VERSION 5.8 ;
BUSBITCHARS "[]" ;
DIVIDERCHAR "/" ;
UNITS
    DATABASE MICRONS 1000 ;
END UNITS

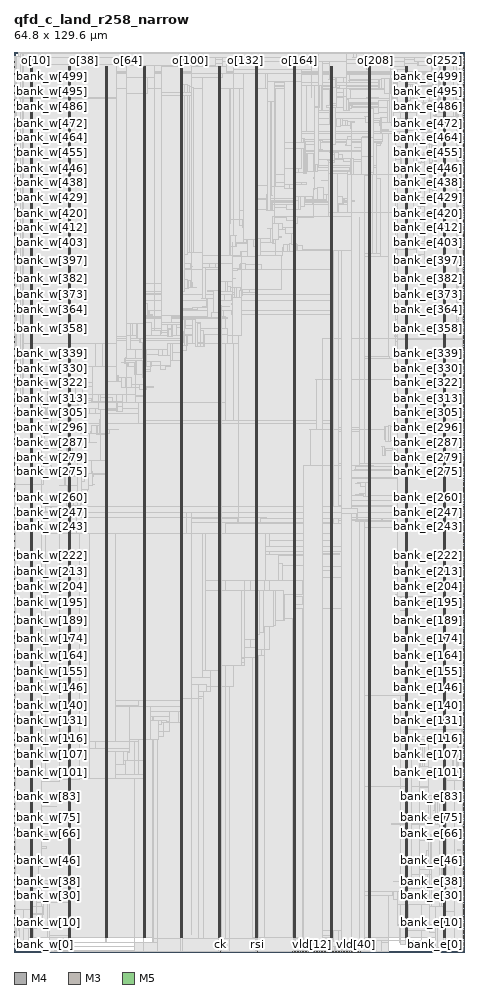
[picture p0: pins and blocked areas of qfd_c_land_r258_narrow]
MACRO qfd_c_land_r258_narrow
  FOREIGN qfd_c_land_r258_narrow 0 0 ;
  CLASS BLOCK ;
  SIZE 64.8 BY 129.6 ;
  PIN bank_e[0]
    DIRECTION INPUT ;
    USE SIGNAL ;
    PORT
      LAYER M4 ;
        RECT  64.716 0.672 64.8 0.696 ;
    END
  END bank_e[0]
  PIN bank_e[100]
    DIRECTION INPUT ;
    USE SIGNAL ;
    PORT
      LAYER M4 ;
        RECT  64.716 25.584 64.8 25.608 ;
    END
  END bank_e[100]
  PIN bank_e[101]
    DIRECTION INPUT ;
    USE SIGNAL ;
    PORT
      LAYER M4 ;
        RECT  64.716 25.824 64.8 25.848 ;
    END
  END bank_e[101]
  PIN bank_e[102]
    DIRECTION INPUT ;
    USE SIGNAL ;
    PORT
      LAYER M4 ;
        RECT  64.716 26.064 64.8 26.088 ;
    END
  END bank_e[102]
  PIN bank_e[103]
    DIRECTION INPUT ;
    USE SIGNAL ;
    PORT
      LAYER M4 ;
        RECT  64.716 26.304 64.8 26.328 ;
    END
  END bank_e[103]
  PIN bank_e[104]
    DIRECTION INPUT ;
    USE SIGNAL ;
    PORT
      LAYER M4 ;
        RECT  64.716 26.544 64.8 26.568 ;
    END
  END bank_e[104]
  PIN bank_e[105]
    DIRECTION INPUT ;
    USE SIGNAL ;
    PORT
      LAYER M4 ;
        RECT  64.716 26.784 64.8 26.808 ;
    END
  END bank_e[105]
  PIN bank_e[106]
    DIRECTION INPUT ;
    USE SIGNAL ;
    PORT
      LAYER M4 ;
        RECT  64.716 27.072 64.8 27.096 ;
    END
  END bank_e[106]
  PIN bank_e[107]
    DIRECTION INPUT ;
    USE SIGNAL ;
    PORT
      LAYER M4 ;
        RECT  64.716 27.312 64.8 27.336 ;
    END
  END bank_e[107]
  PIN bank_e[108]
    DIRECTION INPUT ;
    USE SIGNAL ;
    PORT
      LAYER M4 ;
        RECT  64.716 27.552 64.8 27.576 ;
    END
  END bank_e[108]
  PIN bank_e[109]
    DIRECTION INPUT ;
    USE SIGNAL ;
    PORT
      LAYER M4 ;
        RECT  64.716 27.792 64.8 27.816 ;
    END
  END bank_e[109]
  PIN bank_e[10]
    DIRECTION INPUT ;
    USE SIGNAL ;
    PORT
      LAYER M4 ;
        RECT  64.716 3.12 64.8 3.144 ;
    END
  END bank_e[10]
  PIN bank_e[110]
    DIRECTION INPUT ;
    USE SIGNAL ;
    PORT
      LAYER M4 ;
        RECT  64.716 28.032 64.8 28.056 ;
    END
  END bank_e[110]
  PIN bank_e[111]
    DIRECTION INPUT ;
    USE SIGNAL ;
    PORT
      LAYER M4 ;
        RECT  64.716 28.32 64.8 28.344 ;
    END
  END bank_e[111]
  PIN bank_e[112]
    DIRECTION INPUT ;
    USE SIGNAL ;
    PORT
      LAYER M4 ;
        RECT  64.716 28.56 64.8 28.584 ;
    END
  END bank_e[112]
  PIN bank_e[113]
    DIRECTION INPUT ;
    USE SIGNAL ;
    PORT
      LAYER M4 ;
        RECT  64.716 28.8 64.8 28.824 ;
    END
  END bank_e[113]
  PIN bank_e[114]
    DIRECTION INPUT ;
    USE SIGNAL ;
    PORT
      LAYER M4 ;
        RECT  64.716 29.04 64.8 29.064 ;
    END
  END bank_e[114]
  PIN bank_e[115]
    DIRECTION INPUT ;
    USE SIGNAL ;
    PORT
      LAYER M4 ;
        RECT  64.716 29.28 64.8 29.304 ;
    END
  END bank_e[115]
  PIN bank_e[116]
    DIRECTION INPUT ;
    USE SIGNAL ;
    PORT
      LAYER M4 ;
        RECT  64.716 29.568 64.8 29.592 ;
    END
  END bank_e[116]
  PIN bank_e[117]
    DIRECTION INPUT ;
    USE SIGNAL ;
    PORT
      LAYER M4 ;
        RECT  64.716 29.808 64.8 29.832 ;
    END
  END bank_e[117]
  PIN bank_e[118]
    DIRECTION INPUT ;
    USE SIGNAL ;
    PORT
      LAYER M4 ;
        RECT  64.716 30.048 64.8 30.072 ;
    END
  END bank_e[118]
  PIN bank_e[119]
    DIRECTION INPUT ;
    USE SIGNAL ;
    PORT
      LAYER M4 ;
        RECT  64.716 30.288 64.8 30.312 ;
    END
  END bank_e[119]
  PIN bank_e[11]
    DIRECTION INPUT ;
    USE SIGNAL ;
    PORT
      LAYER M4 ;
        RECT  64.716 3.408 64.8 3.432 ;
    END
  END bank_e[11]
  PIN bank_e[120]
    DIRECTION INPUT ;
    USE SIGNAL ;
    PORT
      LAYER M4 ;
        RECT  64.716 30.528 64.8 30.552 ;
    END
  END bank_e[120]
  PIN bank_e[121]
    DIRECTION INPUT ;
    USE SIGNAL ;
    PORT
      LAYER M4 ;
        RECT  64.716 30.768 64.8 30.792 ;
    END
  END bank_e[121]
  PIN bank_e[122]
    DIRECTION INPUT ;
    USE SIGNAL ;
    PORT
      LAYER M4 ;
        RECT  64.716 31.056 64.8 31.08 ;
    END
  END bank_e[122]
  PIN bank_e[123]
    DIRECTION INPUT ;
    USE SIGNAL ;
    PORT
      LAYER M4 ;
        RECT  64.716 31.296 64.8 31.32 ;
    END
  END bank_e[123]
  PIN bank_e[124]
    DIRECTION INPUT ;
    USE SIGNAL ;
    PORT
      LAYER M4 ;
        RECT  64.716 31.536 64.8 31.56 ;
    END
  END bank_e[124]
  PIN bank_e[125]
    DIRECTION INPUT ;
    USE SIGNAL ;
    PORT
      LAYER M4 ;
        RECT  64.716 31.776 64.8 31.8 ;
    END
  END bank_e[125]
  PIN bank_e[126]
    DIRECTION INPUT ;
    USE SIGNAL ;
    PORT
      LAYER M4 ;
        RECT  64.716 32.016 64.8 32.04 ;
    END
  END bank_e[126]
  PIN bank_e[127]
    DIRECTION INPUT ;
    USE SIGNAL ;
    PORT
      LAYER M4 ;
        RECT  64.716 32.304 64.8 32.328 ;
    END
  END bank_e[127]
  PIN bank_e[128]
    DIRECTION INPUT ;
    USE SIGNAL ;
    PORT
      LAYER M4 ;
        RECT  64.716 32.544 64.8 32.568 ;
    END
  END bank_e[128]
  PIN bank_e[129]
    DIRECTION INPUT ;
    USE SIGNAL ;
    PORT
      LAYER M4 ;
        RECT  64.716 32.784 64.8 32.808 ;
    END
  END bank_e[129]
  PIN bank_e[12]
    DIRECTION INPUT ;
    USE SIGNAL ;
    PORT
      LAYER M4 ;
        RECT  64.716 3.648 64.8 3.672 ;
    END
  END bank_e[12]
  PIN bank_e[130]
    DIRECTION INPUT ;
    USE SIGNAL ;
    PORT
      LAYER M4 ;
        RECT  64.716 33.024 64.8 33.048 ;
    END
  END bank_e[130]
  PIN bank_e[131]
    DIRECTION INPUT ;
    USE SIGNAL ;
    PORT
      LAYER M4 ;
        RECT  64.716 33.264 64.8 33.288 ;
    END
  END bank_e[131]
  PIN bank_e[132]
    DIRECTION INPUT ;
    USE SIGNAL ;
    PORT
      LAYER M4 ;
        RECT  64.716 33.552 64.8 33.576 ;
    END
  END bank_e[132]
  PIN bank_e[133]
    DIRECTION INPUT ;
    USE SIGNAL ;
    PORT
      LAYER M4 ;
        RECT  64.716 33.792 64.8 33.816 ;
    END
  END bank_e[133]
  PIN bank_e[134]
    DIRECTION INPUT ;
    USE SIGNAL ;
    PORT
      LAYER M4 ;
        RECT  64.716 34.032 64.8 34.056 ;
    END
  END bank_e[134]
  PIN bank_e[135]
    DIRECTION INPUT ;
    USE SIGNAL ;
    PORT
      LAYER M4 ;
        RECT  64.716 34.272 64.8 34.296 ;
    END
  END bank_e[135]
  PIN bank_e[136]
    DIRECTION INPUT ;
    USE SIGNAL ;
    PORT
      LAYER M4 ;
        RECT  64.716 34.512 64.8 34.536 ;
    END
  END bank_e[136]
  PIN bank_e[137]
    DIRECTION INPUT ;
    USE SIGNAL ;
    PORT
      LAYER M4 ;
        RECT  64.716 34.752 64.8 34.776 ;
    END
  END bank_e[137]
  PIN bank_e[138]
    DIRECTION INPUT ;
    USE SIGNAL ;
    PORT
      LAYER M4 ;
        RECT  64.716 35.04 64.8 35.064 ;
    END
  END bank_e[138]
  PIN bank_e[139]
    DIRECTION INPUT ;
    USE SIGNAL ;
    PORT
      LAYER M4 ;
        RECT  64.716 35.28 64.8 35.304 ;
    END
  END bank_e[139]
  PIN bank_e[13]
    DIRECTION INPUT ;
    USE SIGNAL ;
    PORT
      LAYER M4 ;
        RECT  64.716 3.888 64.8 3.912 ;
    END
  END bank_e[13]
  PIN bank_e[140]
    DIRECTION INPUT ;
    USE SIGNAL ;
    PORT
      LAYER M4 ;
        RECT  64.716 35.52 64.8 35.544 ;
    END
  END bank_e[140]
  PIN bank_e[141]
    DIRECTION INPUT ;
    USE SIGNAL ;
    PORT
      LAYER M4 ;
        RECT  64.716 35.76 64.8 35.784 ;
    END
  END bank_e[141]
  PIN bank_e[142]
    DIRECTION INPUT ;
    USE SIGNAL ;
    PORT
      LAYER M4 ;
        RECT  64.716 36 64.8 36.024 ;
    END
  END bank_e[142]
  PIN bank_e[143]
    DIRECTION INPUT ;
    USE SIGNAL ;
    PORT
      LAYER M4 ;
        RECT  64.716 36.288 64.8 36.312 ;
    END
  END bank_e[143]
  PIN bank_e[144]
    DIRECTION INPUT ;
    USE SIGNAL ;
    PORT
      LAYER M4 ;
        RECT  64.716 36.528 64.8 36.552 ;
    END
  END bank_e[144]
  PIN bank_e[145]
    DIRECTION INPUT ;
    USE SIGNAL ;
    PORT
      LAYER M4 ;
        RECT  64.716 36.768 64.8 36.792 ;
    END
  END bank_e[145]
  PIN bank_e[146]
    DIRECTION INPUT ;
    USE SIGNAL ;
    PORT
      LAYER M4 ;
        RECT  64.716 37.008 64.8 37.032 ;
    END
  END bank_e[146]
  PIN bank_e[147]
    DIRECTION INPUT ;
    USE SIGNAL ;
    PORT
      LAYER M4 ;
        RECT  64.716 37.248 64.8 37.272 ;
    END
  END bank_e[147]
  PIN bank_e[148]
    DIRECTION INPUT ;
    USE SIGNAL ;
    PORT
      LAYER M4 ;
        RECT  64.716 37.536 64.8 37.56 ;
    END
  END bank_e[148]
  PIN bank_e[149]
    DIRECTION INPUT ;
    USE SIGNAL ;
    PORT
      LAYER M4 ;
        RECT  64.716 37.776 64.8 37.8 ;
    END
  END bank_e[149]
  PIN bank_e[14]
    DIRECTION INPUT ;
    USE SIGNAL ;
    PORT
      LAYER M4 ;
        RECT  64.716 4.128 64.8 4.152 ;
    END
  END bank_e[14]
  PIN bank_e[150]
    DIRECTION INPUT ;
    USE SIGNAL ;
    PORT
      LAYER M4 ;
        RECT  64.716 38.016 64.8 38.04 ;
    END
  END bank_e[150]
  PIN bank_e[151]
    DIRECTION INPUT ;
    USE SIGNAL ;
    PORT
      LAYER M4 ;
        RECT  64.716 38.256 64.8 38.28 ;
    END
  END bank_e[151]
  PIN bank_e[152]
    DIRECTION INPUT ;
    USE SIGNAL ;
    PORT
      LAYER M4 ;
        RECT  64.716 38.496 64.8 38.52 ;
    END
  END bank_e[152]
  PIN bank_e[153]
    DIRECTION INPUT ;
    USE SIGNAL ;
    PORT
      LAYER M4 ;
        RECT  64.716 38.784 64.8 38.808 ;
    END
  END bank_e[153]
  PIN bank_e[154]
    DIRECTION INPUT ;
    USE SIGNAL ;
    PORT
      LAYER M4 ;
        RECT  64.716 39.024 64.8 39.048 ;
    END
  END bank_e[154]
  PIN bank_e[155]
    DIRECTION INPUT ;
    USE SIGNAL ;
    PORT
      LAYER M4 ;
        RECT  64.716 39.264 64.8 39.288 ;
    END
  END bank_e[155]
  PIN bank_e[156]
    DIRECTION INPUT ;
    USE SIGNAL ;
    PORT
      LAYER M4 ;
        RECT  64.716 39.504 64.8 39.528 ;
    END
  END bank_e[156]
  PIN bank_e[157]
    DIRECTION INPUT ;
    USE SIGNAL ;
    PORT
      LAYER M4 ;
        RECT  64.716 39.744 64.8 39.768 ;
    END
  END bank_e[157]
  PIN bank_e[158]
    DIRECTION INPUT ;
    USE SIGNAL ;
    PORT
      LAYER M4 ;
        RECT  64.716 39.984 64.8 40.008 ;
    END
  END bank_e[158]
  PIN bank_e[159]
    DIRECTION INPUT ;
    USE SIGNAL ;
    PORT
      LAYER M4 ;
        RECT  64.716 40.272 64.8 40.296 ;
    END
  END bank_e[159]
  PIN bank_e[15]
    DIRECTION INPUT ;
    USE SIGNAL ;
    PORT
      LAYER M4 ;
        RECT  64.716 4.368 64.8 4.392 ;
    END
  END bank_e[15]
  PIN bank_e[160]
    DIRECTION INPUT ;
    USE SIGNAL ;
    PORT
      LAYER M4 ;
        RECT  64.716 40.512 64.8 40.536 ;
    END
  END bank_e[160]
  PIN bank_e[161]
    DIRECTION INPUT ;
    USE SIGNAL ;
    PORT
      LAYER M4 ;
        RECT  64.716 40.752 64.8 40.776 ;
    END
  END bank_e[161]
  PIN bank_e[162]
    DIRECTION INPUT ;
    USE SIGNAL ;
    PORT
      LAYER M4 ;
        RECT  64.716 40.992 64.8 41.016 ;
    END
  END bank_e[162]
  PIN bank_e[163]
    DIRECTION INPUT ;
    USE SIGNAL ;
    PORT
      LAYER M4 ;
        RECT  64.716 41.232 64.8 41.256 ;
    END
  END bank_e[163]
  PIN bank_e[164]
    DIRECTION INPUT ;
    USE SIGNAL ;
    PORT
      LAYER M4 ;
        RECT  64.716 41.52 64.8 41.544 ;
    END
  END bank_e[164]
  PIN bank_e[165]
    DIRECTION INPUT ;
    USE SIGNAL ;
    PORT
      LAYER M4 ;
        RECT  64.716 41.76 64.8 41.784 ;
    END
  END bank_e[165]
  PIN bank_e[166]
    DIRECTION INPUT ;
    USE SIGNAL ;
    PORT
      LAYER M4 ;
        RECT  64.716 42 64.8 42.024 ;
    END
  END bank_e[166]
  PIN bank_e[167]
    DIRECTION INPUT ;
    USE SIGNAL ;
    PORT
      LAYER M4 ;
        RECT  64.716 42.24 64.8 42.264 ;
    END
  END bank_e[167]
  PIN bank_e[168]
    DIRECTION INPUT ;
    USE SIGNAL ;
    PORT
      LAYER M4 ;
        RECT  64.716 42.48 64.8 42.504 ;
    END
  END bank_e[168]
  PIN bank_e[169]
    DIRECTION INPUT ;
    USE SIGNAL ;
    PORT
      LAYER M4 ;
        RECT  64.716 42.768 64.8 42.792 ;
    END
  END bank_e[169]
  PIN bank_e[16]
    DIRECTION INPUT ;
    USE SIGNAL ;
    PORT
      LAYER M4 ;
        RECT  64.716 4.656 64.8 4.68 ;
    END
  END bank_e[16]
  PIN bank_e[170]
    DIRECTION INPUT ;
    USE SIGNAL ;
    PORT
      LAYER M4 ;
        RECT  64.716 43.008 64.8 43.032 ;
    END
  END bank_e[170]
  PIN bank_e[171]
    DIRECTION INPUT ;
    USE SIGNAL ;
    PORT
      LAYER M4 ;
        RECT  64.716 43.248 64.8 43.272 ;
    END
  END bank_e[171]
  PIN bank_e[172]
    DIRECTION INPUT ;
    USE SIGNAL ;
    PORT
      LAYER M4 ;
        RECT  64.716 43.488 64.8 43.512 ;
    END
  END bank_e[172]
  PIN bank_e[173]
    DIRECTION INPUT ;
    USE SIGNAL ;
    PORT
      LAYER M4 ;
        RECT  64.716 43.728 64.8 43.752 ;
    END
  END bank_e[173]
  PIN bank_e[174]
    DIRECTION INPUT ;
    USE SIGNAL ;
    PORT
      LAYER M4 ;
        RECT  64.716 43.968 64.8 43.992 ;
    END
  END bank_e[174]
  PIN bank_e[175]
    DIRECTION INPUT ;
    USE SIGNAL ;
    PORT
      LAYER M4 ;
        RECT  64.716 44.256 64.8 44.28 ;
    END
  END bank_e[175]
  PIN bank_e[176]
    DIRECTION INPUT ;
    USE SIGNAL ;
    PORT
      LAYER M4 ;
        RECT  64.716 44.496 64.8 44.52 ;
    END
  END bank_e[176]
  PIN bank_e[177]
    DIRECTION INPUT ;
    USE SIGNAL ;
    PORT
      LAYER M4 ;
        RECT  64.716 44.736 64.8 44.76 ;
    END
  END bank_e[177]
  PIN bank_e[178]
    DIRECTION INPUT ;
    USE SIGNAL ;
    PORT
      LAYER M4 ;
        RECT  64.716 44.976 64.8 45 ;
    END
  END bank_e[178]
  PIN bank_e[179]
    DIRECTION INPUT ;
    USE SIGNAL ;
    PORT
      LAYER M4 ;
        RECT  64.716 45.216 64.8 45.24 ;
    END
  END bank_e[179]
  PIN bank_e[17]
    DIRECTION INPUT ;
    USE SIGNAL ;
    PORT
      LAYER M4 ;
        RECT  64.716 4.896 64.8 4.92 ;
    END
  END bank_e[17]
  PIN bank_e[180]
    DIRECTION INPUT ;
    USE SIGNAL ;
    PORT
      LAYER M4 ;
        RECT  64.716 45.504 64.8 45.528 ;
    END
  END bank_e[180]
  PIN bank_e[181]
    DIRECTION INPUT ;
    USE SIGNAL ;
    PORT
      LAYER M4 ;
        RECT  64.716 45.744 64.8 45.768 ;
    END
  END bank_e[181]
  PIN bank_e[182]
    DIRECTION INPUT ;
    USE SIGNAL ;
    PORT
      LAYER M4 ;
        RECT  64.716 45.984 64.8 46.008 ;
    END
  END bank_e[182]
  PIN bank_e[183]
    DIRECTION INPUT ;
    USE SIGNAL ;
    PORT
      LAYER M4 ;
        RECT  64.716 46.224 64.8 46.248 ;
    END
  END bank_e[183]
  PIN bank_e[184]
    DIRECTION INPUT ;
    USE SIGNAL ;
    PORT
      LAYER M4 ;
        RECT  64.716 46.464 64.8 46.488 ;
    END
  END bank_e[184]
  PIN bank_e[185]
    DIRECTION INPUT ;
    USE SIGNAL ;
    PORT
      LAYER M4 ;
        RECT  64.716 46.752 64.8 46.776 ;
    END
  END bank_e[185]
  PIN bank_e[186]
    DIRECTION INPUT ;
    USE SIGNAL ;
    PORT
      LAYER M4 ;
        RECT  64.716 46.992 64.8 47.016 ;
    END
  END bank_e[186]
  PIN bank_e[187]
    DIRECTION INPUT ;
    USE SIGNAL ;
    PORT
      LAYER M4 ;
        RECT  64.716 47.232 64.8 47.256 ;
    END
  END bank_e[187]
  PIN bank_e[188]
    DIRECTION INPUT ;
    USE SIGNAL ;
    PORT
      LAYER M4 ;
        RECT  64.716 47.472 64.8 47.496 ;
    END
  END bank_e[188]
  PIN bank_e[189]
    DIRECTION INPUT ;
    USE SIGNAL ;
    PORT
      LAYER M4 ;
        RECT  64.716 47.712 64.8 47.736 ;
    END
  END bank_e[189]
  PIN bank_e[18]
    DIRECTION INPUT ;
    USE SIGNAL ;
    PORT
      LAYER M4 ;
        RECT  64.716 5.136 64.8 5.16 ;
    END
  END bank_e[18]
  PIN bank_e[190]
    DIRECTION INPUT ;
    USE SIGNAL ;
    PORT
      LAYER M4 ;
        RECT  64.716 48 64.8 48.024 ;
    END
  END bank_e[190]
  PIN bank_e[191]
    DIRECTION INPUT ;
    USE SIGNAL ;
    PORT
      LAYER M4 ;
        RECT  64.716 48.24 64.8 48.264 ;
    END
  END bank_e[191]
  PIN bank_e[192]
    DIRECTION INPUT ;
    USE SIGNAL ;
    PORT
      LAYER M4 ;
        RECT  64.716 48.48 64.8 48.504 ;
    END
  END bank_e[192]
  PIN bank_e[193]
    DIRECTION INPUT ;
    USE SIGNAL ;
    PORT
      LAYER M4 ;
        RECT  64.716 48.72 64.8 48.744 ;
    END
  END bank_e[193]
  PIN bank_e[194]
    DIRECTION INPUT ;
    USE SIGNAL ;
    PORT
      LAYER M4 ;
        RECT  64.716 48.96 64.8 48.984 ;
    END
  END bank_e[194]
  PIN bank_e[195]
    DIRECTION INPUT ;
    USE SIGNAL ;
    PORT
      LAYER M4 ;
        RECT  64.716 49.2 64.8 49.224 ;
    END
  END bank_e[195]
  PIN bank_e[196]
    DIRECTION INPUT ;
    USE SIGNAL ;
    PORT
      LAYER M4 ;
        RECT  64.716 49.488 64.8 49.512 ;
    END
  END bank_e[196]
  PIN bank_e[197]
    DIRECTION INPUT ;
    USE SIGNAL ;
    PORT
      LAYER M4 ;
        RECT  64.716 49.728 64.8 49.752 ;
    END
  END bank_e[197]
  PIN bank_e[198]
    DIRECTION INPUT ;
    USE SIGNAL ;
    PORT
      LAYER M4 ;
        RECT  64.716 49.968 64.8 49.992 ;
    END
  END bank_e[198]
  PIN bank_e[199]
    DIRECTION INPUT ;
    USE SIGNAL ;
    PORT
      LAYER M4 ;
        RECT  64.716 50.208 64.8 50.232 ;
    END
  END bank_e[199]
  PIN bank_e[19]
    DIRECTION INPUT ;
    USE SIGNAL ;
    PORT
      LAYER M4 ;
        RECT  64.716 5.376 64.8 5.4 ;
    END
  END bank_e[19]
  PIN bank_e[1]
    DIRECTION INPUT ;
    USE SIGNAL ;
    PORT
      LAYER M4 ;
        RECT  64.716 0.912 64.8 0.936 ;
    END
  END bank_e[1]
  PIN bank_e[200]
    DIRECTION INPUT ;
    USE SIGNAL ;
    PORT
      LAYER M4 ;
        RECT  64.716 50.448 64.8 50.472 ;
    END
  END bank_e[200]
  PIN bank_e[201]
    DIRECTION INPUT ;
    USE SIGNAL ;
    PORT
      LAYER M4 ;
        RECT  64.716 50.736 64.8 50.76 ;
    END
  END bank_e[201]
  PIN bank_e[202]
    DIRECTION INPUT ;
    USE SIGNAL ;
    PORT
      LAYER M4 ;
        RECT  64.716 50.976 64.8 51 ;
    END
  END bank_e[202]
  PIN bank_e[203]
    DIRECTION INPUT ;
    USE SIGNAL ;
    PORT
      LAYER M4 ;
        RECT  64.716 51.216 64.8 51.24 ;
    END
  END bank_e[203]
  PIN bank_e[204]
    DIRECTION INPUT ;
    USE SIGNAL ;
    PORT
      LAYER M4 ;
        RECT  64.716 51.456 64.8 51.48 ;
    END
  END bank_e[204]
  PIN bank_e[205]
    DIRECTION INPUT ;
    USE SIGNAL ;
    PORT
      LAYER M4 ;
        RECT  64.716 51.696 64.8 51.72 ;
    END
  END bank_e[205]
  PIN bank_e[206]
    DIRECTION INPUT ;
    USE SIGNAL ;
    PORT
      LAYER M4 ;
        RECT  64.716 51.984 64.8 52.008 ;
    END
  END bank_e[206]
  PIN bank_e[207]
    DIRECTION INPUT ;
    USE SIGNAL ;
    PORT
      LAYER M4 ;
        RECT  64.716 52.224 64.8 52.248 ;
    END
  END bank_e[207]
  PIN bank_e[208]
    DIRECTION INPUT ;
    USE SIGNAL ;
    PORT
      LAYER M4 ;
        RECT  64.716 52.464 64.8 52.488 ;
    END
  END bank_e[208]
  PIN bank_e[209]
    DIRECTION INPUT ;
    USE SIGNAL ;
    PORT
      LAYER M4 ;
        RECT  64.716 52.704 64.8 52.728 ;
    END
  END bank_e[209]
  PIN bank_e[20]
    DIRECTION INPUT ;
    USE SIGNAL ;
    PORT
      LAYER M4 ;
        RECT  64.716 5.616 64.8 5.64 ;
    END
  END bank_e[20]
  PIN bank_e[210]
    DIRECTION INPUT ;
    USE SIGNAL ;
    PORT
      LAYER M4 ;
        RECT  64.716 52.944 64.8 52.968 ;
    END
  END bank_e[210]
  PIN bank_e[211]
    DIRECTION INPUT ;
    USE SIGNAL ;
    PORT
      LAYER M4 ;
        RECT  64.716 53.184 64.8 53.208 ;
    END
  END bank_e[211]
  PIN bank_e[212]
    DIRECTION INPUT ;
    USE SIGNAL ;
    PORT
      LAYER M4 ;
        RECT  64.716 53.472 64.8 53.496 ;
    END
  END bank_e[212]
  PIN bank_e[213]
    DIRECTION INPUT ;
    USE SIGNAL ;
    PORT
      LAYER M4 ;
        RECT  64.716 53.712 64.8 53.736 ;
    END
  END bank_e[213]
  PIN bank_e[214]
    DIRECTION INPUT ;
    USE SIGNAL ;
    PORT
      LAYER M4 ;
        RECT  64.716 53.952 64.8 53.976 ;
    END
  END bank_e[214]
  PIN bank_e[215]
    DIRECTION INPUT ;
    USE SIGNAL ;
    PORT
      LAYER M4 ;
        RECT  64.716 54.192 64.8 54.216 ;
    END
  END bank_e[215]
  PIN bank_e[216]
    DIRECTION INPUT ;
    USE SIGNAL ;
    PORT
      LAYER M4 ;
        RECT  64.716 54.432 64.8 54.456 ;
    END
  END bank_e[216]
  PIN bank_e[217]
    DIRECTION INPUT ;
    USE SIGNAL ;
    PORT
      LAYER M4 ;
        RECT  64.716 54.72 64.8 54.744 ;
    END
  END bank_e[217]
  PIN bank_e[218]
    DIRECTION INPUT ;
    USE SIGNAL ;
    PORT
      LAYER M4 ;
        RECT  64.716 54.96 64.8 54.984 ;
    END
  END bank_e[218]
  PIN bank_e[219]
    DIRECTION INPUT ;
    USE SIGNAL ;
    PORT
      LAYER M4 ;
        RECT  64.716 55.2 64.8 55.224 ;
    END
  END bank_e[219]
  PIN bank_e[21]
    DIRECTION INPUT ;
    USE SIGNAL ;
    PORT
      LAYER M4 ;
        RECT  64.716 5.904 64.8 5.928 ;
    END
  END bank_e[21]
  PIN bank_e[220]
    DIRECTION INPUT ;
    USE SIGNAL ;
    PORT
      LAYER M4 ;
        RECT  64.716 55.44 64.8 55.464 ;
    END
  END bank_e[220]
  PIN bank_e[221]
    DIRECTION INPUT ;
    USE SIGNAL ;
    PORT
      LAYER M4 ;
        RECT  64.716 55.68 64.8 55.704 ;
    END
  END bank_e[221]
  PIN bank_e[222]
    DIRECTION INPUT ;
    USE SIGNAL ;
    PORT
      LAYER M4 ;
        RECT  64.716 55.968 64.8 55.992 ;
    END
  END bank_e[222]
  PIN bank_e[223]
    DIRECTION INPUT ;
    USE SIGNAL ;
    PORT
      LAYER M4 ;
        RECT  64.716 56.208 64.8 56.232 ;
    END
  END bank_e[223]
  PIN bank_e[224]
    DIRECTION INPUT ;
    USE SIGNAL ;
    PORT
      LAYER M4 ;
        RECT  64.716 56.448 64.8 56.472 ;
    END
  END bank_e[224]
  PIN bank_e[225]
    DIRECTION INPUT ;
    USE SIGNAL ;
    PORT
      LAYER M4 ;
        RECT  64.716 56.688 64.8 56.712 ;
    END
  END bank_e[225]
  PIN bank_e[226]
    DIRECTION INPUT ;
    USE SIGNAL ;
    PORT
      LAYER M4 ;
        RECT  64.716 56.928 64.8 56.952 ;
    END
  END bank_e[226]
  PIN bank_e[227]
    DIRECTION INPUT ;
    USE SIGNAL ;
    PORT
      LAYER M4 ;
        RECT  64.716 57.168 64.8 57.192 ;
    END
  END bank_e[227]
  PIN bank_e[228]
    DIRECTION INPUT ;
    USE SIGNAL ;
    PORT
      LAYER M4 ;
        RECT  64.716 57.456 64.8 57.48 ;
    END
  END bank_e[228]
  PIN bank_e[229]
    DIRECTION INPUT ;
    USE SIGNAL ;
    PORT
      LAYER M4 ;
        RECT  64.716 57.696 64.8 57.72 ;
    END
  END bank_e[229]
  PIN bank_e[22]
    DIRECTION INPUT ;
    USE SIGNAL ;
    PORT
      LAYER M4 ;
        RECT  64.716 6.144 64.8 6.168 ;
    END
  END bank_e[22]
  PIN bank_e[230]
    DIRECTION INPUT ;
    USE SIGNAL ;
    PORT
      LAYER M4 ;
        RECT  64.716 57.936 64.8 57.96 ;
    END
  END bank_e[230]
  PIN bank_e[231]
    DIRECTION INPUT ;
    USE SIGNAL ;
    PORT
      LAYER M4 ;
        RECT  64.716 58.176 64.8 58.2 ;
    END
  END bank_e[231]
  PIN bank_e[232]
    DIRECTION INPUT ;
    USE SIGNAL ;
    PORT
      LAYER M4 ;
        RECT  64.716 58.416 64.8 58.44 ;
    END
  END bank_e[232]
  PIN bank_e[233]
    DIRECTION INPUT ;
    USE SIGNAL ;
    PORT
      LAYER M4 ;
        RECT  64.716 58.704 64.8 58.728 ;
    END
  END bank_e[233]
  PIN bank_e[234]
    DIRECTION INPUT ;
    USE SIGNAL ;
    PORT
      LAYER M4 ;
        RECT  64.716 58.944 64.8 58.968 ;
    END
  END bank_e[234]
  PIN bank_e[235]
    DIRECTION INPUT ;
    USE SIGNAL ;
    PORT
      LAYER M4 ;
        RECT  64.716 59.184 64.8 59.208 ;
    END
  END bank_e[235]
  PIN bank_e[236]
    DIRECTION INPUT ;
    USE SIGNAL ;
    PORT
      LAYER M4 ;
        RECT  64.716 59.424 64.8 59.448 ;
    END
  END bank_e[236]
  PIN bank_e[237]
    DIRECTION INPUT ;
    USE SIGNAL ;
    PORT
      LAYER M4 ;
        RECT  64.716 59.664 64.8 59.688 ;
    END
  END bank_e[237]
  PIN bank_e[238]
    DIRECTION INPUT ;
    USE SIGNAL ;
    PORT
      LAYER M4 ;
        RECT  64.716 59.952 64.8 59.976 ;
    END
  END bank_e[238]
  PIN bank_e[239]
    DIRECTION INPUT ;
    USE SIGNAL ;
    PORT
      LAYER M4 ;
        RECT  64.716 60.192 64.8 60.216 ;
    END
  END bank_e[239]
  PIN bank_e[23]
    DIRECTION INPUT ;
    USE SIGNAL ;
    PORT
      LAYER M4 ;
        RECT  64.716 6.384 64.8 6.408 ;
    END
  END bank_e[23]
  PIN bank_e[240]
    DIRECTION INPUT ;
    USE SIGNAL ;
    PORT
      LAYER M4 ;
        RECT  64.716 60.432 64.8 60.456 ;
    END
  END bank_e[240]
  PIN bank_e[241]
    DIRECTION INPUT ;
    USE SIGNAL ;
    PORT
      LAYER M4 ;
        RECT  64.716 60.672 64.8 60.696 ;
    END
  END bank_e[241]
  PIN bank_e[242]
    DIRECTION INPUT ;
    USE SIGNAL ;
    PORT
      LAYER M4 ;
        RECT  64.716 60.912 64.8 60.936 ;
    END
  END bank_e[242]
  PIN bank_e[243]
    DIRECTION INPUT ;
    USE SIGNAL ;
    PORT
      LAYER M4 ;
        RECT  64.716 61.2 64.8 61.224 ;
    END
  END bank_e[243]
  PIN bank_e[244]
    DIRECTION INPUT ;
    USE SIGNAL ;
    PORT
      LAYER M4 ;
        RECT  64.716 61.44 64.8 61.464 ;
    END
  END bank_e[244]
  PIN bank_e[245]
    DIRECTION INPUT ;
    USE SIGNAL ;
    PORT
      LAYER M4 ;
        RECT  64.716 61.68 64.8 61.704 ;
    END
  END bank_e[245]
  PIN bank_e[246]
    DIRECTION INPUT ;
    USE SIGNAL ;
    PORT
      LAYER M4 ;
        RECT  64.716 61.92 64.8 61.944 ;
    END
  END bank_e[246]
  PIN bank_e[247]
    DIRECTION INPUT ;
    USE SIGNAL ;
    PORT
      LAYER M4 ;
        RECT  64.716 62.16 64.8 62.184 ;
    END
  END bank_e[247]
  PIN bank_e[248]
    DIRECTION INPUT ;
    USE SIGNAL ;
    PORT
      LAYER M4 ;
        RECT  64.716 62.4 64.8 62.424 ;
    END
  END bank_e[248]
  PIN bank_e[249]
    DIRECTION INPUT ;
    USE SIGNAL ;
    PORT
      LAYER M4 ;
        RECT  64.716 62.688 64.8 62.712 ;
    END
  END bank_e[249]
  PIN bank_e[24]
    DIRECTION INPUT ;
    USE SIGNAL ;
    PORT
      LAYER M4 ;
        RECT  64.716 6.624 64.8 6.648 ;
    END
  END bank_e[24]
  PIN bank_e[250]
    DIRECTION INPUT ;
    USE SIGNAL ;
    PORT
      LAYER M4 ;
        RECT  64.716 62.928 64.8 62.952 ;
    END
  END bank_e[250]
  PIN bank_e[251]
    DIRECTION INPUT ;
    USE SIGNAL ;
    PORT
      LAYER M4 ;
        RECT  64.716 63.168 64.8 63.192 ;
    END
  END bank_e[251]
  PIN bank_e[252]
    DIRECTION INPUT ;
    USE SIGNAL ;
    PORT
      LAYER M4 ;
        RECT  64.716 63.408 64.8 63.432 ;
    END
  END bank_e[252]
  PIN bank_e[253]
    DIRECTION INPUT ;
    USE SIGNAL ;
    PORT
      LAYER M4 ;
        RECT  64.716 63.648 64.8 63.672 ;
    END
  END bank_e[253]
  PIN bank_e[254]
    DIRECTION INPUT ;
    USE SIGNAL ;
    PORT
      LAYER M4 ;
        RECT  64.716 63.936 64.8 63.96 ;
    END
  END bank_e[254]
  PIN bank_e[255]
    DIRECTION INPUT ;
    USE SIGNAL ;
    PORT
      LAYER M4 ;
        RECT  64.716 64.176 64.8 64.2 ;
    END
  END bank_e[255]
  PIN bank_e[256]
    DIRECTION INPUT ;
    USE SIGNAL ;
    PORT
      LAYER M4 ;
        RECT  64.716 64.416 64.8 64.44 ;
    END
  END bank_e[256]
  PIN bank_e[257]
    DIRECTION INPUT ;
    USE SIGNAL ;
    PORT
      LAYER M4 ;
        RECT  64.716 64.656 64.8 64.68 ;
    END
  END bank_e[257]
  PIN bank_e[258]
    DIRECTION INPUT ;
    USE SIGNAL ;
    PORT
      LAYER M4 ;
        RECT  64.716 64.896 64.8 64.92 ;
    END
  END bank_e[258]
  PIN bank_e[259]
    DIRECTION INPUT ;
    USE SIGNAL ;
    PORT
      LAYER M4 ;
        RECT  64.716 65.184 64.8 65.208 ;
    END
  END bank_e[259]
  PIN bank_e[25]
    DIRECTION INPUT ;
    USE SIGNAL ;
    PORT
      LAYER M4 ;
        RECT  64.716 6.864 64.8 6.888 ;
    END
  END bank_e[25]
  PIN bank_e[260]
    DIRECTION INPUT ;
    USE SIGNAL ;
    PORT
      LAYER M4 ;
        RECT  64.716 65.424 64.8 65.448 ;
    END
  END bank_e[260]
  PIN bank_e[261]
    DIRECTION INPUT ;
    USE SIGNAL ;
    PORT
      LAYER M4 ;
        RECT  64.716 65.664 64.8 65.688 ;
    END
  END bank_e[261]
  PIN bank_e[262]
    DIRECTION INPUT ;
    USE SIGNAL ;
    PORT
      LAYER M4 ;
        RECT  64.716 65.904 64.8 65.928 ;
    END
  END bank_e[262]
  PIN bank_e[263]
    DIRECTION INPUT ;
    USE SIGNAL ;
    PORT
      LAYER M4 ;
        RECT  64.716 66.144 64.8 66.168 ;
    END
  END bank_e[263]
  PIN bank_e[264]
    DIRECTION INPUT ;
    USE SIGNAL ;
    PORT
      LAYER M4 ;
        RECT  64.716 66.384 64.8 66.408 ;
    END
  END bank_e[264]
  PIN bank_e[265]
    DIRECTION INPUT ;
    USE SIGNAL ;
    PORT
      LAYER M4 ;
        RECT  64.716 66.672 64.8 66.696 ;
    END
  END bank_e[265]
  PIN bank_e[266]
    DIRECTION INPUT ;
    USE SIGNAL ;
    PORT
      LAYER M4 ;
        RECT  64.716 66.912 64.8 66.936 ;
    END
  END bank_e[266]
  PIN bank_e[267]
    DIRECTION INPUT ;
    USE SIGNAL ;
    PORT
      LAYER M4 ;
        RECT  64.716 67.152 64.8 67.176 ;
    END
  END bank_e[267]
  PIN bank_e[268]
    DIRECTION INPUT ;
    USE SIGNAL ;
    PORT
      LAYER M4 ;
        RECT  64.716 67.392 64.8 67.416 ;
    END
  END bank_e[268]
  PIN bank_e[269]
    DIRECTION INPUT ;
    USE SIGNAL ;
    PORT
      LAYER M4 ;
        RECT  64.716 67.632 64.8 67.656 ;
    END
  END bank_e[269]
  PIN bank_e[26]
    DIRECTION INPUT ;
    USE SIGNAL ;
    PORT
      LAYER M4 ;
        RECT  64.716 7.152 64.8 7.176 ;
    END
  END bank_e[26]
  PIN bank_e[270]
    DIRECTION INPUT ;
    USE SIGNAL ;
    PORT
      LAYER M4 ;
        RECT  64.716 67.92 64.8 67.944 ;
    END
  END bank_e[270]
  PIN bank_e[271]
    DIRECTION INPUT ;
    USE SIGNAL ;
    PORT
      LAYER M4 ;
        RECT  64.716 68.16 64.8 68.184 ;
    END
  END bank_e[271]
  PIN bank_e[272]
    DIRECTION INPUT ;
    USE SIGNAL ;
    PORT
      LAYER M4 ;
        RECT  64.716 68.4 64.8 68.424 ;
    END
  END bank_e[272]
  PIN bank_e[273]
    DIRECTION INPUT ;
    USE SIGNAL ;
    PORT
      LAYER M4 ;
        RECT  64.716 68.64 64.8 68.664 ;
    END
  END bank_e[273]
  PIN bank_e[274]
    DIRECTION INPUT ;
    USE SIGNAL ;
    PORT
      LAYER M4 ;
        RECT  64.716 68.88 64.8 68.904 ;
    END
  END bank_e[274]
  PIN bank_e[275]
    DIRECTION INPUT ;
    USE SIGNAL ;
    PORT
      LAYER M4 ;
        RECT  64.716 69.168 64.8 69.192 ;
    END
  END bank_e[275]
  PIN bank_e[276]
    DIRECTION INPUT ;
    USE SIGNAL ;
    PORT
      LAYER M4 ;
        RECT  64.716 69.408 64.8 69.432 ;
    END
  END bank_e[276]
  PIN bank_e[277]
    DIRECTION INPUT ;
    USE SIGNAL ;
    PORT
      LAYER M4 ;
        RECT  64.716 69.648 64.8 69.672 ;
    END
  END bank_e[277]
  PIN bank_e[278]
    DIRECTION INPUT ;
    USE SIGNAL ;
    PORT
      LAYER M4 ;
        RECT  64.716 69.888 64.8 69.912 ;
    END
  END bank_e[278]
  PIN bank_e[279]
    DIRECTION INPUT ;
    USE SIGNAL ;
    PORT
      LAYER M4 ;
        RECT  64.716 70.128 64.8 70.152 ;
    END
  END bank_e[279]
  PIN bank_e[27]
    DIRECTION INPUT ;
    USE SIGNAL ;
    PORT
      LAYER M4 ;
        RECT  64.716 7.392 64.8 7.416 ;
    END
  END bank_e[27]
  PIN bank_e[280]
    DIRECTION INPUT ;
    USE SIGNAL ;
    PORT
      LAYER M4 ;
        RECT  64.716 70.416 64.8 70.44 ;
    END
  END bank_e[280]
  PIN bank_e[281]
    DIRECTION INPUT ;
    USE SIGNAL ;
    PORT
      LAYER M4 ;
        RECT  64.716 70.656 64.8 70.68 ;
    END
  END bank_e[281]
  PIN bank_e[282]
    DIRECTION INPUT ;
    USE SIGNAL ;
    PORT
      LAYER M4 ;
        RECT  64.716 70.896 64.8 70.92 ;
    END
  END bank_e[282]
  PIN bank_e[283]
    DIRECTION INPUT ;
    USE SIGNAL ;
    PORT
      LAYER M4 ;
        RECT  64.716 71.136 64.8 71.16 ;
    END
  END bank_e[283]
  PIN bank_e[284]
    DIRECTION INPUT ;
    USE SIGNAL ;
    PORT
      LAYER M4 ;
        RECT  64.716 71.376 64.8 71.4 ;
    END
  END bank_e[284]
  PIN bank_e[285]
    DIRECTION INPUT ;
    USE SIGNAL ;
    PORT
      LAYER M4 ;
        RECT  64.716 71.616 64.8 71.64 ;
    END
  END bank_e[285]
  PIN bank_e[286]
    DIRECTION INPUT ;
    USE SIGNAL ;
    PORT
      LAYER M4 ;
        RECT  64.716 71.904 64.8 71.928 ;
    END
  END bank_e[286]
  PIN bank_e[287]
    DIRECTION INPUT ;
    USE SIGNAL ;
    PORT
      LAYER M4 ;
        RECT  64.716 72.144 64.8 72.168 ;
    END
  END bank_e[287]
  PIN bank_e[288]
    DIRECTION INPUT ;
    USE SIGNAL ;
    PORT
      LAYER M4 ;
        RECT  64.716 72.384 64.8 72.408 ;
    END
  END bank_e[288]
  PIN bank_e[289]
    DIRECTION INPUT ;
    USE SIGNAL ;
    PORT
      LAYER M4 ;
        RECT  64.716 72.624 64.8 72.648 ;
    END
  END bank_e[289]
  PIN bank_e[28]
    DIRECTION INPUT ;
    USE SIGNAL ;
    PORT
      LAYER M4 ;
        RECT  64.716 7.632 64.8 7.656 ;
    END
  END bank_e[28]
  PIN bank_e[290]
    DIRECTION INPUT ;
    USE SIGNAL ;
    PORT
      LAYER M4 ;
        RECT  64.716 72.864 64.8 72.888 ;
    END
  END bank_e[290]
  PIN bank_e[291]
    DIRECTION INPUT ;
    USE SIGNAL ;
    PORT
      LAYER M4 ;
        RECT  64.716 73.152 64.8 73.176 ;
    END
  END bank_e[291]
  PIN bank_e[292]
    DIRECTION INPUT ;
    USE SIGNAL ;
    PORT
      LAYER M4 ;
        RECT  64.716 73.392 64.8 73.416 ;
    END
  END bank_e[292]
  PIN bank_e[293]
    DIRECTION INPUT ;
    USE SIGNAL ;
    PORT
      LAYER M4 ;
        RECT  64.716 73.632 64.8 73.656 ;
    END
  END bank_e[293]
  PIN bank_e[294]
    DIRECTION INPUT ;
    USE SIGNAL ;
    PORT
      LAYER M4 ;
        RECT  64.716 73.872 64.8 73.896 ;
    END
  END bank_e[294]
  PIN bank_e[295]
    DIRECTION INPUT ;
    USE SIGNAL ;
    PORT
      LAYER M4 ;
        RECT  64.716 74.112 64.8 74.136 ;
    END
  END bank_e[295]
  PIN bank_e[296]
    DIRECTION INPUT ;
    USE SIGNAL ;
    PORT
      LAYER M4 ;
        RECT  64.716 74.4 64.8 74.424 ;
    END
  END bank_e[296]
  PIN bank_e[297]
    DIRECTION INPUT ;
    USE SIGNAL ;
    PORT
      LAYER M4 ;
        RECT  64.716 74.64 64.8 74.664 ;
    END
  END bank_e[297]
  PIN bank_e[298]
    DIRECTION INPUT ;
    USE SIGNAL ;
    PORT
      LAYER M4 ;
        RECT  64.716 74.88 64.8 74.904 ;
    END
  END bank_e[298]
  PIN bank_e[299]
    DIRECTION INPUT ;
    USE SIGNAL ;
    PORT
      LAYER M4 ;
        RECT  64.716 75.12 64.8 75.144 ;
    END
  END bank_e[299]
  PIN bank_e[29]
    DIRECTION INPUT ;
    USE SIGNAL ;
    PORT
      LAYER M4 ;
        RECT  64.716 7.872 64.8 7.896 ;
    END
  END bank_e[29]
  PIN bank_e[2]
    DIRECTION INPUT ;
    USE SIGNAL ;
    PORT
      LAYER M4 ;
        RECT  64.716 1.152 64.8 1.176 ;
    END
  END bank_e[2]
  PIN bank_e[300]
    DIRECTION INPUT ;
    USE SIGNAL ;
    PORT
      LAYER M4 ;
        RECT  64.716 75.36 64.8 75.384 ;
    END
  END bank_e[300]
  PIN bank_e[301]
    DIRECTION INPUT ;
    USE SIGNAL ;
    PORT
      LAYER M4 ;
        RECT  64.716 75.6 64.8 75.624 ;
    END
  END bank_e[301]
  PIN bank_e[302]
    DIRECTION INPUT ;
    USE SIGNAL ;
    PORT
      LAYER M4 ;
        RECT  64.716 75.888 64.8 75.912 ;
    END
  END bank_e[302]
  PIN bank_e[303]
    DIRECTION INPUT ;
    USE SIGNAL ;
    PORT
      LAYER M4 ;
        RECT  64.716 76.128 64.8 76.152 ;
    END
  END bank_e[303]
  PIN bank_e[304]
    DIRECTION INPUT ;
    USE SIGNAL ;
    PORT
      LAYER M4 ;
        RECT  64.716 76.368 64.8 76.392 ;
    END
  END bank_e[304]
  PIN bank_e[305]
    DIRECTION INPUT ;
    USE SIGNAL ;
    PORT
      LAYER M4 ;
        RECT  64.716 76.608 64.8 76.632 ;
    END
  END bank_e[305]
  PIN bank_e[306]
    DIRECTION INPUT ;
    USE SIGNAL ;
    PORT
      LAYER M4 ;
        RECT  64.716 76.848 64.8 76.872 ;
    END
  END bank_e[306]
  PIN bank_e[307]
    DIRECTION INPUT ;
    USE SIGNAL ;
    PORT
      LAYER M4 ;
        RECT  64.716 77.136 64.8 77.16 ;
    END
  END bank_e[307]
  PIN bank_e[308]
    DIRECTION INPUT ;
    USE SIGNAL ;
    PORT
      LAYER M4 ;
        RECT  64.716 77.376 64.8 77.4 ;
    END
  END bank_e[308]
  PIN bank_e[309]
    DIRECTION INPUT ;
    USE SIGNAL ;
    PORT
      LAYER M4 ;
        RECT  64.716 77.616 64.8 77.64 ;
    END
  END bank_e[309]
  PIN bank_e[30]
    DIRECTION INPUT ;
    USE SIGNAL ;
    PORT
      LAYER M4 ;
        RECT  64.716 8.112 64.8 8.136 ;
    END
  END bank_e[30]
  PIN bank_e[310]
    DIRECTION INPUT ;
    USE SIGNAL ;
    PORT
      LAYER M4 ;
        RECT  64.716 77.856 64.8 77.88 ;
    END
  END bank_e[310]
  PIN bank_e[311]
    DIRECTION INPUT ;
    USE SIGNAL ;
    PORT
      LAYER M4 ;
        RECT  64.716 78.096 64.8 78.12 ;
    END
  END bank_e[311]
  PIN bank_e[312]
    DIRECTION INPUT ;
    USE SIGNAL ;
    PORT
      LAYER M4 ;
        RECT  64.716 78.384 64.8 78.408 ;
    END
  END bank_e[312]
  PIN bank_e[313]
    DIRECTION INPUT ;
    USE SIGNAL ;
    PORT
      LAYER M4 ;
        RECT  64.716 78.624 64.8 78.648 ;
    END
  END bank_e[313]
  PIN bank_e[314]
    DIRECTION INPUT ;
    USE SIGNAL ;
    PORT
      LAYER M4 ;
        RECT  64.716 78.864 64.8 78.888 ;
    END
  END bank_e[314]
  PIN bank_e[315]
    DIRECTION INPUT ;
    USE SIGNAL ;
    PORT
      LAYER M4 ;
        RECT  64.716 79.104 64.8 79.128 ;
    END
  END bank_e[315]
  PIN bank_e[316]
    DIRECTION INPUT ;
    USE SIGNAL ;
    PORT
      LAYER M4 ;
        RECT  64.716 79.344 64.8 79.368 ;
    END
  END bank_e[316]
  PIN bank_e[317]
    DIRECTION INPUT ;
    USE SIGNAL ;
    PORT
      LAYER M4 ;
        RECT  64.716 79.632 64.8 79.656 ;
    END
  END bank_e[317]
  PIN bank_e[318]
    DIRECTION INPUT ;
    USE SIGNAL ;
    PORT
      LAYER M4 ;
        RECT  64.716 79.872 64.8 79.896 ;
    END
  END bank_e[318]
  PIN bank_e[319]
    DIRECTION INPUT ;
    USE SIGNAL ;
    PORT
      LAYER M4 ;
        RECT  64.716 80.112 64.8 80.136 ;
    END
  END bank_e[319]
  PIN bank_e[31]
    DIRECTION INPUT ;
    USE SIGNAL ;
    PORT
      LAYER M4 ;
        RECT  64.716 8.352 64.8 8.376 ;
    END
  END bank_e[31]
  PIN bank_e[320]
    DIRECTION INPUT ;
    USE SIGNAL ;
    PORT
      LAYER M4 ;
        RECT  64.716 80.352 64.8 80.376 ;
    END
  END bank_e[320]
  PIN bank_e[321]
    DIRECTION INPUT ;
    USE SIGNAL ;
    PORT
      LAYER M4 ;
        RECT  64.716 80.592 64.8 80.616 ;
    END
  END bank_e[321]
  PIN bank_e[322]
    DIRECTION INPUT ;
    USE SIGNAL ;
    PORT
      LAYER M4 ;
        RECT  64.716 80.832 64.8 80.856 ;
    END
  END bank_e[322]
  PIN bank_e[323]
    DIRECTION INPUT ;
    USE SIGNAL ;
    PORT
      LAYER M4 ;
        RECT  64.716 81.12 64.8 81.144 ;
    END
  END bank_e[323]
  PIN bank_e[324]
    DIRECTION INPUT ;
    USE SIGNAL ;
    PORT
      LAYER M4 ;
        RECT  64.716 81.36 64.8 81.384 ;
    END
  END bank_e[324]
  PIN bank_e[325]
    DIRECTION INPUT ;
    USE SIGNAL ;
    PORT
      LAYER M4 ;
        RECT  64.716 81.6 64.8 81.624 ;
    END
  END bank_e[325]
  PIN bank_e[326]
    DIRECTION INPUT ;
    USE SIGNAL ;
    PORT
      LAYER M4 ;
        RECT  64.716 81.84 64.8 81.864 ;
    END
  END bank_e[326]
  PIN bank_e[327]
    DIRECTION INPUT ;
    USE SIGNAL ;
    PORT
      LAYER M4 ;
        RECT  64.716 82.08 64.8 82.104 ;
    END
  END bank_e[327]
  PIN bank_e[328]
    DIRECTION INPUT ;
    USE SIGNAL ;
    PORT
      LAYER M4 ;
        RECT  64.716 82.368 64.8 82.392 ;
    END
  END bank_e[328]
  PIN bank_e[329]
    DIRECTION INPUT ;
    USE SIGNAL ;
    PORT
      LAYER M4 ;
        RECT  64.716 82.608 64.8 82.632 ;
    END
  END bank_e[329]
  PIN bank_e[32]
    DIRECTION INPUT ;
    USE SIGNAL ;
    PORT
      LAYER M4 ;
        RECT  64.716 8.64 64.8 8.664 ;
    END
  END bank_e[32]
  PIN bank_e[330]
    DIRECTION INPUT ;
    USE SIGNAL ;
    PORT
      LAYER M4 ;
        RECT  64.716 82.848 64.8 82.872 ;
    END
  END bank_e[330]
  PIN bank_e[331]
    DIRECTION INPUT ;
    USE SIGNAL ;
    PORT
      LAYER M4 ;
        RECT  64.716 83.088 64.8 83.112 ;
    END
  END bank_e[331]
  PIN bank_e[332]
    DIRECTION INPUT ;
    USE SIGNAL ;
    PORT
      LAYER M4 ;
        RECT  64.716 83.328 64.8 83.352 ;
    END
  END bank_e[332]
  PIN bank_e[333]
    DIRECTION INPUT ;
    USE SIGNAL ;
    PORT
      LAYER M4 ;
        RECT  64.716 83.616 64.8 83.64 ;
    END
  END bank_e[333]
  PIN bank_e[334]
    DIRECTION INPUT ;
    USE SIGNAL ;
    PORT
      LAYER M4 ;
        RECT  64.716 83.856 64.8 83.88 ;
    END
  END bank_e[334]
  PIN bank_e[335]
    DIRECTION INPUT ;
    USE SIGNAL ;
    PORT
      LAYER M4 ;
        RECT  64.716 84.096 64.8 84.12 ;
    END
  END bank_e[335]
  PIN bank_e[336]
    DIRECTION INPUT ;
    USE SIGNAL ;
    PORT
      LAYER M4 ;
        RECT  64.716 84.336 64.8 84.36 ;
    END
  END bank_e[336]
  PIN bank_e[337]
    DIRECTION INPUT ;
    USE SIGNAL ;
    PORT
      LAYER M4 ;
        RECT  64.716 84.576 64.8 84.6 ;
    END
  END bank_e[337]
  PIN bank_e[338]
    DIRECTION INPUT ;
    USE SIGNAL ;
    PORT
      LAYER M4 ;
        RECT  64.716 84.816 64.8 84.84 ;
    END
  END bank_e[338]
  PIN bank_e[339]
    DIRECTION INPUT ;
    USE SIGNAL ;
    PORT
      LAYER M4 ;
        RECT  64.716 85.104 64.8 85.128 ;
    END
  END bank_e[339]
  PIN bank_e[33]
    DIRECTION INPUT ;
    USE SIGNAL ;
    PORT
      LAYER M4 ;
        RECT  64.716 8.88 64.8 8.904 ;
    END
  END bank_e[33]
  PIN bank_e[340]
    DIRECTION INPUT ;
    USE SIGNAL ;
    PORT
      LAYER M4 ;
        RECT  64.716 85.344 64.8 85.368 ;
    END
  END bank_e[340]
  PIN bank_e[341]
    DIRECTION INPUT ;
    USE SIGNAL ;
    PORT
      LAYER M4 ;
        RECT  64.716 85.584 64.8 85.608 ;
    END
  END bank_e[341]
  PIN bank_e[342]
    DIRECTION INPUT ;
    USE SIGNAL ;
    PORT
      LAYER M4 ;
        RECT  64.716 85.824 64.8 85.848 ;
    END
  END bank_e[342]
  PIN bank_e[343]
    DIRECTION INPUT ;
    USE SIGNAL ;
    PORT
      LAYER M4 ;
        RECT  64.716 86.064 64.8 86.088 ;
    END
  END bank_e[343]
  PIN bank_e[344]
    DIRECTION INPUT ;
    USE SIGNAL ;
    PORT
      LAYER M4 ;
        RECT  64.716 86.352 64.8 86.376 ;
    END
  END bank_e[344]
  PIN bank_e[345]
    DIRECTION INPUT ;
    USE SIGNAL ;
    PORT
      LAYER M4 ;
        RECT  64.716 86.592 64.8 86.616 ;
    END
  END bank_e[345]
  PIN bank_e[346]
    DIRECTION INPUT ;
    USE SIGNAL ;
    PORT
      LAYER M4 ;
        RECT  64.716 86.832 64.8 86.856 ;
    END
  END bank_e[346]
  PIN bank_e[347]
    DIRECTION INPUT ;
    USE SIGNAL ;
    PORT
      LAYER M4 ;
        RECT  64.716 87.072 64.8 87.096 ;
    END
  END bank_e[347]
  PIN bank_e[348]
    DIRECTION INPUT ;
    USE SIGNAL ;
    PORT
      LAYER M4 ;
        RECT  64.716 87.312 64.8 87.336 ;
    END
  END bank_e[348]
  PIN bank_e[349]
    DIRECTION INPUT ;
    USE SIGNAL ;
    PORT
      LAYER M4 ;
        RECT  64.716 87.6 64.8 87.624 ;
    END
  END bank_e[349]
  PIN bank_e[34]
    DIRECTION INPUT ;
    USE SIGNAL ;
    PORT
      LAYER M4 ;
        RECT  64.716 9.12 64.8 9.144 ;
    END
  END bank_e[34]
  PIN bank_e[350]
    DIRECTION INPUT ;
    USE SIGNAL ;
    PORT
      LAYER M4 ;
        RECT  64.716 87.84 64.8 87.864 ;
    END
  END bank_e[350]
  PIN bank_e[351]
    DIRECTION INPUT ;
    USE SIGNAL ;
    PORT
      LAYER M4 ;
        RECT  64.716 88.08 64.8 88.104 ;
    END
  END bank_e[351]
  PIN bank_e[352]
    DIRECTION INPUT ;
    USE SIGNAL ;
    PORT
      LAYER M4 ;
        RECT  64.716 88.32 64.8 88.344 ;
    END
  END bank_e[352]
  PIN bank_e[353]
    DIRECTION INPUT ;
    USE SIGNAL ;
    PORT
      LAYER M4 ;
        RECT  64.716 88.56 64.8 88.584 ;
    END
  END bank_e[353]
  PIN bank_e[354]
    DIRECTION INPUT ;
    USE SIGNAL ;
    PORT
      LAYER M4 ;
        RECT  64.716 88.8 64.8 88.824 ;
    END
  END bank_e[354]
  PIN bank_e[355]
    DIRECTION INPUT ;
    USE SIGNAL ;
    PORT
      LAYER M4 ;
        RECT  64.716 89.088 64.8 89.112 ;
    END
  END bank_e[355]
  PIN bank_e[356]
    DIRECTION INPUT ;
    USE SIGNAL ;
    PORT
      LAYER M4 ;
        RECT  64.716 89.328 64.8 89.352 ;
    END
  END bank_e[356]
  PIN bank_e[357]
    DIRECTION INPUT ;
    USE SIGNAL ;
    PORT
      LAYER M4 ;
        RECT  64.716 89.568 64.8 89.592 ;
    END
  END bank_e[357]
  PIN bank_e[358]
    DIRECTION INPUT ;
    USE SIGNAL ;
    PORT
      LAYER M4 ;
        RECT  64.716 89.808 64.8 89.832 ;
    END
  END bank_e[358]
  PIN bank_e[359]
    DIRECTION INPUT ;
    USE SIGNAL ;
    PORT
      LAYER M4 ;
        RECT  64.716 90.048 64.8 90.072 ;
    END
  END bank_e[359]
  PIN bank_e[35]
    DIRECTION INPUT ;
    USE SIGNAL ;
    PORT
      LAYER M4 ;
        RECT  64.716 9.36 64.8 9.384 ;
    END
  END bank_e[35]
  PIN bank_e[360]
    DIRECTION INPUT ;
    USE SIGNAL ;
    PORT
      LAYER M4 ;
        RECT  64.716 90.336 64.8 90.36 ;
    END
  END bank_e[360]
  PIN bank_e[361]
    DIRECTION INPUT ;
    USE SIGNAL ;
    PORT
      LAYER M4 ;
        RECT  64.716 90.576 64.8 90.6 ;
    END
  END bank_e[361]
  PIN bank_e[362]
    DIRECTION INPUT ;
    USE SIGNAL ;
    PORT
      LAYER M4 ;
        RECT  64.716 90.816 64.8 90.84 ;
    END
  END bank_e[362]
  PIN bank_e[363]
    DIRECTION INPUT ;
    USE SIGNAL ;
    PORT
      LAYER M4 ;
        RECT  64.716 91.056 64.8 91.08 ;
    END
  END bank_e[363]
  PIN bank_e[364]
    DIRECTION INPUT ;
    USE SIGNAL ;
    PORT
      LAYER M4 ;
        RECT  64.716 91.296 64.8 91.32 ;
    END
  END bank_e[364]
  PIN bank_e[365]
    DIRECTION INPUT ;
    USE SIGNAL ;
    PORT
      LAYER M4 ;
        RECT  64.716 91.584 64.8 91.608 ;
    END
  END bank_e[365]
  PIN bank_e[366]
    DIRECTION INPUT ;
    USE SIGNAL ;
    PORT
      LAYER M4 ;
        RECT  64.716 91.824 64.8 91.848 ;
    END
  END bank_e[366]
  PIN bank_e[367]
    DIRECTION INPUT ;
    USE SIGNAL ;
    PORT
      LAYER M4 ;
        RECT  64.716 92.064 64.8 92.088 ;
    END
  END bank_e[367]
  PIN bank_e[368]
    DIRECTION INPUT ;
    USE SIGNAL ;
    PORT
      LAYER M4 ;
        RECT  64.716 92.304 64.8 92.328 ;
    END
  END bank_e[368]
  PIN bank_e[369]
    DIRECTION INPUT ;
    USE SIGNAL ;
    PORT
      LAYER M4 ;
        RECT  64.716 92.544 64.8 92.568 ;
    END
  END bank_e[369]
  PIN bank_e[36]
    DIRECTION INPUT ;
    USE SIGNAL ;
    PORT
      LAYER M4 ;
        RECT  64.716 9.6 64.8 9.624 ;
    END
  END bank_e[36]
  PIN bank_e[370]
    DIRECTION INPUT ;
    USE SIGNAL ;
    PORT
      LAYER M4 ;
        RECT  64.716 92.832 64.8 92.856 ;
    END
  END bank_e[370]
  PIN bank_e[371]
    DIRECTION INPUT ;
    USE SIGNAL ;
    PORT
      LAYER M4 ;
        RECT  64.716 93.072 64.8 93.096 ;
    END
  END bank_e[371]
  PIN bank_e[372]
    DIRECTION INPUT ;
    USE SIGNAL ;
    PORT
      LAYER M4 ;
        RECT  64.716 93.312 64.8 93.336 ;
    END
  END bank_e[372]
  PIN bank_e[373]
    DIRECTION INPUT ;
    USE SIGNAL ;
    PORT
      LAYER M4 ;
        RECT  64.716 93.552 64.8 93.576 ;
    END
  END bank_e[373]
  PIN bank_e[374]
    DIRECTION INPUT ;
    USE SIGNAL ;
    PORT
      LAYER M4 ;
        RECT  64.716 93.792 64.8 93.816 ;
    END
  END bank_e[374]
  PIN bank_e[375]
    DIRECTION INPUT ;
    USE SIGNAL ;
    PORT
      LAYER M4 ;
        RECT  64.716 94.032 64.8 94.056 ;
    END
  END bank_e[375]
  PIN bank_e[376]
    DIRECTION INPUT ;
    USE SIGNAL ;
    PORT
      LAYER M4 ;
        RECT  64.716 94.32 64.8 94.344 ;
    END
  END bank_e[376]
  PIN bank_e[377]
    DIRECTION INPUT ;
    USE SIGNAL ;
    PORT
      LAYER M4 ;
        RECT  64.716 94.56 64.8 94.584 ;
    END
  END bank_e[377]
  PIN bank_e[378]
    DIRECTION INPUT ;
    USE SIGNAL ;
    PORT
      LAYER M4 ;
        RECT  64.716 94.8 64.8 94.824 ;
    END
  END bank_e[378]
  PIN bank_e[379]
    DIRECTION INPUT ;
    USE SIGNAL ;
    PORT
      LAYER M4 ;
        RECT  64.716 95.04 64.8 95.064 ;
    END
  END bank_e[379]
  PIN bank_e[37]
    DIRECTION INPUT ;
    USE SIGNAL ;
    PORT
      LAYER M4 ;
        RECT  64.716 9.888 64.8 9.912 ;
    END
  END bank_e[37]
  PIN bank_e[380]
    DIRECTION INPUT ;
    USE SIGNAL ;
    PORT
      LAYER M4 ;
        RECT  64.716 95.28 64.8 95.304 ;
    END
  END bank_e[380]
  PIN bank_e[381]
    DIRECTION INPUT ;
    USE SIGNAL ;
    PORT
      LAYER M4 ;
        RECT  64.716 95.568 64.8 95.592 ;
    END
  END bank_e[381]
  PIN bank_e[382]
    DIRECTION INPUT ;
    USE SIGNAL ;
    PORT
      LAYER M4 ;
        RECT  64.716 95.808 64.8 95.832 ;
    END
  END bank_e[382]
  PIN bank_e[383]
    DIRECTION INPUT ;
    USE SIGNAL ;
    PORT
      LAYER M4 ;
        RECT  64.716 96.048 64.8 96.072 ;
    END
  END bank_e[383]
  PIN bank_e[384]
    DIRECTION INPUT ;
    USE SIGNAL ;
    PORT
      LAYER M4 ;
        RECT  64.716 96.288 64.8 96.312 ;
    END
  END bank_e[384]
  PIN bank_e[385]
    DIRECTION INPUT ;
    USE SIGNAL ;
    PORT
      LAYER M4 ;
        RECT  64.716 96.528 64.8 96.552 ;
    END
  END bank_e[385]
  PIN bank_e[386]
    DIRECTION INPUT ;
    USE SIGNAL ;
    PORT
      LAYER M4 ;
        RECT  64.716 96.816 64.8 96.84 ;
    END
  END bank_e[386]
  PIN bank_e[387]
    DIRECTION INPUT ;
    USE SIGNAL ;
    PORT
      LAYER M4 ;
        RECT  64.716 97.056 64.8 97.08 ;
    END
  END bank_e[387]
  PIN bank_e[388]
    DIRECTION INPUT ;
    USE SIGNAL ;
    PORT
      LAYER M4 ;
        RECT  64.716 97.296 64.8 97.32 ;
    END
  END bank_e[388]
  PIN bank_e[389]
    DIRECTION INPUT ;
    USE SIGNAL ;
    PORT
      LAYER M4 ;
        RECT  64.716 97.536 64.8 97.56 ;
    END
  END bank_e[389]
  PIN bank_e[38]
    DIRECTION INPUT ;
    USE SIGNAL ;
    PORT
      LAYER M4 ;
        RECT  64.716 10.128 64.8 10.152 ;
    END
  END bank_e[38]
  PIN bank_e[390]
    DIRECTION INPUT ;
    USE SIGNAL ;
    PORT
      LAYER M4 ;
        RECT  64.716 97.776 64.8 97.8 ;
    END
  END bank_e[390]
  PIN bank_e[391]
    DIRECTION INPUT ;
    USE SIGNAL ;
    PORT
      LAYER M4 ;
        RECT  64.716 98.016 64.8 98.04 ;
    END
  END bank_e[391]
  PIN bank_e[392]
    DIRECTION INPUT ;
    USE SIGNAL ;
    PORT
      LAYER M4 ;
        RECT  64.716 98.304 64.8 98.328 ;
    END
  END bank_e[392]
  PIN bank_e[393]
    DIRECTION INPUT ;
    USE SIGNAL ;
    PORT
      LAYER M4 ;
        RECT  64.716 98.544 64.8 98.568 ;
    END
  END bank_e[393]
  PIN bank_e[394]
    DIRECTION INPUT ;
    USE SIGNAL ;
    PORT
      LAYER M4 ;
        RECT  64.716 98.784 64.8 98.808 ;
    END
  END bank_e[394]
  PIN bank_e[395]
    DIRECTION INPUT ;
    USE SIGNAL ;
    PORT
      LAYER M4 ;
        RECT  64.716 99.024 64.8 99.048 ;
    END
  END bank_e[395]
  PIN bank_e[396]
    DIRECTION INPUT ;
    USE SIGNAL ;
    PORT
      LAYER M4 ;
        RECT  64.716 99.264 64.8 99.288 ;
    END
  END bank_e[396]
  PIN bank_e[397]
    DIRECTION INPUT ;
    USE SIGNAL ;
    PORT
      LAYER M4 ;
        RECT  64.716 99.552 64.8 99.576 ;
    END
  END bank_e[397]
  PIN bank_e[398]
    DIRECTION INPUT ;
    USE SIGNAL ;
    PORT
      LAYER M4 ;
        RECT  64.716 99.792 64.8 99.816 ;
    END
  END bank_e[398]
  PIN bank_e[399]
    DIRECTION INPUT ;
    USE SIGNAL ;
    PORT
      LAYER M4 ;
        RECT  64.716 100.032 64.8 100.056 ;
    END
  END bank_e[399]
  PIN bank_e[39]
    DIRECTION INPUT ;
    USE SIGNAL ;
    PORT
      LAYER M4 ;
        RECT  64.716 10.368 64.8 10.392 ;
    END
  END bank_e[39]
  PIN bank_e[3]
    DIRECTION INPUT ;
    USE SIGNAL ;
    PORT
      LAYER M4 ;
        RECT  64.716 1.392 64.8 1.416 ;
    END
  END bank_e[3]
  PIN bank_e[400]
    DIRECTION INPUT ;
    USE SIGNAL ;
    PORT
      LAYER M4 ;
        RECT  64.716 100.272 64.8 100.296 ;
    END
  END bank_e[400]
  PIN bank_e[401]
    DIRECTION INPUT ;
    USE SIGNAL ;
    PORT
      LAYER M4 ;
        RECT  64.716 100.512 64.8 100.536 ;
    END
  END bank_e[401]
  PIN bank_e[402]
    DIRECTION INPUT ;
    USE SIGNAL ;
    PORT
      LAYER M4 ;
        RECT  64.716 100.8 64.8 100.824 ;
    END
  END bank_e[402]
  PIN bank_e[403]
    DIRECTION INPUT ;
    USE SIGNAL ;
    PORT
      LAYER M4 ;
        RECT  64.716 101.04 64.8 101.064 ;
    END
  END bank_e[403]
  PIN bank_e[404]
    DIRECTION INPUT ;
    USE SIGNAL ;
    PORT
      LAYER M4 ;
        RECT  64.716 101.28 64.8 101.304 ;
    END
  END bank_e[404]
  PIN bank_e[405]
    DIRECTION INPUT ;
    USE SIGNAL ;
    PORT
      LAYER M4 ;
        RECT  64.716 101.52 64.8 101.544 ;
    END
  END bank_e[405]
  PIN bank_e[406]
    DIRECTION INPUT ;
    USE SIGNAL ;
    PORT
      LAYER M4 ;
        RECT  64.716 101.76 64.8 101.784 ;
    END
  END bank_e[406]
  PIN bank_e[407]
    DIRECTION INPUT ;
    USE SIGNAL ;
    PORT
      LAYER M4 ;
        RECT  64.716 102.048 64.8 102.072 ;
    END
  END bank_e[407]
  PIN bank_e[408]
    DIRECTION INPUT ;
    USE SIGNAL ;
    PORT
      LAYER M4 ;
        RECT  64.716 102.288 64.8 102.312 ;
    END
  END bank_e[408]
  PIN bank_e[409]
    DIRECTION INPUT ;
    USE SIGNAL ;
    PORT
      LAYER M4 ;
        RECT  64.716 102.528 64.8 102.552 ;
    END
  END bank_e[409]
  PIN bank_e[40]
    DIRECTION INPUT ;
    USE SIGNAL ;
    PORT
      LAYER M4 ;
        RECT  64.716 10.608 64.8 10.632 ;
    END
  END bank_e[40]
  PIN bank_e[410]
    DIRECTION INPUT ;
    USE SIGNAL ;
    PORT
      LAYER M4 ;
        RECT  64.716 102.768 64.8 102.792 ;
    END
  END bank_e[410]
  PIN bank_e[411]
    DIRECTION INPUT ;
    USE SIGNAL ;
    PORT
      LAYER M4 ;
        RECT  64.716 103.008 64.8 103.032 ;
    END
  END bank_e[411]
  PIN bank_e[412]
    DIRECTION INPUT ;
    USE SIGNAL ;
    PORT
      LAYER M4 ;
        RECT  64.716 103.248 64.8 103.272 ;
    END
  END bank_e[412]
  PIN bank_e[413]
    DIRECTION INPUT ;
    USE SIGNAL ;
    PORT
      LAYER M4 ;
        RECT  64.716 103.536 64.8 103.56 ;
    END
  END bank_e[413]
  PIN bank_e[414]
    DIRECTION INPUT ;
    USE SIGNAL ;
    PORT
      LAYER M4 ;
        RECT  64.716 103.776 64.8 103.8 ;
    END
  END bank_e[414]
  PIN bank_e[415]
    DIRECTION INPUT ;
    USE SIGNAL ;
    PORT
      LAYER M4 ;
        RECT  64.716 104.016 64.8 104.04 ;
    END
  END bank_e[415]
  PIN bank_e[416]
    DIRECTION INPUT ;
    USE SIGNAL ;
    PORT
      LAYER M4 ;
        RECT  64.716 104.256 64.8 104.28 ;
    END
  END bank_e[416]
  PIN bank_e[417]
    DIRECTION INPUT ;
    USE SIGNAL ;
    PORT
      LAYER M4 ;
        RECT  64.716 104.496 64.8 104.52 ;
    END
  END bank_e[417]
  PIN bank_e[418]
    DIRECTION INPUT ;
    USE SIGNAL ;
    PORT
      LAYER M4 ;
        RECT  64.716 104.784 64.8 104.808 ;
    END
  END bank_e[418]
  PIN bank_e[419]
    DIRECTION INPUT ;
    USE SIGNAL ;
    PORT
      LAYER M4 ;
        RECT  64.716 105.024 64.8 105.048 ;
    END
  END bank_e[419]
  PIN bank_e[41]
    DIRECTION INPUT ;
    USE SIGNAL ;
    PORT
      LAYER M4 ;
        RECT  64.716 10.848 64.8 10.872 ;
    END
  END bank_e[41]
  PIN bank_e[420]
    DIRECTION INPUT ;
    USE SIGNAL ;
    PORT
      LAYER M4 ;
        RECT  64.716 105.264 64.8 105.288 ;
    END
  END bank_e[420]
  PIN bank_e[421]
    DIRECTION INPUT ;
    USE SIGNAL ;
    PORT
      LAYER M4 ;
        RECT  64.716 105.504 64.8 105.528 ;
    END
  END bank_e[421]
  PIN bank_e[422]
    DIRECTION INPUT ;
    USE SIGNAL ;
    PORT
      LAYER M4 ;
        RECT  64.716 105.744 64.8 105.768 ;
    END
  END bank_e[422]
  PIN bank_e[423]
    DIRECTION INPUT ;
    USE SIGNAL ;
    PORT
      LAYER M4 ;
        RECT  64.716 106.032 64.8 106.056 ;
    END
  END bank_e[423]
  PIN bank_e[424]
    DIRECTION INPUT ;
    USE SIGNAL ;
    PORT
      LAYER M4 ;
        RECT  64.716 106.272 64.8 106.296 ;
    END
  END bank_e[424]
  PIN bank_e[425]
    DIRECTION INPUT ;
    USE SIGNAL ;
    PORT
      LAYER M4 ;
        RECT  64.716 106.512 64.8 106.536 ;
    END
  END bank_e[425]
  PIN bank_e[426]
    DIRECTION INPUT ;
    USE SIGNAL ;
    PORT
      LAYER M4 ;
        RECT  64.716 106.752 64.8 106.776 ;
    END
  END bank_e[426]
  PIN bank_e[427]
    DIRECTION INPUT ;
    USE SIGNAL ;
    PORT
      LAYER M4 ;
        RECT  64.716 106.992 64.8 107.016 ;
    END
  END bank_e[427]
  PIN bank_e[428]
    DIRECTION INPUT ;
    USE SIGNAL ;
    PORT
      LAYER M4 ;
        RECT  64.716 107.232 64.8 107.256 ;
    END
  END bank_e[428]
  PIN bank_e[429]
    DIRECTION INPUT ;
    USE SIGNAL ;
    PORT
      LAYER M4 ;
        RECT  64.716 107.52 64.8 107.544 ;
    END
  END bank_e[429]
  PIN bank_e[42]
    DIRECTION INPUT ;
    USE SIGNAL ;
    PORT
      LAYER M4 ;
        RECT  64.716 11.136 64.8 11.16 ;
    END
  END bank_e[42]
  PIN bank_e[430]
    DIRECTION INPUT ;
    USE SIGNAL ;
    PORT
      LAYER M4 ;
        RECT  64.716 107.76 64.8 107.784 ;
    END
  END bank_e[430]
  PIN bank_e[431]
    DIRECTION INPUT ;
    USE SIGNAL ;
    PORT
      LAYER M4 ;
        RECT  64.716 108 64.8 108.024 ;
    END
  END bank_e[431]
  PIN bank_e[432]
    DIRECTION INPUT ;
    USE SIGNAL ;
    PORT
      LAYER M4 ;
        RECT  64.716 108.24 64.8 108.264 ;
    END
  END bank_e[432]
  PIN bank_e[433]
    DIRECTION INPUT ;
    USE SIGNAL ;
    PORT
      LAYER M4 ;
        RECT  64.716 108.48 64.8 108.504 ;
    END
  END bank_e[433]
  PIN bank_e[434]
    DIRECTION INPUT ;
    USE SIGNAL ;
    PORT
      LAYER M4 ;
        RECT  64.716 108.768 64.8 108.792 ;
    END
  END bank_e[434]
  PIN bank_e[435]
    DIRECTION INPUT ;
    USE SIGNAL ;
    PORT
      LAYER M4 ;
        RECT  64.716 109.008 64.8 109.032 ;
    END
  END bank_e[435]
  PIN bank_e[436]
    DIRECTION INPUT ;
    USE SIGNAL ;
    PORT
      LAYER M4 ;
        RECT  64.716 109.248 64.8 109.272 ;
    END
  END bank_e[436]
  PIN bank_e[437]
    DIRECTION INPUT ;
    USE SIGNAL ;
    PORT
      LAYER M4 ;
        RECT  64.716 109.488 64.8 109.512 ;
    END
  END bank_e[437]
  PIN bank_e[438]
    DIRECTION INPUT ;
    USE SIGNAL ;
    PORT
      LAYER M4 ;
        RECT  64.716 109.728 64.8 109.752 ;
    END
  END bank_e[438]
  PIN bank_e[439]
    DIRECTION INPUT ;
    USE SIGNAL ;
    PORT
      LAYER M4 ;
        RECT  64.716 110.016 64.8 110.04 ;
    END
  END bank_e[439]
  PIN bank_e[43]
    DIRECTION INPUT ;
    USE SIGNAL ;
    PORT
      LAYER M4 ;
        RECT  64.716 11.376 64.8 11.4 ;
    END
  END bank_e[43]
  PIN bank_e[440]
    DIRECTION INPUT ;
    USE SIGNAL ;
    PORT
      LAYER M4 ;
        RECT  64.716 110.256 64.8 110.28 ;
    END
  END bank_e[440]
  PIN bank_e[441]
    DIRECTION INPUT ;
    USE SIGNAL ;
    PORT
      LAYER M4 ;
        RECT  64.716 110.496 64.8 110.52 ;
    END
  END bank_e[441]
  PIN bank_e[442]
    DIRECTION INPUT ;
    USE SIGNAL ;
    PORT
      LAYER M4 ;
        RECT  64.716 110.736 64.8 110.76 ;
    END
  END bank_e[442]
  PIN bank_e[443]
    DIRECTION INPUT ;
    USE SIGNAL ;
    PORT
      LAYER M4 ;
        RECT  64.716 110.976 64.8 111 ;
    END
  END bank_e[443]
  PIN bank_e[444]
    DIRECTION INPUT ;
    USE SIGNAL ;
    PORT
      LAYER M4 ;
        RECT  64.716 111.264 64.8 111.288 ;
    END
  END bank_e[444]
  PIN bank_e[445]
    DIRECTION INPUT ;
    USE SIGNAL ;
    PORT
      LAYER M4 ;
        RECT  64.716 111.504 64.8 111.528 ;
    END
  END bank_e[445]
  PIN bank_e[446]
    DIRECTION INPUT ;
    USE SIGNAL ;
    PORT
      LAYER M4 ;
        RECT  64.716 111.744 64.8 111.768 ;
    END
  END bank_e[446]
  PIN bank_e[447]
    DIRECTION INPUT ;
    USE SIGNAL ;
    PORT
      LAYER M4 ;
        RECT  64.716 111.984 64.8 112.008 ;
    END
  END bank_e[447]
  PIN bank_e[448]
    DIRECTION INPUT ;
    USE SIGNAL ;
    PORT
      LAYER M4 ;
        RECT  64.716 112.224 64.8 112.248 ;
    END
  END bank_e[448]
  PIN bank_e[449]
    DIRECTION INPUT ;
    USE SIGNAL ;
    PORT
      LAYER M4 ;
        RECT  64.716 112.464 64.8 112.488 ;
    END
  END bank_e[449]
  PIN bank_e[44]
    DIRECTION INPUT ;
    USE SIGNAL ;
    PORT
      LAYER M4 ;
        RECT  64.716 11.616 64.8 11.64 ;
    END
  END bank_e[44]
  PIN bank_e[450]
    DIRECTION INPUT ;
    USE SIGNAL ;
    PORT
      LAYER M4 ;
        RECT  64.716 112.752 64.8 112.776 ;
    END
  END bank_e[450]
  PIN bank_e[451]
    DIRECTION INPUT ;
    USE SIGNAL ;
    PORT
      LAYER M4 ;
        RECT  64.716 112.992 64.8 113.016 ;
    END
  END bank_e[451]
  PIN bank_e[452]
    DIRECTION INPUT ;
    USE SIGNAL ;
    PORT
      LAYER M4 ;
        RECT  64.716 113.232 64.8 113.256 ;
    END
  END bank_e[452]
  PIN bank_e[453]
    DIRECTION INPUT ;
    USE SIGNAL ;
    PORT
      LAYER M4 ;
        RECT  64.716 113.472 64.8 113.496 ;
    END
  END bank_e[453]
  PIN bank_e[454]
    DIRECTION INPUT ;
    USE SIGNAL ;
    PORT
      LAYER M4 ;
        RECT  64.716 113.712 64.8 113.736 ;
    END
  END bank_e[454]
  PIN bank_e[455]
    DIRECTION INPUT ;
    USE SIGNAL ;
    PORT
      LAYER M4 ;
        RECT  64.716 114 64.8 114.024 ;
    END
  END bank_e[455]
  PIN bank_e[456]
    DIRECTION INPUT ;
    USE SIGNAL ;
    PORT
      LAYER M4 ;
        RECT  64.716 114.24 64.8 114.264 ;
    END
  END bank_e[456]
  PIN bank_e[457]
    DIRECTION INPUT ;
    USE SIGNAL ;
    PORT
      LAYER M4 ;
        RECT  64.716 114.48 64.8 114.504 ;
    END
  END bank_e[457]
  PIN bank_e[458]
    DIRECTION INPUT ;
    USE SIGNAL ;
    PORT
      LAYER M4 ;
        RECT  64.716 114.72 64.8 114.744 ;
    END
  END bank_e[458]
  PIN bank_e[459]
    DIRECTION INPUT ;
    USE SIGNAL ;
    PORT
      LAYER M4 ;
        RECT  64.716 114.96 64.8 114.984 ;
    END
  END bank_e[459]
  PIN bank_e[45]
    DIRECTION INPUT ;
    USE SIGNAL ;
    PORT
      LAYER M4 ;
        RECT  64.716 11.856 64.8 11.88 ;
    END
  END bank_e[45]
  PIN bank_e[460]
    DIRECTION INPUT ;
    USE SIGNAL ;
    PORT
      LAYER M4 ;
        RECT  64.716 115.248 64.8 115.272 ;
    END
  END bank_e[460]
  PIN bank_e[461]
    DIRECTION INPUT ;
    USE SIGNAL ;
    PORT
      LAYER M4 ;
        RECT  64.716 115.488 64.8 115.512 ;
    END
  END bank_e[461]
  PIN bank_e[462]
    DIRECTION INPUT ;
    USE SIGNAL ;
    PORT
      LAYER M4 ;
        RECT  64.716 115.728 64.8 115.752 ;
    END
  END bank_e[462]
  PIN bank_e[463]
    DIRECTION INPUT ;
    USE SIGNAL ;
    PORT
      LAYER M4 ;
        RECT  64.716 115.968 64.8 115.992 ;
    END
  END bank_e[463]
  PIN bank_e[464]
    DIRECTION INPUT ;
    USE SIGNAL ;
    PORT
      LAYER M4 ;
        RECT  64.716 116.208 64.8 116.232 ;
    END
  END bank_e[464]
  PIN bank_e[465]
    DIRECTION INPUT ;
    USE SIGNAL ;
    PORT
      LAYER M4 ;
        RECT  64.716 116.448 64.8 116.472 ;
    END
  END bank_e[465]
  PIN bank_e[466]
    DIRECTION INPUT ;
    USE SIGNAL ;
    PORT
      LAYER M4 ;
        RECT  64.716 116.736 64.8 116.76 ;
    END
  END bank_e[466]
  PIN bank_e[467]
    DIRECTION INPUT ;
    USE SIGNAL ;
    PORT
      LAYER M4 ;
        RECT  64.716 116.976 64.8 117 ;
    END
  END bank_e[467]
  PIN bank_e[468]
    DIRECTION INPUT ;
    USE SIGNAL ;
    PORT
      LAYER M4 ;
        RECT  64.716 117.216 64.8 117.24 ;
    END
  END bank_e[468]
  PIN bank_e[469]
    DIRECTION INPUT ;
    USE SIGNAL ;
    PORT
      LAYER M4 ;
        RECT  64.716 117.456 64.8 117.48 ;
    END
  END bank_e[469]
  PIN bank_e[46]
    DIRECTION INPUT ;
    USE SIGNAL ;
    PORT
      LAYER M4 ;
        RECT  64.716 12.096 64.8 12.12 ;
    END
  END bank_e[46]
  PIN bank_e[470]
    DIRECTION INPUT ;
    USE SIGNAL ;
    PORT
      LAYER M4 ;
        RECT  64.716 117.696 64.8 117.72 ;
    END
  END bank_e[470]
  PIN bank_e[471]
    DIRECTION INPUT ;
    USE SIGNAL ;
    PORT
      LAYER M4 ;
        RECT  64.716 117.984 64.8 118.008 ;
    END
  END bank_e[471]
  PIN bank_e[472]
    DIRECTION INPUT ;
    USE SIGNAL ;
    PORT
      LAYER M4 ;
        RECT  64.716 118.224 64.8 118.248 ;
    END
  END bank_e[472]
  PIN bank_e[473]
    DIRECTION INPUT ;
    USE SIGNAL ;
    PORT
      LAYER M4 ;
        RECT  64.716 118.464 64.8 118.488 ;
    END
  END bank_e[473]
  PIN bank_e[474]
    DIRECTION INPUT ;
    USE SIGNAL ;
    PORT
      LAYER M4 ;
        RECT  64.716 118.704 64.8 118.728 ;
    END
  END bank_e[474]
  PIN bank_e[475]
    DIRECTION INPUT ;
    USE SIGNAL ;
    PORT
      LAYER M4 ;
        RECT  64.716 118.944 64.8 118.968 ;
    END
  END bank_e[475]
  PIN bank_e[476]
    DIRECTION INPUT ;
    USE SIGNAL ;
    PORT
      LAYER M4 ;
        RECT  64.716 119.232 64.8 119.256 ;
    END
  END bank_e[476]
  PIN bank_e[477]
    DIRECTION INPUT ;
    USE SIGNAL ;
    PORT
      LAYER M4 ;
        RECT  64.716 119.472 64.8 119.496 ;
    END
  END bank_e[477]
  PIN bank_e[478]
    DIRECTION INPUT ;
    USE SIGNAL ;
    PORT
      LAYER M4 ;
        RECT  64.716 119.712 64.8 119.736 ;
    END
  END bank_e[478]
  PIN bank_e[479]
    DIRECTION INPUT ;
    USE SIGNAL ;
    PORT
      LAYER M4 ;
        RECT  64.716 119.952 64.8 119.976 ;
    END
  END bank_e[479]
  PIN bank_e[47]
    DIRECTION INPUT ;
    USE SIGNAL ;
    PORT
      LAYER M4 ;
        RECT  64.716 12.336 64.8 12.36 ;
    END
  END bank_e[47]
  PIN bank_e[480]
    DIRECTION INPUT ;
    USE SIGNAL ;
    PORT
      LAYER M4 ;
        RECT  64.716 120.192 64.8 120.216 ;
    END
  END bank_e[480]
  PIN bank_e[481]
    DIRECTION INPUT ;
    USE SIGNAL ;
    PORT
      LAYER M4 ;
        RECT  64.716 120.432 64.8 120.456 ;
    END
  END bank_e[481]
  PIN bank_e[482]
    DIRECTION INPUT ;
    USE SIGNAL ;
    PORT
      LAYER M4 ;
        RECT  64.716 120.72 64.8 120.744 ;
    END
  END bank_e[482]
  PIN bank_e[483]
    DIRECTION INPUT ;
    USE SIGNAL ;
    PORT
      LAYER M4 ;
        RECT  64.716 120.96 64.8 120.984 ;
    END
  END bank_e[483]
  PIN bank_e[484]
    DIRECTION INPUT ;
    USE SIGNAL ;
    PORT
      LAYER M4 ;
        RECT  64.716 121.2 64.8 121.224 ;
    END
  END bank_e[484]
  PIN bank_e[485]
    DIRECTION INPUT ;
    USE SIGNAL ;
    PORT
      LAYER M4 ;
        RECT  64.716 121.44 64.8 121.464 ;
    END
  END bank_e[485]
  PIN bank_e[486]
    DIRECTION INPUT ;
    USE SIGNAL ;
    PORT
      LAYER M4 ;
        RECT  64.716 121.68 64.8 121.704 ;
    END
  END bank_e[486]
  PIN bank_e[487]
    DIRECTION INPUT ;
    USE SIGNAL ;
    PORT
      LAYER M4 ;
        RECT  64.716 121.968 64.8 121.992 ;
    END
  END bank_e[487]
  PIN bank_e[488]
    DIRECTION INPUT ;
    USE SIGNAL ;
    PORT
      LAYER M4 ;
        RECT  64.716 122.208 64.8 122.232 ;
    END
  END bank_e[488]
  PIN bank_e[489]
    DIRECTION INPUT ;
    USE SIGNAL ;
    PORT
      LAYER M4 ;
        RECT  64.716 122.448 64.8 122.472 ;
    END
  END bank_e[489]
  PIN bank_e[48]
    DIRECTION INPUT ;
    USE SIGNAL ;
    PORT
      LAYER M4 ;
        RECT  64.716 12.624 64.8 12.648 ;
    END
  END bank_e[48]
  PIN bank_e[490]
    DIRECTION INPUT ;
    USE SIGNAL ;
    PORT
      LAYER M4 ;
        RECT  64.716 122.688 64.8 122.712 ;
    END
  END bank_e[490]
  PIN bank_e[491]
    DIRECTION INPUT ;
    USE SIGNAL ;
    PORT
      LAYER M4 ;
        RECT  64.716 122.928 64.8 122.952 ;
    END
  END bank_e[491]
  PIN bank_e[492]
    DIRECTION INPUT ;
    USE SIGNAL ;
    PORT
      LAYER M4 ;
        RECT  64.716 123.216 64.8 123.24 ;
    END
  END bank_e[492]
  PIN bank_e[493]
    DIRECTION INPUT ;
    USE SIGNAL ;
    PORT
      LAYER M4 ;
        RECT  64.716 123.456 64.8 123.48 ;
    END
  END bank_e[493]
  PIN bank_e[494]
    DIRECTION INPUT ;
    USE SIGNAL ;
    PORT
      LAYER M4 ;
        RECT  64.716 123.696 64.8 123.72 ;
    END
  END bank_e[494]
  PIN bank_e[495]
    DIRECTION INPUT ;
    USE SIGNAL ;
    PORT
      LAYER M4 ;
        RECT  64.716 123.936 64.8 123.96 ;
    END
  END bank_e[495]
  PIN bank_e[496]
    DIRECTION INPUT ;
    USE SIGNAL ;
    PORT
      LAYER M4 ;
        RECT  64.716 124.176 64.8 124.2 ;
    END
  END bank_e[496]
  PIN bank_e[497]
    DIRECTION INPUT ;
    USE SIGNAL ;
    PORT
      LAYER M4 ;
        RECT  64.716 124.464 64.8 124.488 ;
    END
  END bank_e[497]
  PIN bank_e[498]
    DIRECTION INPUT ;
    USE SIGNAL ;
    PORT
      LAYER M4 ;
        RECT  64.716 124.704 64.8 124.728 ;
    END
  END bank_e[498]
  PIN bank_e[499]
    DIRECTION INPUT ;
    USE SIGNAL ;
    PORT
      LAYER M4 ;
        RECT  64.716 124.944 64.8 124.968 ;
    END
  END bank_e[499]
  PIN bank_e[49]
    DIRECTION INPUT ;
    USE SIGNAL ;
    PORT
      LAYER M4 ;
        RECT  64.716 12.864 64.8 12.888 ;
    END
  END bank_e[49]
  PIN bank_e[4]
    DIRECTION INPUT ;
    USE SIGNAL ;
    PORT
      LAYER M4 ;
        RECT  64.716 1.632 64.8 1.656 ;
    END
  END bank_e[4]
  PIN bank_e[500]
    DIRECTION INPUT ;
    USE SIGNAL ;
    PORT
      LAYER M4 ;
        RECT  64.716 125.184 64.8 125.208 ;
    END
  END bank_e[500]
  PIN bank_e[501]
    DIRECTION INPUT ;
    USE SIGNAL ;
    PORT
      LAYER M4 ;
        RECT  64.716 125.424 64.8 125.448 ;
    END
  END bank_e[501]
  PIN bank_e[502]
    DIRECTION INPUT ;
    USE SIGNAL ;
    PORT
      LAYER M4 ;
        RECT  64.716 125.664 64.8 125.688 ;
    END
  END bank_e[502]
  PIN bank_e[503]
    DIRECTION INPUT ;
    USE SIGNAL ;
    PORT
      LAYER M4 ;
        RECT  64.716 125.952 64.8 125.976 ;
    END
  END bank_e[503]
  PIN bank_e[504]
    DIRECTION INPUT ;
    USE SIGNAL ;
    PORT
      LAYER M4 ;
        RECT  64.716 126.192 64.8 126.216 ;
    END
  END bank_e[504]
  PIN bank_e[505]
    DIRECTION INPUT ;
    USE SIGNAL ;
    PORT
      LAYER M4 ;
        RECT  64.716 126.432 64.8 126.456 ;
    END
  END bank_e[505]
  PIN bank_e[506]
    DIRECTION INPUT ;
    USE SIGNAL ;
    PORT
      LAYER M4 ;
        RECT  64.716 126.672 64.8 126.696 ;
    END
  END bank_e[506]
  PIN bank_e[507]
    DIRECTION INPUT ;
    USE SIGNAL ;
    PORT
      LAYER M4 ;
        RECT  64.716 126.912 64.8 126.936 ;
    END
  END bank_e[507]
  PIN bank_e[508]
    DIRECTION INPUT ;
    USE SIGNAL ;
    PORT
      LAYER M4 ;
        RECT  64.716 127.2 64.8 127.224 ;
    END
  END bank_e[508]
  PIN bank_e[509]
    DIRECTION INPUT ;
    USE SIGNAL ;
    PORT
      LAYER M4 ;
        RECT  64.716 127.44 64.8 127.464 ;
    END
  END bank_e[509]
  PIN bank_e[50]
    DIRECTION INPUT ;
    USE SIGNAL ;
    PORT
      LAYER M4 ;
        RECT  64.716 13.104 64.8 13.128 ;
    END
  END bank_e[50]
  PIN bank_e[510]
    DIRECTION INPUT ;
    USE SIGNAL ;
    PORT
      LAYER M4 ;
        RECT  64.716 127.68 64.8 127.704 ;
    END
  END bank_e[510]
  PIN bank_e[511]
    DIRECTION INPUT ;
    USE SIGNAL ;
    PORT
      LAYER M4 ;
        RECT  64.716 127.92 64.8 127.944 ;
    END
  END bank_e[511]
  PIN bank_e[512]
    DIRECTION INPUT ;
    USE SIGNAL ;
    PORT
      LAYER M4 ;
        RECT  64.716 128.16 64.8 128.184 ;
    END
  END bank_e[512]
  PIN bank_e[513]
    DIRECTION INPUT ;
    USE SIGNAL ;
    PORT
      LAYER M4 ;
        RECT  64.716 128.448 64.8 128.472 ;
    END
  END bank_e[513]
  PIN bank_e[514]
    DIRECTION INPUT ;
    USE SIGNAL ;
    PORT
      LAYER M4 ;
        RECT  64.716 128.688 64.8 128.712 ;
    END
  END bank_e[514]
  PIN bank_e[515]
    DIRECTION INPUT ;
    USE SIGNAL ;
    PORT
      LAYER M4 ;
        RECT  64.716 128.928 64.8 128.952 ;
    END
  END bank_e[515]
  PIN bank_e[51]
    DIRECTION INPUT ;
    USE SIGNAL ;
    PORT
      LAYER M4 ;
        RECT  64.716 13.344 64.8 13.368 ;
    END
  END bank_e[51]
  PIN bank_e[52]
    DIRECTION INPUT ;
    USE SIGNAL ;
    PORT
      LAYER M4 ;
        RECT  64.716 13.584 64.8 13.608 ;
    END
  END bank_e[52]
  PIN bank_e[53]
    DIRECTION INPUT ;
    USE SIGNAL ;
    PORT
      LAYER M4 ;
        RECT  64.716 13.872 64.8 13.896 ;
    END
  END bank_e[53]
  PIN bank_e[54]
    DIRECTION INPUT ;
    USE SIGNAL ;
    PORT
      LAYER M4 ;
        RECT  64.716 14.112 64.8 14.136 ;
    END
  END bank_e[54]
  PIN bank_e[55]
    DIRECTION INPUT ;
    USE SIGNAL ;
    PORT
      LAYER M4 ;
        RECT  64.716 14.352 64.8 14.376 ;
    END
  END bank_e[55]
  PIN bank_e[56]
    DIRECTION INPUT ;
    USE SIGNAL ;
    PORT
      LAYER M4 ;
        RECT  64.716 14.592 64.8 14.616 ;
    END
  END bank_e[56]
  PIN bank_e[57]
    DIRECTION INPUT ;
    USE SIGNAL ;
    PORT
      LAYER M4 ;
        RECT  64.716 14.832 64.8 14.856 ;
    END
  END bank_e[57]
  PIN bank_e[58]
    DIRECTION INPUT ;
    USE SIGNAL ;
    PORT
      LAYER M4 ;
        RECT  64.716 15.12 64.8 15.144 ;
    END
  END bank_e[58]
  PIN bank_e[59]
    DIRECTION INPUT ;
    USE SIGNAL ;
    PORT
      LAYER M4 ;
        RECT  64.716 15.36 64.8 15.384 ;
    END
  END bank_e[59]
  PIN bank_e[5]
    DIRECTION INPUT ;
    USE SIGNAL ;
    PORT
      LAYER M4 ;
        RECT  64.716 1.92 64.8 1.944 ;
    END
  END bank_e[5]
  PIN bank_e[60]
    DIRECTION INPUT ;
    USE SIGNAL ;
    PORT
      LAYER M4 ;
        RECT  64.716 15.6 64.8 15.624 ;
    END
  END bank_e[60]
  PIN bank_e[61]
    DIRECTION INPUT ;
    USE SIGNAL ;
    PORT
      LAYER M4 ;
        RECT  64.716 15.84 64.8 15.864 ;
    END
  END bank_e[61]
  PIN bank_e[62]
    DIRECTION INPUT ;
    USE SIGNAL ;
    PORT
      LAYER M4 ;
        RECT  64.716 16.08 64.8 16.104 ;
    END
  END bank_e[62]
  PIN bank_e[63]
    DIRECTION INPUT ;
    USE SIGNAL ;
    PORT
      LAYER M4 ;
        RECT  64.716 16.368 64.8 16.392 ;
    END
  END bank_e[63]
  PIN bank_e[64]
    DIRECTION INPUT ;
    USE SIGNAL ;
    PORT
      LAYER M4 ;
        RECT  64.716 16.608 64.8 16.632 ;
    END
  END bank_e[64]
  PIN bank_e[65]
    DIRECTION INPUT ;
    USE SIGNAL ;
    PORT
      LAYER M4 ;
        RECT  64.716 16.848 64.8 16.872 ;
    END
  END bank_e[65]
  PIN bank_e[66]
    DIRECTION INPUT ;
    USE SIGNAL ;
    PORT
      LAYER M4 ;
        RECT  64.716 17.088 64.8 17.112 ;
    END
  END bank_e[66]
  PIN bank_e[67]
    DIRECTION INPUT ;
    USE SIGNAL ;
    PORT
      LAYER M4 ;
        RECT  64.716 17.328 64.8 17.352 ;
    END
  END bank_e[67]
  PIN bank_e[68]
    DIRECTION INPUT ;
    USE SIGNAL ;
    PORT
      LAYER M4 ;
        RECT  64.716 17.568 64.8 17.592 ;
    END
  END bank_e[68]
  PIN bank_e[69]
    DIRECTION INPUT ;
    USE SIGNAL ;
    PORT
      LAYER M4 ;
        RECT  64.716 17.856 64.8 17.88 ;
    END
  END bank_e[69]
  PIN bank_e[6]
    DIRECTION INPUT ;
    USE SIGNAL ;
    PORT
      LAYER M4 ;
        RECT  64.716 2.16 64.8 2.184 ;
    END
  END bank_e[6]
  PIN bank_e[70]
    DIRECTION INPUT ;
    USE SIGNAL ;
    PORT
      LAYER M4 ;
        RECT  64.716 18.096 64.8 18.12 ;
    END
  END bank_e[70]
  PIN bank_e[71]
    DIRECTION INPUT ;
    USE SIGNAL ;
    PORT
      LAYER M4 ;
        RECT  64.716 18.336 64.8 18.36 ;
    END
  END bank_e[71]
  PIN bank_e[72]
    DIRECTION INPUT ;
    USE SIGNAL ;
    PORT
      LAYER M4 ;
        RECT  64.716 18.576 64.8 18.6 ;
    END
  END bank_e[72]
  PIN bank_e[73]
    DIRECTION INPUT ;
    USE SIGNAL ;
    PORT
      LAYER M4 ;
        RECT  64.716 18.816 64.8 18.84 ;
    END
  END bank_e[73]
  PIN bank_e[74]
    DIRECTION INPUT ;
    USE SIGNAL ;
    PORT
      LAYER M4 ;
        RECT  64.716 19.104 64.8 19.128 ;
    END
  END bank_e[74]
  PIN bank_e[75]
    DIRECTION INPUT ;
    USE SIGNAL ;
    PORT
      LAYER M4 ;
        RECT  64.716 19.344 64.8 19.368 ;
    END
  END bank_e[75]
  PIN bank_e[76]
    DIRECTION INPUT ;
    USE SIGNAL ;
    PORT
      LAYER M4 ;
        RECT  64.716 19.584 64.8 19.608 ;
    END
  END bank_e[76]
  PIN bank_e[77]
    DIRECTION INPUT ;
    USE SIGNAL ;
    PORT
      LAYER M4 ;
        RECT  64.716 19.824 64.8 19.848 ;
    END
  END bank_e[77]
  PIN bank_e[78]
    DIRECTION INPUT ;
    USE SIGNAL ;
    PORT
      LAYER M4 ;
        RECT  64.716 20.064 64.8 20.088 ;
    END
  END bank_e[78]
  PIN bank_e[79]
    DIRECTION INPUT ;
    USE SIGNAL ;
    PORT
      LAYER M4 ;
        RECT  64.716 20.352 64.8 20.376 ;
    END
  END bank_e[79]
  PIN bank_e[7]
    DIRECTION INPUT ;
    USE SIGNAL ;
    PORT
      LAYER M4 ;
        RECT  64.716 2.4 64.8 2.424 ;
    END
  END bank_e[7]
  PIN bank_e[80]
    DIRECTION INPUT ;
    USE SIGNAL ;
    PORT
      LAYER M4 ;
        RECT  64.716 20.592 64.8 20.616 ;
    END
  END bank_e[80]
  PIN bank_e[81]
    DIRECTION INPUT ;
    USE SIGNAL ;
    PORT
      LAYER M4 ;
        RECT  64.716 20.832 64.8 20.856 ;
    END
  END bank_e[81]
  PIN bank_e[82]
    DIRECTION INPUT ;
    USE SIGNAL ;
    PORT
      LAYER M4 ;
        RECT  64.716 21.072 64.8 21.096 ;
    END
  END bank_e[82]
  PIN bank_e[83]
    DIRECTION INPUT ;
    USE SIGNAL ;
    PORT
      LAYER M4 ;
        RECT  64.716 21.312 64.8 21.336 ;
    END
  END bank_e[83]
  PIN bank_e[84]
    DIRECTION INPUT ;
    USE SIGNAL ;
    PORT
      LAYER M4 ;
        RECT  64.716 21.552 64.8 21.576 ;
    END
  END bank_e[84]
  PIN bank_e[85]
    DIRECTION INPUT ;
    USE SIGNAL ;
    PORT
      LAYER M4 ;
        RECT  64.716 21.84 64.8 21.864 ;
    END
  END bank_e[85]
  PIN bank_e[86]
    DIRECTION INPUT ;
    USE SIGNAL ;
    PORT
      LAYER M4 ;
        RECT  64.716 22.08 64.8 22.104 ;
    END
  END bank_e[86]
  PIN bank_e[87]
    DIRECTION INPUT ;
    USE SIGNAL ;
    PORT
      LAYER M4 ;
        RECT  64.716 22.32 64.8 22.344 ;
    END
  END bank_e[87]
  PIN bank_e[88]
    DIRECTION INPUT ;
    USE SIGNAL ;
    PORT
      LAYER M4 ;
        RECT  64.716 22.56 64.8 22.584 ;
    END
  END bank_e[88]
  PIN bank_e[89]
    DIRECTION INPUT ;
    USE SIGNAL ;
    PORT
      LAYER M4 ;
        RECT  64.716 22.8 64.8 22.824 ;
    END
  END bank_e[89]
  PIN bank_e[8]
    DIRECTION INPUT ;
    USE SIGNAL ;
    PORT
      LAYER M4 ;
        RECT  64.716 2.64 64.8 2.664 ;
    END
  END bank_e[8]
  PIN bank_e[90]
    DIRECTION INPUT ;
    USE SIGNAL ;
    PORT
      LAYER M4 ;
        RECT  64.716 23.088 64.8 23.112 ;
    END
  END bank_e[90]
  PIN bank_e[91]
    DIRECTION INPUT ;
    USE SIGNAL ;
    PORT
      LAYER M4 ;
        RECT  64.716 23.328 64.8 23.352 ;
    END
  END bank_e[91]
  PIN bank_e[92]
    DIRECTION INPUT ;
    USE SIGNAL ;
    PORT
      LAYER M4 ;
        RECT  64.716 23.568 64.8 23.592 ;
    END
  END bank_e[92]
  PIN bank_e[93]
    DIRECTION INPUT ;
    USE SIGNAL ;
    PORT
      LAYER M4 ;
        RECT  64.716 23.808 64.8 23.832 ;
    END
  END bank_e[93]
  PIN bank_e[94]
    DIRECTION INPUT ;
    USE SIGNAL ;
    PORT
      LAYER M4 ;
        RECT  64.716 24.048 64.8 24.072 ;
    END
  END bank_e[94]
  PIN bank_e[95]
    DIRECTION INPUT ;
    USE SIGNAL ;
    PORT
      LAYER M4 ;
        RECT  64.716 24.336 64.8 24.36 ;
    END
  END bank_e[95]
  PIN bank_e[96]
    DIRECTION INPUT ;
    USE SIGNAL ;
    PORT
      LAYER M4 ;
        RECT  64.716 24.576 64.8 24.6 ;
    END
  END bank_e[96]
  PIN bank_e[97]
    DIRECTION INPUT ;
    USE SIGNAL ;
    PORT
      LAYER M4 ;
        RECT  64.716 24.816 64.8 24.84 ;
    END
  END bank_e[97]
  PIN bank_e[98]
    DIRECTION INPUT ;
    USE SIGNAL ;
    PORT
      LAYER M4 ;
        RECT  64.716 25.056 64.8 25.08 ;
    END
  END bank_e[98]
  PIN bank_e[99]
    DIRECTION INPUT ;
    USE SIGNAL ;
    PORT
      LAYER M4 ;
        RECT  64.716 25.296 64.8 25.32 ;
    END
  END bank_e[99]
  PIN bank_e[9]
    DIRECTION INPUT ;
    USE SIGNAL ;
    PORT
      LAYER M4 ;
        RECT  64.716 2.88 64.8 2.904 ;
    END
  END bank_e[9]
  PIN bank_w[0]
    DIRECTION INPUT ;
    USE SIGNAL ;
    PORT
      LAYER M4 ;
        RECT  0 0.672 0.084 0.696 ;
    END
  END bank_w[0]
  PIN bank_w[100]
    DIRECTION INPUT ;
    USE SIGNAL ;
    PORT
      LAYER M4 ;
        RECT  0 25.584 0.084 25.608 ;
    END
  END bank_w[100]
  PIN bank_w[101]
    DIRECTION INPUT ;
    USE SIGNAL ;
    PORT
      LAYER M4 ;
        RECT  0 25.824 0.084 25.848 ;
    END
  END bank_w[101]
  PIN bank_w[102]
    DIRECTION INPUT ;
    USE SIGNAL ;
    PORT
      LAYER M4 ;
        RECT  0 26.064 0.084 26.088 ;
    END
  END bank_w[102]
  PIN bank_w[103]
    DIRECTION INPUT ;
    USE SIGNAL ;
    PORT
      LAYER M4 ;
        RECT  0 26.304 0.084 26.328 ;
    END
  END bank_w[103]
  PIN bank_w[104]
    DIRECTION INPUT ;
    USE SIGNAL ;
    PORT
      LAYER M4 ;
        RECT  0 26.544 0.084 26.568 ;
    END
  END bank_w[104]
  PIN bank_w[105]
    DIRECTION INPUT ;
    USE SIGNAL ;
    PORT
      LAYER M4 ;
        RECT  0 26.784 0.084 26.808 ;
    END
  END bank_w[105]
  PIN bank_w[106]
    DIRECTION INPUT ;
    USE SIGNAL ;
    PORT
      LAYER M4 ;
        RECT  0 27.072 0.084 27.096 ;
    END
  END bank_w[106]
  PIN bank_w[107]
    DIRECTION INPUT ;
    USE SIGNAL ;
    PORT
      LAYER M4 ;
        RECT  0 27.312 0.084 27.336 ;
    END
  END bank_w[107]
  PIN bank_w[108]
    DIRECTION INPUT ;
    USE SIGNAL ;
    PORT
      LAYER M4 ;
        RECT  0 27.552 0.084 27.576 ;
    END
  END bank_w[108]
  PIN bank_w[109]
    DIRECTION INPUT ;
    USE SIGNAL ;
    PORT
      LAYER M4 ;
        RECT  0 27.792 0.084 27.816 ;
    END
  END bank_w[109]
  PIN bank_w[10]
    DIRECTION INPUT ;
    USE SIGNAL ;
    PORT
      LAYER M4 ;
        RECT  0 3.12 0.084 3.144 ;
    END
  END bank_w[10]
  PIN bank_w[110]
    DIRECTION INPUT ;
    USE SIGNAL ;
    PORT
      LAYER M4 ;
        RECT  0 28.032 0.084 28.056 ;
    END
  END bank_w[110]
  PIN bank_w[111]
    DIRECTION INPUT ;
    USE SIGNAL ;
    PORT
      LAYER M4 ;
        RECT  0 28.32 0.084 28.344 ;
    END
  END bank_w[111]
  PIN bank_w[112]
    DIRECTION INPUT ;
    USE SIGNAL ;
    PORT
      LAYER M4 ;
        RECT  0 28.56 0.084 28.584 ;
    END
  END bank_w[112]
  PIN bank_w[113]
    DIRECTION INPUT ;
    USE SIGNAL ;
    PORT
      LAYER M4 ;
        RECT  0 28.8 0.084 28.824 ;
    END
  END bank_w[113]
  PIN bank_w[114]
    DIRECTION INPUT ;
    USE SIGNAL ;
    PORT
      LAYER M4 ;
        RECT  0 29.04 0.084 29.064 ;
    END
  END bank_w[114]
  PIN bank_w[115]
    DIRECTION INPUT ;
    USE SIGNAL ;
    PORT
      LAYER M4 ;
        RECT  0 29.28 0.084 29.304 ;
    END
  END bank_w[115]
  PIN bank_w[116]
    DIRECTION INPUT ;
    USE SIGNAL ;
    PORT
      LAYER M4 ;
        RECT  0 29.568 0.084 29.592 ;
    END
  END bank_w[116]
  PIN bank_w[117]
    DIRECTION INPUT ;
    USE SIGNAL ;
    PORT
      LAYER M4 ;
        RECT  0 29.808 0.084 29.832 ;
    END
  END bank_w[117]
  PIN bank_w[118]
    DIRECTION INPUT ;
    USE SIGNAL ;
    PORT
      LAYER M4 ;
        RECT  0 30.048 0.084 30.072 ;
    END
  END bank_w[118]
  PIN bank_w[119]
    DIRECTION INPUT ;
    USE SIGNAL ;
    PORT
      LAYER M4 ;
        RECT  0 30.288 0.084 30.312 ;
    END
  END bank_w[119]
  PIN bank_w[11]
    DIRECTION INPUT ;
    USE SIGNAL ;
    PORT
      LAYER M4 ;
        RECT  0 3.408 0.084 3.432 ;
    END
  END bank_w[11]
  PIN bank_w[120]
    DIRECTION INPUT ;
    USE SIGNAL ;
    PORT
      LAYER M4 ;
        RECT  0 30.528 0.084 30.552 ;
    END
  END bank_w[120]
  PIN bank_w[121]
    DIRECTION INPUT ;
    USE SIGNAL ;
    PORT
      LAYER M4 ;
        RECT  0 30.768 0.084 30.792 ;
    END
  END bank_w[121]
  PIN bank_w[122]
    DIRECTION INPUT ;
    USE SIGNAL ;
    PORT
      LAYER M4 ;
        RECT  0 31.056 0.084 31.08 ;
    END
  END bank_w[122]
  PIN bank_w[123]
    DIRECTION INPUT ;
    USE SIGNAL ;
    PORT
      LAYER M4 ;
        RECT  0 31.296 0.084 31.32 ;
    END
  END bank_w[123]
  PIN bank_w[124]
    DIRECTION INPUT ;
    USE SIGNAL ;
    PORT
      LAYER M4 ;
        RECT  0 31.536 0.084 31.56 ;
    END
  END bank_w[124]
  PIN bank_w[125]
    DIRECTION INPUT ;
    USE SIGNAL ;
    PORT
      LAYER M4 ;
        RECT  0 31.776 0.084 31.8 ;
    END
  END bank_w[125]
  PIN bank_w[126]
    DIRECTION INPUT ;
    USE SIGNAL ;
    PORT
      LAYER M4 ;
        RECT  0 32.016 0.084 32.04 ;
    END
  END bank_w[126]
  PIN bank_w[127]
    DIRECTION INPUT ;
    USE SIGNAL ;
    PORT
      LAYER M4 ;
        RECT  0 32.304 0.084 32.328 ;
    END
  END bank_w[127]
  PIN bank_w[128]
    DIRECTION INPUT ;
    USE SIGNAL ;
    PORT
      LAYER M4 ;
        RECT  0 32.544 0.084 32.568 ;
    END
  END bank_w[128]
  PIN bank_w[129]
    DIRECTION INPUT ;
    USE SIGNAL ;
    PORT
      LAYER M4 ;
        RECT  0 32.784 0.084 32.808 ;
    END
  END bank_w[129]
  PIN bank_w[12]
    DIRECTION INPUT ;
    USE SIGNAL ;
    PORT
      LAYER M4 ;
        RECT  0 3.648 0.084 3.672 ;
    END
  END bank_w[12]
  PIN bank_w[130]
    DIRECTION INPUT ;
    USE SIGNAL ;
    PORT
      LAYER M4 ;
        RECT  0 33.024 0.084 33.048 ;
    END
  END bank_w[130]
  PIN bank_w[131]
    DIRECTION INPUT ;
    USE SIGNAL ;
    PORT
      LAYER M4 ;
        RECT  0 33.264 0.084 33.288 ;
    END
  END bank_w[131]
  PIN bank_w[132]
    DIRECTION INPUT ;
    USE SIGNAL ;
    PORT
      LAYER M4 ;
        RECT  0 33.552 0.084 33.576 ;
    END
  END bank_w[132]
  PIN bank_w[133]
    DIRECTION INPUT ;
    USE SIGNAL ;
    PORT
      LAYER M4 ;
        RECT  0 33.792 0.084 33.816 ;
    END
  END bank_w[133]
  PIN bank_w[134]
    DIRECTION INPUT ;
    USE SIGNAL ;
    PORT
      LAYER M4 ;
        RECT  0 34.032 0.084 34.056 ;
    END
  END bank_w[134]
  PIN bank_w[135]
    DIRECTION INPUT ;
    USE SIGNAL ;
    PORT
      LAYER M4 ;
        RECT  0 34.272 0.084 34.296 ;
    END
  END bank_w[135]
  PIN bank_w[136]
    DIRECTION INPUT ;
    USE SIGNAL ;
    PORT
      LAYER M4 ;
        RECT  0 34.512 0.084 34.536 ;
    END
  END bank_w[136]
  PIN bank_w[137]
    DIRECTION INPUT ;
    USE SIGNAL ;
    PORT
      LAYER M4 ;
        RECT  0 34.752 0.084 34.776 ;
    END
  END bank_w[137]
  PIN bank_w[138]
    DIRECTION INPUT ;
    USE SIGNAL ;
    PORT
      LAYER M4 ;
        RECT  0 35.04 0.084 35.064 ;
    END
  END bank_w[138]
  PIN bank_w[139]
    DIRECTION INPUT ;
    USE SIGNAL ;
    PORT
      LAYER M4 ;
        RECT  0 35.28 0.084 35.304 ;
    END
  END bank_w[139]
  PIN bank_w[13]
    DIRECTION INPUT ;
    USE SIGNAL ;
    PORT
      LAYER M4 ;
        RECT  0 3.888 0.084 3.912 ;
    END
  END bank_w[13]
  PIN bank_w[140]
    DIRECTION INPUT ;
    USE SIGNAL ;
    PORT
      LAYER M4 ;
        RECT  0 35.52 0.084 35.544 ;
    END
  END bank_w[140]
  PIN bank_w[141]
    DIRECTION INPUT ;
    USE SIGNAL ;
    PORT
      LAYER M4 ;
        RECT  0 35.76 0.084 35.784 ;
    END
  END bank_w[141]
  PIN bank_w[142]
    DIRECTION INPUT ;
    USE SIGNAL ;
    PORT
      LAYER M4 ;
        RECT  0 36 0.084 36.024 ;
    END
  END bank_w[142]
  PIN bank_w[143]
    DIRECTION INPUT ;
    USE SIGNAL ;
    PORT
      LAYER M4 ;
        RECT  0 36.288 0.084 36.312 ;
    END
  END bank_w[143]
  PIN bank_w[144]
    DIRECTION INPUT ;
    USE SIGNAL ;
    PORT
      LAYER M4 ;
        RECT  0 36.528 0.084 36.552 ;
    END
  END bank_w[144]
  PIN bank_w[145]
    DIRECTION INPUT ;
    USE SIGNAL ;
    PORT
      LAYER M4 ;
        RECT  0 36.768 0.084 36.792 ;
    END
  END bank_w[145]
  PIN bank_w[146]
    DIRECTION INPUT ;
    USE SIGNAL ;
    PORT
      LAYER M4 ;
        RECT  0 37.008 0.084 37.032 ;
    END
  END bank_w[146]
  PIN bank_w[147]
    DIRECTION INPUT ;
    USE SIGNAL ;
    PORT
      LAYER M4 ;
        RECT  0 37.248 0.084 37.272 ;
    END
  END bank_w[147]
  PIN bank_w[148]
    DIRECTION INPUT ;
    USE SIGNAL ;
    PORT
      LAYER M4 ;
        RECT  0 37.536 0.084 37.56 ;
    END
  END bank_w[148]
  PIN bank_w[149]
    DIRECTION INPUT ;
    USE SIGNAL ;
    PORT
      LAYER M4 ;
        RECT  0 37.776 0.084 37.8 ;
    END
  END bank_w[149]
  PIN bank_w[14]
    DIRECTION INPUT ;
    USE SIGNAL ;
    PORT
      LAYER M4 ;
        RECT  0 4.128 0.084 4.152 ;
    END
  END bank_w[14]
  PIN bank_w[150]
    DIRECTION INPUT ;
    USE SIGNAL ;
    PORT
      LAYER M4 ;
        RECT  0 38.016 0.084 38.04 ;
    END
  END bank_w[150]
  PIN bank_w[151]
    DIRECTION INPUT ;
    USE SIGNAL ;
    PORT
      LAYER M4 ;
        RECT  0 38.256 0.084 38.28 ;
    END
  END bank_w[151]
  PIN bank_w[152]
    DIRECTION INPUT ;
    USE SIGNAL ;
    PORT
      LAYER M4 ;
        RECT  0 38.496 0.084 38.52 ;
    END
  END bank_w[152]
  PIN bank_w[153]
    DIRECTION INPUT ;
    USE SIGNAL ;
    PORT
      LAYER M4 ;
        RECT  0 38.784 0.084 38.808 ;
    END
  END bank_w[153]
  PIN bank_w[154]
    DIRECTION INPUT ;
    USE SIGNAL ;
    PORT
      LAYER M4 ;
        RECT  0 39.024 0.084 39.048 ;
    END
  END bank_w[154]
  PIN bank_w[155]
    DIRECTION INPUT ;
    USE SIGNAL ;
    PORT
      LAYER M4 ;
        RECT  0 39.264 0.084 39.288 ;
    END
  END bank_w[155]
  PIN bank_w[156]
    DIRECTION INPUT ;
    USE SIGNAL ;
    PORT
      LAYER M4 ;
        RECT  0 39.504 0.084 39.528 ;
    END
  END bank_w[156]
  PIN bank_w[157]
    DIRECTION INPUT ;
    USE SIGNAL ;
    PORT
      LAYER M4 ;
        RECT  0 39.744 0.084 39.768 ;
    END
  END bank_w[157]
  PIN bank_w[158]
    DIRECTION INPUT ;
    USE SIGNAL ;
    PORT
      LAYER M4 ;
        RECT  0 39.984 0.084 40.008 ;
    END
  END bank_w[158]
  PIN bank_w[159]
    DIRECTION INPUT ;
    USE SIGNAL ;
    PORT
      LAYER M4 ;
        RECT  0 40.272 0.084 40.296 ;
    END
  END bank_w[159]
  PIN bank_w[15]
    DIRECTION INPUT ;
    USE SIGNAL ;
    PORT
      LAYER M4 ;
        RECT  0 4.368 0.084 4.392 ;
    END
  END bank_w[15]
  PIN bank_w[160]
    DIRECTION INPUT ;
    USE SIGNAL ;
    PORT
      LAYER M4 ;
        RECT  0 40.512 0.084 40.536 ;
    END
  END bank_w[160]
  PIN bank_w[161]
    DIRECTION INPUT ;
    USE SIGNAL ;
    PORT
      LAYER M4 ;
        RECT  0 40.752 0.084 40.776 ;
    END
  END bank_w[161]
  PIN bank_w[162]
    DIRECTION INPUT ;
    USE SIGNAL ;
    PORT
      LAYER M4 ;
        RECT  0 40.992 0.084 41.016 ;
    END
  END bank_w[162]
  PIN bank_w[163]
    DIRECTION INPUT ;
    USE SIGNAL ;
    PORT
      LAYER M4 ;
        RECT  0 41.232 0.084 41.256 ;
    END
  END bank_w[163]
  PIN bank_w[164]
    DIRECTION INPUT ;
    USE SIGNAL ;
    PORT
      LAYER M4 ;
        RECT  0 41.52 0.084 41.544 ;
    END
  END bank_w[164]
  PIN bank_w[165]
    DIRECTION INPUT ;
    USE SIGNAL ;
    PORT
      LAYER M4 ;
        RECT  0 41.76 0.084 41.784 ;
    END
  END bank_w[165]
  PIN bank_w[166]
    DIRECTION INPUT ;
    USE SIGNAL ;
    PORT
      LAYER M4 ;
        RECT  0 42 0.084 42.024 ;
    END
  END bank_w[166]
  PIN bank_w[167]
    DIRECTION INPUT ;
    USE SIGNAL ;
    PORT
      LAYER M4 ;
        RECT  0 42.24 0.084 42.264 ;
    END
  END bank_w[167]
  PIN bank_w[168]
    DIRECTION INPUT ;
    USE SIGNAL ;
    PORT
      LAYER M4 ;
        RECT  0 42.48 0.084 42.504 ;
    END
  END bank_w[168]
  PIN bank_w[169]
    DIRECTION INPUT ;
    USE SIGNAL ;
    PORT
      LAYER M4 ;
        RECT  0 42.768 0.084 42.792 ;
    END
  END bank_w[169]
  PIN bank_w[16]
    DIRECTION INPUT ;
    USE SIGNAL ;
    PORT
      LAYER M4 ;
        RECT  0 4.656 0.084 4.68 ;
    END
  END bank_w[16]
  PIN bank_w[170]
    DIRECTION INPUT ;
    USE SIGNAL ;
    PORT
      LAYER M4 ;
        RECT  0 43.008 0.084 43.032 ;
    END
  END bank_w[170]
  PIN bank_w[171]
    DIRECTION INPUT ;
    USE SIGNAL ;
    PORT
      LAYER M4 ;
        RECT  0 43.248 0.084 43.272 ;
    END
  END bank_w[171]
  PIN bank_w[172]
    DIRECTION INPUT ;
    USE SIGNAL ;
    PORT
      LAYER M4 ;
        RECT  0 43.488 0.084 43.512 ;
    END
  END bank_w[172]
  PIN bank_w[173]
    DIRECTION INPUT ;
    USE SIGNAL ;
    PORT
      LAYER M4 ;
        RECT  0 43.728 0.084 43.752 ;
    END
  END bank_w[173]
  PIN bank_w[174]
    DIRECTION INPUT ;
    USE SIGNAL ;
    PORT
      LAYER M4 ;
        RECT  0 43.968 0.084 43.992 ;
    END
  END bank_w[174]
  PIN bank_w[175]
    DIRECTION INPUT ;
    USE SIGNAL ;
    PORT
      LAYER M4 ;
        RECT  0 44.256 0.084 44.28 ;
    END
  END bank_w[175]
  PIN bank_w[176]
    DIRECTION INPUT ;
    USE SIGNAL ;
    PORT
      LAYER M4 ;
        RECT  0 44.496 0.084 44.52 ;
    END
  END bank_w[176]
  PIN bank_w[177]
    DIRECTION INPUT ;
    USE SIGNAL ;
    PORT
      LAYER M4 ;
        RECT  0 44.736 0.084 44.76 ;
    END
  END bank_w[177]
  PIN bank_w[178]
    DIRECTION INPUT ;
    USE SIGNAL ;
    PORT
      LAYER M4 ;
        RECT  0 44.976 0.084 45 ;
    END
  END bank_w[178]
  PIN bank_w[179]
    DIRECTION INPUT ;
    USE SIGNAL ;
    PORT
      LAYER M4 ;
        RECT  0 45.216 0.084 45.24 ;
    END
  END bank_w[179]
  PIN bank_w[17]
    DIRECTION INPUT ;
    USE SIGNAL ;
    PORT
      LAYER M4 ;
        RECT  0 4.896 0.084 4.92 ;
    END
  END bank_w[17]
  PIN bank_w[180]
    DIRECTION INPUT ;
    USE SIGNAL ;
    PORT
      LAYER M4 ;
        RECT  0 45.504 0.084 45.528 ;
    END
  END bank_w[180]
  PIN bank_w[181]
    DIRECTION INPUT ;
    USE SIGNAL ;
    PORT
      LAYER M4 ;
        RECT  0 45.744 0.084 45.768 ;
    END
  END bank_w[181]
  PIN bank_w[182]
    DIRECTION INPUT ;
    USE SIGNAL ;
    PORT
      LAYER M4 ;
        RECT  0 45.984 0.084 46.008 ;
    END
  END bank_w[182]
  PIN bank_w[183]
    DIRECTION INPUT ;
    USE SIGNAL ;
    PORT
      LAYER M4 ;
        RECT  0 46.224 0.084 46.248 ;
    END
  END bank_w[183]
  PIN bank_w[184]
    DIRECTION INPUT ;
    USE SIGNAL ;
    PORT
      LAYER M4 ;
        RECT  0 46.464 0.084 46.488 ;
    END
  END bank_w[184]
  PIN bank_w[185]
    DIRECTION INPUT ;
    USE SIGNAL ;
    PORT
      LAYER M4 ;
        RECT  0 46.752 0.084 46.776 ;
    END
  END bank_w[185]
  PIN bank_w[186]
    DIRECTION INPUT ;
    USE SIGNAL ;
    PORT
      LAYER M4 ;
        RECT  0 46.992 0.084 47.016 ;
    END
  END bank_w[186]
  PIN bank_w[187]
    DIRECTION INPUT ;
    USE SIGNAL ;
    PORT
      LAYER M4 ;
        RECT  0 47.232 0.084 47.256 ;
    END
  END bank_w[187]
  PIN bank_w[188]
    DIRECTION INPUT ;
    USE SIGNAL ;
    PORT
      LAYER M4 ;
        RECT  0 47.472 0.084 47.496 ;
    END
  END bank_w[188]
  PIN bank_w[189]
    DIRECTION INPUT ;
    USE SIGNAL ;
    PORT
      LAYER M4 ;
        RECT  0 47.712 0.084 47.736 ;
    END
  END bank_w[189]
  PIN bank_w[18]
    DIRECTION INPUT ;
    USE SIGNAL ;
    PORT
      LAYER M4 ;
        RECT  0 5.136 0.084 5.16 ;
    END
  END bank_w[18]
  PIN bank_w[190]
    DIRECTION INPUT ;
    USE SIGNAL ;
    PORT
      LAYER M4 ;
        RECT  0 48 0.084 48.024 ;
    END
  END bank_w[190]
  PIN bank_w[191]
    DIRECTION INPUT ;
    USE SIGNAL ;
    PORT
      LAYER M4 ;
        RECT  0 48.24 0.084 48.264 ;
    END
  END bank_w[191]
  PIN bank_w[192]
    DIRECTION INPUT ;
    USE SIGNAL ;
    PORT
      LAYER M4 ;
        RECT  0 48.48 0.084 48.504 ;
    END
  END bank_w[192]
  PIN bank_w[193]
    DIRECTION INPUT ;
    USE SIGNAL ;
    PORT
      LAYER M4 ;
        RECT  0 48.72 0.084 48.744 ;
    END
  END bank_w[193]
  PIN bank_w[194]
    DIRECTION INPUT ;
    USE SIGNAL ;
    PORT
      LAYER M4 ;
        RECT  0 48.96 0.084 48.984 ;
    END
  END bank_w[194]
  PIN bank_w[195]
    DIRECTION INPUT ;
    USE SIGNAL ;
    PORT
      LAYER M4 ;
        RECT  0 49.2 0.084 49.224 ;
    END
  END bank_w[195]
  PIN bank_w[196]
    DIRECTION INPUT ;
    USE SIGNAL ;
    PORT
      LAYER M4 ;
        RECT  0 49.488 0.084 49.512 ;
    END
  END bank_w[196]
  PIN bank_w[197]
    DIRECTION INPUT ;
    USE SIGNAL ;
    PORT
      LAYER M4 ;
        RECT  0 49.728 0.084 49.752 ;
    END
  END bank_w[197]
  PIN bank_w[198]
    DIRECTION INPUT ;
    USE SIGNAL ;
    PORT
      LAYER M4 ;
        RECT  0 49.968 0.084 49.992 ;
    END
  END bank_w[198]
  PIN bank_w[199]
    DIRECTION INPUT ;
    USE SIGNAL ;
    PORT
      LAYER M4 ;
        RECT  0 50.208 0.084 50.232 ;
    END
  END bank_w[199]
  PIN bank_w[19]
    DIRECTION INPUT ;
    USE SIGNAL ;
    PORT
      LAYER M4 ;
        RECT  0 5.376 0.084 5.4 ;
    END
  END bank_w[19]
  PIN bank_w[1]
    DIRECTION INPUT ;
    USE SIGNAL ;
    PORT
      LAYER M4 ;
        RECT  0 0.912 0.084 0.936 ;
    END
  END bank_w[1]
  PIN bank_w[200]
    DIRECTION INPUT ;
    USE SIGNAL ;
    PORT
      LAYER M4 ;
        RECT  0 50.448 0.084 50.472 ;
    END
  END bank_w[200]
  PIN bank_w[201]
    DIRECTION INPUT ;
    USE SIGNAL ;
    PORT
      LAYER M4 ;
        RECT  0 50.736 0.084 50.76 ;
    END
  END bank_w[201]
  PIN bank_w[202]
    DIRECTION INPUT ;
    USE SIGNAL ;
    PORT
      LAYER M4 ;
        RECT  0 50.976 0.084 51 ;
    END
  END bank_w[202]
  PIN bank_w[203]
    DIRECTION INPUT ;
    USE SIGNAL ;
    PORT
      LAYER M4 ;
        RECT  0 51.216 0.084 51.24 ;
    END
  END bank_w[203]
  PIN bank_w[204]
    DIRECTION INPUT ;
    USE SIGNAL ;
    PORT
      LAYER M4 ;
        RECT  0 51.456 0.084 51.48 ;
    END
  END bank_w[204]
  PIN bank_w[205]
    DIRECTION INPUT ;
    USE SIGNAL ;
    PORT
      LAYER M4 ;
        RECT  0 51.696 0.084 51.72 ;
    END
  END bank_w[205]
  PIN bank_w[206]
    DIRECTION INPUT ;
    USE SIGNAL ;
    PORT
      LAYER M4 ;
        RECT  0 51.984 0.084 52.008 ;
    END
  END bank_w[206]
  PIN bank_w[207]
    DIRECTION INPUT ;
    USE SIGNAL ;
    PORT
      LAYER M4 ;
        RECT  0 52.224 0.084 52.248 ;
    END
  END bank_w[207]
  PIN bank_w[208]
    DIRECTION INPUT ;
    USE SIGNAL ;
    PORT
      LAYER M4 ;
        RECT  0 52.464 0.084 52.488 ;
    END
  END bank_w[208]
  PIN bank_w[209]
    DIRECTION INPUT ;
    USE SIGNAL ;
    PORT
      LAYER M4 ;
        RECT  0 52.704 0.084 52.728 ;
    END
  END bank_w[209]
  PIN bank_w[20]
    DIRECTION INPUT ;
    USE SIGNAL ;
    PORT
      LAYER M4 ;
        RECT  0 5.616 0.084 5.64 ;
    END
  END bank_w[20]
  PIN bank_w[210]
    DIRECTION INPUT ;
    USE SIGNAL ;
    PORT
      LAYER M4 ;
        RECT  0 52.944 0.084 52.968 ;
    END
  END bank_w[210]
  PIN bank_w[211]
    DIRECTION INPUT ;
    USE SIGNAL ;
    PORT
      LAYER M4 ;
        RECT  0 53.184 0.084 53.208 ;
    END
  END bank_w[211]
  PIN bank_w[212]
    DIRECTION INPUT ;
    USE SIGNAL ;
    PORT
      LAYER M4 ;
        RECT  0 53.472 0.084 53.496 ;
    END
  END bank_w[212]
  PIN bank_w[213]
    DIRECTION INPUT ;
    USE SIGNAL ;
    PORT
      LAYER M4 ;
        RECT  0 53.712 0.084 53.736 ;
    END
  END bank_w[213]
  PIN bank_w[214]
    DIRECTION INPUT ;
    USE SIGNAL ;
    PORT
      LAYER M4 ;
        RECT  0 53.952 0.084 53.976 ;
    END
  END bank_w[214]
  PIN bank_w[215]
    DIRECTION INPUT ;
    USE SIGNAL ;
    PORT
      LAYER M4 ;
        RECT  0 54.192 0.084 54.216 ;
    END
  END bank_w[215]
  PIN bank_w[216]
    DIRECTION INPUT ;
    USE SIGNAL ;
    PORT
      LAYER M4 ;
        RECT  0 54.432 0.084 54.456 ;
    END
  END bank_w[216]
  PIN bank_w[217]
    DIRECTION INPUT ;
    USE SIGNAL ;
    PORT
      LAYER M4 ;
        RECT  0 54.72 0.084 54.744 ;
    END
  END bank_w[217]
  PIN bank_w[218]
    DIRECTION INPUT ;
    USE SIGNAL ;
    PORT
      LAYER M4 ;
        RECT  0 54.96 0.084 54.984 ;
    END
  END bank_w[218]
  PIN bank_w[219]
    DIRECTION INPUT ;
    USE SIGNAL ;
    PORT
      LAYER M4 ;
        RECT  0 55.2 0.084 55.224 ;
    END
  END bank_w[219]
  PIN bank_w[21]
    DIRECTION INPUT ;
    USE SIGNAL ;
    PORT
      LAYER M4 ;
        RECT  0 5.904 0.084 5.928 ;
    END
  END bank_w[21]
  PIN bank_w[220]
    DIRECTION INPUT ;
    USE SIGNAL ;
    PORT
      LAYER M4 ;
        RECT  0 55.44 0.084 55.464 ;
    END
  END bank_w[220]
  PIN bank_w[221]
    DIRECTION INPUT ;
    USE SIGNAL ;
    PORT
      LAYER M4 ;
        RECT  0 55.68 0.084 55.704 ;
    END
  END bank_w[221]
  PIN bank_w[222]
    DIRECTION INPUT ;
    USE SIGNAL ;
    PORT
      LAYER M4 ;
        RECT  0 55.968 0.084 55.992 ;
    END
  END bank_w[222]
  PIN bank_w[223]
    DIRECTION INPUT ;
    USE SIGNAL ;
    PORT
      LAYER M4 ;
        RECT  0 56.208 0.084 56.232 ;
    END
  END bank_w[223]
  PIN bank_w[224]
    DIRECTION INPUT ;
    USE SIGNAL ;
    PORT
      LAYER M4 ;
        RECT  0 56.448 0.084 56.472 ;
    END
  END bank_w[224]
  PIN bank_w[225]
    DIRECTION INPUT ;
    USE SIGNAL ;
    PORT
      LAYER M4 ;
        RECT  0 56.688 0.084 56.712 ;
    END
  END bank_w[225]
  PIN bank_w[226]
    DIRECTION INPUT ;
    USE SIGNAL ;
    PORT
      LAYER M4 ;
        RECT  0 56.928 0.084 56.952 ;
    END
  END bank_w[226]
  PIN bank_w[227]
    DIRECTION INPUT ;
    USE SIGNAL ;
    PORT
      LAYER M4 ;
        RECT  0 57.168 0.084 57.192 ;
    END
  END bank_w[227]
  PIN bank_w[228]
    DIRECTION INPUT ;
    USE SIGNAL ;
    PORT
      LAYER M4 ;
        RECT  0 57.456 0.084 57.48 ;
    END
  END bank_w[228]
  PIN bank_w[229]
    DIRECTION INPUT ;
    USE SIGNAL ;
    PORT
      LAYER M4 ;
        RECT  0 57.696 0.084 57.72 ;
    END
  END bank_w[229]
  PIN bank_w[22]
    DIRECTION INPUT ;
    USE SIGNAL ;
    PORT
      LAYER M4 ;
        RECT  0 6.144 0.084 6.168 ;
    END
  END bank_w[22]
  PIN bank_w[230]
    DIRECTION INPUT ;
    USE SIGNAL ;
    PORT
      LAYER M4 ;
        RECT  0 57.936 0.084 57.96 ;
    END
  END bank_w[230]
  PIN bank_w[231]
    DIRECTION INPUT ;
    USE SIGNAL ;
    PORT
      LAYER M4 ;
        RECT  0 58.176 0.084 58.2 ;
    END
  END bank_w[231]
  PIN bank_w[232]
    DIRECTION INPUT ;
    USE SIGNAL ;
    PORT
      LAYER M4 ;
        RECT  0 58.416 0.084 58.44 ;
    END
  END bank_w[232]
  PIN bank_w[233]
    DIRECTION INPUT ;
    USE SIGNAL ;
    PORT
      LAYER M4 ;
        RECT  0 58.704 0.084 58.728 ;
    END
  END bank_w[233]
  PIN bank_w[234]
    DIRECTION INPUT ;
    USE SIGNAL ;
    PORT
      LAYER M4 ;
        RECT  0 58.944 0.084 58.968 ;
    END
  END bank_w[234]
  PIN bank_w[235]
    DIRECTION INPUT ;
    USE SIGNAL ;
    PORT
      LAYER M4 ;
        RECT  0 59.184 0.084 59.208 ;
    END
  END bank_w[235]
  PIN bank_w[236]
    DIRECTION INPUT ;
    USE SIGNAL ;
    PORT
      LAYER M4 ;
        RECT  0 59.424 0.084 59.448 ;
    END
  END bank_w[236]
  PIN bank_w[237]
    DIRECTION INPUT ;
    USE SIGNAL ;
    PORT
      LAYER M4 ;
        RECT  0 59.664 0.084 59.688 ;
    END
  END bank_w[237]
  PIN bank_w[238]
    DIRECTION INPUT ;
    USE SIGNAL ;
    PORT
      LAYER M4 ;
        RECT  0 59.952 0.084 59.976 ;
    END
  END bank_w[238]
  PIN bank_w[239]
    DIRECTION INPUT ;
    USE SIGNAL ;
    PORT
      LAYER M4 ;
        RECT  0 60.192 0.084 60.216 ;
    END
  END bank_w[239]
  PIN bank_w[23]
    DIRECTION INPUT ;
    USE SIGNAL ;
    PORT
      LAYER M4 ;
        RECT  0 6.384 0.084 6.408 ;
    END
  END bank_w[23]
  PIN bank_w[240]
    DIRECTION INPUT ;
    USE SIGNAL ;
    PORT
      LAYER M4 ;
        RECT  0 60.432 0.084 60.456 ;
    END
  END bank_w[240]
  PIN bank_w[241]
    DIRECTION INPUT ;
    USE SIGNAL ;
    PORT
      LAYER M4 ;
        RECT  0 60.672 0.084 60.696 ;
    END
  END bank_w[241]
  PIN bank_w[242]
    DIRECTION INPUT ;
    USE SIGNAL ;
    PORT
      LAYER M4 ;
        RECT  0 60.912 0.084 60.936 ;
    END
  END bank_w[242]
  PIN bank_w[243]
    DIRECTION INPUT ;
    USE SIGNAL ;
    PORT
      LAYER M4 ;
        RECT  0 61.2 0.084 61.224 ;
    END
  END bank_w[243]
  PIN bank_w[244]
    DIRECTION INPUT ;
    USE SIGNAL ;
    PORT
      LAYER M4 ;
        RECT  0 61.44 0.084 61.464 ;
    END
  END bank_w[244]
  PIN bank_w[245]
    DIRECTION INPUT ;
    USE SIGNAL ;
    PORT
      LAYER M4 ;
        RECT  0 61.68 0.084 61.704 ;
    END
  END bank_w[245]
  PIN bank_w[246]
    DIRECTION INPUT ;
    USE SIGNAL ;
    PORT
      LAYER M4 ;
        RECT  0 61.92 0.084 61.944 ;
    END
  END bank_w[246]
  PIN bank_w[247]
    DIRECTION INPUT ;
    USE SIGNAL ;
    PORT
      LAYER M4 ;
        RECT  0 62.16 0.084 62.184 ;
    END
  END bank_w[247]
  PIN bank_w[248]
    DIRECTION INPUT ;
    USE SIGNAL ;
    PORT
      LAYER M4 ;
        RECT  0 62.4 0.084 62.424 ;
    END
  END bank_w[248]
  PIN bank_w[249]
    DIRECTION INPUT ;
    USE SIGNAL ;
    PORT
      LAYER M4 ;
        RECT  0 62.688 0.084 62.712 ;
    END
  END bank_w[249]
  PIN bank_w[24]
    DIRECTION INPUT ;
    USE SIGNAL ;
    PORT
      LAYER M4 ;
        RECT  0 6.624 0.084 6.648 ;
    END
  END bank_w[24]
  PIN bank_w[250]
    DIRECTION INPUT ;
    USE SIGNAL ;
    PORT
      LAYER M4 ;
        RECT  0 62.928 0.084 62.952 ;
    END
  END bank_w[250]
  PIN bank_w[251]
    DIRECTION INPUT ;
    USE SIGNAL ;
    PORT
      LAYER M4 ;
        RECT  0 63.168 0.084 63.192 ;
    END
  END bank_w[251]
  PIN bank_w[252]
    DIRECTION INPUT ;
    USE SIGNAL ;
    PORT
      LAYER M4 ;
        RECT  0 63.408 0.084 63.432 ;
    END
  END bank_w[252]
  PIN bank_w[253]
    DIRECTION INPUT ;
    USE SIGNAL ;
    PORT
      LAYER M4 ;
        RECT  0 63.648 0.084 63.672 ;
    END
  END bank_w[253]
  PIN bank_w[254]
    DIRECTION INPUT ;
    USE SIGNAL ;
    PORT
      LAYER M4 ;
        RECT  0 63.936 0.084 63.96 ;
    END
  END bank_w[254]
  PIN bank_w[255]
    DIRECTION INPUT ;
    USE SIGNAL ;
    PORT
      LAYER M4 ;
        RECT  0 64.176 0.084 64.2 ;
    END
  END bank_w[255]
  PIN bank_w[256]
    DIRECTION INPUT ;
    USE SIGNAL ;
    PORT
      LAYER M4 ;
        RECT  0 64.416 0.084 64.44 ;
    END
  END bank_w[256]
  PIN bank_w[257]
    DIRECTION INPUT ;
    USE SIGNAL ;
    PORT
      LAYER M4 ;
        RECT  0 64.656 0.084 64.68 ;
    END
  END bank_w[257]
  PIN bank_w[258]
    DIRECTION INPUT ;
    USE SIGNAL ;
    PORT
      LAYER M4 ;
        RECT  0 64.896 0.084 64.92 ;
    END
  END bank_w[258]
  PIN bank_w[259]
    DIRECTION INPUT ;
    USE SIGNAL ;
    PORT
      LAYER M4 ;
        RECT  0 65.184 0.084 65.208 ;
    END
  END bank_w[259]
  PIN bank_w[25]
    DIRECTION INPUT ;
    USE SIGNAL ;
    PORT
      LAYER M4 ;
        RECT  0 6.864 0.084 6.888 ;
    END
  END bank_w[25]
  PIN bank_w[260]
    DIRECTION INPUT ;
    USE SIGNAL ;
    PORT
      LAYER M4 ;
        RECT  0 65.424 0.084 65.448 ;
    END
  END bank_w[260]
  PIN bank_w[261]
    DIRECTION INPUT ;
    USE SIGNAL ;
    PORT
      LAYER M4 ;
        RECT  0 65.664 0.084 65.688 ;
    END
  END bank_w[261]
  PIN bank_w[262]
    DIRECTION INPUT ;
    USE SIGNAL ;
    PORT
      LAYER M4 ;
        RECT  0 65.904 0.084 65.928 ;
    END
  END bank_w[262]
  PIN bank_w[263]
    DIRECTION INPUT ;
    USE SIGNAL ;
    PORT
      LAYER M4 ;
        RECT  0 66.144 0.084 66.168 ;
    END
  END bank_w[263]
  PIN bank_w[264]
    DIRECTION INPUT ;
    USE SIGNAL ;
    PORT
      LAYER M4 ;
        RECT  0 66.384 0.084 66.408 ;
    END
  END bank_w[264]
  PIN bank_w[265]
    DIRECTION INPUT ;
    USE SIGNAL ;
    PORT
      LAYER M4 ;
        RECT  0 66.672 0.084 66.696 ;
    END
  END bank_w[265]
  PIN bank_w[266]
    DIRECTION INPUT ;
    USE SIGNAL ;
    PORT
      LAYER M4 ;
        RECT  0 66.912 0.084 66.936 ;
    END
  END bank_w[266]
  PIN bank_w[267]
    DIRECTION INPUT ;
    USE SIGNAL ;
    PORT
      LAYER M4 ;
        RECT  0 67.152 0.084 67.176 ;
    END
  END bank_w[267]
  PIN bank_w[268]
    DIRECTION INPUT ;
    USE SIGNAL ;
    PORT
      LAYER M4 ;
        RECT  0 67.392 0.084 67.416 ;
    END
  END bank_w[268]
  PIN bank_w[269]
    DIRECTION INPUT ;
    USE SIGNAL ;
    PORT
      LAYER M4 ;
        RECT  0 67.632 0.084 67.656 ;
    END
  END bank_w[269]
  PIN bank_w[26]
    DIRECTION INPUT ;
    USE SIGNAL ;
    PORT
      LAYER M4 ;
        RECT  0 7.152 0.084 7.176 ;
    END
  END bank_w[26]
  PIN bank_w[270]
    DIRECTION INPUT ;
    USE SIGNAL ;
    PORT
      LAYER M4 ;
        RECT  0 67.92 0.084 67.944 ;
    END
  END bank_w[270]
  PIN bank_w[271]
    DIRECTION INPUT ;
    USE SIGNAL ;
    PORT
      LAYER M4 ;
        RECT  0 68.16 0.084 68.184 ;
    END
  END bank_w[271]
  PIN bank_w[272]
    DIRECTION INPUT ;
    USE SIGNAL ;
    PORT
      LAYER M4 ;
        RECT  0 68.4 0.084 68.424 ;
    END
  END bank_w[272]
  PIN bank_w[273]
    DIRECTION INPUT ;
    USE SIGNAL ;
    PORT
      LAYER M4 ;
        RECT  0 68.64 0.084 68.664 ;
    END
  END bank_w[273]
  PIN bank_w[274]
    DIRECTION INPUT ;
    USE SIGNAL ;
    PORT
      LAYER M4 ;
        RECT  0 68.88 0.084 68.904 ;
    END
  END bank_w[274]
  PIN bank_w[275]
    DIRECTION INPUT ;
    USE SIGNAL ;
    PORT
      LAYER M4 ;
        RECT  0 69.168 0.084 69.192 ;
    END
  END bank_w[275]
  PIN bank_w[276]
    DIRECTION INPUT ;
    USE SIGNAL ;
    PORT
      LAYER M4 ;
        RECT  0 69.408 0.084 69.432 ;
    END
  END bank_w[276]
  PIN bank_w[277]
    DIRECTION INPUT ;
    USE SIGNAL ;
    PORT
      LAYER M4 ;
        RECT  0 69.648 0.084 69.672 ;
    END
  END bank_w[277]
  PIN bank_w[278]
    DIRECTION INPUT ;
    USE SIGNAL ;
    PORT
      LAYER M4 ;
        RECT  0 69.888 0.084 69.912 ;
    END
  END bank_w[278]
  PIN bank_w[279]
    DIRECTION INPUT ;
    USE SIGNAL ;
    PORT
      LAYER M4 ;
        RECT  0 70.128 0.084 70.152 ;
    END
  END bank_w[279]
  PIN bank_w[27]
    DIRECTION INPUT ;
    USE SIGNAL ;
    PORT
      LAYER M4 ;
        RECT  0 7.392 0.084 7.416 ;
    END
  END bank_w[27]
  PIN bank_w[280]
    DIRECTION INPUT ;
    USE SIGNAL ;
    PORT
      LAYER M4 ;
        RECT  0 70.416 0.084 70.44 ;
    END
  END bank_w[280]
  PIN bank_w[281]
    DIRECTION INPUT ;
    USE SIGNAL ;
    PORT
      LAYER M4 ;
        RECT  0 70.656 0.084 70.68 ;
    END
  END bank_w[281]
  PIN bank_w[282]
    DIRECTION INPUT ;
    USE SIGNAL ;
    PORT
      LAYER M4 ;
        RECT  0 70.896 0.084 70.92 ;
    END
  END bank_w[282]
  PIN bank_w[283]
    DIRECTION INPUT ;
    USE SIGNAL ;
    PORT
      LAYER M4 ;
        RECT  0 71.136 0.084 71.16 ;
    END
  END bank_w[283]
  PIN bank_w[284]
    DIRECTION INPUT ;
    USE SIGNAL ;
    PORT
      LAYER M4 ;
        RECT  0 71.376 0.084 71.4 ;
    END
  END bank_w[284]
  PIN bank_w[285]
    DIRECTION INPUT ;
    USE SIGNAL ;
    PORT
      LAYER M4 ;
        RECT  0 71.616 0.084 71.64 ;
    END
  END bank_w[285]
  PIN bank_w[286]
    DIRECTION INPUT ;
    USE SIGNAL ;
    PORT
      LAYER M4 ;
        RECT  0 71.904 0.084 71.928 ;
    END
  END bank_w[286]
  PIN bank_w[287]
    DIRECTION INPUT ;
    USE SIGNAL ;
    PORT
      LAYER M4 ;
        RECT  0 72.144 0.084 72.168 ;
    END
  END bank_w[287]
  PIN bank_w[288]
    DIRECTION INPUT ;
    USE SIGNAL ;
    PORT
      LAYER M4 ;
        RECT  0 72.384 0.084 72.408 ;
    END
  END bank_w[288]
  PIN bank_w[289]
    DIRECTION INPUT ;
    USE SIGNAL ;
    PORT
      LAYER M4 ;
        RECT  0 72.624 0.084 72.648 ;
    END
  END bank_w[289]
  PIN bank_w[28]
    DIRECTION INPUT ;
    USE SIGNAL ;
    PORT
      LAYER M4 ;
        RECT  0 7.632 0.084 7.656 ;
    END
  END bank_w[28]
  PIN bank_w[290]
    DIRECTION INPUT ;
    USE SIGNAL ;
    PORT
      LAYER M4 ;
        RECT  0 72.864 0.084 72.888 ;
    END
  END bank_w[290]
  PIN bank_w[291]
    DIRECTION INPUT ;
    USE SIGNAL ;
    PORT
      LAYER M4 ;
        RECT  0 73.152 0.084 73.176 ;
    END
  END bank_w[291]
  PIN bank_w[292]
    DIRECTION INPUT ;
    USE SIGNAL ;
    PORT
      LAYER M4 ;
        RECT  0 73.392 0.084 73.416 ;
    END
  END bank_w[292]
  PIN bank_w[293]
    DIRECTION INPUT ;
    USE SIGNAL ;
    PORT
      LAYER M4 ;
        RECT  0 73.632 0.084 73.656 ;
    END
  END bank_w[293]
  PIN bank_w[294]
    DIRECTION INPUT ;
    USE SIGNAL ;
    PORT
      LAYER M4 ;
        RECT  0 73.872 0.084 73.896 ;
    END
  END bank_w[294]
  PIN bank_w[295]
    DIRECTION INPUT ;
    USE SIGNAL ;
    PORT
      LAYER M4 ;
        RECT  0 74.112 0.084 74.136 ;
    END
  END bank_w[295]
  PIN bank_w[296]
    DIRECTION INPUT ;
    USE SIGNAL ;
    PORT
      LAYER M4 ;
        RECT  0 74.4 0.084 74.424 ;
    END
  END bank_w[296]
  PIN bank_w[297]
    DIRECTION INPUT ;
    USE SIGNAL ;
    PORT
      LAYER M4 ;
        RECT  0 74.64 0.084 74.664 ;
    END
  END bank_w[297]
  PIN bank_w[298]
    DIRECTION INPUT ;
    USE SIGNAL ;
    PORT
      LAYER M4 ;
        RECT  0 74.88 0.084 74.904 ;
    END
  END bank_w[298]
  PIN bank_w[299]
    DIRECTION INPUT ;
    USE SIGNAL ;
    PORT
      LAYER M4 ;
        RECT  0 75.12 0.084 75.144 ;
    END
  END bank_w[299]
  PIN bank_w[29]
    DIRECTION INPUT ;
    USE SIGNAL ;
    PORT
      LAYER M4 ;
        RECT  0 7.872 0.084 7.896 ;
    END
  END bank_w[29]
  PIN bank_w[2]
    DIRECTION INPUT ;
    USE SIGNAL ;
    PORT
      LAYER M4 ;
        RECT  0 1.152 0.084 1.176 ;
    END
  END bank_w[2]
  PIN bank_w[300]
    DIRECTION INPUT ;
    USE SIGNAL ;
    PORT
      LAYER M4 ;
        RECT  0 75.36 0.084 75.384 ;
    END
  END bank_w[300]
  PIN bank_w[301]
    DIRECTION INPUT ;
    USE SIGNAL ;
    PORT
      LAYER M4 ;
        RECT  0 75.6 0.084 75.624 ;
    END
  END bank_w[301]
  PIN bank_w[302]
    DIRECTION INPUT ;
    USE SIGNAL ;
    PORT
      LAYER M4 ;
        RECT  0 75.888 0.084 75.912 ;
    END
  END bank_w[302]
  PIN bank_w[303]
    DIRECTION INPUT ;
    USE SIGNAL ;
    PORT
      LAYER M4 ;
        RECT  0 76.128 0.084 76.152 ;
    END
  END bank_w[303]
  PIN bank_w[304]
    DIRECTION INPUT ;
    USE SIGNAL ;
    PORT
      LAYER M4 ;
        RECT  0 76.368 0.084 76.392 ;
    END
  END bank_w[304]
  PIN bank_w[305]
    DIRECTION INPUT ;
    USE SIGNAL ;
    PORT
      LAYER M4 ;
        RECT  0 76.608 0.084 76.632 ;
    END
  END bank_w[305]
  PIN bank_w[306]
    DIRECTION INPUT ;
    USE SIGNAL ;
    PORT
      LAYER M4 ;
        RECT  0 76.848 0.084 76.872 ;
    END
  END bank_w[306]
  PIN bank_w[307]
    DIRECTION INPUT ;
    USE SIGNAL ;
    PORT
      LAYER M4 ;
        RECT  0 77.136 0.084 77.16 ;
    END
  END bank_w[307]
  PIN bank_w[308]
    DIRECTION INPUT ;
    USE SIGNAL ;
    PORT
      LAYER M4 ;
        RECT  0 77.376 0.084 77.4 ;
    END
  END bank_w[308]
  PIN bank_w[309]
    DIRECTION INPUT ;
    USE SIGNAL ;
    PORT
      LAYER M4 ;
        RECT  0 77.616 0.084 77.64 ;
    END
  END bank_w[309]
  PIN bank_w[30]
    DIRECTION INPUT ;
    USE SIGNAL ;
    PORT
      LAYER M4 ;
        RECT  0 8.112 0.084 8.136 ;
    END
  END bank_w[30]
  PIN bank_w[310]
    DIRECTION INPUT ;
    USE SIGNAL ;
    PORT
      LAYER M4 ;
        RECT  0 77.856 0.084 77.88 ;
    END
  END bank_w[310]
  PIN bank_w[311]
    DIRECTION INPUT ;
    USE SIGNAL ;
    PORT
      LAYER M4 ;
        RECT  0 78.096 0.084 78.12 ;
    END
  END bank_w[311]
  PIN bank_w[312]
    DIRECTION INPUT ;
    USE SIGNAL ;
    PORT
      LAYER M4 ;
        RECT  0 78.384 0.084 78.408 ;
    END
  END bank_w[312]
  PIN bank_w[313]
    DIRECTION INPUT ;
    USE SIGNAL ;
    PORT
      LAYER M4 ;
        RECT  0 78.624 0.084 78.648 ;
    END
  END bank_w[313]
  PIN bank_w[314]
    DIRECTION INPUT ;
    USE SIGNAL ;
    PORT
      LAYER M4 ;
        RECT  0 78.864 0.084 78.888 ;
    END
  END bank_w[314]
  PIN bank_w[315]
    DIRECTION INPUT ;
    USE SIGNAL ;
    PORT
      LAYER M4 ;
        RECT  0 79.104 0.084 79.128 ;
    END
  END bank_w[315]
  PIN bank_w[316]
    DIRECTION INPUT ;
    USE SIGNAL ;
    PORT
      LAYER M4 ;
        RECT  0 79.344 0.084 79.368 ;
    END
  END bank_w[316]
  PIN bank_w[317]
    DIRECTION INPUT ;
    USE SIGNAL ;
    PORT
      LAYER M4 ;
        RECT  0 79.632 0.084 79.656 ;
    END
  END bank_w[317]
  PIN bank_w[318]
    DIRECTION INPUT ;
    USE SIGNAL ;
    PORT
      LAYER M4 ;
        RECT  0 79.872 0.084 79.896 ;
    END
  END bank_w[318]
  PIN bank_w[319]
    DIRECTION INPUT ;
    USE SIGNAL ;
    PORT
      LAYER M4 ;
        RECT  0 80.112 0.084 80.136 ;
    END
  END bank_w[319]
  PIN bank_w[31]
    DIRECTION INPUT ;
    USE SIGNAL ;
    PORT
      LAYER M4 ;
        RECT  0 8.352 0.084 8.376 ;
    END
  END bank_w[31]
  PIN bank_w[320]
    DIRECTION INPUT ;
    USE SIGNAL ;
    PORT
      LAYER M4 ;
        RECT  0 80.352 0.084 80.376 ;
    END
  END bank_w[320]
  PIN bank_w[321]
    DIRECTION INPUT ;
    USE SIGNAL ;
    PORT
      LAYER M4 ;
        RECT  0 80.592 0.084 80.616 ;
    END
  END bank_w[321]
  PIN bank_w[322]
    DIRECTION INPUT ;
    USE SIGNAL ;
    PORT
      LAYER M4 ;
        RECT  0 80.832 0.084 80.856 ;
    END
  END bank_w[322]
  PIN bank_w[323]
    DIRECTION INPUT ;
    USE SIGNAL ;
    PORT
      LAYER M4 ;
        RECT  0 81.12 0.084 81.144 ;
    END
  END bank_w[323]
  PIN bank_w[324]
    DIRECTION INPUT ;
    USE SIGNAL ;
    PORT
      LAYER M4 ;
        RECT  0 81.36 0.084 81.384 ;
    END
  END bank_w[324]
  PIN bank_w[325]
    DIRECTION INPUT ;
    USE SIGNAL ;
    PORT
      LAYER M4 ;
        RECT  0 81.6 0.084 81.624 ;
    END
  END bank_w[325]
  PIN bank_w[326]
    DIRECTION INPUT ;
    USE SIGNAL ;
    PORT
      LAYER M4 ;
        RECT  0 81.84 0.084 81.864 ;
    END
  END bank_w[326]
  PIN bank_w[327]
    DIRECTION INPUT ;
    USE SIGNAL ;
    PORT
      LAYER M4 ;
        RECT  0 82.08 0.084 82.104 ;
    END
  END bank_w[327]
  PIN bank_w[328]
    DIRECTION INPUT ;
    USE SIGNAL ;
    PORT
      LAYER M4 ;
        RECT  0 82.368 0.084 82.392 ;
    END
  END bank_w[328]
  PIN bank_w[329]
    DIRECTION INPUT ;
    USE SIGNAL ;
    PORT
      LAYER M4 ;
        RECT  0 82.608 0.084 82.632 ;
    END
  END bank_w[329]
  PIN bank_w[32]
    DIRECTION INPUT ;
    USE SIGNAL ;
    PORT
      LAYER M4 ;
        RECT  0 8.64 0.084 8.664 ;
    END
  END bank_w[32]
  PIN bank_w[330]
    DIRECTION INPUT ;
    USE SIGNAL ;
    PORT
      LAYER M4 ;
        RECT  0 82.848 0.084 82.872 ;
    END
  END bank_w[330]
  PIN bank_w[331]
    DIRECTION INPUT ;
    USE SIGNAL ;
    PORT
      LAYER M4 ;
        RECT  0 83.088 0.084 83.112 ;
    END
  END bank_w[331]
  PIN bank_w[332]
    DIRECTION INPUT ;
    USE SIGNAL ;
    PORT
      LAYER M4 ;
        RECT  0 83.328 0.084 83.352 ;
    END
  END bank_w[332]
  PIN bank_w[333]
    DIRECTION INPUT ;
    USE SIGNAL ;
    PORT
      LAYER M4 ;
        RECT  0 83.616 0.084 83.64 ;
    END
  END bank_w[333]
  PIN bank_w[334]
    DIRECTION INPUT ;
    USE SIGNAL ;
    PORT
      LAYER M4 ;
        RECT  0 83.856 0.084 83.88 ;
    END
  END bank_w[334]
  PIN bank_w[335]
    DIRECTION INPUT ;
    USE SIGNAL ;
    PORT
      LAYER M4 ;
        RECT  0 84.096 0.084 84.12 ;
    END
  END bank_w[335]
  PIN bank_w[336]
    DIRECTION INPUT ;
    USE SIGNAL ;
    PORT
      LAYER M4 ;
        RECT  0 84.336 0.084 84.36 ;
    END
  END bank_w[336]
  PIN bank_w[337]
    DIRECTION INPUT ;
    USE SIGNAL ;
    PORT
      LAYER M4 ;
        RECT  0 84.576 0.084 84.6 ;
    END
  END bank_w[337]
  PIN bank_w[338]
    DIRECTION INPUT ;
    USE SIGNAL ;
    PORT
      LAYER M4 ;
        RECT  0 84.816 0.084 84.84 ;
    END
  END bank_w[338]
  PIN bank_w[339]
    DIRECTION INPUT ;
    USE SIGNAL ;
    PORT
      LAYER M4 ;
        RECT  0 85.104 0.084 85.128 ;
    END
  END bank_w[339]
  PIN bank_w[33]
    DIRECTION INPUT ;
    USE SIGNAL ;
    PORT
      LAYER M4 ;
        RECT  0 8.88 0.084 8.904 ;
    END
  END bank_w[33]
  PIN bank_w[340]
    DIRECTION INPUT ;
    USE SIGNAL ;
    PORT
      LAYER M4 ;
        RECT  0 85.344 0.084 85.368 ;
    END
  END bank_w[340]
  PIN bank_w[341]
    DIRECTION INPUT ;
    USE SIGNAL ;
    PORT
      LAYER M4 ;
        RECT  0 85.584 0.084 85.608 ;
    END
  END bank_w[341]
  PIN bank_w[342]
    DIRECTION INPUT ;
    USE SIGNAL ;
    PORT
      LAYER M4 ;
        RECT  0 85.824 0.084 85.848 ;
    END
  END bank_w[342]
  PIN bank_w[343]
    DIRECTION INPUT ;
    USE SIGNAL ;
    PORT
      LAYER M4 ;
        RECT  0 86.064 0.084 86.088 ;
    END
  END bank_w[343]
  PIN bank_w[344]
    DIRECTION INPUT ;
    USE SIGNAL ;
    PORT
      LAYER M4 ;
        RECT  0 86.352 0.084 86.376 ;
    END
  END bank_w[344]
  PIN bank_w[345]
    DIRECTION INPUT ;
    USE SIGNAL ;
    PORT
      LAYER M4 ;
        RECT  0 86.592 0.084 86.616 ;
    END
  END bank_w[345]
  PIN bank_w[346]
    DIRECTION INPUT ;
    USE SIGNAL ;
    PORT
      LAYER M4 ;
        RECT  0 86.832 0.084 86.856 ;
    END
  END bank_w[346]
  PIN bank_w[347]
    DIRECTION INPUT ;
    USE SIGNAL ;
    PORT
      LAYER M4 ;
        RECT  0 87.072 0.084 87.096 ;
    END
  END bank_w[347]
  PIN bank_w[348]
    DIRECTION INPUT ;
    USE SIGNAL ;
    PORT
      LAYER M4 ;
        RECT  0 87.312 0.084 87.336 ;
    END
  END bank_w[348]
  PIN bank_w[349]
    DIRECTION INPUT ;
    USE SIGNAL ;
    PORT
      LAYER M4 ;
        RECT  0 87.6 0.084 87.624 ;
    END
  END bank_w[349]
  PIN bank_w[34]
    DIRECTION INPUT ;
    USE SIGNAL ;
    PORT
      LAYER M4 ;
        RECT  0 9.12 0.084 9.144 ;
    END
  END bank_w[34]
  PIN bank_w[350]
    DIRECTION INPUT ;
    USE SIGNAL ;
    PORT
      LAYER M4 ;
        RECT  0 87.84 0.084 87.864 ;
    END
  END bank_w[350]
  PIN bank_w[351]
    DIRECTION INPUT ;
    USE SIGNAL ;
    PORT
      LAYER M4 ;
        RECT  0 88.08 0.084 88.104 ;
    END
  END bank_w[351]
  PIN bank_w[352]
    DIRECTION INPUT ;
    USE SIGNAL ;
    PORT
      LAYER M4 ;
        RECT  0 88.32 0.084 88.344 ;
    END
  END bank_w[352]
  PIN bank_w[353]
    DIRECTION INPUT ;
    USE SIGNAL ;
    PORT
      LAYER M4 ;
        RECT  0 88.56 0.084 88.584 ;
    END
  END bank_w[353]
  PIN bank_w[354]
    DIRECTION INPUT ;
    USE SIGNAL ;
    PORT
      LAYER M4 ;
        RECT  0 88.8 0.084 88.824 ;
    END
  END bank_w[354]
  PIN bank_w[355]
    DIRECTION INPUT ;
    USE SIGNAL ;
    PORT
      LAYER M4 ;
        RECT  0 89.088 0.084 89.112 ;
    END
  END bank_w[355]
  PIN bank_w[356]
    DIRECTION INPUT ;
    USE SIGNAL ;
    PORT
      LAYER M4 ;
        RECT  0 89.328 0.084 89.352 ;
    END
  END bank_w[356]
  PIN bank_w[357]
    DIRECTION INPUT ;
    USE SIGNAL ;
    PORT
      LAYER M4 ;
        RECT  0 89.568 0.084 89.592 ;
    END
  END bank_w[357]
  PIN bank_w[358]
    DIRECTION INPUT ;
    USE SIGNAL ;
    PORT
      LAYER M4 ;
        RECT  0 89.808 0.084 89.832 ;
    END
  END bank_w[358]
  PIN bank_w[359]
    DIRECTION INPUT ;
    USE SIGNAL ;
    PORT
      LAYER M4 ;
        RECT  0 90.048 0.084 90.072 ;
    END
  END bank_w[359]
  PIN bank_w[35]
    DIRECTION INPUT ;
    USE SIGNAL ;
    PORT
      LAYER M4 ;
        RECT  0 9.36 0.084 9.384 ;
    END
  END bank_w[35]
  PIN bank_w[360]
    DIRECTION INPUT ;
    USE SIGNAL ;
    PORT
      LAYER M4 ;
        RECT  0 90.336 0.084 90.36 ;
    END
  END bank_w[360]
  PIN bank_w[361]
    DIRECTION INPUT ;
    USE SIGNAL ;
    PORT
      LAYER M4 ;
        RECT  0 90.576 0.084 90.6 ;
    END
  END bank_w[361]
  PIN bank_w[362]
    DIRECTION INPUT ;
    USE SIGNAL ;
    PORT
      LAYER M4 ;
        RECT  0 90.816 0.084 90.84 ;
    END
  END bank_w[362]
  PIN bank_w[363]
    DIRECTION INPUT ;
    USE SIGNAL ;
    PORT
      LAYER M4 ;
        RECT  0 91.056 0.084 91.08 ;
    END
  END bank_w[363]
  PIN bank_w[364]
    DIRECTION INPUT ;
    USE SIGNAL ;
    PORT
      LAYER M4 ;
        RECT  0 91.296 0.084 91.32 ;
    END
  END bank_w[364]
  PIN bank_w[365]
    DIRECTION INPUT ;
    USE SIGNAL ;
    PORT
      LAYER M4 ;
        RECT  0 91.584 0.084 91.608 ;
    END
  END bank_w[365]
  PIN bank_w[366]
    DIRECTION INPUT ;
    USE SIGNAL ;
    PORT
      LAYER M4 ;
        RECT  0 91.824 0.084 91.848 ;
    END
  END bank_w[366]
  PIN bank_w[367]
    DIRECTION INPUT ;
    USE SIGNAL ;
    PORT
      LAYER M4 ;
        RECT  0 92.064 0.084 92.088 ;
    END
  END bank_w[367]
  PIN bank_w[368]
    DIRECTION INPUT ;
    USE SIGNAL ;
    PORT
      LAYER M4 ;
        RECT  0 92.304 0.084 92.328 ;
    END
  END bank_w[368]
  PIN bank_w[369]
    DIRECTION INPUT ;
    USE SIGNAL ;
    PORT
      LAYER M4 ;
        RECT  0 92.544 0.084 92.568 ;
    END
  END bank_w[369]
  PIN bank_w[36]
    DIRECTION INPUT ;
    USE SIGNAL ;
    PORT
      LAYER M4 ;
        RECT  0 9.6 0.084 9.624 ;
    END
  END bank_w[36]
  PIN bank_w[370]
    DIRECTION INPUT ;
    USE SIGNAL ;
    PORT
      LAYER M4 ;
        RECT  0 92.832 0.084 92.856 ;
    END
  END bank_w[370]
  PIN bank_w[371]
    DIRECTION INPUT ;
    USE SIGNAL ;
    PORT
      LAYER M4 ;
        RECT  0 93.072 0.084 93.096 ;
    END
  END bank_w[371]
  PIN bank_w[372]
    DIRECTION INPUT ;
    USE SIGNAL ;
    PORT
      LAYER M4 ;
        RECT  0 93.312 0.084 93.336 ;
    END
  END bank_w[372]
  PIN bank_w[373]
    DIRECTION INPUT ;
    USE SIGNAL ;
    PORT
      LAYER M4 ;
        RECT  0 93.552 0.084 93.576 ;
    END
  END bank_w[373]
  PIN bank_w[374]
    DIRECTION INPUT ;
    USE SIGNAL ;
    PORT
      LAYER M4 ;
        RECT  0 93.792 0.084 93.816 ;
    END
  END bank_w[374]
  PIN bank_w[375]
    DIRECTION INPUT ;
    USE SIGNAL ;
    PORT
      LAYER M4 ;
        RECT  0 94.032 0.084 94.056 ;
    END
  END bank_w[375]
  PIN bank_w[376]
    DIRECTION INPUT ;
    USE SIGNAL ;
    PORT
      LAYER M4 ;
        RECT  0 94.32 0.084 94.344 ;
    END
  END bank_w[376]
  PIN bank_w[377]
    DIRECTION INPUT ;
    USE SIGNAL ;
    PORT
      LAYER M4 ;
        RECT  0 94.56 0.084 94.584 ;
    END
  END bank_w[377]
  PIN bank_w[378]
    DIRECTION INPUT ;
    USE SIGNAL ;
    PORT
      LAYER M4 ;
        RECT  0 94.8 0.084 94.824 ;
    END
  END bank_w[378]
  PIN bank_w[379]
    DIRECTION INPUT ;
    USE SIGNAL ;
    PORT
      LAYER M4 ;
        RECT  0 95.04 0.084 95.064 ;
    END
  END bank_w[379]
  PIN bank_w[37]
    DIRECTION INPUT ;
    USE SIGNAL ;
    PORT
      LAYER M4 ;
        RECT  0 9.888 0.084 9.912 ;
    END
  END bank_w[37]
  PIN bank_w[380]
    DIRECTION INPUT ;
    USE SIGNAL ;
    PORT
      LAYER M4 ;
        RECT  0 95.28 0.084 95.304 ;
    END
  END bank_w[380]
  PIN bank_w[381]
    DIRECTION INPUT ;
    USE SIGNAL ;
    PORT
      LAYER M4 ;
        RECT  0 95.568 0.084 95.592 ;
    END
  END bank_w[381]
  PIN bank_w[382]
    DIRECTION INPUT ;
    USE SIGNAL ;
    PORT
      LAYER M4 ;
        RECT  0 95.808 0.084 95.832 ;
    END
  END bank_w[382]
  PIN bank_w[383]
    DIRECTION INPUT ;
    USE SIGNAL ;
    PORT
      LAYER M4 ;
        RECT  0 96.048 0.084 96.072 ;
    END
  END bank_w[383]
  PIN bank_w[384]
    DIRECTION INPUT ;
    USE SIGNAL ;
    PORT
      LAYER M4 ;
        RECT  0 96.288 0.084 96.312 ;
    END
  END bank_w[384]
  PIN bank_w[385]
    DIRECTION INPUT ;
    USE SIGNAL ;
    PORT
      LAYER M4 ;
        RECT  0 96.528 0.084 96.552 ;
    END
  END bank_w[385]
  PIN bank_w[386]
    DIRECTION INPUT ;
    USE SIGNAL ;
    PORT
      LAYER M4 ;
        RECT  0 96.816 0.084 96.84 ;
    END
  END bank_w[386]
  PIN bank_w[387]
    DIRECTION INPUT ;
    USE SIGNAL ;
    PORT
      LAYER M4 ;
        RECT  0 97.056 0.084 97.08 ;
    END
  END bank_w[387]
  PIN bank_w[388]
    DIRECTION INPUT ;
    USE SIGNAL ;
    PORT
      LAYER M4 ;
        RECT  0 97.296 0.084 97.32 ;
    END
  END bank_w[388]
  PIN bank_w[389]
    DIRECTION INPUT ;
    USE SIGNAL ;
    PORT
      LAYER M4 ;
        RECT  0 97.536 0.084 97.56 ;
    END
  END bank_w[389]
  PIN bank_w[38]
    DIRECTION INPUT ;
    USE SIGNAL ;
    PORT
      LAYER M4 ;
        RECT  0 10.128 0.084 10.152 ;
    END
  END bank_w[38]
  PIN bank_w[390]
    DIRECTION INPUT ;
    USE SIGNAL ;
    PORT
      LAYER M4 ;
        RECT  0 97.776 0.084 97.8 ;
    END
  END bank_w[390]
  PIN bank_w[391]
    DIRECTION INPUT ;
    USE SIGNAL ;
    PORT
      LAYER M4 ;
        RECT  0 98.016 0.084 98.04 ;
    END
  END bank_w[391]
  PIN bank_w[392]
    DIRECTION INPUT ;
    USE SIGNAL ;
    PORT
      LAYER M4 ;
        RECT  0 98.304 0.084 98.328 ;
    END
  END bank_w[392]
  PIN bank_w[393]
    DIRECTION INPUT ;
    USE SIGNAL ;
    PORT
      LAYER M4 ;
        RECT  0 98.544 0.084 98.568 ;
    END
  END bank_w[393]
  PIN bank_w[394]
    DIRECTION INPUT ;
    USE SIGNAL ;
    PORT
      LAYER M4 ;
        RECT  0 98.784 0.084 98.808 ;
    END
  END bank_w[394]
  PIN bank_w[395]
    DIRECTION INPUT ;
    USE SIGNAL ;
    PORT
      LAYER M4 ;
        RECT  0 99.024 0.084 99.048 ;
    END
  END bank_w[395]
  PIN bank_w[396]
    DIRECTION INPUT ;
    USE SIGNAL ;
    PORT
      LAYER M4 ;
        RECT  0 99.264 0.084 99.288 ;
    END
  END bank_w[396]
  PIN bank_w[397]
    DIRECTION INPUT ;
    USE SIGNAL ;
    PORT
      LAYER M4 ;
        RECT  0 99.552 0.084 99.576 ;
    END
  END bank_w[397]
  PIN bank_w[398]
    DIRECTION INPUT ;
    USE SIGNAL ;
    PORT
      LAYER M4 ;
        RECT  0 99.792 0.084 99.816 ;
    END
  END bank_w[398]
  PIN bank_w[399]
    DIRECTION INPUT ;
    USE SIGNAL ;
    PORT
      LAYER M4 ;
        RECT  0 100.032 0.084 100.056 ;
    END
  END bank_w[399]
  PIN bank_w[39]
    DIRECTION INPUT ;
    USE SIGNAL ;
    PORT
      LAYER M4 ;
        RECT  0 10.368 0.084 10.392 ;
    END
  END bank_w[39]
  PIN bank_w[3]
    DIRECTION INPUT ;
    USE SIGNAL ;
    PORT
      LAYER M4 ;
        RECT  0 1.392 0.084 1.416 ;
    END
  END bank_w[3]
  PIN bank_w[400]
    DIRECTION INPUT ;
    USE SIGNAL ;
    PORT
      LAYER M4 ;
        RECT  0 100.272 0.084 100.296 ;
    END
  END bank_w[400]
  PIN bank_w[401]
    DIRECTION INPUT ;
    USE SIGNAL ;
    PORT
      LAYER M4 ;
        RECT  0 100.512 0.084 100.536 ;
    END
  END bank_w[401]
  PIN bank_w[402]
    DIRECTION INPUT ;
    USE SIGNAL ;
    PORT
      LAYER M4 ;
        RECT  0 100.8 0.084 100.824 ;
    END
  END bank_w[402]
  PIN bank_w[403]
    DIRECTION INPUT ;
    USE SIGNAL ;
    PORT
      LAYER M4 ;
        RECT  0 101.04 0.084 101.064 ;
    END
  END bank_w[403]
  PIN bank_w[404]
    DIRECTION INPUT ;
    USE SIGNAL ;
    PORT
      LAYER M4 ;
        RECT  0 101.28 0.084 101.304 ;
    END
  END bank_w[404]
  PIN bank_w[405]
    DIRECTION INPUT ;
    USE SIGNAL ;
    PORT
      LAYER M4 ;
        RECT  0 101.52 0.084 101.544 ;
    END
  END bank_w[405]
  PIN bank_w[406]
    DIRECTION INPUT ;
    USE SIGNAL ;
    PORT
      LAYER M4 ;
        RECT  0 101.76 0.084 101.784 ;
    END
  END bank_w[406]
  PIN bank_w[407]
    DIRECTION INPUT ;
    USE SIGNAL ;
    PORT
      LAYER M4 ;
        RECT  0 102.048 0.084 102.072 ;
    END
  END bank_w[407]
  PIN bank_w[408]
    DIRECTION INPUT ;
    USE SIGNAL ;
    PORT
      LAYER M4 ;
        RECT  0 102.288 0.084 102.312 ;
    END
  END bank_w[408]
  PIN bank_w[409]
    DIRECTION INPUT ;
    USE SIGNAL ;
    PORT
      LAYER M4 ;
        RECT  0 102.528 0.084 102.552 ;
    END
  END bank_w[409]
  PIN bank_w[40]
    DIRECTION INPUT ;
    USE SIGNAL ;
    PORT
      LAYER M4 ;
        RECT  0 10.608 0.084 10.632 ;
    END
  END bank_w[40]
  PIN bank_w[410]
    DIRECTION INPUT ;
    USE SIGNAL ;
    PORT
      LAYER M4 ;
        RECT  0 102.768 0.084 102.792 ;
    END
  END bank_w[410]
  PIN bank_w[411]
    DIRECTION INPUT ;
    USE SIGNAL ;
    PORT
      LAYER M4 ;
        RECT  0 103.008 0.084 103.032 ;
    END
  END bank_w[411]
  PIN bank_w[412]
    DIRECTION INPUT ;
    USE SIGNAL ;
    PORT
      LAYER M4 ;
        RECT  0 103.248 0.084 103.272 ;
    END
  END bank_w[412]
  PIN bank_w[413]
    DIRECTION INPUT ;
    USE SIGNAL ;
    PORT
      LAYER M4 ;
        RECT  0 103.536 0.084 103.56 ;
    END
  END bank_w[413]
  PIN bank_w[414]
    DIRECTION INPUT ;
    USE SIGNAL ;
    PORT
      LAYER M4 ;
        RECT  0 103.776 0.084 103.8 ;
    END
  END bank_w[414]
  PIN bank_w[415]
    DIRECTION INPUT ;
    USE SIGNAL ;
    PORT
      LAYER M4 ;
        RECT  0 104.016 0.084 104.04 ;
    END
  END bank_w[415]
  PIN bank_w[416]
    DIRECTION INPUT ;
    USE SIGNAL ;
    PORT
      LAYER M4 ;
        RECT  0 104.256 0.084 104.28 ;
    END
  END bank_w[416]
  PIN bank_w[417]
    DIRECTION INPUT ;
    USE SIGNAL ;
    PORT
      LAYER M4 ;
        RECT  0 104.496 0.084 104.52 ;
    END
  END bank_w[417]
  PIN bank_w[418]
    DIRECTION INPUT ;
    USE SIGNAL ;
    PORT
      LAYER M4 ;
        RECT  0 104.784 0.084 104.808 ;
    END
  END bank_w[418]
  PIN bank_w[419]
    DIRECTION INPUT ;
    USE SIGNAL ;
    PORT
      LAYER M4 ;
        RECT  0 105.024 0.084 105.048 ;
    END
  END bank_w[419]
  PIN bank_w[41]
    DIRECTION INPUT ;
    USE SIGNAL ;
    PORT
      LAYER M4 ;
        RECT  0 10.848 0.084 10.872 ;
    END
  END bank_w[41]
  PIN bank_w[420]
    DIRECTION INPUT ;
    USE SIGNAL ;
    PORT
      LAYER M4 ;
        RECT  0 105.264 0.084 105.288 ;
    END
  END bank_w[420]
  PIN bank_w[421]
    DIRECTION INPUT ;
    USE SIGNAL ;
    PORT
      LAYER M4 ;
        RECT  0 105.504 0.084 105.528 ;
    END
  END bank_w[421]
  PIN bank_w[422]
    DIRECTION INPUT ;
    USE SIGNAL ;
    PORT
      LAYER M4 ;
        RECT  0 105.744 0.084 105.768 ;
    END
  END bank_w[422]
  PIN bank_w[423]
    DIRECTION INPUT ;
    USE SIGNAL ;
    PORT
      LAYER M4 ;
        RECT  0 106.032 0.084 106.056 ;
    END
  END bank_w[423]
  PIN bank_w[424]
    DIRECTION INPUT ;
    USE SIGNAL ;
    PORT
      LAYER M4 ;
        RECT  0 106.272 0.084 106.296 ;
    END
  END bank_w[424]
  PIN bank_w[425]
    DIRECTION INPUT ;
    USE SIGNAL ;
    PORT
      LAYER M4 ;
        RECT  0 106.512 0.084 106.536 ;
    END
  END bank_w[425]
  PIN bank_w[426]
    DIRECTION INPUT ;
    USE SIGNAL ;
    PORT
      LAYER M4 ;
        RECT  0 106.752 0.084 106.776 ;
    END
  END bank_w[426]
  PIN bank_w[427]
    DIRECTION INPUT ;
    USE SIGNAL ;
    PORT
      LAYER M4 ;
        RECT  0 106.992 0.084 107.016 ;
    END
  END bank_w[427]
  PIN bank_w[428]
    DIRECTION INPUT ;
    USE SIGNAL ;
    PORT
      LAYER M4 ;
        RECT  0 107.232 0.084 107.256 ;
    END
  END bank_w[428]
  PIN bank_w[429]
    DIRECTION INPUT ;
    USE SIGNAL ;
    PORT
      LAYER M4 ;
        RECT  0 107.52 0.084 107.544 ;
    END
  END bank_w[429]
  PIN bank_w[42]
    DIRECTION INPUT ;
    USE SIGNAL ;
    PORT
      LAYER M4 ;
        RECT  0 11.136 0.084 11.16 ;
    END
  END bank_w[42]
  PIN bank_w[430]
    DIRECTION INPUT ;
    USE SIGNAL ;
    PORT
      LAYER M4 ;
        RECT  0 107.76 0.084 107.784 ;
    END
  END bank_w[430]
  PIN bank_w[431]
    DIRECTION INPUT ;
    USE SIGNAL ;
    PORT
      LAYER M4 ;
        RECT  0 108 0.084 108.024 ;
    END
  END bank_w[431]
  PIN bank_w[432]
    DIRECTION INPUT ;
    USE SIGNAL ;
    PORT
      LAYER M4 ;
        RECT  0 108.24 0.084 108.264 ;
    END
  END bank_w[432]
  PIN bank_w[433]
    DIRECTION INPUT ;
    USE SIGNAL ;
    PORT
      LAYER M4 ;
        RECT  0 108.48 0.084 108.504 ;
    END
  END bank_w[433]
  PIN bank_w[434]
    DIRECTION INPUT ;
    USE SIGNAL ;
    PORT
      LAYER M4 ;
        RECT  0 108.768 0.084 108.792 ;
    END
  END bank_w[434]
  PIN bank_w[435]
    DIRECTION INPUT ;
    USE SIGNAL ;
    PORT
      LAYER M4 ;
        RECT  0 109.008 0.084 109.032 ;
    END
  END bank_w[435]
  PIN bank_w[436]
    DIRECTION INPUT ;
    USE SIGNAL ;
    PORT
      LAYER M4 ;
        RECT  0 109.248 0.084 109.272 ;
    END
  END bank_w[436]
  PIN bank_w[437]
    DIRECTION INPUT ;
    USE SIGNAL ;
    PORT
      LAYER M4 ;
        RECT  0 109.488 0.084 109.512 ;
    END
  END bank_w[437]
  PIN bank_w[438]
    DIRECTION INPUT ;
    USE SIGNAL ;
    PORT
      LAYER M4 ;
        RECT  0 109.728 0.084 109.752 ;
    END
  END bank_w[438]
  PIN bank_w[439]
    DIRECTION INPUT ;
    USE SIGNAL ;
    PORT
      LAYER M4 ;
        RECT  0 110.016 0.084 110.04 ;
    END
  END bank_w[439]
  PIN bank_w[43]
    DIRECTION INPUT ;
    USE SIGNAL ;
    PORT
      LAYER M4 ;
        RECT  0 11.376 0.084 11.4 ;
    END
  END bank_w[43]
  PIN bank_w[440]
    DIRECTION INPUT ;
    USE SIGNAL ;
    PORT
      LAYER M4 ;
        RECT  0 110.256 0.084 110.28 ;
    END
  END bank_w[440]
  PIN bank_w[441]
    DIRECTION INPUT ;
    USE SIGNAL ;
    PORT
      LAYER M4 ;
        RECT  0 110.496 0.084 110.52 ;
    END
  END bank_w[441]
  PIN bank_w[442]
    DIRECTION INPUT ;
    USE SIGNAL ;
    PORT
      LAYER M4 ;
        RECT  0 110.736 0.084 110.76 ;
    END
  END bank_w[442]
  PIN bank_w[443]
    DIRECTION INPUT ;
    USE SIGNAL ;
    PORT
      LAYER M4 ;
        RECT  0 110.976 0.084 111 ;
    END
  END bank_w[443]
  PIN bank_w[444]
    DIRECTION INPUT ;
    USE SIGNAL ;
    PORT
      LAYER M4 ;
        RECT  0 111.264 0.084 111.288 ;
    END
  END bank_w[444]
  PIN bank_w[445]
    DIRECTION INPUT ;
    USE SIGNAL ;
    PORT
      LAYER M4 ;
        RECT  0 111.504 0.084 111.528 ;
    END
  END bank_w[445]
  PIN bank_w[446]
    DIRECTION INPUT ;
    USE SIGNAL ;
    PORT
      LAYER M4 ;
        RECT  0 111.744 0.084 111.768 ;
    END
  END bank_w[446]
  PIN bank_w[447]
    DIRECTION INPUT ;
    USE SIGNAL ;
    PORT
      LAYER M4 ;
        RECT  0 111.984 0.084 112.008 ;
    END
  END bank_w[447]
  PIN bank_w[448]
    DIRECTION INPUT ;
    USE SIGNAL ;
    PORT
      LAYER M4 ;
        RECT  0 112.224 0.084 112.248 ;
    END
  END bank_w[448]
  PIN bank_w[449]
    DIRECTION INPUT ;
    USE SIGNAL ;
    PORT
      LAYER M4 ;
        RECT  0 112.464 0.084 112.488 ;
    END
  END bank_w[449]
  PIN bank_w[44]
    DIRECTION INPUT ;
    USE SIGNAL ;
    PORT
      LAYER M4 ;
        RECT  0 11.616 0.084 11.64 ;
    END
  END bank_w[44]
  PIN bank_w[450]
    DIRECTION INPUT ;
    USE SIGNAL ;
    PORT
      LAYER M4 ;
        RECT  0 112.752 0.084 112.776 ;
    END
  END bank_w[450]
  PIN bank_w[451]
    DIRECTION INPUT ;
    USE SIGNAL ;
    PORT
      LAYER M4 ;
        RECT  0 112.992 0.084 113.016 ;
    END
  END bank_w[451]
  PIN bank_w[452]
    DIRECTION INPUT ;
    USE SIGNAL ;
    PORT
      LAYER M4 ;
        RECT  0 113.232 0.084 113.256 ;
    END
  END bank_w[452]
  PIN bank_w[453]
    DIRECTION INPUT ;
    USE SIGNAL ;
    PORT
      LAYER M4 ;
        RECT  0 113.472 0.084 113.496 ;
    END
  END bank_w[453]
  PIN bank_w[454]
    DIRECTION INPUT ;
    USE SIGNAL ;
    PORT
      LAYER M4 ;
        RECT  0 113.712 0.084 113.736 ;
    END
  END bank_w[454]
  PIN bank_w[455]
    DIRECTION INPUT ;
    USE SIGNAL ;
    PORT
      LAYER M4 ;
        RECT  0 114 0.084 114.024 ;
    END
  END bank_w[455]
  PIN bank_w[456]
    DIRECTION INPUT ;
    USE SIGNAL ;
    PORT
      LAYER M4 ;
        RECT  0 114.24 0.084 114.264 ;
    END
  END bank_w[456]
  PIN bank_w[457]
    DIRECTION INPUT ;
    USE SIGNAL ;
    PORT
      LAYER M4 ;
        RECT  0 114.48 0.084 114.504 ;
    END
  END bank_w[457]
  PIN bank_w[458]
    DIRECTION INPUT ;
    USE SIGNAL ;
    PORT
      LAYER M4 ;
        RECT  0 114.72 0.084 114.744 ;
    END
  END bank_w[458]
  PIN bank_w[459]
    DIRECTION INPUT ;
    USE SIGNAL ;
    PORT
      LAYER M4 ;
        RECT  0 114.96 0.084 114.984 ;
    END
  END bank_w[459]
  PIN bank_w[45]
    DIRECTION INPUT ;
    USE SIGNAL ;
    PORT
      LAYER M4 ;
        RECT  0 11.856 0.084 11.88 ;
    END
  END bank_w[45]
  PIN bank_w[460]
    DIRECTION INPUT ;
    USE SIGNAL ;
    PORT
      LAYER M4 ;
        RECT  0 115.248 0.084 115.272 ;
    END
  END bank_w[460]
  PIN bank_w[461]
    DIRECTION INPUT ;
    USE SIGNAL ;
    PORT
      LAYER M4 ;
        RECT  0 115.488 0.084 115.512 ;
    END
  END bank_w[461]
  PIN bank_w[462]
    DIRECTION INPUT ;
    USE SIGNAL ;
    PORT
      LAYER M4 ;
        RECT  0 115.728 0.084 115.752 ;
    END
  END bank_w[462]
  PIN bank_w[463]
    DIRECTION INPUT ;
    USE SIGNAL ;
    PORT
      LAYER M4 ;
        RECT  0 115.968 0.084 115.992 ;
    END
  END bank_w[463]
  PIN bank_w[464]
    DIRECTION INPUT ;
    USE SIGNAL ;
    PORT
      LAYER M4 ;
        RECT  0 116.208 0.084 116.232 ;
    END
  END bank_w[464]
  PIN bank_w[465]
    DIRECTION INPUT ;
    USE SIGNAL ;
    PORT
      LAYER M4 ;
        RECT  0 116.448 0.084 116.472 ;
    END
  END bank_w[465]
  PIN bank_w[466]
    DIRECTION INPUT ;
    USE SIGNAL ;
    PORT
      LAYER M4 ;
        RECT  0 116.736 0.084 116.76 ;
    END
  END bank_w[466]
  PIN bank_w[467]
    DIRECTION INPUT ;
    USE SIGNAL ;
    PORT
      LAYER M4 ;
        RECT  0 116.976 0.084 117 ;
    END
  END bank_w[467]
  PIN bank_w[468]
    DIRECTION INPUT ;
    USE SIGNAL ;
    PORT
      LAYER M4 ;
        RECT  0 117.216 0.084 117.24 ;
    END
  END bank_w[468]
  PIN bank_w[469]
    DIRECTION INPUT ;
    USE SIGNAL ;
    PORT
      LAYER M4 ;
        RECT  0 117.456 0.084 117.48 ;
    END
  END bank_w[469]
  PIN bank_w[46]
    DIRECTION INPUT ;
    USE SIGNAL ;
    PORT
      LAYER M4 ;
        RECT  0 12.096 0.084 12.12 ;
    END
  END bank_w[46]
  PIN bank_w[470]
    DIRECTION INPUT ;
    USE SIGNAL ;
    PORT
      LAYER M4 ;
        RECT  0 117.696 0.084 117.72 ;
    END
  END bank_w[470]
  PIN bank_w[471]
    DIRECTION INPUT ;
    USE SIGNAL ;
    PORT
      LAYER M4 ;
        RECT  0 117.984 0.084 118.008 ;
    END
  END bank_w[471]
  PIN bank_w[472]
    DIRECTION INPUT ;
    USE SIGNAL ;
    PORT
      LAYER M4 ;
        RECT  0 118.224 0.084 118.248 ;
    END
  END bank_w[472]
  PIN bank_w[473]
    DIRECTION INPUT ;
    USE SIGNAL ;
    PORT
      LAYER M4 ;
        RECT  0 118.464 0.084 118.488 ;
    END
  END bank_w[473]
  PIN bank_w[474]
    DIRECTION INPUT ;
    USE SIGNAL ;
    PORT
      LAYER M4 ;
        RECT  0 118.704 0.084 118.728 ;
    END
  END bank_w[474]
  PIN bank_w[475]
    DIRECTION INPUT ;
    USE SIGNAL ;
    PORT
      LAYER M4 ;
        RECT  0 118.944 0.084 118.968 ;
    END
  END bank_w[475]
  PIN bank_w[476]
    DIRECTION INPUT ;
    USE SIGNAL ;
    PORT
      LAYER M4 ;
        RECT  0 119.232 0.084 119.256 ;
    END
  END bank_w[476]
  PIN bank_w[477]
    DIRECTION INPUT ;
    USE SIGNAL ;
    PORT
      LAYER M4 ;
        RECT  0 119.472 0.084 119.496 ;
    END
  END bank_w[477]
  PIN bank_w[478]
    DIRECTION INPUT ;
    USE SIGNAL ;
    PORT
      LAYER M4 ;
        RECT  0 119.712 0.084 119.736 ;
    END
  END bank_w[478]
  PIN bank_w[479]
    DIRECTION INPUT ;
    USE SIGNAL ;
    PORT
      LAYER M4 ;
        RECT  0 119.952 0.084 119.976 ;
    END
  END bank_w[479]
  PIN bank_w[47]
    DIRECTION INPUT ;
    USE SIGNAL ;
    PORT
      LAYER M4 ;
        RECT  0 12.336 0.084 12.36 ;
    END
  END bank_w[47]
  PIN bank_w[480]
    DIRECTION INPUT ;
    USE SIGNAL ;
    PORT
      LAYER M4 ;
        RECT  0 120.192 0.084 120.216 ;
    END
  END bank_w[480]
  PIN bank_w[481]
    DIRECTION INPUT ;
    USE SIGNAL ;
    PORT
      LAYER M4 ;
        RECT  0 120.432 0.084 120.456 ;
    END
  END bank_w[481]
  PIN bank_w[482]
    DIRECTION INPUT ;
    USE SIGNAL ;
    PORT
      LAYER M4 ;
        RECT  0 120.72 0.084 120.744 ;
    END
  END bank_w[482]
  PIN bank_w[483]
    DIRECTION INPUT ;
    USE SIGNAL ;
    PORT
      LAYER M4 ;
        RECT  0 120.96 0.084 120.984 ;
    END
  END bank_w[483]
  PIN bank_w[484]
    DIRECTION INPUT ;
    USE SIGNAL ;
    PORT
      LAYER M4 ;
        RECT  0 121.2 0.084 121.224 ;
    END
  END bank_w[484]
  PIN bank_w[485]
    DIRECTION INPUT ;
    USE SIGNAL ;
    PORT
      LAYER M4 ;
        RECT  0 121.44 0.084 121.464 ;
    END
  END bank_w[485]
  PIN bank_w[486]
    DIRECTION INPUT ;
    USE SIGNAL ;
    PORT
      LAYER M4 ;
        RECT  0 121.68 0.084 121.704 ;
    END
  END bank_w[486]
  PIN bank_w[487]
    DIRECTION INPUT ;
    USE SIGNAL ;
    PORT
      LAYER M4 ;
        RECT  0 121.968 0.084 121.992 ;
    END
  END bank_w[487]
  PIN bank_w[488]
    DIRECTION INPUT ;
    USE SIGNAL ;
    PORT
      LAYER M4 ;
        RECT  0 122.208 0.084 122.232 ;
    END
  END bank_w[488]
  PIN bank_w[489]
    DIRECTION INPUT ;
    USE SIGNAL ;
    PORT
      LAYER M4 ;
        RECT  0 122.448 0.084 122.472 ;
    END
  END bank_w[489]
  PIN bank_w[48]
    DIRECTION INPUT ;
    USE SIGNAL ;
    PORT
      LAYER M4 ;
        RECT  0 12.624 0.084 12.648 ;
    END
  END bank_w[48]
  PIN bank_w[490]
    DIRECTION INPUT ;
    USE SIGNAL ;
    PORT
      LAYER M4 ;
        RECT  0 122.688 0.084 122.712 ;
    END
  END bank_w[490]
  PIN bank_w[491]
    DIRECTION INPUT ;
    USE SIGNAL ;
    PORT
      LAYER M4 ;
        RECT  0 122.928 0.084 122.952 ;
    END
  END bank_w[491]
  PIN bank_w[492]
    DIRECTION INPUT ;
    USE SIGNAL ;
    PORT
      LAYER M4 ;
        RECT  0 123.216 0.084 123.24 ;
    END
  END bank_w[492]
  PIN bank_w[493]
    DIRECTION INPUT ;
    USE SIGNAL ;
    PORT
      LAYER M4 ;
        RECT  0 123.456 0.084 123.48 ;
    END
  END bank_w[493]
  PIN bank_w[494]
    DIRECTION INPUT ;
    USE SIGNAL ;
    PORT
      LAYER M4 ;
        RECT  0 123.696 0.084 123.72 ;
    END
  END bank_w[494]
  PIN bank_w[495]
    DIRECTION INPUT ;
    USE SIGNAL ;
    PORT
      LAYER M4 ;
        RECT  0 123.936 0.084 123.96 ;
    END
  END bank_w[495]
  PIN bank_w[496]
    DIRECTION INPUT ;
    USE SIGNAL ;
    PORT
      LAYER M4 ;
        RECT  0 124.176 0.084 124.2 ;
    END
  END bank_w[496]
  PIN bank_w[497]
    DIRECTION INPUT ;
    USE SIGNAL ;
    PORT
      LAYER M4 ;
        RECT  0 124.464 0.084 124.488 ;
    END
  END bank_w[497]
  PIN bank_w[498]
    DIRECTION INPUT ;
    USE SIGNAL ;
    PORT
      LAYER M4 ;
        RECT  0 124.704 0.084 124.728 ;
    END
  END bank_w[498]
  PIN bank_w[499]
    DIRECTION INPUT ;
    USE SIGNAL ;
    PORT
      LAYER M4 ;
        RECT  0 124.944 0.084 124.968 ;
    END
  END bank_w[499]
  PIN bank_w[49]
    DIRECTION INPUT ;
    USE SIGNAL ;
    PORT
      LAYER M4 ;
        RECT  0 12.864 0.084 12.888 ;
    END
  END bank_w[49]
  PIN bank_w[4]
    DIRECTION INPUT ;
    USE SIGNAL ;
    PORT
      LAYER M4 ;
        RECT  0 1.632 0.084 1.656 ;
    END
  END bank_w[4]
  PIN bank_w[500]
    DIRECTION INPUT ;
    USE SIGNAL ;
    PORT
      LAYER M4 ;
        RECT  0 125.184 0.084 125.208 ;
    END
  END bank_w[500]
  PIN bank_w[501]
    DIRECTION INPUT ;
    USE SIGNAL ;
    PORT
      LAYER M4 ;
        RECT  0 125.424 0.084 125.448 ;
    END
  END bank_w[501]
  PIN bank_w[502]
    DIRECTION INPUT ;
    USE SIGNAL ;
    PORT
      LAYER M4 ;
        RECT  0 125.664 0.084 125.688 ;
    END
  END bank_w[502]
  PIN bank_w[503]
    DIRECTION INPUT ;
    USE SIGNAL ;
    PORT
      LAYER M4 ;
        RECT  0 125.952 0.084 125.976 ;
    END
  END bank_w[503]
  PIN bank_w[504]
    DIRECTION INPUT ;
    USE SIGNAL ;
    PORT
      LAYER M4 ;
        RECT  0 126.192 0.084 126.216 ;
    END
  END bank_w[504]
  PIN bank_w[505]
    DIRECTION INPUT ;
    USE SIGNAL ;
    PORT
      LAYER M4 ;
        RECT  0 126.432 0.084 126.456 ;
    END
  END bank_w[505]
  PIN bank_w[506]
    DIRECTION INPUT ;
    USE SIGNAL ;
    PORT
      LAYER M4 ;
        RECT  0 126.672 0.084 126.696 ;
    END
  END bank_w[506]
  PIN bank_w[507]
    DIRECTION INPUT ;
    USE SIGNAL ;
    PORT
      LAYER M4 ;
        RECT  0 126.912 0.084 126.936 ;
    END
  END bank_w[507]
  PIN bank_w[508]
    DIRECTION INPUT ;
    USE SIGNAL ;
    PORT
      LAYER M4 ;
        RECT  0 127.2 0.084 127.224 ;
    END
  END bank_w[508]
  PIN bank_w[509]
    DIRECTION INPUT ;
    USE SIGNAL ;
    PORT
      LAYER M4 ;
        RECT  0 127.44 0.084 127.464 ;
    END
  END bank_w[509]
  PIN bank_w[50]
    DIRECTION INPUT ;
    USE SIGNAL ;
    PORT
      LAYER M4 ;
        RECT  0 13.104 0.084 13.128 ;
    END
  END bank_w[50]
  PIN bank_w[510]
    DIRECTION INPUT ;
    USE SIGNAL ;
    PORT
      LAYER M4 ;
        RECT  0 127.68 0.084 127.704 ;
    END
  END bank_w[510]
  PIN bank_w[511]
    DIRECTION INPUT ;
    USE SIGNAL ;
    PORT
      LAYER M4 ;
        RECT  0 127.92 0.084 127.944 ;
    END
  END bank_w[511]
  PIN bank_w[512]
    DIRECTION INPUT ;
    USE SIGNAL ;
    PORT
      LAYER M4 ;
        RECT  0 128.16 0.084 128.184 ;
    END
  END bank_w[512]
  PIN bank_w[513]
    DIRECTION INPUT ;
    USE SIGNAL ;
    PORT
      LAYER M4 ;
        RECT  0 128.448 0.084 128.472 ;
    END
  END bank_w[513]
  PIN bank_w[514]
    DIRECTION INPUT ;
    USE SIGNAL ;
    PORT
      LAYER M4 ;
        RECT  0 128.688 0.084 128.712 ;
    END
  END bank_w[514]
  PIN bank_w[515]
    DIRECTION INPUT ;
    USE SIGNAL ;
    PORT
      LAYER M4 ;
        RECT  0 128.928 0.084 128.952 ;
    END
  END bank_w[515]
  PIN bank_w[51]
    DIRECTION INPUT ;
    USE SIGNAL ;
    PORT
      LAYER M4 ;
        RECT  0 13.344 0.084 13.368 ;
    END
  END bank_w[51]
  PIN bank_w[52]
    DIRECTION INPUT ;
    USE SIGNAL ;
    PORT
      LAYER M4 ;
        RECT  0 13.584 0.084 13.608 ;
    END
  END bank_w[52]
  PIN bank_w[53]
    DIRECTION INPUT ;
    USE SIGNAL ;
    PORT
      LAYER M4 ;
        RECT  0 13.872 0.084 13.896 ;
    END
  END bank_w[53]
  PIN bank_w[54]
    DIRECTION INPUT ;
    USE SIGNAL ;
    PORT
      LAYER M4 ;
        RECT  0 14.112 0.084 14.136 ;
    END
  END bank_w[54]
  PIN bank_w[55]
    DIRECTION INPUT ;
    USE SIGNAL ;
    PORT
      LAYER M4 ;
        RECT  0 14.352 0.084 14.376 ;
    END
  END bank_w[55]
  PIN bank_w[56]
    DIRECTION INPUT ;
    USE SIGNAL ;
    PORT
      LAYER M4 ;
        RECT  0 14.592 0.084 14.616 ;
    END
  END bank_w[56]
  PIN bank_w[57]
    DIRECTION INPUT ;
    USE SIGNAL ;
    PORT
      LAYER M4 ;
        RECT  0 14.832 0.084 14.856 ;
    END
  END bank_w[57]
  PIN bank_w[58]
    DIRECTION INPUT ;
    USE SIGNAL ;
    PORT
      LAYER M4 ;
        RECT  0 15.12 0.084 15.144 ;
    END
  END bank_w[58]
  PIN bank_w[59]
    DIRECTION INPUT ;
    USE SIGNAL ;
    PORT
      LAYER M4 ;
        RECT  0 15.36 0.084 15.384 ;
    END
  END bank_w[59]
  PIN bank_w[5]
    DIRECTION INPUT ;
    USE SIGNAL ;
    PORT
      LAYER M4 ;
        RECT  0 1.92 0.084 1.944 ;
    END
  END bank_w[5]
  PIN bank_w[60]
    DIRECTION INPUT ;
    USE SIGNAL ;
    PORT
      LAYER M4 ;
        RECT  0 15.6 0.084 15.624 ;
    END
  END bank_w[60]
  PIN bank_w[61]
    DIRECTION INPUT ;
    USE SIGNAL ;
    PORT
      LAYER M4 ;
        RECT  0 15.84 0.084 15.864 ;
    END
  END bank_w[61]
  PIN bank_w[62]
    DIRECTION INPUT ;
    USE SIGNAL ;
    PORT
      LAYER M4 ;
        RECT  0 16.08 0.084 16.104 ;
    END
  END bank_w[62]
  PIN bank_w[63]
    DIRECTION INPUT ;
    USE SIGNAL ;
    PORT
      LAYER M4 ;
        RECT  0 16.368 0.084 16.392 ;
    END
  END bank_w[63]
  PIN bank_w[64]
    DIRECTION INPUT ;
    USE SIGNAL ;
    PORT
      LAYER M4 ;
        RECT  0 16.608 0.084 16.632 ;
    END
  END bank_w[64]
  PIN bank_w[65]
    DIRECTION INPUT ;
    USE SIGNAL ;
    PORT
      LAYER M4 ;
        RECT  0 16.848 0.084 16.872 ;
    END
  END bank_w[65]
  PIN bank_w[66]
    DIRECTION INPUT ;
    USE SIGNAL ;
    PORT
      LAYER M4 ;
        RECT  0 17.088 0.084 17.112 ;
    END
  END bank_w[66]
  PIN bank_w[67]
    DIRECTION INPUT ;
    USE SIGNAL ;
    PORT
      LAYER M4 ;
        RECT  0 17.328 0.084 17.352 ;
    END
  END bank_w[67]
  PIN bank_w[68]
    DIRECTION INPUT ;
    USE SIGNAL ;
    PORT
      LAYER M4 ;
        RECT  0 17.568 0.084 17.592 ;
    END
  END bank_w[68]
  PIN bank_w[69]
    DIRECTION INPUT ;
    USE SIGNAL ;
    PORT
      LAYER M4 ;
        RECT  0 17.856 0.084 17.88 ;
    END
  END bank_w[69]
  PIN bank_w[6]
    DIRECTION INPUT ;
    USE SIGNAL ;
    PORT
      LAYER M4 ;
        RECT  0 2.16 0.084 2.184 ;
    END
  END bank_w[6]
  PIN bank_w[70]
    DIRECTION INPUT ;
    USE SIGNAL ;
    PORT
      LAYER M4 ;
        RECT  0 18.096 0.084 18.12 ;
    END
  END bank_w[70]
  PIN bank_w[71]
    DIRECTION INPUT ;
    USE SIGNAL ;
    PORT
      LAYER M4 ;
        RECT  0 18.336 0.084 18.36 ;
    END
  END bank_w[71]
  PIN bank_w[72]
    DIRECTION INPUT ;
    USE SIGNAL ;
    PORT
      LAYER M4 ;
        RECT  0 18.576 0.084 18.6 ;
    END
  END bank_w[72]
  PIN bank_w[73]
    DIRECTION INPUT ;
    USE SIGNAL ;
    PORT
      LAYER M4 ;
        RECT  0 18.816 0.084 18.84 ;
    END
  END bank_w[73]
  PIN bank_w[74]
    DIRECTION INPUT ;
    USE SIGNAL ;
    PORT
      LAYER M4 ;
        RECT  0 19.104 0.084 19.128 ;
    END
  END bank_w[74]
  PIN bank_w[75]
    DIRECTION INPUT ;
    USE SIGNAL ;
    PORT
      LAYER M4 ;
        RECT  0 19.344 0.084 19.368 ;
    END
  END bank_w[75]
  PIN bank_w[76]
    DIRECTION INPUT ;
    USE SIGNAL ;
    PORT
      LAYER M4 ;
        RECT  0 19.584 0.084 19.608 ;
    END
  END bank_w[76]
  PIN bank_w[77]
    DIRECTION INPUT ;
    USE SIGNAL ;
    PORT
      LAYER M4 ;
        RECT  0 19.824 0.084 19.848 ;
    END
  END bank_w[77]
  PIN bank_w[78]
    DIRECTION INPUT ;
    USE SIGNAL ;
    PORT
      LAYER M4 ;
        RECT  0 20.064 0.084 20.088 ;
    END
  END bank_w[78]
  PIN bank_w[79]
    DIRECTION INPUT ;
    USE SIGNAL ;
    PORT
      LAYER M4 ;
        RECT  0 20.352 0.084 20.376 ;
    END
  END bank_w[79]
  PIN bank_w[7]
    DIRECTION INPUT ;
    USE SIGNAL ;
    PORT
      LAYER M4 ;
        RECT  0 2.4 0.084 2.424 ;
    END
  END bank_w[7]
  PIN bank_w[80]
    DIRECTION INPUT ;
    USE SIGNAL ;
    PORT
      LAYER M4 ;
        RECT  0 20.592 0.084 20.616 ;
    END
  END bank_w[80]
  PIN bank_w[81]
    DIRECTION INPUT ;
    USE SIGNAL ;
    PORT
      LAYER M4 ;
        RECT  0 20.832 0.084 20.856 ;
    END
  END bank_w[81]
  PIN bank_w[82]
    DIRECTION INPUT ;
    USE SIGNAL ;
    PORT
      LAYER M4 ;
        RECT  0 21.072 0.084 21.096 ;
    END
  END bank_w[82]
  PIN bank_w[83]
    DIRECTION INPUT ;
    USE SIGNAL ;
    PORT
      LAYER M4 ;
        RECT  0 21.312 0.084 21.336 ;
    END
  END bank_w[83]
  PIN bank_w[84]
    DIRECTION INPUT ;
    USE SIGNAL ;
    PORT
      LAYER M4 ;
        RECT  0 21.552 0.084 21.576 ;
    END
  END bank_w[84]
  PIN bank_w[85]
    DIRECTION INPUT ;
    USE SIGNAL ;
    PORT
      LAYER M4 ;
        RECT  0 21.84 0.084 21.864 ;
    END
  END bank_w[85]
  PIN bank_w[86]
    DIRECTION INPUT ;
    USE SIGNAL ;
    PORT
      LAYER M4 ;
        RECT  0 22.08 0.084 22.104 ;
    END
  END bank_w[86]
  PIN bank_w[87]
    DIRECTION INPUT ;
    USE SIGNAL ;
    PORT
      LAYER M4 ;
        RECT  0 22.32 0.084 22.344 ;
    END
  END bank_w[87]
  PIN bank_w[88]
    DIRECTION INPUT ;
    USE SIGNAL ;
    PORT
      LAYER M4 ;
        RECT  0 22.56 0.084 22.584 ;
    END
  END bank_w[88]
  PIN bank_w[89]
    DIRECTION INPUT ;
    USE SIGNAL ;
    PORT
      LAYER M4 ;
        RECT  0 22.8 0.084 22.824 ;
    END
  END bank_w[89]
  PIN bank_w[8]
    DIRECTION INPUT ;
    USE SIGNAL ;
    PORT
      LAYER M4 ;
        RECT  0 2.64 0.084 2.664 ;
    END
  END bank_w[8]
  PIN bank_w[90]
    DIRECTION INPUT ;
    USE SIGNAL ;
    PORT
      LAYER M4 ;
        RECT  0 23.088 0.084 23.112 ;
    END
  END bank_w[90]
  PIN bank_w[91]
    DIRECTION INPUT ;
    USE SIGNAL ;
    PORT
      LAYER M4 ;
        RECT  0 23.328 0.084 23.352 ;
    END
  END bank_w[91]
  PIN bank_w[92]
    DIRECTION INPUT ;
    USE SIGNAL ;
    PORT
      LAYER M4 ;
        RECT  0 23.568 0.084 23.592 ;
    END
  END bank_w[92]
  PIN bank_w[93]
    DIRECTION INPUT ;
    USE SIGNAL ;
    PORT
      LAYER M4 ;
        RECT  0 23.808 0.084 23.832 ;
    END
  END bank_w[93]
  PIN bank_w[94]
    DIRECTION INPUT ;
    USE SIGNAL ;
    PORT
      LAYER M4 ;
        RECT  0 24.048 0.084 24.072 ;
    END
  END bank_w[94]
  PIN bank_w[95]
    DIRECTION INPUT ;
    USE SIGNAL ;
    PORT
      LAYER M4 ;
        RECT  0 24.336 0.084 24.36 ;
    END
  END bank_w[95]
  PIN bank_w[96]
    DIRECTION INPUT ;
    USE SIGNAL ;
    PORT
      LAYER M4 ;
        RECT  0 24.576 0.084 24.6 ;
    END
  END bank_w[96]
  PIN bank_w[97]
    DIRECTION INPUT ;
    USE SIGNAL ;
    PORT
      LAYER M4 ;
        RECT  0 24.816 0.084 24.84 ;
    END
  END bank_w[97]
  PIN bank_w[98]
    DIRECTION INPUT ;
    USE SIGNAL ;
    PORT
      LAYER M4 ;
        RECT  0 25.056 0.084 25.08 ;
    END
  END bank_w[98]
  PIN bank_w[99]
    DIRECTION INPUT ;
    USE SIGNAL ;
    PORT
      LAYER M4 ;
        RECT  0 25.296 0.084 25.32 ;
    END
  END bank_w[99]
  PIN bank_w[9]
    DIRECTION INPUT ;
    USE SIGNAL ;
    PORT
      LAYER M4 ;
        RECT  0 2.88 0.084 2.904 ;
    END
  END bank_w[9]
  PIN ck
    DIRECTION INPUT ;
    USE SIGNAL ;
    PORT
      LAYER M3 ;
        RECT  29.7 0 29.718 0.038 ;
    END
  END ck
  PIN o[0]
    DIRECTION OUTPUT ;
    USE SIGNAL ;
    PORT
      LAYER M3 ;
        RECT  0.648 129.562 0.666 129.6 ;
    END
  END o[0]
  PIN o[100]
    DIRECTION OUTPUT ;
    USE SIGNAL ;
    PORT
      LAYER M3 ;
        RECT  25.344 129.562 25.362 129.6 ;
    END
  END o[100]
  PIN o[101]
    DIRECTION OUTPUT ;
    USE SIGNAL ;
    PORT
      LAYER M5 ;
        RECT  25.584 129.516 25.608 129.6 ;
    END
  END o[101]
  PIN o[102]
    DIRECTION OUTPUT ;
    USE SIGNAL ;
    PORT
      LAYER M3 ;
        RECT  25.848 129.562 25.866 129.6 ;
    END
  END o[102]
  PIN o[103]
    DIRECTION OUTPUT ;
    USE SIGNAL ;
    PORT
      LAYER M5 ;
        RECT  26.112 129.516 26.136 129.6 ;
    END
  END o[103]
  PIN o[104]
    DIRECTION OUTPUT ;
    USE SIGNAL ;
    PORT
      LAYER M3 ;
        RECT  26.352 129.562 26.37 129.6 ;
    END
  END o[104]
  PIN o[105]
    DIRECTION OUTPUT ;
    USE SIGNAL ;
    PORT
      LAYER M5 ;
        RECT  26.592 129.516 26.616 129.6 ;
    END
  END o[105]
  PIN o[106]
    DIRECTION OUTPUT ;
    USE SIGNAL ;
    PORT
      LAYER M3 ;
        RECT  26.82 129.562 26.838 129.6 ;
    END
  END o[106]
  PIN o[107]
    DIRECTION OUTPUT ;
    USE SIGNAL ;
    PORT
      LAYER M5 ;
        RECT  27.072 129.516 27.096 129.6 ;
    END
  END o[107]
  PIN o[108]
    DIRECTION OUTPUT ;
    USE SIGNAL ;
    PORT
      LAYER M3 ;
        RECT  27.324 129.562 27.342 129.6 ;
    END
  END o[108]
  PIN o[109]
    DIRECTION OUTPUT ;
    USE SIGNAL ;
    PORT
      LAYER M5 ;
        RECT  27.552 129.516 27.576 129.6 ;
    END
  END o[109]
  PIN o[10]
    DIRECTION OUTPUT ;
    USE SIGNAL ;
    PORT
      LAYER M3 ;
        RECT  3.132 129.562 3.15 129.6 ;
    END
  END o[10]
  PIN o[110]
    DIRECTION OUTPUT ;
    USE SIGNAL ;
    PORT
      LAYER M3 ;
        RECT  27.828 129.562 27.846 129.6 ;
    END
  END o[110]
  PIN o[111]
    DIRECTION OUTPUT ;
    USE SIGNAL ;
    PORT
      LAYER M5 ;
        RECT  28.08 129.516 28.104 129.6 ;
    END
  END o[111]
  PIN o[112]
    DIRECTION OUTPUT ;
    USE SIGNAL ;
    PORT
      LAYER M3 ;
        RECT  28.332 129.562 28.35 129.6 ;
    END
  END o[112]
  PIN o[113]
    DIRECTION OUTPUT ;
    USE SIGNAL ;
    PORT
      LAYER M5 ;
        RECT  28.56 129.516 28.584 129.6 ;
    END
  END o[113]
  PIN o[114]
    DIRECTION OUTPUT ;
    USE SIGNAL ;
    PORT
      LAYER M3 ;
        RECT  28.8 129.562 28.818 129.6 ;
    END
  END o[114]
  PIN o[115]
    DIRECTION OUTPUT ;
    USE SIGNAL ;
    PORT
      LAYER M5 ;
        RECT  29.04 129.516 29.064 129.6 ;
    END
  END o[115]
  PIN o[116]
    DIRECTION OUTPUT ;
    USE SIGNAL ;
    PORT
      LAYER M3 ;
        RECT  29.304 129.562 29.322 129.6 ;
    END
  END o[116]
  PIN o[117]
    DIRECTION OUTPUT ;
    USE SIGNAL ;
    PORT
      LAYER M5 ;
        RECT  29.568 129.516 29.592 129.6 ;
    END
  END o[117]
  PIN o[118]
    DIRECTION OUTPUT ;
    USE SIGNAL ;
    PORT
      LAYER M3 ;
        RECT  29.808 129.562 29.826 129.6 ;
    END
  END o[118]
  PIN o[119]
    DIRECTION OUTPUT ;
    USE SIGNAL ;
    PORT
      LAYER M5 ;
        RECT  30.048 129.516 30.072 129.6 ;
    END
  END o[119]
  PIN o[11]
    DIRECTION OUTPUT ;
    USE SIGNAL ;
    PORT
      LAYER M5 ;
        RECT  3.36 129.516 3.384 129.6 ;
    END
  END o[11]
  PIN o[120]
    DIRECTION OUTPUT ;
    USE SIGNAL ;
    PORT
      LAYER M3 ;
        RECT  30.276 129.562 30.294 129.6 ;
    END
  END o[120]
  PIN o[121]
    DIRECTION OUTPUT ;
    USE SIGNAL ;
    PORT
      LAYER M5 ;
        RECT  30.528 129.516 30.552 129.6 ;
    END
  END o[121]
  PIN o[122]
    DIRECTION OUTPUT ;
    USE SIGNAL ;
    PORT
      LAYER M3 ;
        RECT  30.78 129.562 30.798 129.6 ;
    END
  END o[122]
  PIN o[123]
    DIRECTION OUTPUT ;
    USE SIGNAL ;
    PORT
      LAYER M5 ;
        RECT  31.008 129.516 31.032 129.6 ;
    END
  END o[123]
  PIN o[124]
    DIRECTION OUTPUT ;
    USE SIGNAL ;
    PORT
      LAYER M3 ;
        RECT  31.284 129.562 31.302 129.6 ;
    END
  END o[124]
  PIN o[125]
    DIRECTION OUTPUT ;
    USE SIGNAL ;
    PORT
      LAYER M5 ;
        RECT  31.536 129.516 31.56 129.6 ;
    END
  END o[125]
  PIN o[126]
    DIRECTION OUTPUT ;
    USE SIGNAL ;
    PORT
      LAYER M3 ;
        RECT  31.788 129.562 31.806 129.6 ;
    END
  END o[126]
  PIN o[127]
    DIRECTION OUTPUT ;
    USE SIGNAL ;
    PORT
      LAYER M5 ;
        RECT  32.016 129.516 32.04 129.6 ;
    END
  END o[127]
  PIN o[128]
    DIRECTION OUTPUT ;
    USE SIGNAL ;
    PORT
      LAYER M3 ;
        RECT  32.256 129.562 32.274 129.6 ;
    END
  END o[128]
  PIN o[129]
    DIRECTION OUTPUT ;
    USE SIGNAL ;
    PORT
      LAYER M5 ;
        RECT  32.496 129.516 32.52 129.6 ;
    END
  END o[129]
  PIN o[12]
    DIRECTION OUTPUT ;
    USE SIGNAL ;
    PORT
      LAYER M3 ;
        RECT  3.636 129.562 3.654 129.6 ;
    END
  END o[12]
  PIN o[130]
    DIRECTION OUTPUT ;
    USE SIGNAL ;
    PORT
      LAYER M3 ;
        RECT  32.76 129.562 32.778 129.6 ;
    END
  END o[130]
  PIN o[131]
    DIRECTION OUTPUT ;
    USE SIGNAL ;
    PORT
      LAYER M5 ;
        RECT  33.024 129.516 33.048 129.6 ;
    END
  END o[131]
  PIN o[132]
    DIRECTION OUTPUT ;
    USE SIGNAL ;
    PORT
      LAYER M3 ;
        RECT  33.264 129.562 33.282 129.6 ;
    END
  END o[132]
  PIN o[133]
    DIRECTION OUTPUT ;
    USE SIGNAL ;
    PORT
      LAYER M5 ;
        RECT  33.504 129.516 33.528 129.6 ;
    END
  END o[133]
  PIN o[134]
    DIRECTION OUTPUT ;
    USE SIGNAL ;
    PORT
      LAYER M3 ;
        RECT  33.732 129.562 33.75 129.6 ;
    END
  END o[134]
  PIN o[135]
    DIRECTION OUTPUT ;
    USE SIGNAL ;
    PORT
      LAYER M5 ;
        RECT  33.984 129.516 34.008 129.6 ;
    END
  END o[135]
  PIN o[136]
    DIRECTION OUTPUT ;
    USE SIGNAL ;
    PORT
      LAYER M3 ;
        RECT  34.236 129.562 34.254 129.6 ;
    END
  END o[136]
  PIN o[137]
    DIRECTION OUTPUT ;
    USE SIGNAL ;
    PORT
      LAYER M5 ;
        RECT  34.464 129.516 34.488 129.6 ;
    END
  END o[137]
  PIN o[138]
    DIRECTION OUTPUT ;
    USE SIGNAL ;
    PORT
      LAYER M3 ;
        RECT  34.74 129.562 34.758 129.6 ;
    END
  END o[138]
  PIN o[139]
    DIRECTION OUTPUT ;
    USE SIGNAL ;
    PORT
      LAYER M5 ;
        RECT  34.992 129.516 35.016 129.6 ;
    END
  END o[139]
  PIN o[13]
    DIRECTION OUTPUT ;
    USE SIGNAL ;
    PORT
      LAYER M5 ;
        RECT  3.84 129.516 3.864 129.6 ;
    END
  END o[13]
  PIN o[140]
    DIRECTION OUTPUT ;
    USE SIGNAL ;
    PORT
      LAYER M3 ;
        RECT  35.244 129.562 35.262 129.6 ;
    END
  END o[140]
  PIN o[141]
    DIRECTION OUTPUT ;
    USE SIGNAL ;
    PORT
      LAYER M5 ;
        RECT  35.472 129.516 35.496 129.6 ;
    END
  END o[141]
  PIN o[142]
    DIRECTION OUTPUT ;
    USE SIGNAL ;
    PORT
      LAYER M3 ;
        RECT  35.712 129.562 35.73 129.6 ;
    END
  END o[142]
  PIN o[143]
    DIRECTION OUTPUT ;
    USE SIGNAL ;
    PORT
      LAYER M5 ;
        RECT  35.952 129.516 35.976 129.6 ;
    END
  END o[143]
  PIN o[144]
    DIRECTION OUTPUT ;
    USE SIGNAL ;
    PORT
      LAYER M3 ;
        RECT  36.216 129.562 36.234 129.6 ;
    END
  END o[144]
  PIN o[145]
    DIRECTION OUTPUT ;
    USE SIGNAL ;
    PORT
      LAYER M5 ;
        RECT  36.48 129.516 36.504 129.6 ;
    END
  END o[145]
  PIN o[146]
    DIRECTION OUTPUT ;
    USE SIGNAL ;
    PORT
      LAYER M3 ;
        RECT  36.72 129.562 36.738 129.6 ;
    END
  END o[146]
  PIN o[147]
    DIRECTION OUTPUT ;
    USE SIGNAL ;
    PORT
      LAYER M5 ;
        RECT  36.96 129.516 36.984 129.6 ;
    END
  END o[147]
  PIN o[148]
    DIRECTION OUTPUT ;
    USE SIGNAL ;
    PORT
      LAYER M3 ;
        RECT  37.224 129.562 37.242 129.6 ;
    END
  END o[148]
  PIN o[149]
    DIRECTION OUTPUT ;
    USE SIGNAL ;
    PORT
      LAYER M5 ;
        RECT  37.44 129.516 37.464 129.6 ;
    END
  END o[149]
  PIN o[14]
    DIRECTION OUTPUT ;
    USE SIGNAL ;
    PORT
      LAYER M3 ;
        RECT  4.104 129.562 4.122 129.6 ;
    END
  END o[14]
  PIN o[150]
    DIRECTION OUTPUT ;
    USE SIGNAL ;
    PORT
      LAYER M3 ;
        RECT  37.692 129.562 37.71 129.6 ;
    END
  END o[150]
  PIN o[151]
    DIRECTION OUTPUT ;
    USE SIGNAL ;
    PORT
      LAYER M5 ;
        RECT  37.968 129.516 37.992 129.6 ;
    END
  END o[151]
  PIN o[152]
    DIRECTION OUTPUT ;
    USE SIGNAL ;
    PORT
      LAYER M3 ;
        RECT  38.196 129.562 38.214 129.6 ;
    END
  END o[152]
  PIN o[153]
    DIRECTION OUTPUT ;
    USE SIGNAL ;
    PORT
      LAYER M5 ;
        RECT  38.448 129.516 38.472 129.6 ;
    END
  END o[153]
  PIN o[154]
    DIRECTION OUTPUT ;
    USE SIGNAL ;
    PORT
      LAYER M3 ;
        RECT  38.7 129.562 38.718 129.6 ;
    END
  END o[154]
  PIN o[155]
    DIRECTION OUTPUT ;
    USE SIGNAL ;
    PORT
      LAYER M5 ;
        RECT  38.928 129.516 38.952 129.6 ;
    END
  END o[155]
  PIN o[156]
    DIRECTION OUTPUT ;
    USE SIGNAL ;
    PORT
      LAYER M3 ;
        RECT  39.168 129.562 39.186 129.6 ;
    END
  END o[156]
  PIN o[157]
    DIRECTION OUTPUT ;
    USE SIGNAL ;
    PORT
      LAYER M5 ;
        RECT  39.408 129.516 39.432 129.6 ;
    END
  END o[157]
  PIN o[158]
    DIRECTION OUTPUT ;
    USE SIGNAL ;
    PORT
      LAYER M3 ;
        RECT  39.672 129.562 39.69 129.6 ;
    END
  END o[158]
  PIN o[159]
    DIRECTION OUTPUT ;
    USE SIGNAL ;
    PORT
      LAYER M5 ;
        RECT  39.936 129.516 39.96 129.6 ;
    END
  END o[159]
  PIN o[15]
    DIRECTION OUTPUT ;
    USE SIGNAL ;
    PORT
      LAYER M5 ;
        RECT  4.368 129.516 4.392 129.6 ;
    END
  END o[15]
  PIN o[160]
    DIRECTION OUTPUT ;
    USE SIGNAL ;
    PORT
      LAYER M3 ;
        RECT  40.176 129.562 40.194 129.6 ;
    END
  END o[160]
  PIN o[161]
    DIRECTION OUTPUT ;
    USE SIGNAL ;
    PORT
      LAYER M5 ;
        RECT  40.416 129.516 40.44 129.6 ;
    END
  END o[161]
  PIN o[162]
    DIRECTION OUTPUT ;
    USE SIGNAL ;
    PORT
      LAYER M3 ;
        RECT  40.68 129.562 40.698 129.6 ;
    END
  END o[162]
  PIN o[163]
    DIRECTION OUTPUT ;
    USE SIGNAL ;
    PORT
      LAYER M5 ;
        RECT  40.896 129.516 40.92 129.6 ;
    END
  END o[163]
  PIN o[164]
    DIRECTION OUTPUT ;
    USE SIGNAL ;
    PORT
      LAYER M3 ;
        RECT  41.148 129.562 41.166 129.6 ;
    END
  END o[164]
  PIN o[165]
    DIRECTION OUTPUT ;
    USE SIGNAL ;
    PORT
      LAYER M5 ;
        RECT  41.424 129.516 41.448 129.6 ;
    END
  END o[165]
  PIN o[166]
    DIRECTION OUTPUT ;
    USE SIGNAL ;
    PORT
      LAYER M3 ;
        RECT  41.652 129.562 41.67 129.6 ;
    END
  END o[166]
  PIN o[167]
    DIRECTION OUTPUT ;
    USE SIGNAL ;
    PORT
      LAYER M5 ;
        RECT  41.904 129.516 41.928 129.6 ;
    END
  END o[167]
  PIN o[168]
    DIRECTION OUTPUT ;
    USE SIGNAL ;
    PORT
      LAYER M3 ;
        RECT  42.156 129.562 42.174 129.6 ;
    END
  END o[168]
  PIN o[169]
    DIRECTION OUTPUT ;
    USE SIGNAL ;
    PORT
      LAYER M5 ;
        RECT  42.384 129.516 42.408 129.6 ;
    END
  END o[169]
  PIN o[16]
    DIRECTION OUTPUT ;
    USE SIGNAL ;
    PORT
      LAYER M3 ;
        RECT  4.608 129.562 4.626 129.6 ;
    END
  END o[16]
  PIN o[170]
    DIRECTION OUTPUT ;
    USE SIGNAL ;
    PORT
      LAYER M3 ;
        RECT  42.624 129.562 42.642 129.6 ;
    END
  END o[170]
  PIN o[171]
    DIRECTION OUTPUT ;
    USE SIGNAL ;
    PORT
      LAYER M5 ;
        RECT  42.864 129.516 42.888 129.6 ;
    END
  END o[171]
  PIN o[172]
    DIRECTION OUTPUT ;
    USE SIGNAL ;
    PORT
      LAYER M3 ;
        RECT  43.128 129.562 43.146 129.6 ;
    END
  END o[172]
  PIN o[173]
    DIRECTION OUTPUT ;
    USE SIGNAL ;
    PORT
      LAYER M5 ;
        RECT  43.392 129.516 43.416 129.6 ;
    END
  END o[173]
  PIN o[174]
    DIRECTION OUTPUT ;
    USE SIGNAL ;
    PORT
      LAYER M3 ;
        RECT  43.632 129.562 43.65 129.6 ;
    END
  END o[174]
  PIN o[175]
    DIRECTION OUTPUT ;
    USE SIGNAL ;
    PORT
      LAYER M5 ;
        RECT  43.872 129.516 43.896 129.6 ;
    END
  END o[175]
  PIN o[176]
    DIRECTION OUTPUT ;
    USE SIGNAL ;
    PORT
      LAYER M3 ;
        RECT  44.136 129.562 44.154 129.6 ;
    END
  END o[176]
  PIN o[177]
    DIRECTION OUTPUT ;
    USE SIGNAL ;
    PORT
      LAYER M5 ;
        RECT  44.352 129.516 44.376 129.6 ;
    END
  END o[177]
  PIN o[178]
    DIRECTION OUTPUT ;
    USE SIGNAL ;
    PORT
      LAYER M3 ;
        RECT  44.604 129.562 44.622 129.6 ;
    END
  END o[178]
  PIN o[179]
    DIRECTION OUTPUT ;
    USE SIGNAL ;
    PORT
      LAYER M5 ;
        RECT  44.88 129.516 44.904 129.6 ;
    END
  END o[179]
  PIN o[17]
    DIRECTION OUTPUT ;
    USE SIGNAL ;
    PORT
      LAYER M5 ;
        RECT  4.848 129.516 4.872 129.6 ;
    END
  END o[17]
  PIN o[180]
    DIRECTION OUTPUT ;
    USE SIGNAL ;
    PORT
      LAYER M3 ;
        RECT  45.108 129.562 45.126 129.6 ;
    END
  END o[180]
  PIN o[181]
    DIRECTION OUTPUT ;
    USE SIGNAL ;
    PORT
      LAYER M5 ;
        RECT  45.36 129.516 45.384 129.6 ;
    END
  END o[181]
  PIN o[182]
    DIRECTION OUTPUT ;
    USE SIGNAL ;
    PORT
      LAYER M3 ;
        RECT  45.612 129.562 45.63 129.6 ;
    END
  END o[182]
  PIN o[183]
    DIRECTION OUTPUT ;
    USE SIGNAL ;
    PORT
      LAYER M5 ;
        RECT  45.84 129.516 45.864 129.6 ;
    END
  END o[183]
  PIN o[184]
    DIRECTION OUTPUT ;
    USE SIGNAL ;
    PORT
      LAYER M3 ;
        RECT  46.116 129.562 46.134 129.6 ;
    END
  END o[184]
  PIN o[185]
    DIRECTION OUTPUT ;
    USE SIGNAL ;
    PORT
      LAYER M5 ;
        RECT  46.32 129.516 46.344 129.6 ;
    END
  END o[185]
  PIN o[186]
    DIRECTION OUTPUT ;
    USE SIGNAL ;
    PORT
      LAYER M3 ;
        RECT  46.584 129.562 46.602 129.6 ;
    END
  END o[186]
  PIN o[187]
    DIRECTION OUTPUT ;
    USE SIGNAL ;
    PORT
      LAYER M5 ;
        RECT  46.848 129.516 46.872 129.6 ;
    END
  END o[187]
  PIN o[188]
    DIRECTION OUTPUT ;
    USE SIGNAL ;
    PORT
      LAYER M3 ;
        RECT  47.088 129.562 47.106 129.6 ;
    END
  END o[188]
  PIN o[189]
    DIRECTION OUTPUT ;
    USE SIGNAL ;
    PORT
      LAYER M5 ;
        RECT  47.328 129.516 47.352 129.6 ;
    END
  END o[189]
  PIN o[18]
    DIRECTION OUTPUT ;
    USE SIGNAL ;
    PORT
      LAYER M3 ;
        RECT  5.112 129.562 5.13 129.6 ;
    END
  END o[18]
  PIN o[190]
    DIRECTION OUTPUT ;
    USE SIGNAL ;
    PORT
      LAYER M3 ;
        RECT  47.592 129.562 47.61 129.6 ;
    END
  END o[190]
  PIN o[191]
    DIRECTION OUTPUT ;
    USE SIGNAL ;
    PORT
      LAYER M5 ;
        RECT  47.808 129.516 47.832 129.6 ;
    END
  END o[191]
  PIN o[192]
    DIRECTION OUTPUT ;
    USE SIGNAL ;
    PORT
      LAYER M3 ;
        RECT  48.06 129.562 48.078 129.6 ;
    END
  END o[192]
  PIN o[193]
    DIRECTION OUTPUT ;
    USE SIGNAL ;
    PORT
      LAYER M5 ;
        RECT  48.336 129.516 48.36 129.6 ;
    END
  END o[193]
  PIN o[194]
    DIRECTION OUTPUT ;
    USE SIGNAL ;
    PORT
      LAYER M3 ;
        RECT  48.564 129.562 48.582 129.6 ;
    END
  END o[194]
  PIN o[195]
    DIRECTION OUTPUT ;
    USE SIGNAL ;
    PORT
      LAYER M5 ;
        RECT  48.816 129.516 48.84 129.6 ;
    END
  END o[195]
  PIN o[196]
    DIRECTION OUTPUT ;
    USE SIGNAL ;
    PORT
      LAYER M3 ;
        RECT  49.068 129.562 49.086 129.6 ;
    END
  END o[196]
  PIN o[197]
    DIRECTION OUTPUT ;
    USE SIGNAL ;
    PORT
      LAYER M5 ;
        RECT  49.296 129.516 49.32 129.6 ;
    END
  END o[197]
  PIN o[198]
    DIRECTION OUTPUT ;
    USE SIGNAL ;
    PORT
      LAYER M3 ;
        RECT  49.572 129.562 49.59 129.6 ;
    END
  END o[198]
  PIN o[199]
    DIRECTION OUTPUT ;
    USE SIGNAL ;
    PORT
      LAYER M5 ;
        RECT  49.824 129.516 49.848 129.6 ;
    END
  END o[199]
  PIN o[19]
    DIRECTION OUTPUT ;
    USE SIGNAL ;
    PORT
      LAYER M5 ;
        RECT  5.328 129.516 5.352 129.6 ;
    END
  END o[19]
  PIN o[1]
    DIRECTION OUTPUT ;
    USE SIGNAL ;
    PORT
      LAYER M5 ;
        RECT  0.912 129.516 0.936 129.6 ;
    END
  END o[1]
  PIN o[200]
    DIRECTION OUTPUT ;
    USE SIGNAL ;
    PORT
      LAYER M3 ;
        RECT  50.04 129.562 50.058 129.6 ;
    END
  END o[200]
  PIN o[201]
    DIRECTION OUTPUT ;
    USE SIGNAL ;
    PORT
      LAYER M5 ;
        RECT  50.304 129.516 50.328 129.6 ;
    END
  END o[201]
  PIN o[202]
    DIRECTION OUTPUT ;
    USE SIGNAL ;
    PORT
      LAYER M3 ;
        RECT  50.544 129.562 50.562 129.6 ;
    END
  END o[202]
  PIN o[203]
    DIRECTION OUTPUT ;
    USE SIGNAL ;
    PORT
      LAYER M5 ;
        RECT  50.784 129.516 50.808 129.6 ;
    END
  END o[203]
  PIN o[204]
    DIRECTION OUTPUT ;
    USE SIGNAL ;
    PORT
      LAYER M3 ;
        RECT  51.048 129.562 51.066 129.6 ;
    END
  END o[204]
  PIN o[205]
    DIRECTION OUTPUT ;
    USE SIGNAL ;
    PORT
      LAYER M5 ;
        RECT  51.264 129.516 51.288 129.6 ;
    END
  END o[205]
  PIN o[206]
    DIRECTION OUTPUT ;
    USE SIGNAL ;
    PORT
      LAYER M3 ;
        RECT  51.516 129.562 51.534 129.6 ;
    END
  END o[206]
  PIN o[207]
    DIRECTION OUTPUT ;
    USE SIGNAL ;
    PORT
      LAYER M5 ;
        RECT  51.792 129.516 51.816 129.6 ;
    END
  END o[207]
  PIN o[208]
    DIRECTION OUTPUT ;
    USE SIGNAL ;
    PORT
      LAYER M3 ;
        RECT  52.02 129.562 52.038 129.6 ;
    END
  END o[208]
  PIN o[209]
    DIRECTION OUTPUT ;
    USE SIGNAL ;
    PORT
      LAYER M5 ;
        RECT  52.272 129.516 52.296 129.6 ;
    END
  END o[209]
  PIN o[20]
    DIRECTION OUTPUT ;
    USE SIGNAL ;
    PORT
      LAYER M3 ;
        RECT  5.58 129.562 5.598 129.6 ;
    END
  END o[20]
  PIN o[210]
    DIRECTION OUTPUT ;
    USE SIGNAL ;
    PORT
      LAYER M3 ;
        RECT  52.524 129.562 52.542 129.6 ;
    END
  END o[210]
  PIN o[211]
    DIRECTION OUTPUT ;
    USE SIGNAL ;
    PORT
      LAYER M5 ;
        RECT  52.752 129.516 52.776 129.6 ;
    END
  END o[211]
  PIN o[212]
    DIRECTION OUTPUT ;
    USE SIGNAL ;
    PORT
      LAYER M3 ;
        RECT  53.028 129.562 53.046 129.6 ;
    END
  END o[212]
  PIN o[213]
    DIRECTION OUTPUT ;
    USE SIGNAL ;
    PORT
      LAYER M5 ;
        RECT  53.28 129.516 53.304 129.6 ;
    END
  END o[213]
  PIN o[214]
    DIRECTION OUTPUT ;
    USE SIGNAL ;
    PORT
      LAYER M3 ;
        RECT  53.496 129.562 53.514 129.6 ;
    END
  END o[214]
  PIN o[215]
    DIRECTION OUTPUT ;
    USE SIGNAL ;
    PORT
      LAYER M5 ;
        RECT  53.76 129.516 53.784 129.6 ;
    END
  END o[215]
  PIN o[216]
    DIRECTION OUTPUT ;
    USE SIGNAL ;
    PORT
      LAYER M3 ;
        RECT  54 129.562 54.018 129.6 ;
    END
  END o[216]
  PIN o[217]
    DIRECTION OUTPUT ;
    USE SIGNAL ;
    PORT
      LAYER M5 ;
        RECT  54.24 129.516 54.264 129.6 ;
    END
  END o[217]
  PIN o[218]
    DIRECTION OUTPUT ;
    USE SIGNAL ;
    PORT
      LAYER M3 ;
        RECT  54.504 129.562 54.522 129.6 ;
    END
  END o[218]
  PIN o[219]
    DIRECTION OUTPUT ;
    USE SIGNAL ;
    PORT
      LAYER M5 ;
        RECT  54.72 129.516 54.744 129.6 ;
    END
  END o[219]
  PIN o[21]
    DIRECTION OUTPUT ;
    USE SIGNAL ;
    PORT
      LAYER M5 ;
        RECT  5.856 129.516 5.88 129.6 ;
    END
  END o[21]
  PIN o[220]
    DIRECTION OUTPUT ;
    USE SIGNAL ;
    PORT
      LAYER M3 ;
        RECT  54.972 129.562 54.99 129.6 ;
    END
  END o[220]
  PIN o[221]
    DIRECTION OUTPUT ;
    USE SIGNAL ;
    PORT
      LAYER M5 ;
        RECT  55.248 129.516 55.272 129.6 ;
    END
  END o[221]
  PIN o[222]
    DIRECTION OUTPUT ;
    USE SIGNAL ;
    PORT
      LAYER M3 ;
        RECT  55.476 129.562 55.494 129.6 ;
    END
  END o[222]
  PIN o[223]
    DIRECTION OUTPUT ;
    USE SIGNAL ;
    PORT
      LAYER M5 ;
        RECT  55.728 129.516 55.752 129.6 ;
    END
  END o[223]
  PIN o[224]
    DIRECTION OUTPUT ;
    USE SIGNAL ;
    PORT
      LAYER M3 ;
        RECT  55.98 129.562 55.998 129.6 ;
    END
  END o[224]
  PIN o[225]
    DIRECTION OUTPUT ;
    USE SIGNAL ;
    PORT
      LAYER M5 ;
        RECT  56.208 129.516 56.232 129.6 ;
    END
  END o[225]
  PIN o[226]
    DIRECTION OUTPUT ;
    USE SIGNAL ;
    PORT
      LAYER M3 ;
        RECT  56.484 129.562 56.502 129.6 ;
    END
  END o[226]
  PIN o[227]
    DIRECTION OUTPUT ;
    USE SIGNAL ;
    PORT
      LAYER M5 ;
        RECT  56.736 129.516 56.76 129.6 ;
    END
  END o[227]
  PIN o[228]
    DIRECTION OUTPUT ;
    USE SIGNAL ;
    PORT
      LAYER M3 ;
        RECT  56.952 129.562 56.97 129.6 ;
    END
  END o[228]
  PIN o[229]
    DIRECTION OUTPUT ;
    USE SIGNAL ;
    PORT
      LAYER M5 ;
        RECT  57.216 129.516 57.24 129.6 ;
    END
  END o[229]
  PIN o[22]
    DIRECTION OUTPUT ;
    USE SIGNAL ;
    PORT
      LAYER M3 ;
        RECT  6.084 129.562 6.102 129.6 ;
    END
  END o[22]
  PIN o[230]
    DIRECTION OUTPUT ;
    USE SIGNAL ;
    PORT
      LAYER M3 ;
        RECT  57.456 129.562 57.474 129.6 ;
    END
  END o[230]
  PIN o[231]
    DIRECTION OUTPUT ;
    USE SIGNAL ;
    PORT
      LAYER M5 ;
        RECT  57.696 129.516 57.72 129.6 ;
    END
  END o[231]
  PIN o[232]
    DIRECTION OUTPUT ;
    USE SIGNAL ;
    PORT
      LAYER M3 ;
        RECT  57.96 129.562 57.978 129.6 ;
    END
  END o[232]
  PIN o[233]
    DIRECTION OUTPUT ;
    USE SIGNAL ;
    PORT
      LAYER M5 ;
        RECT  58.176 129.516 58.2 129.6 ;
    END
  END o[233]
  PIN o[234]
    DIRECTION OUTPUT ;
    USE SIGNAL ;
    PORT
      LAYER M3 ;
        RECT  58.464 129.562 58.482 129.6 ;
    END
  END o[234]
  PIN o[235]
    DIRECTION OUTPUT ;
    USE SIGNAL ;
    PORT
      LAYER M5 ;
        RECT  58.704 129.516 58.728 129.6 ;
    END
  END o[235]
  PIN o[236]
    DIRECTION OUTPUT ;
    USE SIGNAL ;
    PORT
      LAYER M3 ;
        RECT  58.932 129.562 58.95 129.6 ;
    END
  END o[236]
  PIN o[237]
    DIRECTION OUTPUT ;
    USE SIGNAL ;
    PORT
      LAYER M5 ;
        RECT  59.184 129.516 59.208 129.6 ;
    END
  END o[237]
  PIN o[238]
    DIRECTION OUTPUT ;
    USE SIGNAL ;
    PORT
      LAYER M3 ;
        RECT  59.436 129.562 59.454 129.6 ;
    END
  END o[238]
  PIN o[239]
    DIRECTION OUTPUT ;
    USE SIGNAL ;
    PORT
      LAYER M5 ;
        RECT  59.664 129.516 59.688 129.6 ;
    END
  END o[239]
  PIN o[23]
    DIRECTION OUTPUT ;
    USE SIGNAL ;
    PORT
      LAYER M5 ;
        RECT  6.336 129.516 6.36 129.6 ;
    END
  END o[23]
  PIN o[240]
    DIRECTION OUTPUT ;
    USE SIGNAL ;
    PORT
      LAYER M3 ;
        RECT  59.94 129.562 59.958 129.6 ;
    END
  END o[240]
  PIN o[241]
    DIRECTION OUTPUT ;
    USE SIGNAL ;
    PORT
      LAYER M5 ;
        RECT  60.192 129.516 60.216 129.6 ;
    END
  END o[241]
  PIN o[242]
    DIRECTION OUTPUT ;
    USE SIGNAL ;
    PORT
      LAYER M3 ;
        RECT  60.408 129.562 60.426 129.6 ;
    END
  END o[242]
  PIN o[243]
    DIRECTION OUTPUT ;
    USE SIGNAL ;
    PORT
      LAYER M5 ;
        RECT  60.672 129.516 60.696 129.6 ;
    END
  END o[243]
  PIN o[244]
    DIRECTION OUTPUT ;
    USE SIGNAL ;
    PORT
      LAYER M3 ;
        RECT  60.912 129.562 60.93 129.6 ;
    END
  END o[244]
  PIN o[245]
    DIRECTION OUTPUT ;
    USE SIGNAL ;
    PORT
      LAYER M5 ;
        RECT  61.152 129.516 61.176 129.6 ;
    END
  END o[245]
  PIN o[246]
    DIRECTION OUTPUT ;
    USE SIGNAL ;
    PORT
      LAYER M3 ;
        RECT  61.416 129.562 61.434 129.6 ;
    END
  END o[246]
  PIN o[247]
    DIRECTION OUTPUT ;
    USE SIGNAL ;
    PORT
      LAYER M5 ;
        RECT  61.632 129.516 61.656 129.6 ;
    END
  END o[247]
  PIN o[248]
    DIRECTION OUTPUT ;
    USE SIGNAL ;
    PORT
      LAYER M3 ;
        RECT  61.92 129.562 61.938 129.6 ;
    END
  END o[248]
  PIN o[249]
    DIRECTION OUTPUT ;
    USE SIGNAL ;
    PORT
      LAYER M5 ;
        RECT  62.16 129.516 62.184 129.6 ;
    END
  END o[249]
  PIN o[24]
    DIRECTION OUTPUT ;
    USE SIGNAL ;
    PORT
      LAYER M3 ;
        RECT  6.588 129.562 6.606 129.6 ;
    END
  END o[24]
  PIN o[250]
    DIRECTION OUTPUT ;
    USE SIGNAL ;
    PORT
      LAYER M3 ;
        RECT  62.388 129.562 62.406 129.6 ;
    END
  END o[250]
  PIN o[251]
    DIRECTION OUTPUT ;
    USE SIGNAL ;
    PORT
      LAYER M5 ;
        RECT  62.64 129.516 62.664 129.6 ;
    END
  END o[251]
  PIN o[252]
    DIRECTION OUTPUT ;
    USE SIGNAL ;
    PORT
      LAYER M3 ;
        RECT  62.892 129.562 62.91 129.6 ;
    END
  END o[252]
  PIN o[253]
    DIRECTION OUTPUT ;
    USE SIGNAL ;
    PORT
      LAYER M5 ;
        RECT  63.12 129.516 63.144 129.6 ;
    END
  END o[253]
  PIN o[254]
    DIRECTION OUTPUT ;
    USE SIGNAL ;
    PORT
      LAYER M3 ;
        RECT  63.396 129.562 63.414 129.6 ;
    END
  END o[254]
  PIN o[255]
    DIRECTION OUTPUT ;
    USE SIGNAL ;
    PORT
      LAYER M5 ;
        RECT  63.648 129.516 63.672 129.6 ;
    END
  END o[255]
  PIN o[256]
    DIRECTION OUTPUT ;
    USE SIGNAL ;
    PORT
      LAYER M3 ;
        RECT  63.864 129.562 63.882 129.6 ;
    END
  END o[256]
  PIN o[257]
    DIRECTION OUTPUT ;
    USE SIGNAL ;
    PORT
      LAYER M5 ;
        RECT  64.128 129.516 64.152 129.6 ;
    END
  END o[257]
  PIN o[25]
    DIRECTION OUTPUT ;
    USE SIGNAL ;
    PORT
      LAYER M5 ;
        RECT  6.816 129.516 6.84 129.6 ;
    END
  END o[25]
  PIN o[26]
    DIRECTION OUTPUT ;
    USE SIGNAL ;
    PORT
      LAYER M3 ;
        RECT  7.092 129.562 7.11 129.6 ;
    END
  END o[26]
  PIN o[27]
    DIRECTION OUTPUT ;
    USE SIGNAL ;
    PORT
      LAYER M5 ;
        RECT  7.344 129.516 7.368 129.6 ;
    END
  END o[27]
  PIN o[28]
    DIRECTION OUTPUT ;
    USE SIGNAL ;
    PORT
      LAYER M3 ;
        RECT  7.56 129.562 7.578 129.6 ;
    END
  END o[28]
  PIN o[29]
    DIRECTION OUTPUT ;
    USE SIGNAL ;
    PORT
      LAYER M5 ;
        RECT  7.824 129.516 7.848 129.6 ;
    END
  END o[29]
  PIN o[2]
    DIRECTION OUTPUT ;
    USE SIGNAL ;
    PORT
      LAYER M3 ;
        RECT  1.152 129.562 1.17 129.6 ;
    END
  END o[2]
  PIN o[30]
    DIRECTION OUTPUT ;
    USE SIGNAL ;
    PORT
      LAYER M3 ;
        RECT  8.064 129.562 8.082 129.6 ;
    END
  END o[30]
  PIN o[31]
    DIRECTION OUTPUT ;
    USE SIGNAL ;
    PORT
      LAYER M5 ;
        RECT  8.304 129.516 8.328 129.6 ;
    END
  END o[31]
  PIN o[32]
    DIRECTION OUTPUT ;
    USE SIGNAL ;
    PORT
      LAYER M3 ;
        RECT  8.568 129.562 8.586 129.6 ;
    END
  END o[32]
  PIN o[33]
    DIRECTION OUTPUT ;
    USE SIGNAL ;
    PORT
      LAYER M5 ;
        RECT  8.784 129.516 8.808 129.6 ;
    END
  END o[33]
  PIN o[34]
    DIRECTION OUTPUT ;
    USE SIGNAL ;
    PORT
      LAYER M3 ;
        RECT  9.036 129.562 9.054 129.6 ;
    END
  END o[34]
  PIN o[35]
    DIRECTION OUTPUT ;
    USE SIGNAL ;
    PORT
      LAYER M5 ;
        RECT  9.312 129.516 9.336 129.6 ;
    END
  END o[35]
  PIN o[36]
    DIRECTION OUTPUT ;
    USE SIGNAL ;
    PORT
      LAYER M3 ;
        RECT  9.54 129.562 9.558 129.6 ;
    END
  END o[36]
  PIN o[37]
    DIRECTION OUTPUT ;
    USE SIGNAL ;
    PORT
      LAYER M5 ;
        RECT  9.792 129.516 9.816 129.6 ;
    END
  END o[37]
  PIN o[38]
    DIRECTION OUTPUT ;
    USE SIGNAL ;
    PORT
      LAYER M3 ;
        RECT  10.044 129.562 10.062 129.6 ;
    END
  END o[38]
  PIN o[39]
    DIRECTION OUTPUT ;
    USE SIGNAL ;
    PORT
      LAYER M5 ;
        RECT  10.272 129.516 10.296 129.6 ;
    END
  END o[39]
  PIN o[3]
    DIRECTION OUTPUT ;
    USE SIGNAL ;
    PORT
      LAYER M5 ;
        RECT  1.392 129.516 1.416 129.6 ;
    END
  END o[3]
  PIN o[40]
    DIRECTION OUTPUT ;
    USE SIGNAL ;
    PORT
      LAYER M3 ;
        RECT  10.548 129.562 10.566 129.6 ;
    END
  END o[40]
  PIN o[41]
    DIRECTION OUTPUT ;
    USE SIGNAL ;
    PORT
      LAYER M5 ;
        RECT  10.8 129.516 10.824 129.6 ;
    END
  END o[41]
  PIN o[42]
    DIRECTION OUTPUT ;
    USE SIGNAL ;
    PORT
      LAYER M3 ;
        RECT  11.016 129.562 11.034 129.6 ;
    END
  END o[42]
  PIN o[43]
    DIRECTION OUTPUT ;
    USE SIGNAL ;
    PORT
      LAYER M5 ;
        RECT  11.28 129.516 11.304 129.6 ;
    END
  END o[43]
  PIN o[44]
    DIRECTION OUTPUT ;
    USE SIGNAL ;
    PORT
      LAYER M3 ;
        RECT  11.52 129.562 11.538 129.6 ;
    END
  END o[44]
  PIN o[45]
    DIRECTION OUTPUT ;
    USE SIGNAL ;
    PORT
      LAYER M5 ;
        RECT  11.76 129.516 11.784 129.6 ;
    END
  END o[45]
  PIN o[46]
    DIRECTION OUTPUT ;
    USE SIGNAL ;
    PORT
      LAYER M3 ;
        RECT  12.024 129.562 12.042 129.6 ;
    END
  END o[46]
  PIN o[47]
    DIRECTION OUTPUT ;
    USE SIGNAL ;
    PORT
      LAYER M5 ;
        RECT  12.24 129.516 12.264 129.6 ;
    END
  END o[47]
  PIN o[48]
    DIRECTION OUTPUT ;
    USE SIGNAL ;
    PORT
      LAYER M3 ;
        RECT  12.492 129.562 12.51 129.6 ;
    END
  END o[48]
  PIN o[49]
    DIRECTION OUTPUT ;
    USE SIGNAL ;
    PORT
      LAYER M5 ;
        RECT  12.768 129.516 12.792 129.6 ;
    END
  END o[49]
  PIN o[4]
    DIRECTION OUTPUT ;
    USE SIGNAL ;
    PORT
      LAYER M3 ;
        RECT  1.656 129.562 1.674 129.6 ;
    END
  END o[4]
  PIN o[50]
    DIRECTION OUTPUT ;
    USE SIGNAL ;
    PORT
      LAYER M3 ;
        RECT  12.996 129.562 13.014 129.6 ;
    END
  END o[50]
  PIN o[51]
    DIRECTION OUTPUT ;
    USE SIGNAL ;
    PORT
      LAYER M5 ;
        RECT  13.248 129.516 13.272 129.6 ;
    END
  END o[51]
  PIN o[52]
    DIRECTION OUTPUT ;
    USE SIGNAL ;
    PORT
      LAYER M3 ;
        RECT  13.5 129.562 13.518 129.6 ;
    END
  END o[52]
  PIN o[53]
    DIRECTION OUTPUT ;
    USE SIGNAL ;
    PORT
      LAYER M5 ;
        RECT  13.728 129.516 13.752 129.6 ;
    END
  END o[53]
  PIN o[54]
    DIRECTION OUTPUT ;
    USE SIGNAL ;
    PORT
      LAYER M3 ;
        RECT  14.004 129.562 14.022 129.6 ;
    END
  END o[54]
  PIN o[55]
    DIRECTION OUTPUT ;
    USE SIGNAL ;
    PORT
      LAYER M5 ;
        RECT  14.256 129.516 14.28 129.6 ;
    END
  END o[55]
  PIN o[56]
    DIRECTION OUTPUT ;
    USE SIGNAL ;
    PORT
      LAYER M3 ;
        RECT  14.472 129.562 14.49 129.6 ;
    END
  END o[56]
  PIN o[57]
    DIRECTION OUTPUT ;
    USE SIGNAL ;
    PORT
      LAYER M5 ;
        RECT  14.736 129.516 14.76 129.6 ;
    END
  END o[57]
  PIN o[58]
    DIRECTION OUTPUT ;
    USE SIGNAL ;
    PORT
      LAYER M3 ;
        RECT  14.976 129.562 14.994 129.6 ;
    END
  END o[58]
  PIN o[59]
    DIRECTION OUTPUT ;
    USE SIGNAL ;
    PORT
      LAYER M5 ;
        RECT  15.216 129.516 15.24 129.6 ;
    END
  END o[59]
  PIN o[5]
    DIRECTION OUTPUT ;
    USE SIGNAL ;
    PORT
      LAYER M5 ;
        RECT  1.872 129.516 1.896 129.6 ;
    END
  END o[5]
  PIN o[60]
    DIRECTION OUTPUT ;
    USE SIGNAL ;
    PORT
      LAYER M3 ;
        RECT  15.48 129.562 15.498 129.6 ;
    END
  END o[60]
  PIN o[61]
    DIRECTION OUTPUT ;
    USE SIGNAL ;
    PORT
      LAYER M5 ;
        RECT  15.696 129.516 15.72 129.6 ;
    END
  END o[61]
  PIN o[62]
    DIRECTION OUTPUT ;
    USE SIGNAL ;
    PORT
      LAYER M3 ;
        RECT  15.984 129.562 16.002 129.6 ;
    END
  END o[62]
  PIN o[63]
    DIRECTION OUTPUT ;
    USE SIGNAL ;
    PORT
      LAYER M5 ;
        RECT  16.224 129.516 16.248 129.6 ;
    END
  END o[63]
  PIN o[64]
    DIRECTION OUTPUT ;
    USE SIGNAL ;
    PORT
      LAYER M3 ;
        RECT  16.452 129.562 16.47 129.6 ;
    END
  END o[64]
  PIN o[65]
    DIRECTION OUTPUT ;
    USE SIGNAL ;
    PORT
      LAYER M5 ;
        RECT  16.704 129.516 16.728 129.6 ;
    END
  END o[65]
  PIN o[66]
    DIRECTION OUTPUT ;
    USE SIGNAL ;
    PORT
      LAYER M3 ;
        RECT  16.956 129.562 16.974 129.6 ;
    END
  END o[66]
  PIN o[67]
    DIRECTION OUTPUT ;
    USE SIGNAL ;
    PORT
      LAYER M5 ;
        RECT  17.184 129.516 17.208 129.6 ;
    END
  END o[67]
  PIN o[68]
    DIRECTION OUTPUT ;
    USE SIGNAL ;
    PORT
      LAYER M3 ;
        RECT  17.46 129.562 17.478 129.6 ;
    END
  END o[68]
  PIN o[69]
    DIRECTION OUTPUT ;
    USE SIGNAL ;
    PORT
      LAYER M5 ;
        RECT  17.712 129.516 17.736 129.6 ;
    END
  END o[69]
  PIN o[6]
    DIRECTION OUTPUT ;
    USE SIGNAL ;
    PORT
      LAYER M3 ;
        RECT  2.124 129.562 2.142 129.6 ;
    END
  END o[6]
  PIN o[70]
    DIRECTION OUTPUT ;
    USE SIGNAL ;
    PORT
      LAYER M3 ;
        RECT  17.928 129.562 17.946 129.6 ;
    END
  END o[70]
  PIN o[71]
    DIRECTION OUTPUT ;
    USE SIGNAL ;
    PORT
      LAYER M5 ;
        RECT  18.192 129.516 18.216 129.6 ;
    END
  END o[71]
  PIN o[72]
    DIRECTION OUTPUT ;
    USE SIGNAL ;
    PORT
      LAYER M3 ;
        RECT  18.432 129.562 18.45 129.6 ;
    END
  END o[72]
  PIN o[73]
    DIRECTION OUTPUT ;
    USE SIGNAL ;
    PORT
      LAYER M5 ;
        RECT  18.672 129.516 18.696 129.6 ;
    END
  END o[73]
  PIN o[74]
    DIRECTION OUTPUT ;
    USE SIGNAL ;
    PORT
      LAYER M3 ;
        RECT  18.936 129.562 18.954 129.6 ;
    END
  END o[74]
  PIN o[75]
    DIRECTION OUTPUT ;
    USE SIGNAL ;
    PORT
      LAYER M5 ;
        RECT  19.152 129.516 19.176 129.6 ;
    END
  END o[75]
  PIN o[76]
    DIRECTION OUTPUT ;
    USE SIGNAL ;
    PORT
      LAYER M3 ;
        RECT  19.44 129.562 19.458 129.6 ;
    END
  END o[76]
  PIN o[77]
    DIRECTION OUTPUT ;
    USE SIGNAL ;
    PORT
      LAYER M5 ;
        RECT  19.68 129.516 19.704 129.6 ;
    END
  END o[77]
  PIN o[78]
    DIRECTION OUTPUT ;
    USE SIGNAL ;
    PORT
      LAYER M3 ;
        RECT  19.908 129.562 19.926 129.6 ;
    END
  END o[78]
  PIN o[79]
    DIRECTION OUTPUT ;
    USE SIGNAL ;
    PORT
      LAYER M5 ;
        RECT  20.16 129.516 20.184 129.6 ;
    END
  END o[79]
  PIN o[7]
    DIRECTION OUTPUT ;
    USE SIGNAL ;
    PORT
      LAYER M5 ;
        RECT  2.4 129.516 2.424 129.6 ;
    END
  END o[7]
  PIN o[80]
    DIRECTION OUTPUT ;
    USE SIGNAL ;
    PORT
      LAYER M3 ;
        RECT  20.412 129.562 20.43 129.6 ;
    END
  END o[80]
  PIN o[81]
    DIRECTION OUTPUT ;
    USE SIGNAL ;
    PORT
      LAYER M5 ;
        RECT  20.64 129.516 20.664 129.6 ;
    END
  END o[81]
  PIN o[82]
    DIRECTION OUTPUT ;
    USE SIGNAL ;
    PORT
      LAYER M3 ;
        RECT  20.916 129.562 20.934 129.6 ;
    END
  END o[82]
  PIN o[83]
    DIRECTION OUTPUT ;
    USE SIGNAL ;
    PORT
      LAYER M5 ;
        RECT  21.168 129.516 21.192 129.6 ;
    END
  END o[83]
  PIN o[84]
    DIRECTION OUTPUT ;
    USE SIGNAL ;
    PORT
      LAYER M3 ;
        RECT  21.384 129.562 21.402 129.6 ;
    END
  END o[84]
  PIN o[85]
    DIRECTION OUTPUT ;
    USE SIGNAL ;
    PORT
      LAYER M5 ;
        RECT  21.648 129.516 21.672 129.6 ;
    END
  END o[85]
  PIN o[86]
    DIRECTION OUTPUT ;
    USE SIGNAL ;
    PORT
      LAYER M3 ;
        RECT  21.888 129.562 21.906 129.6 ;
    END
  END o[86]
  PIN o[87]
    DIRECTION OUTPUT ;
    USE SIGNAL ;
    PORT
      LAYER M5 ;
        RECT  22.128 129.516 22.152 129.6 ;
    END
  END o[87]
  PIN o[88]
    DIRECTION OUTPUT ;
    USE SIGNAL ;
    PORT
      LAYER M3 ;
        RECT  22.392 129.562 22.41 129.6 ;
    END
  END o[88]
  PIN o[89]
    DIRECTION OUTPUT ;
    USE SIGNAL ;
    PORT
      LAYER M5 ;
        RECT  22.656 129.516 22.68 129.6 ;
    END
  END o[89]
  PIN o[8]
    DIRECTION OUTPUT ;
    USE SIGNAL ;
    PORT
      LAYER M3 ;
        RECT  2.628 129.562 2.646 129.6 ;
    END
  END o[8]
  PIN o[90]
    DIRECTION OUTPUT ;
    USE SIGNAL ;
    PORT
      LAYER M3 ;
        RECT  22.896 129.562 22.914 129.6 ;
    END
  END o[90]
  PIN o[91]
    DIRECTION OUTPUT ;
    USE SIGNAL ;
    PORT
      LAYER M5 ;
        RECT  23.136 129.516 23.16 129.6 ;
    END
  END o[91]
  PIN o[92]
    DIRECTION OUTPUT ;
    USE SIGNAL ;
    PORT
      LAYER M3 ;
        RECT  23.364 129.562 23.382 129.6 ;
    END
  END o[92]
  PIN o[93]
    DIRECTION OUTPUT ;
    USE SIGNAL ;
    PORT
      LAYER M5 ;
        RECT  23.616 129.516 23.64 129.6 ;
    END
  END o[93]
  PIN o[94]
    DIRECTION OUTPUT ;
    USE SIGNAL ;
    PORT
      LAYER M3 ;
        RECT  23.868 129.562 23.886 129.6 ;
    END
  END o[94]
  PIN o[95]
    DIRECTION OUTPUT ;
    USE SIGNAL ;
    PORT
      LAYER M5 ;
        RECT  24.096 129.516 24.12 129.6 ;
    END
  END o[95]
  PIN o[96]
    DIRECTION OUTPUT ;
    USE SIGNAL ;
    PORT
      LAYER M3 ;
        RECT  24.372 129.562 24.39 129.6 ;
    END
  END o[96]
  PIN o[97]
    DIRECTION OUTPUT ;
    USE SIGNAL ;
    PORT
      LAYER M5 ;
        RECT  24.624 129.516 24.648 129.6 ;
    END
  END o[97]
  PIN o[98]
    DIRECTION OUTPUT ;
    USE SIGNAL ;
    PORT
      LAYER M3 ;
        RECT  24.876 129.562 24.894 129.6 ;
    END
  END o[98]
  PIN o[99]
    DIRECTION OUTPUT ;
    USE SIGNAL ;
    PORT
      LAYER M5 ;
        RECT  25.104 129.516 25.128 129.6 ;
    END
  END o[99]
  PIN o[9]
    DIRECTION OUTPUT ;
    USE SIGNAL ;
    PORT
      LAYER M5 ;
        RECT  2.88 129.516 2.904 129.6 ;
    END
  END o[9]
  PIN rsi
    DIRECTION INPUT ;
    USE SIGNAL ;
    PORT
      LAYER M3 ;
        RECT  35.1 0 35.118 0.038 ;
    END
  END rsi
  PIN vld[0]
    DIRECTION INPUT ;
    USE SIGNAL ;
    PORT
      LAYER M3 ;
        RECT  40.104 0 40.122 0.038 ;
    END
  END vld[0]
  PIN vld[10]
    DIRECTION INPUT ;
    USE SIGNAL ;
    PORT
      LAYER M3 ;
        RECT  42.372 0 42.39 0.038 ;
    END
  END vld[10]
  PIN vld[11]
    DIRECTION INPUT ;
    USE SIGNAL ;
    PORT
      LAYER M5 ;
        RECT  42.624 0 42.648 0.084 ;
    END
  END vld[11]
  PIN vld[12]
    DIRECTION INPUT ;
    USE SIGNAL ;
    PORT
      LAYER M3 ;
        RECT  42.84 0 42.858 0.038 ;
    END
  END vld[12]
  PIN vld[13]
    DIRECTION INPUT ;
    USE SIGNAL ;
    PORT
      LAYER M5 ;
        RECT  43.056 0 43.08 0.084 ;
    END
  END vld[13]
  PIN vld[14]
    DIRECTION INPUT ;
    USE SIGNAL ;
    PORT
      LAYER M3 ;
        RECT  43.272 0 43.29 0.038 ;
    END
  END vld[14]
  PIN vld[15]
    DIRECTION INPUT ;
    USE SIGNAL ;
    PORT
      LAYER M5 ;
        RECT  43.488 0 43.512 0.084 ;
    END
  END vld[15]
  PIN vld[16]
    DIRECTION INPUT ;
    USE SIGNAL ;
    PORT
      LAYER M3 ;
        RECT  43.74 0 43.758 0.038 ;
    END
  END vld[16]
  PIN vld[17]
    DIRECTION INPUT ;
    USE SIGNAL ;
    PORT
      LAYER M5 ;
        RECT  43.968 0 43.992 0.084 ;
    END
  END vld[17]
  PIN vld[18]
    DIRECTION INPUT ;
    USE SIGNAL ;
    PORT
      LAYER M3 ;
        RECT  44.208 0 44.226 0.038 ;
    END
  END vld[18]
  PIN vld[19]
    DIRECTION INPUT ;
    USE SIGNAL ;
    PORT
      LAYER M5 ;
        RECT  44.4 0 44.424 0.084 ;
    END
  END vld[19]
  PIN vld[1]
    DIRECTION INPUT ;
    USE SIGNAL ;
    PORT
      LAYER M5 ;
        RECT  40.32 0 40.344 0.084 ;
    END
  END vld[1]
  PIN vld[20]
    DIRECTION INPUT ;
    USE SIGNAL ;
    PORT
      LAYER M3 ;
        RECT  44.64 0 44.658 0.038 ;
    END
  END vld[20]
  PIN vld[21]
    DIRECTION INPUT ;
    USE SIGNAL ;
    PORT
      LAYER M5 ;
        RECT  44.88 0 44.904 0.084 ;
    END
  END vld[21]
  PIN vld[22]
    DIRECTION INPUT ;
    USE SIGNAL ;
    PORT
      LAYER M3 ;
        RECT  45.108 0 45.126 0.038 ;
    END
  END vld[22]
  PIN vld[23]
    DIRECTION INPUT ;
    USE SIGNAL ;
    PORT
      LAYER M5 ;
        RECT  45.312 0 45.336 0.084 ;
    END
  END vld[23]
  PIN vld[24]
    DIRECTION INPUT ;
    USE SIGNAL ;
    PORT
      LAYER M3 ;
        RECT  45.576 0 45.594 0.038 ;
    END
  END vld[24]
  PIN vld[25]
    DIRECTION INPUT ;
    USE SIGNAL ;
    PORT
      LAYER M5 ;
        RECT  45.792 0 45.816 0.084 ;
    END
  END vld[25]
  PIN vld[26]
    DIRECTION INPUT ;
    USE SIGNAL ;
    PORT
      LAYER M3 ;
        RECT  46.008 0 46.026 0.038 ;
    END
  END vld[26]
  PIN vld[27]
    DIRECTION INPUT ;
    USE SIGNAL ;
    PORT
      LAYER M5 ;
        RECT  46.224 0 46.248 0.084 ;
    END
  END vld[27]
  PIN vld[28]
    DIRECTION INPUT ;
    USE SIGNAL ;
    PORT
      LAYER M3 ;
        RECT  46.476 0 46.494 0.038 ;
    END
  END vld[28]
  PIN vld[29]
    DIRECTION INPUT ;
    USE SIGNAL ;
    PORT
      LAYER M5 ;
        RECT  46.704 0 46.728 0.084 ;
    END
  END vld[29]
  PIN vld[2]
    DIRECTION INPUT ;
    USE SIGNAL ;
    PORT
      LAYER M3 ;
        RECT  40.572 0 40.59 0.038 ;
    END
  END vld[2]
  PIN vld[30]
    DIRECTION INPUT ;
    USE SIGNAL ;
    PORT
      LAYER M3 ;
        RECT  46.908 0 46.926 0.038 ;
    END
  END vld[30]
  PIN vld[31]
    DIRECTION INPUT ;
    USE SIGNAL ;
    PORT
      LAYER M5 ;
        RECT  47.136 0 47.16 0.084 ;
    END
  END vld[31]
  PIN vld[32]
    DIRECTION INPUT ;
    USE SIGNAL ;
    PORT
      LAYER M3 ;
        RECT  47.376 0 47.394 0.038 ;
    END
  END vld[32]
  PIN vld[33]
    DIRECTION INPUT ;
    USE SIGNAL ;
    PORT
      LAYER M5 ;
        RECT  47.616 0 47.64 0.084 ;
    END
  END vld[33]
  PIN vld[34]
    DIRECTION INPUT ;
    USE SIGNAL ;
    PORT
      LAYER M3 ;
        RECT  47.844 0 47.862 0.038 ;
    END
  END vld[34]
  PIN vld[35]
    DIRECTION INPUT ;
    USE SIGNAL ;
    PORT
      LAYER M5 ;
        RECT  48.048 0 48.072 0.084 ;
    END
  END vld[35]
  PIN vld[36]
    DIRECTION INPUT ;
    USE SIGNAL ;
    PORT
      LAYER M3 ;
        RECT  48.276 0 48.294 0.038 ;
    END
  END vld[36]
  PIN vld[37]
    DIRECTION INPUT ;
    USE SIGNAL ;
    PORT
      LAYER M5 ;
        RECT  48.528 0 48.552 0.084 ;
    END
  END vld[37]
  PIN vld[38]
    DIRECTION INPUT ;
    USE SIGNAL ;
    PORT
      LAYER M3 ;
        RECT  48.744 0 48.762 0.038 ;
    END
  END vld[38]
  PIN vld[39]
    DIRECTION INPUT ;
    USE SIGNAL ;
    PORT
      LAYER M5 ;
        RECT  48.96 0 48.984 0.084 ;
    END
  END vld[39]
  PIN vld[3]
    DIRECTION INPUT ;
    USE SIGNAL ;
    PORT
      LAYER M5 ;
        RECT  40.8 0 40.824 0.084 ;
    END
  END vld[3]
  PIN vld[40]
    DIRECTION INPUT ;
    USE SIGNAL ;
    PORT
      LAYER M3 ;
        RECT  49.212 0 49.23 0.038 ;
    END
  END vld[40]
  PIN vld[41]
    DIRECTION INPUT ;
    USE SIGNAL ;
    PORT
      LAYER M5 ;
        RECT  49.44 0 49.464 0.084 ;
    END
  END vld[41]
  PIN vld[42]
    DIRECTION INPUT ;
    USE SIGNAL ;
    PORT
      LAYER M3 ;
        RECT  49.644 0 49.662 0.038 ;
    END
  END vld[42]
  PIN vld[43]
    DIRECTION INPUT ;
    USE SIGNAL ;
    PORT
      LAYER M5 ;
        RECT  49.872 0 49.896 0.084 ;
    END
  END vld[43]
  PIN vld[4]
    DIRECTION INPUT ;
    USE SIGNAL ;
    PORT
      LAYER M3 ;
        RECT  41.004 0 41.022 0.038 ;
    END
  END vld[4]
  PIN vld[5]
    DIRECTION INPUT ;
    USE SIGNAL ;
    PORT
      LAYER M5 ;
        RECT  41.232 0 41.256 0.084 ;
    END
  END vld[5]
  PIN vld[6]
    DIRECTION INPUT ;
    USE SIGNAL ;
    PORT
      LAYER M3 ;
        RECT  41.472 0 41.49 0.038 ;
    END
  END vld[6]
  PIN vld[7]
    DIRECTION INPUT ;
    USE SIGNAL ;
    PORT
      LAYER M5 ;
        RECT  41.712 0 41.736 0.084 ;
    END
  END vld[7]
  PIN vld[8]
    DIRECTION INPUT ;
    USE SIGNAL ;
    PORT
      LAYER M3 ;
        RECT  41.94 0 41.958 0.038 ;
    END
  END vld[8]
  PIN vld[9]
    DIRECTION INPUT ;
    USE SIGNAL ;
    PORT
      LAYER M5 ;
        RECT  42.144 0 42.168 0.084 ;
    END
  END vld[9]
  PIN VDD
    DIRECTION INOUT ;
    USE POWER ;
    PORT
      LAYER M5 ;
        RECT  61.992 2.151 62.112 127.449 ;
        RECT  56.592 2.151 56.712 127.449 ;
        RECT  51.192 2.151 51.312 127.449 ;
        RECT  45.792 2.151 45.912 127.449 ;
        RECT  40.392 2.151 40.512 127.449 ;
        RECT  34.992 2.151 35.112 127.449 ;
        RECT  29.592 2.151 29.712 127.449 ;
        RECT  24.192 2.151 24.312 127.449 ;
        RECT  18.792 2.151 18.912 127.449 ;
        RECT  13.392 2.151 13.512 127.449 ;
        RECT  7.992 2.151 8.112 127.449 ;
        RECT  2.592 2.151 2.712 127.449 ;
    END
  END VDD
  PIN VSS
    DIRECTION INOUT ;
    USE GROUND ;
    PORT
      LAYER M5 ;
        RECT  61.8 2.137 61.92 127.463 ;
        RECT  56.4 2.137 56.52 127.463 ;
        RECT  51 2.137 51.12 127.463 ;
        RECT  45.6 2.137 45.72 127.463 ;
        RECT  40.2 2.137 40.32 127.463 ;
        RECT  34.8 2.137 34.92 127.463 ;
        RECT  29.4 2.137 29.52 127.463 ;
        RECT  24 2.137 24.12 127.463 ;
        RECT  18.6 2.137 18.72 127.463 ;
        RECT  13.2 2.137 13.32 127.463 ;
        RECT  7.8 2.137 7.92 127.463 ;
        RECT  2.4 2.137 2.52 127.463 ;
    END
  END VSS
  OBS
    LAYER RVTN ;
     RECT  2.16 2.16 62.64 2.295 ;
     RECT  2.16 2.565 62.64 2.835 ;
     RECT  2.16 3.105 62.64 3.375 ;
     RECT  2.16 3.645 62.64 3.915 ;
     RECT  2.16 4.185 62.64 4.455 ;
     RECT  2.16 4.725 62.64 4.995 ;
     RECT  2.16 5.265 62.64 5.535 ;
     RECT  2.16 5.805 62.64 6.075 ;
     RECT  2.16 6.345 62.64 6.615 ;
     RECT  2.16 6.885 62.64 7.155 ;
     RECT  2.16 7.425 62.64 7.695 ;
     RECT  2.16 7.965 62.64 8.235 ;
     RECT  2.16 8.505 62.64 8.775 ;
     RECT  2.16 9.045 62.64 9.315 ;
     RECT  2.16 9.585 62.64 9.855 ;
     RECT  2.16 10.125 62.64 10.395 ;
     RECT  2.16 10.665 62.64 10.935 ;
     RECT  2.16 11.205 62.64 11.475 ;
     RECT  2.16 11.745 62.64 12.015 ;
     RECT  2.16 12.285 62.64 12.555 ;
     RECT  2.16 12.825 62.64 13.095 ;
     RECT  2.16 13.365 62.64 13.635 ;
     RECT  2.16 13.905 62.64 14.175 ;
     RECT  2.16 14.445 62.64 14.715 ;
     RECT  2.16 14.985 62.64 15.255 ;
     RECT  2.16 15.525 62.64 15.795 ;
     RECT  2.16 16.065 62.64 16.335 ;
     RECT  2.16 16.605 62.64 16.875 ;
     RECT  2.16 17.145 62.64 17.415 ;
     RECT  2.16 17.685 62.64 17.955 ;
     RECT  2.16 18.225 62.64 18.495 ;
     RECT  2.16 18.765 62.64 19.035 ;
     RECT  2.16 19.305 62.64 19.575 ;
     RECT  2.16 19.845 62.64 20.115 ;
     RECT  2.16 20.385 62.64 20.655 ;
     RECT  2.16 20.925 62.64 21.195 ;
     RECT  2.16 21.465 62.64 21.735 ;
     RECT  2.16 22.005 62.64 22.275 ;
     RECT  2.16 22.545 62.64 22.815 ;
     RECT  2.16 23.085 62.64 23.355 ;
     RECT  2.16 23.625 62.64 23.895 ;
     RECT  2.16 24.165 62.64 24.435 ;
     RECT  2.16 24.705 62.64 24.975 ;
     RECT  2.16 25.245 62.64 25.515 ;
     RECT  2.16 25.785 62.64 26.055 ;
     RECT  2.16 26.325 62.64 26.595 ;
     RECT  2.16 26.865 62.64 27.135 ;
     RECT  2.16 27.405 62.64 27.675 ;
     RECT  2.16 27.945 62.64 28.215 ;
     RECT  2.16 28.485 62.64 28.755 ;
     RECT  2.16 29.025 62.64 29.295 ;
     RECT  2.16 29.565 62.64 29.835 ;
     RECT  2.16 30.105 62.64 30.375 ;
     RECT  2.16 30.645 62.64 30.915 ;
     RECT  2.16 31.185 62.64 31.455 ;
     RECT  2.16 31.725 62.64 31.995 ;
     RECT  2.16 32.265 62.64 32.535 ;
     RECT  2.16 32.805 62.64 33.075 ;
     RECT  2.16 33.345 62.64 33.615 ;
     RECT  2.16 33.885 62.64 34.155 ;
     RECT  2.16 34.425 62.64 34.695 ;
     RECT  2.16 34.965 62.64 35.235 ;
     RECT  2.16 35.505 62.64 35.775 ;
     RECT  2.16 36.045 62.64 36.315 ;
     RECT  2.16 36.585 62.64 36.855 ;
     RECT  2.16 37.125 62.64 37.395 ;
     RECT  2.16 37.665 62.64 37.935 ;
     RECT  2.16 38.205 62.64 38.475 ;
     RECT  2.16 38.745 62.64 39.015 ;
     RECT  2.16 39.285 62.64 39.555 ;
     RECT  2.16 39.825 62.64 40.095 ;
     RECT  2.16 40.365 62.64 40.635 ;
     RECT  2.16 40.905 62.64 41.175 ;
     RECT  2.16 41.445 62.64 41.715 ;
     RECT  2.16 41.985 62.64 42.255 ;
     RECT  2.16 42.525 62.64 42.795 ;
     RECT  2.16 43.065 62.64 43.335 ;
     RECT  2.16 43.605 62.64 43.875 ;
     RECT  2.16 44.145 62.64 44.415 ;
     RECT  2.16 44.685 62.64 44.955 ;
     RECT  2.16 45.225 62.64 45.495 ;
     RECT  2.16 45.765 62.64 46.035 ;
     RECT  2.16 46.305 62.64 46.575 ;
     RECT  2.16 46.845 62.64 47.115 ;
     RECT  2.16 47.385 62.64 47.655 ;
     RECT  2.16 47.925 62.64 48.195 ;
     RECT  2.16 48.465 62.64 48.735 ;
     RECT  2.16 49.005 62.64 49.275 ;
     RECT  2.16 49.545 62.64 49.815 ;
     RECT  2.16 50.085 62.64 50.355 ;
     RECT  2.16 50.625 62.64 50.895 ;
     RECT  2.16 51.165 62.64 51.435 ;
     RECT  2.16 51.705 62.64 51.975 ;
     RECT  2.16 52.245 62.64 52.515 ;
     RECT  2.16 52.785 62.64 53.055 ;
     RECT  2.16 53.325 62.64 53.595 ;
     RECT  2.16 53.865 62.64 54.135 ;
     RECT  2.16 54.405 62.64 54.675 ;
     RECT  2.16 54.945 62.64 55.215 ;
     RECT  2.16 55.485 62.64 55.755 ;
     RECT  2.16 56.025 62.64 56.295 ;
     RECT  2.16 56.565 62.64 56.835 ;
     RECT  2.16 57.105 62.64 57.375 ;
     RECT  2.16 57.645 62.64 57.915 ;
     RECT  2.16 58.185 62.64 58.455 ;
     RECT  2.16 58.725 62.64 58.995 ;
     RECT  2.16 59.265 62.64 59.535 ;
     RECT  2.16 59.805 62.64 60.075 ;
     RECT  2.16 60.345 62.64 60.615 ;
     RECT  2.16 60.885 62.64 61.155 ;
     RECT  2.16 61.425 62.64 61.695 ;
     RECT  2.16 61.965 62.64 62.235 ;
     RECT  2.16 62.505 62.64 62.775 ;
     RECT  2.16 63.045 62.64 63.315 ;
     RECT  2.16 63.585 62.64 63.855 ;
     RECT  2.16 64.125 62.64 64.395 ;
     RECT  2.16 64.665 62.64 64.935 ;
     RECT  2.16 65.205 62.64 65.475 ;
     RECT  2.16 65.745 62.64 66.015 ;
     RECT  2.16 66.285 62.64 66.555 ;
     RECT  2.16 66.825 62.64 67.095 ;
     RECT  2.16 67.365 62.64 67.635 ;
     RECT  2.16 67.905 62.64 68.175 ;
     RECT  2.16 68.445 62.64 68.715 ;
     RECT  2.16 68.985 62.64 69.255 ;
     RECT  2.16 69.525 62.64 69.795 ;
     RECT  2.16 70.065 62.64 70.335 ;
     RECT  2.16 70.605 62.64 70.875 ;
     RECT  2.16 71.145 62.64 71.415 ;
     RECT  2.16 71.685 62.64 71.955 ;
     RECT  2.16 72.225 62.64 72.495 ;
     RECT  2.16 72.765 62.64 73.035 ;
     RECT  2.16 73.305 62.64 73.575 ;
     RECT  2.16 73.845 62.64 74.115 ;
     RECT  2.16 74.385 62.64 74.655 ;
     RECT  2.16 74.925 62.64 75.195 ;
     RECT  2.16 75.465 62.64 75.735 ;
     RECT  2.16 76.005 62.64 76.275 ;
     RECT  2.16 76.545 62.64 76.815 ;
     RECT  2.16 77.085 62.64 77.355 ;
     RECT  2.16 77.625 62.64 77.895 ;
     RECT  2.16 78.165 62.64 78.435 ;
     RECT  2.16 78.705 62.64 78.975 ;
     RECT  2.16 79.245 62.64 79.515 ;
     RECT  2.16 79.785 62.64 80.055 ;
     RECT  2.16 80.325 62.64 80.595 ;
     RECT  2.16 80.865 62.64 81.135 ;
     RECT  2.16 81.405 62.64 81.675 ;
     RECT  2.16 81.945 62.64 82.215 ;
     RECT  2.16 82.485 62.64 82.755 ;
     RECT  2.16 83.025 62.64 83.295 ;
     RECT  2.16 83.565 62.64 83.835 ;
     RECT  2.16 84.105 62.64 84.375 ;
     RECT  2.16 84.645 62.64 84.915 ;
     RECT  2.16 85.185 62.64 85.455 ;
     RECT  2.16 85.725 62.64 85.995 ;
     RECT  2.16 86.265 62.64 86.535 ;
     RECT  2.16 86.805 62.64 87.075 ;
     RECT  2.16 87.345 62.64 87.615 ;
     RECT  2.16 87.885 62.64 88.155 ;
     RECT  2.16 88.425 62.64 88.695 ;
     RECT  2.16 88.965 62.64 89.235 ;
     RECT  2.16 89.505 62.64 89.775 ;
     RECT  2.16 90.045 62.64 90.315 ;
     RECT  2.16 90.585 62.64 90.855 ;
     RECT  2.16 91.125 62.64 91.395 ;
     RECT  2.16 91.665 62.64 91.935 ;
     RECT  2.16 92.205 62.64 92.475 ;
     RECT  2.16 92.745 62.64 93.015 ;
     RECT  2.16 93.285 62.64 93.555 ;
     RECT  2.16 93.825 62.64 94.095 ;
     RECT  2.16 94.365 62.64 94.635 ;
     RECT  2.16 94.905 62.64 95.175 ;
     RECT  2.16 95.445 62.64 95.715 ;
     RECT  2.16 95.985 62.64 96.255 ;
     RECT  2.16 96.525 62.64 96.795 ;
     RECT  2.16 97.065 62.64 97.335 ;
     RECT  2.16 97.605 62.64 97.875 ;
     RECT  2.16 98.145 62.64 98.415 ;
     RECT  2.16 98.685 62.64 98.955 ;
     RECT  2.16 99.225 62.64 99.495 ;
     RECT  2.16 99.765 62.64 100.035 ;
     RECT  2.16 100.305 62.64 100.575 ;
     RECT  2.16 100.845 62.64 101.115 ;
     RECT  2.16 101.385 62.64 101.655 ;
     RECT  2.16 101.925 62.64 102.195 ;
     RECT  2.16 102.465 62.64 102.735 ;
     RECT  2.16 103.005 62.64 103.275 ;
     RECT  2.16 103.545 62.64 103.815 ;
     RECT  2.16 104.085 62.64 104.355 ;
     RECT  2.16 104.625 62.64 104.895 ;
     RECT  2.16 105.165 62.64 105.435 ;
     RECT  2.16 105.705 62.64 105.975 ;
     RECT  2.16 106.245 62.64 106.515 ;
     RECT  2.16 106.785 62.64 107.055 ;
     RECT  2.16 107.325 62.64 107.595 ;
     RECT  2.16 107.865 62.64 108.135 ;
     RECT  2.16 108.405 62.64 108.675 ;
     RECT  2.16 108.945 62.64 109.215 ;
     RECT  2.16 109.485 62.64 109.755 ;
     RECT  2.16 110.025 62.64 110.295 ;
     RECT  2.16 110.565 62.64 110.835 ;
     RECT  2.16 111.105 62.64 111.375 ;
     RECT  2.16 111.645 62.64 111.915 ;
     RECT  2.16 112.185 62.64 112.455 ;
     RECT  2.16 112.725 62.64 112.995 ;
     RECT  2.16 113.265 62.64 113.535 ;
     RECT  2.16 113.805 62.64 114.075 ;
     RECT  2.16 114.345 62.64 114.615 ;
     RECT  2.16 114.885 62.64 115.155 ;
     RECT  2.16 115.425 62.64 115.695 ;
     RECT  2.16 115.965 62.64 116.235 ;
     RECT  2.16 116.505 62.64 116.775 ;
     RECT  2.16 117.045 62.64 117.315 ;
     RECT  2.16 117.585 62.64 117.855 ;
     RECT  2.16 118.125 62.64 118.395 ;
     RECT  2.16 118.665 62.64 118.935 ;
     RECT  2.16 119.205 62.64 119.475 ;
     RECT  2.16 119.745 62.64 120.015 ;
     RECT  2.16 120.285 62.64 120.555 ;
     RECT  2.16 120.825 62.64 121.095 ;
     RECT  2.16 121.365 62.64 121.635 ;
     RECT  2.16 121.905 62.64 122.175 ;
     RECT  2.16 122.445 62.64 122.715 ;
     RECT  2.16 122.985 62.64 123.255 ;
     RECT  2.16 123.525 62.64 123.795 ;
     RECT  2.16 124.065 62.64 124.335 ;
     RECT  2.16 124.605 62.64 124.875 ;
     RECT  2.16 125.145 62.64 125.415 ;
     RECT  2.16 125.685 62.64 125.955 ;
     RECT  2.16 126.225 62.64 126.495 ;
     RECT  2.16 126.765 62.64 127.035 ;
     RECT  2.16 127.305 62.64 127.44 ;
    LAYER RVTP ;
     RECT  2.16 2.295 62.64 2.565 ;
     RECT  2.16 2.835 62.64 3.105 ;
     RECT  2.16 3.375 62.64 3.645 ;
     RECT  2.16 3.915 62.64 4.185 ;
     RECT  2.16 4.455 62.64 4.725 ;
     RECT  2.16 4.995 62.64 5.265 ;
     RECT  2.16 5.535 62.64 5.805 ;
     RECT  2.16 6.075 62.64 6.345 ;
     RECT  2.16 6.615 62.64 6.885 ;
     RECT  2.16 7.155 62.64 7.425 ;
     RECT  2.16 7.695 62.64 7.965 ;
     RECT  2.16 8.235 62.64 8.505 ;
     RECT  2.16 8.775 62.64 9.045 ;
     RECT  2.16 9.315 62.64 9.585 ;
     RECT  2.16 9.855 62.64 10.125 ;
     RECT  2.16 10.395 62.64 10.665 ;
     RECT  2.16 10.935 62.64 11.205 ;
     RECT  2.16 11.475 62.64 11.745 ;
     RECT  2.16 12.015 62.64 12.285 ;
     RECT  2.16 12.555 62.64 12.825 ;
     RECT  2.16 13.095 62.64 13.365 ;
     RECT  2.16 13.635 62.64 13.905 ;
     RECT  2.16 14.175 62.64 14.445 ;
     RECT  2.16 14.715 62.64 14.985 ;
     RECT  2.16 15.255 62.64 15.525 ;
     RECT  2.16 15.795 62.64 16.065 ;
     RECT  2.16 16.335 62.64 16.605 ;
     RECT  2.16 16.875 62.64 17.145 ;
     RECT  2.16 17.415 62.64 17.685 ;
     RECT  2.16 17.955 62.64 18.225 ;
     RECT  2.16 18.495 62.64 18.765 ;
     RECT  2.16 19.035 62.64 19.305 ;
     RECT  2.16 19.575 62.64 19.845 ;
     RECT  2.16 20.115 62.64 20.385 ;
     RECT  2.16 20.655 62.64 20.925 ;
     RECT  2.16 21.195 62.64 21.465 ;
     RECT  2.16 21.735 62.64 22.005 ;
     RECT  2.16 22.275 62.64 22.545 ;
     RECT  2.16 22.815 62.64 23.085 ;
     RECT  2.16 23.355 62.64 23.625 ;
     RECT  2.16 23.895 62.64 24.165 ;
     RECT  2.16 24.435 62.64 24.705 ;
     RECT  2.16 24.975 62.64 25.245 ;
     RECT  2.16 25.515 62.64 25.785 ;
     RECT  2.16 26.055 62.64 26.325 ;
     RECT  2.16 26.595 62.64 26.865 ;
     RECT  2.16 27.135 62.64 27.405 ;
     RECT  2.16 27.675 62.64 27.945 ;
     RECT  2.16 28.215 62.64 28.485 ;
     RECT  2.16 28.755 62.64 29.025 ;
     RECT  2.16 29.295 62.64 29.565 ;
     RECT  2.16 29.835 62.64 30.105 ;
     RECT  2.16 30.375 62.64 30.645 ;
     RECT  2.16 30.915 62.64 31.185 ;
     RECT  2.16 31.455 62.64 31.725 ;
     RECT  2.16 31.995 62.64 32.265 ;
     RECT  2.16 32.535 62.64 32.805 ;
     RECT  2.16 33.075 62.64 33.345 ;
     RECT  2.16 33.615 62.64 33.885 ;
     RECT  2.16 34.155 62.64 34.425 ;
     RECT  2.16 34.695 62.64 34.965 ;
     RECT  2.16 35.235 62.64 35.505 ;
     RECT  2.16 35.775 62.64 36.045 ;
     RECT  2.16 36.315 62.64 36.585 ;
     RECT  2.16 36.855 62.64 37.125 ;
     RECT  2.16 37.395 62.64 37.665 ;
     RECT  2.16 37.935 62.64 38.205 ;
     RECT  2.16 38.475 62.64 38.745 ;
     RECT  2.16 39.015 62.64 39.285 ;
     RECT  2.16 39.555 62.64 39.825 ;
     RECT  2.16 40.095 62.64 40.365 ;
     RECT  2.16 40.635 62.64 40.905 ;
     RECT  2.16 41.175 62.64 41.445 ;
     RECT  2.16 41.715 62.64 41.985 ;
     RECT  2.16 42.255 62.64 42.525 ;
     RECT  2.16 42.795 62.64 43.065 ;
     RECT  2.16 43.335 62.64 43.605 ;
     RECT  2.16 43.875 62.64 44.145 ;
     RECT  2.16 44.415 62.64 44.685 ;
     RECT  2.16 44.955 62.64 45.225 ;
     RECT  2.16 45.495 62.64 45.765 ;
     RECT  2.16 46.035 62.64 46.305 ;
     RECT  2.16 46.575 62.64 46.845 ;
     RECT  2.16 47.115 62.64 47.385 ;
     RECT  2.16 47.655 62.64 47.925 ;
     RECT  2.16 48.195 62.64 48.465 ;
     RECT  2.16 48.735 62.64 49.005 ;
     RECT  2.16 49.275 62.64 49.545 ;
     RECT  2.16 49.815 62.64 50.085 ;
     RECT  2.16 50.355 62.64 50.625 ;
     RECT  2.16 50.895 62.64 51.165 ;
     RECT  2.16 51.435 62.64 51.705 ;
     RECT  2.16 51.975 62.64 52.245 ;
     RECT  2.16 52.515 62.64 52.785 ;
     RECT  2.16 53.055 62.64 53.325 ;
     RECT  2.16 53.595 62.64 53.865 ;
     RECT  2.16 54.135 62.64 54.405 ;
     RECT  2.16 54.675 62.64 54.945 ;
     RECT  2.16 55.215 62.64 55.485 ;
     RECT  2.16 55.755 62.64 56.025 ;
     RECT  2.16 56.295 62.64 56.565 ;
     RECT  2.16 56.835 62.64 57.105 ;
     RECT  2.16 57.375 62.64 57.645 ;
     RECT  2.16 57.915 62.64 58.185 ;
     RECT  2.16 58.455 62.64 58.725 ;
     RECT  2.16 58.995 62.64 59.265 ;
     RECT  2.16 59.535 62.64 59.805 ;
     RECT  2.16 60.075 62.64 60.345 ;
     RECT  2.16 60.615 62.64 60.885 ;
     RECT  2.16 61.155 62.64 61.425 ;
     RECT  2.16 61.695 62.64 61.965 ;
     RECT  2.16 62.235 62.64 62.505 ;
     RECT  2.16 62.775 62.64 63.045 ;
     RECT  2.16 63.315 62.64 63.585 ;
     RECT  2.16 63.855 62.64 64.125 ;
     RECT  2.16 64.395 62.64 64.665 ;
     RECT  2.16 64.935 62.64 65.205 ;
     RECT  2.16 65.475 62.64 65.745 ;
     RECT  2.16 66.015 62.64 66.285 ;
     RECT  2.16 66.555 62.64 66.825 ;
     RECT  2.16 67.095 62.64 67.365 ;
     RECT  2.16 67.635 62.64 67.905 ;
     RECT  2.16 68.175 62.64 68.445 ;
     RECT  2.16 68.715 62.64 68.985 ;
     RECT  2.16 69.255 62.64 69.525 ;
     RECT  2.16 69.795 62.64 70.065 ;
     RECT  2.16 70.335 62.64 70.605 ;
     RECT  2.16 70.875 62.64 71.145 ;
     RECT  2.16 71.415 62.64 71.685 ;
     RECT  2.16 71.955 62.64 72.225 ;
     RECT  2.16 72.495 62.64 72.765 ;
     RECT  2.16 73.035 62.64 73.305 ;
     RECT  2.16 73.575 62.64 73.845 ;
     RECT  2.16 74.115 62.64 74.385 ;
     RECT  2.16 74.655 62.64 74.925 ;
     RECT  2.16 75.195 62.64 75.465 ;
     RECT  2.16 75.735 62.64 76.005 ;
     RECT  2.16 76.275 62.64 76.545 ;
     RECT  2.16 76.815 62.64 77.085 ;
     RECT  2.16 77.355 62.64 77.625 ;
     RECT  2.16 77.895 62.64 78.165 ;
     RECT  2.16 78.435 62.64 78.705 ;
     RECT  2.16 78.975 62.64 79.245 ;
     RECT  2.16 79.515 62.64 79.785 ;
     RECT  2.16 80.055 62.64 80.325 ;
     RECT  2.16 80.595 62.64 80.865 ;
     RECT  2.16 81.135 62.64 81.405 ;
     RECT  2.16 81.675 62.64 81.945 ;
     RECT  2.16 82.215 62.64 82.485 ;
     RECT  2.16 82.755 62.64 83.025 ;
     RECT  2.16 83.295 62.64 83.565 ;
     RECT  2.16 83.835 62.64 84.105 ;
     RECT  2.16 84.375 62.64 84.645 ;
     RECT  2.16 84.915 62.64 85.185 ;
     RECT  2.16 85.455 62.64 85.725 ;
     RECT  2.16 85.995 62.64 86.265 ;
     RECT  2.16 86.535 62.64 86.805 ;
     RECT  2.16 87.075 62.64 87.345 ;
     RECT  2.16 87.615 62.64 87.885 ;
     RECT  2.16 88.155 62.64 88.425 ;
     RECT  2.16 88.695 62.64 88.965 ;
     RECT  2.16 89.235 62.64 89.505 ;
     RECT  2.16 89.775 62.64 90.045 ;
     RECT  2.16 90.315 62.64 90.585 ;
     RECT  2.16 90.855 62.64 91.125 ;
     RECT  2.16 91.395 62.64 91.665 ;
     RECT  2.16 91.935 62.64 92.205 ;
     RECT  2.16 92.475 62.64 92.745 ;
     RECT  2.16 93.015 62.64 93.285 ;
     RECT  2.16 93.555 62.64 93.825 ;
     RECT  2.16 94.095 62.64 94.365 ;
     RECT  2.16 94.635 62.64 94.905 ;
     RECT  2.16 95.175 62.64 95.445 ;
     RECT  2.16 95.715 62.64 95.985 ;
     RECT  2.16 96.255 62.64 96.525 ;
     RECT  2.16 96.795 62.64 97.065 ;
     RECT  2.16 97.335 62.64 97.605 ;
     RECT  2.16 97.875 62.64 98.145 ;
     RECT  2.16 98.415 62.64 98.685 ;
     RECT  2.16 98.955 62.64 99.225 ;
     RECT  2.16 99.495 62.64 99.765 ;
     RECT  2.16 100.035 62.64 100.305 ;
     RECT  2.16 100.575 62.64 100.845 ;
     RECT  2.16 101.115 62.64 101.385 ;
     RECT  2.16 101.655 62.64 101.925 ;
     RECT  2.16 102.195 62.64 102.465 ;
     RECT  2.16 102.735 62.64 103.005 ;
     RECT  2.16 103.275 62.64 103.545 ;
     RECT  2.16 103.815 62.64 104.085 ;
     RECT  2.16 104.355 62.64 104.625 ;
     RECT  2.16 104.895 62.64 105.165 ;
     RECT  2.16 105.435 62.64 105.705 ;
     RECT  2.16 105.975 62.64 106.245 ;
     RECT  2.16 106.515 62.64 106.785 ;
     RECT  2.16 107.055 62.64 107.325 ;
     RECT  2.16 107.595 62.64 107.865 ;
     RECT  2.16 108.135 62.64 108.405 ;
     RECT  2.16 108.675 62.64 108.945 ;
     RECT  2.16 109.215 62.64 109.485 ;
     RECT  2.16 109.755 62.64 110.025 ;
     RECT  2.16 110.295 62.64 110.565 ;
     RECT  2.16 110.835 62.64 111.105 ;
     RECT  2.16 111.375 62.64 111.645 ;
     RECT  2.16 111.915 62.64 112.185 ;
     RECT  2.16 112.455 62.64 112.725 ;
     RECT  2.16 112.995 62.64 113.265 ;
     RECT  2.16 113.535 62.64 113.805 ;
     RECT  2.16 114.075 62.64 114.345 ;
     RECT  2.16 114.615 62.64 114.885 ;
     RECT  2.16 115.155 62.64 115.425 ;
     RECT  2.16 115.695 62.64 115.965 ;
     RECT  2.16 116.235 62.64 116.505 ;
     RECT  2.16 116.775 62.64 117.045 ;
     RECT  2.16 117.315 62.64 117.585 ;
     RECT  2.16 117.855 62.64 118.125 ;
     RECT  2.16 118.395 62.64 118.665 ;
     RECT  2.16 118.935 62.64 119.205 ;
     RECT  2.16 119.475 62.64 119.745 ;
     RECT  2.16 120.015 62.64 120.285 ;
     RECT  2.16 120.555 62.64 120.825 ;
     RECT  2.16 121.095 62.64 121.365 ;
     RECT  2.16 121.635 62.64 121.905 ;
     RECT  2.16 122.175 62.64 122.445 ;
     RECT  2.16 122.715 62.64 122.985 ;
     RECT  2.16 123.255 62.64 123.525 ;
     RECT  2.16 123.795 62.64 124.065 ;
     RECT  2.16 124.335 62.64 124.605 ;
     RECT  2.16 124.875 62.64 125.145 ;
     RECT  2.16 125.415 62.64 125.685 ;
     RECT  2.16 125.955 62.64 126.225 ;
     RECT  2.16 126.495 62.64 126.765 ;
     RECT  2.16 127.035 62.64 127.305 ;
    LAYER M1 ;
     RECT  2.16 2.151 62.64 127.449 ;
    LAYER M2 ;
     RECT  0.031 3.816 0.103 3.834 ;
     RECT  0.031 64.332 0.103 64.35 ;
     RECT  0.067 85.122 0.103 85.14 ;
     RECT  0.103 3.816 0.131 4.284 ;
     RECT  0.067 19.971 0.139 19.989 ;
     RECT  0.103 66.366 0.139 66.384 ;
     RECT  0.103 67.41 0.139 67.428 ;
     RECT  0.103 70.542 0.139 70.704 ;
     RECT  0.103 71.46 0.139 71.478 ;
     RECT  0.103 72.504 0.139 72.522 ;
     RECT  0.103 81.99 0.139 82.008 ;
     RECT  0.103 85.122 0.139 85.41 ;
     RECT  0.103 95.256 0.139 95.814 ;
     RECT  0.103 64.332 0.175 64.494 ;
     RECT  0.139 70.461 0.175 72.522 ;
     RECT  0.139 81.99 0.175 82.674 ;
     RECT  0.175 62.784 0.211 62.802 ;
     RECT  0.139 66.222 0.211 66.384 ;
     RECT  0.139 85.122 0.211 85.788 ;
     RECT  0.103 73.476 0.239 73.494 ;
     RECT  0.175 81.99 0.239 83.25 ;
     RECT  0.175 53.1 0.247 53.118 ;
     RECT  0.175 54.036 0.247 54.054 ;
     RECT  0.239 83.232 0.247 83.25 ;
     RECT  0.247 53.028 0.275 53.118 ;
     RECT  0.247 54.036 0.275 54.126 ;
     RECT  0.175 70.416 0.275 72.522 ;
     RECT  0.211 62.784 0.283 63.108 ;
     RECT  0.275 70.461 0.311 72.522 ;
     RECT  0.175 64.332 0.355 64.89 ;
     RECT  0.211 85.122 0.355 86.22 ;
     RECT  0.311 70.461 0.383 70.668 ;
     RECT  0.211 66.222 0.391 66.654 ;
     RECT  0.103 75.51 0.391 75.528 ;
     RECT  0.247 57.006 0.427 57.024 ;
     RECT  0.103 25.101 0.455 25.119 ;
     RECT  0.031 121.032 0.463 121.05 ;
     RECT  0.391 75.51 0.499 75.762 ;
     RECT  0.103 76.86 0.499 76.878 ;
     RECT  0.103 79.758 0.499 79.776 ;
     RECT  0.463 124.416 0.499 124.434 ;
     RECT  0.275 53.028 0.527 53.046 ;
     RECT  0.275 54.108 0.527 54.126 ;
     RECT  0.391 66.06 0.527 66.654 ;
     RECT  0.499 79.758 0.535 80.118 ;
     RECT  0.499 124.416 0.535 124.596 ;
     RECT  0.383 70.461 0.563 70.479 ;
     RECT  0.103 77.94 0.571 77.958 ;
     RECT  0.527 66.06 0.607 66.384 ;
     RECT  0.463 120.492 0.607 121.05 ;
     RECT  0.103 69.192 0.643 69.21 ;
     RECT  0.571 77.94 0.643 77.994 ;
     RECT  0.103 74.664 0.671 74.682 ;
     RECT  0.643 77.868 0.671 77.994 ;
     RECT  0.283 62.712 0.679 63.108 ;
     RECT  0.607 120.492 0.715 121.59 ;
     RECT  0.427 122.652 0.715 122.67 ;
     RECT  0.427 57.006 0.751 57.06 ;
     RECT  0.139 67.41 0.823 67.698 ;
     RECT  0.715 120.492 0.823 122.67 ;
     RECT  0.679 61.974 0.859 63.108 ;
     RECT  0.535 79.56 0.859 80.118 ;
     RECT  0.535 80.91 0.859 80.928 ;
     RECT  0.751 57.006 0.887 57.096 ;
     RECT  0.859 61.902 0.887 63.108 ;
     RECT  0.823 67.41 0.895 67.932 ;
     RECT  0.895 67.41 1.147 68.4 ;
     RECT  0.643 69.192 1.147 69.354 ;
     RECT  0.311 71.46 1.291 71.748 ;
     RECT  0.139 19.971 1.319 20.214 ;
     RECT  1.147 67.41 1.399 69.354 ;
     RECT  1.147 70.146 1.399 70.164 ;
     RECT  0.499 75.51 1.435 76.878 ;
     RECT  0.671 77.868 1.435 77.958 ;
     RECT  0.535 73.386 1.471 73.404 ;
     RECT  0.311 72.504 1.543 72.522 ;
     RECT  1.471 73.386 1.543 73.8 ;
     RECT  1.543 72.504 1.579 73.8 ;
     RECT  0.887 61.902 1.651 61.92 ;
     RECT  0.887 62.712 1.651 63.108 ;
     RECT  0.535 126.198 1.687 126.216 ;
     RECT  0.103 127.35 1.687 127.368 ;
     RECT  1.651 61.902 1.723 63.108 ;
     RECT  0.355 63.864 1.723 64.89 ;
     RECT  1.579 72.504 1.723 74.484 ;
     RECT  1.435 75.51 1.723 77.958 ;
     RECT  0.355 84.654 1.723 86.22 ;
     RECT  0.103 87.39 1.723 87.408 ;
     RECT  1.003 78.786 1.903 78.804 ;
     RECT  0.859 79.56 1.903 80.928 ;
     RECT  1.291 71.082 2.011 71.748 ;
     RECT  1.723 72.504 2.011 77.958 ;
     RECT  0.607 65.952 2.119 66.384 ;
     RECT  0.131 4.266 2.16 4.284 ;
     RECT  0.103 16.236 2.16 16.254 ;
     RECT  1.319 20.196 2.16 20.214 ;
     RECT  1.723 61.902 2.16 64.89 ;
     RECT  2.119 65.826 2.16 66.384 ;
     RECT  1.399 67.41 2.16 70.164 ;
     RECT  2.011 71.082 2.16 77.958 ;
     RECT  1.903 78.786 2.16 80.928 ;
     RECT  0.239 81.99 2.16 82.44 ;
     RECT  0.247 83.232 2.16 83.79 ;
     RECT  1.723 84.654 2.16 87.408 ;
     RECT  0.103 91.836 2.16 92.844 ;
     RECT  0.139 94.806 2.16 95.814 ;
     RECT  0.139 98.766 2.16 98.784 ;
     RECT  0.103 101.286 2.16 102.294 ;
     RECT  0.103 104.796 2.16 105.264 ;
     RECT  0.103 107.766 2.16 108.774 ;
     RECT  0.103 114.696 2.16 115.254 ;
     RECT  0.103 117.486 2.16 118.224 ;
     RECT  0.823 120.492 2.16 122.94 ;
     RECT  0.535 124.38 2.16 124.596 ;
     RECT  1.687 126.198 2.16 127.368 ;
     RECT  2.16 2.151 2.803 127.449 ;
     RECT  2.803 2.151 4.883 127.944 ;
     RECT  5.143 0.072 5.863 0.09 ;
     RECT  15.979 128.781 16.115 128.799 ;
     RECT  6.547 0.846 20.011 0.864 ;
     RECT  4.883 2.151 20.011 127.449 ;
     RECT  21.883 128.781 22.559 128.799 ;
     RECT  23.359 128.781 23.459 128.799 ;
     RECT  25.843 128.781 25.943 128.799 ;
     RECT  5.863 0.036 26.527 0.09 ;
     RECT  20.011 0.846 26.527 127.449 ;
     RECT  28.327 128.781 28.463 128.799 ;
     RECT  26.527 0.036 40.127 127.449 ;
     RECT  40.127 0.036 41.963 0.126 ;
     RECT  41.963 0.108 42.763 0.126 ;
     RECT  40.127 0.882 42.763 127.449 ;
     RECT  42.763 0.108 42.791 127.449 ;
     RECT  42.791 0.18 43.763 127.449 ;
     RECT  43.763 0.18 44.707 0.9 ;
     RECT  44.707 0.036 45.599 0.9 ;
     RECT  43.763 2.151 45.607 127.449 ;
     RECT  45.607 2.151 45.959 127.53 ;
     RECT  45.959 2.151 46.003 127.449 ;
     RECT  45.599 0.036 46.499 0.198 ;
     RECT  46.499 0.108 47.839 0.198 ;
     RECT  47.839 0.036 49.235 0.198 ;
     RECT  49.235 0.036 50.531 0.126 ;
     RECT  46.003 1.422 51.043 127.449 ;
     RECT  51.043 1.422 51.179 127.53 ;
     RECT  51.179 1.422 51.575 127.449 ;
     RECT  50.531 0.036 52.727 0.054 ;
     RECT  51.575 2.151 56.479 127.449 ;
     RECT  56.479 2.151 56.579 127.53 ;
     RECT  56.579 2.151 61.339 127.449 ;
     RECT  61.159 128.781 61.439 128.799 ;
     RECT  61.339 2.151 61.771 127.494 ;
     RECT  61.771 2.151 61.943 127.53 ;
     RECT  61.943 2.151 62.64 127.494 ;
     RECT  62.64 79.56 62.735 94.05 ;
     RECT  62.64 94.878 62.735 105.732 ;
     RECT  62.735 87.39 62.771 94.05 ;
     RECT  62.64 106.758 62.771 111.708 ;
     RECT  62.64 112.5 62.771 127.494 ;
     RECT  62.771 114.39 62.779 127.494 ;
     RECT  62.735 96.228 62.807 105.732 ;
     RECT  62.64 77.13 62.843 78.66 ;
     RECT  62.64 61.2 62.879 61.218 ;
     RECT  62.735 79.56 62.879 86.634 ;
     RECT  62.807 100.548 62.879 105.732 ;
     RECT  62.771 87.588 63.095 94.05 ;
     RECT  62.807 96.228 63.095 99.594 ;
     RECT  62.64 52.722 63.131 52.74 ;
     RECT  62.779 114.39 63.203 127.53 ;
     RECT  63.203 116.748 63.239 127.53 ;
     RECT  63.239 116.784 63.275 127.53 ;
     RECT  62.64 64.368 63.311 64.926 ;
     RECT  62.64 65.682 63.311 66.312 ;
     RECT  62.64 67.302 63.311 70.29 ;
     RECT  62.64 71.46 63.311 75.798 ;
     RECT  63.095 87.588 63.311 92.349 ;
     RECT  63.095 96.228 63.311 97.398 ;
     RECT  62.879 100.548 63.311 105.426 ;
     RECT  62.771 106.758 63.347 110.898 ;
     RECT  63.275 117.018 63.347 123.048 ;
     RECT  63.275 123.84 63.347 124.596 ;
     RECT  62.64 41.652 63.419 41.976 ;
     RECT  63.311 87.588 63.419 91.998 ;
     RECT  63.311 64.368 63.455 64.386 ;
     RECT  63.311 65.682 63.455 66.078 ;
     RECT  63.311 69.066 63.455 70.29 ;
     RECT  63.311 71.46 63.455 75.762 ;
     RECT  62.64 42.732 63.491 42.75 ;
     RECT  62.64 51.21 63.527 51.228 ;
     RECT  63.203 114.39 63.527 115.992 ;
     RECT  63.095 98.19 63.563 99.594 ;
     RECT  63.311 100.548 63.599 101.448 ;
     RECT  63.095 93.258 63.635 94.05 ;
     RECT  63.419 90.018 63.671 91.998 ;
     RECT  63.311 102.204 63.743 105.426 ;
     RECT  63.347 106.758 63.743 108.198 ;
     RECT  62.64 58.662 63.779 58.986 ;
     RECT  63.563 98.19 63.779 98.406 ;
     RECT  62.64 62.28 63.815 63.54 ;
     RECT  63.311 96.228 63.851 96.894 ;
     RECT  63.599 100.854 63.851 101.448 ;
     RECT  63.743 102.204 63.851 103.068 ;
     RECT  63.743 107.532 63.851 108.198 ;
     RECT  63.527 114.39 63.851 115.686 ;
     RECT  63.347 117.09 63.851 123.048 ;
     RECT  63.815 62.982 63.887 63.54 ;
     RECT  63.455 69.066 63.887 69.516 ;
     RECT  63.455 71.46 63.887 73.134 ;
     RECT  63.851 114.966 63.887 114.984 ;
     RECT  63.851 117.63 63.887 121.392 ;
     RECT  63.851 122.796 63.887 123.048 ;
     RECT  63.275 125.352 63.887 127.53 ;
     RECT  63.743 103.986 63.923 105.426 ;
     RECT  63.347 109.26 63.923 110.898 ;
     RECT  62.771 112.5 63.923 113.526 ;
     RECT  63.887 118.71 63.923 118.728 ;
     RECT  63.887 119.52 63.923 121.392 ;
     RECT  63.887 126.306 63.923 126.639 ;
     RECT  63.635 93.258 63.959 93.888 ;
     RECT  62.735 94.878 63.959 95.436 ;
     RECT  63.851 96.228 63.959 96.246 ;
     RECT  63.851 100.854 63.959 101.376 ;
     RECT  63.851 102.204 63.959 102.258 ;
     RECT  63.923 103.986 63.959 105.228 ;
     RECT  63.923 109.26 63.959 110.124 ;
     RECT  63.923 112.698 63.959 113.526 ;
     RECT  63.455 73.89 63.995 75.762 ;
     RECT  62.843 77.13 63.995 78.534 ;
     RECT  62.879 80.298 63.995 82.404 ;
     RECT  62.879 83.268 63.995 86.634 ;
     RECT  63.959 112.698 63.995 112.716 ;
     RECT  63.959 93.258 64.003 93.654 ;
     RECT  63.959 94.878 64.003 95.004 ;
     RECT  63.995 84.078 64.031 84.87 ;
     RECT  63.743 106.758 64.031 106.776 ;
     RECT  63.455 65.682 64.075 65.7 ;
     RECT  63.995 80.838 64.103 82.008 ;
     RECT  64.003 92.916 64.103 93.654 ;
     RECT  64.003 94.644 64.103 95.004 ;
     RECT  62.64 40.68 64.111 40.698 ;
     RECT  64.075 64.566 64.139 65.7 ;
     RECT  63.671 90.018 64.139 91.188 ;
     RECT  64.103 93.636 64.139 93.654 ;
     RECT  64.139 64.566 64.175 64.584 ;
     RECT  63.887 69.336 64.175 69.354 ;
     RECT  64.111 53.028 64.183 53.046 ;
     RECT  64.183 52.83 64.211 53.046 ;
     RECT  63.995 73.89 64.211 75.222 ;
     RECT  64.111 39.951 64.219 40.698 ;
     RECT  63.419 41.652 64.219 41.67 ;
     RECT  64.183 45.036 64.219 45.054 ;
     RECT  63.995 77.13 64.219 77.148 ;
     RECT  64.219 39.951 64.247 41.67 ;
     RECT  63.887 62.982 64.247 63 ;
     RECT  63.887 71.73 64.247 73.134 ;
     RECT  63.455 70.272 64.283 70.29 ;
     RECT  64.219 76.986 64.283 77.148 ;
     RECT  64.031 84.078 64.283 84.33 ;
     RECT  62.64 37.476 64.319 37.926 ;
     RECT  62.64 54.414 64.319 54.432 ;
     RECT  63.779 58.734 64.319 58.986 ;
     RECT  63.887 122.796 64.319 122.814 ;
     RECT  64.103 81.45 64.355 82.008 ;
     RECT  63.419 87.588 64.355 89.226 ;
     RECT  63.851 103.014 64.355 103.068 ;
     RECT  64.319 37.476 64.391 37.494 ;
     RECT  64.247 40.446 64.391 41.67 ;
     RECT  64.355 103.05 64.391 103.068 ;
     RECT  64.391 40.446 64.427 40.698 ;
     RECT  64.219 44.766 64.427 45.054 ;
     RECT  64.211 52.83 64.427 52.848 ;
     RECT  63.347 124.578 64.427 124.596 ;
     RECT  64.391 41.652 64.463 41.67 ;
     RECT  63.959 104.022 64.463 104.454 ;
     RECT  64.219 26.802 64.471 26.82 ;
     RECT  64.219 28.026 64.471 28.044 ;
     RECT  63.995 86.04 64.499 86.634 ;
     RECT  63.671 91.944 64.499 91.998 ;
     RECT  64.471 26.802 64.507 26.928 ;
     RECT  64.499 91.944 64.535 91.962 ;
     RECT  64.219 33.39 64.543 33.408 ;
     RECT  64.507 26.802 64.571 27.009 ;
     RECT  64.471 27.954 64.571 28.044 ;
     RECT  64.543 33.39 64.571 33.489 ;
     RECT  64.427 40.446 64.571 40.464 ;
     RECT  64.427 44.766 64.571 44.784 ;
     RECT  64.183 56.916 64.571 56.934 ;
     RECT  64.319 58.734 64.571 58.914 ;
     RECT  64.103 94.644 64.607 94.662 ;
     RECT  64.355 87.858 64.643 89.226 ;
     RECT  63.959 101.358 64.643 101.376 ;
     RECT  64.643 88.776 64.679 89.226 ;
     RECT  63.563 99.504 64.679 99.594 ;
     RECT  64.183 57.69 64.687 57.708 ;
     RECT  64.615 15.336 64.715 15.354 ;
     RECT  62.64 17.082 64.715 17.1 ;
     RECT  62.64 23.634 64.715 24.228 ;
     RECT  64.571 26.838 64.715 27.009 ;
     RECT  64.579 29.07 64.715 29.088 ;
     RECT  64.579 30.654 64.715 30.672 ;
     RECT  64.571 33.471 64.715 33.489 ;
     RECT  64.543 34.434 64.715 34.452 ;
     RECT  64.543 36.828 64.715 36.846 ;
     RECT  64.139 65.682 64.715 65.7 ;
     RECT  64.247 71.73 64.715 72.486 ;
     RECT  64.211 73.89 64.715 74.484 ;
     RECT  64.283 77.13 64.715 77.148 ;
     RECT  64.355 81.99 64.715 82.008 ;
     RECT  63.995 83.268 64.715 83.286 ;
     RECT  64.283 84.312 64.715 84.33 ;
     RECT  64.499 86.616 64.715 86.634 ;
     RECT  64.679 89.208 64.715 89.226 ;
     RECT  64.139 90.018 64.715 90.918 ;
     RECT  63.779 98.388 64.715 98.406 ;
     RECT  64.679 99.504 64.715 99.522 ;
     RECT  63.959 102.24 64.715 102.258 ;
     RECT  64.463 104.436 64.715 104.454 ;
     RECT  63.959 105.21 64.715 105.228 ;
     RECT  63.959 109.26 64.715 109.818 ;
     RECT  62.771 111.69 64.715 111.708 ;
     RECT  63.923 119.52 64.715 119.538 ;
     RECT  63.923 121.374 64.715 121.392 ;
     RECT  64.715 90.36 64.751 90.378 ;
     RECT  64.715 23.634 64.787 23.652 ;
     RECT  64.651 25.101 64.787 25.119 ;
     RECT  64.715 26.91 64.787 27.009 ;
     RECT  64.687 57.618 64.787 57.708 ;
     RECT  64.571 58.806 64.787 58.914 ;
     RECT  64.643 87.858 64.787 87.876 ;
     RECT  63.923 126.306 64.787 126.324 ;
    LAYER M3 ;
     RECT  52.704 0.031 52.722 0.043 ;
     RECT  40.104 0.012 49.662 0.059 ;
     RECT  5.868 0.031 5.886 0.067 ;
     RECT  42.372 0.059 49.662 0.067 ;
     RECT  52.704 0.043 53.298 0.091 ;
     RECT  40.104 0.059 41.49 0.095 ;
     RECT  42.372 0.067 49.698 0.131 ;
     RECT  50.436 0.031 50.526 0.131 ;
     RECT  29.7 0.012 29.718 0.133 ;
     RECT  29.7 0.133 29.97 0.139 ;
     RECT  35.1 0.012 35.118 0.139 ;
     RECT  52.704 0.091 53.874 0.139 ;
     RECT  35.1 0.139 35.154 0.167 ;
     RECT  29.592 0.139 29.97 0.173 ;
     RECT  29.592 0.173 29.61 0.176 ;
     RECT  26.532 0.103 26.55 0.187 ;
     RECT  49.212 0.131 49.698 0.203 ;
     RECT  5.148 0.067 5.886 0.841 ;
     RECT  40.104 0.095 40.59 0.869 ;
     RECT  0.216 0.667 0.234 0.907 ;
     RECT  0.216 0.907 0.306 1.147 ;
     RECT  5.148 0.841 6.57 1.387 ;
     RECT  55.62 1.147 55.638 1.387 ;
     RECT  52.128 0.139 53.874 1.417 ;
     RECT  42.372 0.131 48.33 1.445 ;
     RECT  31.032 0.043 31.05 1.453 ;
     RECT  42.372 1.445 43.29 1.481 ;
     RECT  0.216 1.147 0.774 1.627 ;
     RECT  2.124 1.387 2.142 1.915 ;
     RECT  20.016 1.417 20.034 1.963 ;
     RECT  1.656 1.915 2.142 2.143 ;
     RECT  5.148 1.387 7.11 2.143 ;
     RECT  34.344 0.877 34.362 2.143 ;
     RECT  35.136 0.167 35.154 2.143 ;
     RECT  40.572 0.869 40.59 2.143 ;
     RECT  50.436 0.131 50.454 2.143 ;
     RECT  51.552 1.417 53.874 2.143 ;
     RECT  0.108 1.627 0.774 2.155 ;
     RECT  1.656 2.143 2.505 2.155 ;
     RECT  0.108 2.155 2.505 2.413 ;
     RECT  5.148 2.143 7.905 2.413 ;
     RECT  13.215 2.143 13.305 2.413 ;
     RECT  18.615 2.143 18.705 2.413 ;
     RECT  24.015 2.143 24.105 2.413 ;
     RECT  29.415 2.143 29.505 2.413 ;
     RECT  44.208 1.445 45.705 2.413 ;
     RECT  56.415 2.143 56.505 2.413 ;
     RECT  61.815 2.143 61.905 2.413 ;
     RECT  61.815 2.413 62.097 2.491 ;
     RECT  64.692 2.395 64.71 2.525 ;
     RECT  62.856 0.907 62.874 2.875 ;
     RECT  63.792 2.155 63.81 2.875 ;
     RECT  44.208 2.413 45.897 3.109 ;
     RECT  46.728 1.445 48.33 3.109 ;
     RECT  56.415 2.413 56.697 3.115 ;
     RECT  40.215 2.143 40.59 3.137 ;
     RECT  0.108 2.413 2.697 3.403 ;
     RECT  61.596 2.491 62.097 3.643 ;
     RECT  62.856 2.875 63.81 3.643 ;
     RECT  0.108 3.403 3.186 3.811 ;
     RECT  55.548 1.387 55.638 3.883 ;
     RECT  61.596 3.643 63.81 4.363 ;
     RECT  60.732 1.915 60.75 4.651 ;
     RECT  61.596 4.363 64.422 4.651 ;
     RECT  60.732 4.651 64.422 4.891 ;
     RECT  4.104 4.261 4.122 5.467 ;
     RECT  4.104 5.467 4.23 6.619 ;
     RECT  59.832 2.779 59.85 6.619 ;
     RECT  55.224 3.883 55.638 6.859 ;
     RECT  3.996 6.619 4.23 7.147 ;
     RECT  5.148 2.413 8.097 7.147 ;
     RECT  58.716 0.667 58.734 7.387 ;
     RECT  59.796 6.619 59.85 7.387 ;
     RECT  55.188 6.859 55.638 7.627 ;
     RECT  0.036 3.811 3.186 7.723 ;
     RECT  54.684 7.627 55.638 7.867 ;
     RECT  50.436 2.143 53.874 8.155 ;
     RECT  54.612 7.867 55.638 8.155 ;
     RECT  60.732 4.891 64.458 8.347 ;
     RECT  60.732 8.347 64.71 8.477 ;
     RECT  50.436 8.155 55.638 8.671 ;
     RECT  56.415 3.115 56.754 8.671 ;
     RECT  50.436 8.671 56.754 8.717 ;
     RECT  60.732 8.477 64.458 9.883 ;
     RECT  60.732 9.883 64.71 9.979 ;
     RECT  0.036 7.723 3.258 10.363 ;
     RECT  3.996 7.147 8.097 10.363 ;
     RECT  58.716 7.387 59.85 10.363 ;
     RECT  56.415 8.717 56.754 11.131 ;
     RECT  58.392 10.363 59.85 11.947 ;
     RECT  60.732 9.979 64.782 11.947 ;
     RECT  58.392 11.947 64.782 23.657 ;
     RECT  50.436 8.717 55.638 23.791 ;
     RECT  56.415 11.131 57.294 23.791 ;
     RECT  50.436 23.791 57.294 23.837 ;
     RECT  17.352 0.811 17.37 25.003 ;
     RECT  58.392 23.657 64.71 25.096 ;
     RECT  13.215 2.413 13.497 26.299 ;
     RECT  13.068 26.299 13.497 26.779 ;
     RECT  14.544 26.539 14.562 26.779 ;
     RECT  16.056 25.291 16.074 27.067 ;
     RECT  12.276 25.819 12.294 27.307 ;
     RECT  18.615 2.413 18.897 27.595 ;
     RECT  13.068 26.779 14.562 27.883 ;
     RECT  15.768 27.067 16.074 27.883 ;
     RECT  13.068 27.883 16.074 28.123 ;
     RECT  10.836 28.555 10.854 28.733 ;
     RECT  13.068 28.123 16.29 28.795 ;
     RECT  58.392 25.096 64.782 28.795 ;
     RECT  9.468 24.907 9.486 29.035 ;
     RECT  11.736 27.307 12.294 29.275 ;
     RECT  13.068 28.795 16.578 29.275 ;
     RECT  9.072 29.035 9.486 29.803 ;
     RECT  11.736 29.275 16.578 30.283 ;
     RECT  17.352 25.003 17.874 30.283 ;
     RECT  20.016 1.963 20.718 30.571 ;
     RECT  56.415 23.837 57.294 30.811 ;
     RECT  58.104 28.795 64.782 30.811 ;
     RECT  20.016 30.571 20.79 31.099 ;
     RECT  9.072 29.803 9.99 31.147 ;
     RECT  10.836 30.043 10.854 31.147 ;
     RECT  24.015 2.413 24.297 33.019 ;
     RECT  20.016 31.099 21.474 33.259 ;
     RECT  22.32 31.771 22.338 33.259 ;
     RECT  18.615 27.595 18.954 33.883 ;
     RECT  20.016 33.259 22.338 33.883 ;
     RECT  18.615 33.883 22.338 34.603 ;
     RECT  23.616 33.019 24.297 34.603 ;
     RECT  9.072 31.147 10.854 35.515 ;
     RECT  11.736 30.283 17.874 35.515 ;
     RECT  25.56 2.533 25.578 36.859 ;
     RECT  26.532 0.187 27.27 36.859 ;
     RECT  50.436 23.837 55.638 36.907 ;
     RECT  56.415 30.811 64.782 36.907 ;
     RECT  25.56 36.859 27.27 37.963 ;
     RECT  28.224 37.579 28.242 37.963 ;
     RECT  30.456 1.453 31.05 38.251 ;
     RECT  25.56 37.963 28.242 39.499 ;
     RECT  25.56 39.499 28.278 40.555 ;
     RECT  29.415 2.413 29.697 40.555 ;
     RECT  30.456 38.251 31.626 41.419 ;
     RECT  33.156 41.227 33.174 41.755 ;
     RECT  30.456 41.419 31.734 41.995 ;
     RECT  30.456 41.995 32.022 42.235 ;
     RECT  32.76 41.755 33.174 42.235 ;
     RECT  34.344 2.143 35.154 42.475 ;
     RECT  33.984 42.475 35.154 42.763 ;
     RECT  36 2.011 36.018 42.763 ;
     RECT  30.456 42.235 33.174 44.587 ;
     RECT  18.615 34.603 24.297 45.301 ;
     RECT  36.828 43.531 36.846 46.843 ;
     RECT  36.828 46.843 37.35 47.083 ;
     RECT  18.615 45.301 24.75 47.659 ;
     RECT  40.215 3.137 40.497 47.995 ;
     RECT  36.828 47.083 37.638 48.235 ;
     RECT  38.988 47.707 39.006 48.235 ;
     RECT  36.828 48.235 39.006 48.475 ;
     RECT  36.828 48.475 39.042 48.715 ;
     RECT  39.78 47.995 40.497 48.715 ;
     RECT  43.272 1.481 43.29 49.483 ;
     RECT  44.208 3.109 48.33 49.483 ;
     RECT  41.472 0.095 41.49 49.819 ;
     RECT  42.372 1.481 42.39 49.819 ;
     RECT  41.472 49.819 42.39 50.011 ;
     RECT  9.072 35.515 17.874 50.827 ;
     RECT  41.472 50.011 42.498 53.899 ;
     RECT  43.272 49.483 48.33 53.899 ;
     RECT  36.828 48.715 40.497 55.561 ;
     RECT  41.472 53.899 48.33 55.561 ;
     RECT  30.456 44.587 33.21 56.203 ;
     RECT  33.984 42.763 36.018 56.203 ;
     RECT  30.456 56.203 36.018 57.691 ;
     RECT  36.828 55.561 48.33 57.691 ;
     RECT  8.928 50.827 17.874 58.171 ;
     RECT  18.615 47.659 24.786 58.171 ;
     RECT  50.436 36.907 64.782 61.079 ;
     RECT  30.456 57.691 48.33 61.655 ;
     RECT  46.656 61.655 48.33 61.771 ;
     RECT  25.56 40.555 29.697 61.861 ;
     RECT  30.456 61.655 45.897 61.861 ;
     RECT  49.68 0.203 49.698 62.041 ;
     RECT  50.508 61.079 64.782 62.041 ;
     RECT  46.656 61.771 48.438 62.167 ;
     RECT  49.176 62.041 64.782 62.167 ;
     RECT  25.56 61.861 45.897 62.401 ;
     RECT  46.656 62.167 64.782 62.401 ;
     RECT  0.036 10.363 8.097 62.545 ;
     RECT  8.928 58.171 24.786 62.545 ;
     RECT  0.036 62.545 24.786 63.283 ;
     RECT  25.56 62.401 64.782 63.283 ;
     RECT  0.036 63.283 64.782 64.193 ;
     RECT  46.656 64.193 64.782 64.355 ;
     RECT  48.312 64.355 64.782 65.003 ;
     RECT  46.656 64.355 47.466 65.785 ;
     RECT  48.42 65.003 64.782 65.785 ;
     RECT  46.656 65.785 64.782 68.135 ;
     RECT  48.276 68.135 64.782 68.279 ;
     RECT  48.312 68.279 64.782 69.323 ;
     RECT  49.068 69.323 64.782 69.485 ;
     RECT  49.212 69.485 64.782 69.899 ;
     RECT  49.68 69.899 64.782 70.367 ;
     RECT  46.656 68.135 47.466 70.375 ;
     RECT  48.312 69.323 48.33 70.375 ;
     RECT  46.656 70.375 48.33 74.965 ;
     RECT  49.68 70.367 49.698 74.965 ;
     RECT  46.656 74.965 49.698 75.497 ;
     RECT  0.036 64.193 45.897 76.109 ;
     RECT  18.615 76.109 45.897 76.577 ;
     RECT  0.036 76.109 17.874 77.585 ;
     RECT  0.036 77.585 10.926 78.331 ;
     RECT  11.7 77.585 17.874 78.331 ;
     RECT  0.036 78.331 17.874 79.141 ;
     RECT  18.615 76.577 30.51 79.141 ;
     RECT  50.436 70.367 64.782 85.415 ;
     RECT  50.436 85.415 54.126 85.685 ;
     RECT  54.864 85.415 64.782 87.881 ;
     RECT  0.036 79.141 30.51 88.051 ;
     RECT  0.036 88.051 30.726 88.411 ;
     RECT  54.864 87.881 64.746 88.663 ;
     RECT  54.792 88.663 64.746 88.763 ;
     RECT  0.036 88.411 30.798 88.925 ;
     RECT  0.036 88.925 30.762 89.735 ;
     RECT  54.864 88.763 64.746 90.383 ;
     RECT  54.864 90.383 64.71 91.085 ;
     RECT  0.036 89.735 30.51 91.201 ;
     RECT  0.036 91.201 30.762 91.355 ;
     RECT  0.036 91.355 30.51 91.499 ;
     RECT  31.608 76.577 45.897 91.741 ;
     RECT  0.036 91.499 30.222 92.371 ;
     RECT  31.284 91.741 45.897 92.371 ;
     RECT  54.864 91.085 64.602 92.677 ;
     RECT  54.72 92.677 64.602 92.777 ;
     RECT  54.792 92.777 64.602 92.849 ;
     RECT  0.036 92.371 45.897 93.749 ;
     RECT  54.864 92.849 64.602 94.667 ;
     RECT  0.036 93.749 30.294 94.711 ;
     RECT  31.284 93.749 45.897 94.711 ;
     RECT  54.864 94.667 64.458 94.711 ;
     RECT  54.72 94.711 64.458 94.829 ;
     RECT  54.864 94.829 64.458 96.359 ;
     RECT  54.864 96.359 58.482 98.149 ;
     RECT  0.036 94.711 45.897 98.249 ;
     RECT  59.292 96.359 64.458 98.299 ;
     RECT  54.72 98.149 58.482 99.149 ;
     RECT  54.756 99.149 58.482 99.185 ;
     RECT  59.292 98.299 64.71 99.527 ;
     RECT  59.292 99.527 64.674 99.599 ;
     RECT  54.864 99.185 58.482 100.111 ;
     RECT  50.436 85.685 53.874 100.139 ;
     RECT  54.72 100.111 58.482 100.265 ;
     RECT  50.436 100.139 52.722 100.535 ;
     RECT  54.864 100.265 58.482 101.191 ;
     RECT  59.292 99.599 64.458 101.191 ;
     RECT  54.864 101.191 64.458 101.275 ;
     RECT  54.864 101.275 64.638 102.043 ;
     RECT  54.864 102.043 64.71 102.317 ;
     RECT  54.864 102.317 64.458 103.109 ;
     RECT  59.292 103.109 64.458 104.011 ;
     RECT  59.292 104.011 64.71 104.459 ;
     RECT  54.864 103.109 58.482 104.701 ;
     RECT  54.72 104.701 58.482 104.891 ;
     RECT  59.292 104.459 64.422 105.205 ;
     RECT  59.292 105.205 64.71 105.293 ;
     RECT  0.036 98.249 11.718 105.737 ;
     RECT  49.68 75.497 49.698 105.737 ;
     RECT  54.864 104.891 58.482 106.447 ;
     RECT  59.292 105.293 64.422 106.447 ;
     RECT  54.864 106.447 64.422 106.493 ;
     RECT  54.864 106.493 58.482 107.329 ;
     RECT  59.292 106.493 64.422 107.329 ;
     RECT  12.456 98.249 45.897 107.671 ;
     RECT  46.656 75.497 48.33 107.671 ;
     RECT  12.456 107.671 48.33 107.941 ;
     RECT  12.456 107.941 48.366 108.031 ;
     RECT  12.456 108.031 49.05 108.239 ;
     RECT  12.456 108.239 48.366 108.437 ;
     RECT  54.864 107.329 64.422 108.635 ;
     RECT  59.256 108.635 64.422 108.869 ;
     RECT  59.292 108.869 64.422 109.243 ;
     RECT  54.864 108.635 58.482 109.291 ;
     RECT  54.72 109.291 58.482 109.409 ;
     RECT  59.292 109.243 64.71 109.859 ;
     RECT  59.868 109.859 64.71 110.045 ;
     RECT  59.868 110.045 64.422 111.415 ;
     RECT  52.128 100.535 52.722 111.443 ;
     RECT  59.436 111.415 64.422 111.685 ;
     RECT  50.436 100.535 51.297 111.883 ;
     RECT  50.436 111.883 51.39 112.013 ;
     RECT  59.436 111.685 64.71 112.013 ;
     RECT  49.572 111.991 49.59 112.075 ;
     RECT  50.436 112.013 51.297 112.075 ;
     RECT  49.572 112.075 51.297 112.261 ;
     RECT  49.428 112.261 51.297 112.363 ;
     RECT  54.864 109.409 58.482 112.379 ;
     RECT  12.456 108.437 48.33 112.531 ;
     RECT  59.436 112.013 64.422 112.765 ;
     RECT  12.456 112.531 48.366 113.035 ;
     RECT  49.176 112.363 51.297 113.035 ;
     RECT  52.128 111.443 52.146 113.035 ;
     RECT  12.456 113.035 52.146 113.189 ;
     RECT  56.415 112.379 58.482 113.639 ;
     RECT  59.292 112.765 64.422 113.701 ;
     RECT  12.456 113.189 51.354 114.179 ;
     RECT  54.864 112.379 55.674 114.179 ;
     RECT  58.716 113.701 64.422 114.719 ;
     RECT  12.456 114.179 51.297 115.231 ;
     RECT  12.456 115.231 51.354 115.457 ;
     RECT  54.864 114.179 55.638 116.033 ;
     RECT  54.864 116.033 55.098 116.069 ;
     RECT  52.128 113.189 52.146 116.203 ;
     RECT  59.436 114.719 64.422 116.239 ;
     RECT  52.128 116.203 52.83 116.473 ;
     RECT  12.456 115.457 51.297 116.545 ;
     RECT  52.128 116.473 52.974 116.545 ;
     RECT  12.456 116.545 52.974 116.707 ;
     RECT  12.456 116.707 53.118 116.765 ;
     RECT  12.456 116.765 53.046 117.041 ;
     RECT  58.824 116.239 64.422 117.041 ;
     RECT  54.864 116.069 54.99 117.661 ;
     RECT  53.856 100.139 53.874 117.895 ;
     RECT  54.864 117.661 55.566 117.895 ;
     RECT  12.456 117.041 53.01 117.931 ;
     RECT  53.856 117.895 55.566 117.931 ;
     RECT  59.436 117.041 64.422 118.021 ;
     RECT  58.716 118.021 64.422 118.121 ;
     RECT  59.436 118.121 64.422 118.123 ;
     RECT  12.456 117.931 55.566 118.201 ;
     RECT  56.415 113.639 57.942 118.201 ;
     RECT  59.436 118.123 64.71 118.253 ;
     RECT  59.436 118.253 64.422 118.355 ;
     RECT  59.508 118.355 64.422 119.273 ;
     RECT  59.76 119.273 64.422 119.435 ;
     RECT  59.94 119.435 64.422 119.515 ;
     RECT  59.94 119.515 64.71 119.741 ;
     RECT  12.456 118.201 57.942 120.011 ;
     RECT  12.456 120.011 55.638 120.829 ;
     RECT  56.415 120.011 57.942 120.829 ;
     RECT  0.036 105.737 11.538 121.055 ;
     RECT  59.94 119.741 64.422 121.369 ;
     RECT  59.94 121.369 64.71 121.469 ;
     RECT  12.456 120.829 57.942 121.711 ;
     RECT  59.94 121.469 64.422 121.867 ;
     RECT  59.868 121.867 64.422 121.945 ;
     RECT  12.456 121.711 58.446 122.071 ;
     RECT  12.456 122.071 58.914 122.179 ;
     RECT  59.832 121.945 64.422 122.179 ;
     RECT  12.456 122.179 64.422 122.369 ;
     RECT  59.652 122.369 64.422 122.639 ;
     RECT  0.432 121.055 11.538 122.675 ;
     RECT  12.456 122.369 58.914 122.909 ;
     RECT  12.456 122.909 58.23 122.945 ;
     RECT  12.456 122.945 47.502 123.149 ;
     RECT  0.648 122.675 11.538 123.691 ;
     RECT  12.456 123.149 47.466 123.725 ;
     RECT  59.832 122.639 64.422 124.205 ;
     RECT  48.384 122.945 58.23 124.267 ;
     RECT  59.832 124.205 62.73 124.303 ;
     RECT  48.312 124.267 58.23 124.315 ;
     RECT  36.972 123.725 47.466 124.375 ;
     RECT  48.276 124.315 58.23 124.375 ;
     RECT  0.108 123.691 11.538 124.493 ;
     RECT  36.972 124.375 58.23 124.573 ;
     RECT  63.792 124.205 64.422 124.601 ;
     RECT  36.972 124.573 58.482 124.603 ;
     RECT  59.724 124.303 62.73 124.609 ;
     RECT  36.972 124.603 58.734 124.645 ;
     RECT  59.688 124.609 62.73 124.645 ;
     RECT  36.972 124.645 62.73 124.733 ;
     RECT  63.792 124.601 63.81 124.939 ;
     RECT  36.972 124.733 62.478 125.141 ;
     RECT  36.972 125.141 62.262 125.213 ;
     RECT  63.252 124.939 63.81 125.213 ;
     RECT  63.288 125.213 63.81 125.347 ;
     RECT  48.24 125.213 62.262 125.609 ;
     RECT  0.468 124.493 11.538 125.981 ;
     RECT  36.972 125.213 47.466 126.301 ;
     RECT  48.24 125.609 62.154 126.301 ;
     RECT  36.972 126.301 62.154 126.391 ;
     RECT  36.972 126.391 62.406 126.427 ;
     RECT  63.288 125.347 63.882 126.427 ;
     RECT  0.54 125.981 11.538 126.535 ;
     RECT  12.456 123.725 36.234 126.535 ;
     RECT  36.972 126.427 63.882 126.535 ;
     RECT  0.54 126.535 63.882 126.616 ;
     RECT  0.54 126.616 63.918 126.811 ;
     RECT  0.108 126.811 63.918 127.949 ;
     RECT  0.648 127.949 63.918 128.477 ;
     RECT  64.764 126.301 64.782 128.827 ;
     RECT  64.692 128.827 64.782 128.861 ;
     RECT  64.692 128.861 64.71 128.957 ;
     RECT  0.648 128.477 63.882 129.581 ;
    LAYER M4 ;
     RECT  0.025 64.8 0.06 64.824 ;
     RECT  0.06 0.672 0.245 128.952 ;
     RECT  0.245 0.912 0.317 128.952 ;
     RECT  0.317 1.152 0.425 128.952 ;
     RECT  0.425 1.152 0.785 3.672 ;
     RECT  0.425 4.656 0.901 128.952 ;
     RECT  0.901 4.656 0.965 129.48 ;
     RECT  0.965 4.896 1.187 129.48 ;
     RECT  1.187 18.192 1.253 129.48 ;
     RECT  1.253 63.168 1.361 129.48 ;
     RECT  1.253 18.192 1.397 62.184 ;
     RECT  0.785 1.392 1.427 3.672 ;
     RECT  1.427 1.392 2.153 3.432 ;
     RECT  2.153 2.148 2.408 3.432 ;
     RECT  1.187 4.896 2.408 16.872 ;
     RECT  1.397 18.192 2.408 60.936 ;
     RECT  1.397 62.16 2.408 62.184 ;
     RECT  1.361 63.504 2.408 129.48 ;
     RECT  2.408 2.148 2.512 129.48 ;
     RECT  2.512 2.418 2.704 129.48 ;
     RECT  2.704 20.592 2.801 60.936 ;
     RECT  2.801 20.592 2.837 22.824 ;
     RECT  2.704 70.656 2.837 129.48 ;
     RECT  2.801 23.952 2.873 60.936 ;
     RECT  2.873 24.144 2.945 60.936 ;
     RECT  2.704 18.192 2.981 19.608 ;
     RECT  2.837 22.32 3.011 22.824 ;
     RECT  2.981 18.192 3.089 19.272 ;
     RECT  2.945 24.432 3.107 60.936 ;
     RECT  2.837 126.432 3.125 128.472 ;
     RECT  3.011 22.32 3.155 22.344 ;
     RECT  2.704 3.408 3.197 3.432 ;
     RECT  3.125 126.432 3.233 128.184 ;
     RECT  2.704 6.624 3.269 7.752 ;
     RECT  2.704 62.16 3.305 69.528 ;
     RECT  2.837 70.8 3.305 125.448 ;
     RECT  3.305 70.8 3.377 125.208 ;
     RECT  3.305 62.16 3.413 65.496 ;
     RECT  3.377 76.368 3.413 125.208 ;
     RECT  2.837 129.456 3.421 129.48 ;
     RECT  3.089 18.72 3.485 19.272 ;
     RECT  3.485 18.72 3.539 18.744 ;
     RECT  2.837 20.592 3.593 21 ;
     RECT  2.704 9.12 3.629 10.392 ;
     RECT  3.377 70.8 3.629 75.24 ;
     RECT  3.629 70.8 3.665 74.76 ;
     RECT  3.413 81.12 3.665 125.208 ;
     RECT  3.413 76.368 3.701 79.56 ;
     RECT  3.665 81.12 3.701 85.896 ;
     RECT  3.413 62.16 3.737 65.352 ;
     RECT  3.701 85.296 3.773 85.896 ;
     RECT  3.233 126.816 3.773 128.184 ;
     RECT  3.737 63.072 3.809 65.352 ;
     RECT  3.773 85.728 3.809 85.896 ;
     RECT  3.305 66.48 3.829 69.528 ;
     RECT  2.704 14.928 3.845 16.872 ;
     RECT  3.701 81.12 3.845 84.312 ;
     RECT  3.773 126.816 3.845 126.84 ;
     RECT  3.809 63.456 3.881 65.352 ;
     RECT  3.809 85.776 3.881 85.896 ;
     RECT  3.665 87.264 3.881 125.208 ;
     RECT  3.881 63.504 3.917 65.352 ;
     RECT  3.829 66.48 3.917 70.104 ;
     RECT  3.665 72.816 3.917 74.76 ;
     RECT  3.881 87.264 3.917 87.576 ;
     RECT  3.773 128.16 3.917 128.184 ;
     RECT  3.665 71.184 3.923 71.784 ;
     RECT  3.845 14.928 3.953 15.288 ;
     RECT  3.845 81.216 3.953 84.312 ;
     RECT  3.107 24.48 3.971 60.936 ;
     RECT  2.704 12.336 3.989 12.888 ;
     RECT  3.917 72.912 3.989 74.76 ;
     RECT  3.989 12.864 4.019 12.888 ;
     RECT  3.701 76.368 4.019 79.272 ;
     RECT  3.269 6.624 4.025 7.176 ;
     RECT  4.019 76.848 4.025 79.272 ;
     RECT  3.953 81.264 4.061 84.312 ;
     RECT  3.881 85.872 4.061 85.896 ;
     RECT  3.881 88.704 4.097 125.208 ;
     RECT  4.061 83.088 4.169 84.312 ;
     RECT  3.917 87.264 4.169 87.288 ;
     RECT  2.704 5.472 4.241 5.496 ;
     RECT  3.917 67.344 4.277 70.104 ;
     RECT  4.025 76.848 4.277 79.176 ;
     RECT  4.277 67.344 4.313 67.656 ;
     RECT  4.169 83.328 4.313 83.352 ;
     RECT  4.277 76.992 4.385 79.176 ;
     RECT  3.923 71.184 4.421 71.256 ;
     RECT  3.989 72.912 4.421 74.664 ;
     RECT  4.385 77.088 4.493 79.176 ;
     RECT  4.421 71.184 4.529 71.208 ;
     RECT  3.971 24.624 4.565 60.936 ;
     RECT  3.917 63.504 4.601 64.44 ;
     RECT  4.493 77.088 4.601 78.12 ;
     RECT  3.953 14.928 4.673 15.192 ;
     RECT  4.601 77.376 4.673 78.12 ;
     RECT  4.061 81.264 4.673 82.104 ;
     RECT  4.673 14.928 4.709 14.952 ;
     RECT  4.025 7.152 4.745 7.176 ;
     RECT  4.673 77.376 4.745 77.4 ;
     RECT  3.629 9.12 4.781 9.912 ;
     RECT  4.781 9.12 4.817 9.144 ;
     RECT  4.493 79.152 4.817 79.176 ;
     RECT  4.421 72.912 4.997 73.512 ;
     RECT  4.421 74.64 5.141 74.664 ;
     RECT  4.837 75.84 5.141 75.864 ;
     RECT  3.845 16.608 5.213 16.872 ;
     RECT  4.601 63.504 5.249 64.2 ;
     RECT  5.249 63.504 5.281 64.056 ;
     RECT  5.213 16.608 5.285 16.632 ;
     RECT  5.281 63.12 5.357 64.056 ;
     RECT  4.997 72.912 5.461 72.984 ;
     RECT  4.277 69.456 5.465 70.104 ;
     RECT  5.461 72.432 5.537 72.984 ;
     RECT  5.357 63.12 5.605 63.72 ;
     RECT  5.465 69.456 5.717 69.48 ;
     RECT  4.673 82.08 5.717 82.104 ;
     RECT  3.593 20.976 6.077 21 ;
     RECT  6.284 64.896 6.325 64.92 ;
     RECT  6.325 64.896 6.371 65.592 ;
     RECT  5.537 72.432 6.433 72.456 ;
     RECT  6.433 71.712 6.469 72.456 ;
     RECT  4.565 24.624 6.545 60.312 ;
     RECT  5.605 62.784 6.577 63.72 ;
     RECT  5.845 77.472 6.581 77.496 ;
     RECT  6.577 62.784 6.721 63.864 ;
     RECT  6.469 68.448 6.721 68.472 ;
     RECT  6.469 71.424 6.721 72.456 ;
     RECT  6.325 73.488 6.721 73.512 ;
     RECT  6.721 71.424 6.829 73.512 ;
     RECT  6.613 67.152 7.333 67.176 ;
     RECT  6.721 68.448 7.333 68.952 ;
     RECT  6.371 65.04 7.436 65.592 ;
     RECT  6.829 70.704 7.525 73.512 ;
     RECT  7.436 64.896 7.585 65.592 ;
     RECT  6.805 79.248 7.621 79.272 ;
     RECT  6.721 62.688 7.649 63.864 ;
     RECT  7.081 1.392 7.808 1.416 ;
     RECT  6.545 24.912 7.808 60.312 ;
     RECT  7.649 62.544 7.808 63.864 ;
     RECT  7.585 64.896 7.808 66.072 ;
     RECT  7.333 67.152 7.808 68.952 ;
     RECT  7.525 70.656 7.808 73.512 ;
     RECT  5.317 75.792 7.808 75.816 ;
     RECT  7.669 77.04 7.808 77.064 ;
     RECT  7.621 79.248 7.808 79.32 ;
     RECT  4.097 88.704 7.808 124.392 ;
     RECT  7.325 127.056 7.808 127.08 ;
     RECT  7.669 129.456 7.859 129.48 ;
     RECT  7.808 1.392 7.912 127.452 ;
     RECT  7.912 2.418 8.104 127.182 ;
     RECT  8.104 70.704 8.453 73.896 ;
     RECT  8.104 75.792 8.561 75.816 ;
     RECT  8.453 70.704 8.633 71.736 ;
     RECT  8.453 73.056 8.705 73.896 ;
     RECT  8.705 73.872 8.921 73.896 ;
     RECT  8.633 70.704 8.993 71.688 ;
     RECT  8.104 62.544 9.029 62.76 ;
     RECT  8.104 78.672 9.097 79.848 ;
     RECT  8.993 70.704 9.107 70.824 ;
     RECT  8.104 64.32 9.173 69.72 ;
     RECT  9.097 78.672 9.209 80.328 ;
     RECT  9.209 78.72 9.317 80.328 ;
     RECT  8.104 24.912 9.497 60.312 ;
     RECT  9.173 64.32 9.605 64.968 ;
     RECT  9.605 64.416 9.713 64.968 ;
     RECT  9.173 66.144 9.713 69.72 ;
     RECT  9.317 79.2 9.781 80.328 ;
     RECT  9.781 79.2 9.965 80.376 ;
     RECT  9.965 79.2 10.073 80.328 ;
     RECT  9.713 67.824 10.109 69.72 ;
     RECT  9.301 81.456 10.145 81.48 ;
     RECT  10.109 68.448 10.285 69.72 ;
     RECT  9.107 70.8 10.285 70.824 ;
     RECT  9.713 64.416 10.649 64.44 ;
     RECT  9.713 66.144 10.649 66.648 ;
     RECT  10.649 66.624 10.691 66.648 ;
     RECT  9.497 25.008 10.865 60.312 ;
     RECT  9.637 74.688 11.005 74.712 ;
     RECT  11.005 74.688 11.149 75 ;
     RECT  10.073 79.44 11.185 80.328 ;
     RECT  10.285 68.448 11.189 70.824 ;
     RECT  11.149 74.688 11.221 75.72 ;
     RECT  11.185 79.248 11.249 80.328 ;
     RECT  11.189 68.448 11.315 69.24 ;
     RECT  11.315 68.448 11.405 68.856 ;
     RECT  11.269 67.248 11.585 67.272 ;
     RECT  11.221 74.688 11.893 75.768 ;
     RECT  10.789 73.392 11.945 73.416 ;
     RECT  11.893 74.592 11.98 75.768 ;
     RECT  11.249 79.2 12.227 80.328 ;
     RECT  12.181 78.192 12.301 78.216 ;
     RECT  11.98 74.64 12.332 75.768 ;
     RECT  12.301 78.192 12.445 78.264 ;
     RECT  11.749 84.336 12.757 84.36 ;
     RECT  12.332 74.64 12.985 76.68 ;
     RECT  12.445 77.856 12.985 78.264 ;
     RECT  7.912 1.392 13.208 1.416 ;
     RECT  10.865 25.008 13.208 29.304 ;
     RECT  10.865 30.288 13.208 60.312 ;
     RECT  9.029 62.544 13.208 62.568 ;
     RECT  11.405 68.832 13.208 68.856 ;
     RECT  11.189 70.8 13.208 70.824 ;
     RECT  12.985 74.64 13.208 78.264 ;
     RECT  12.227 79.296 13.208 80.328 ;
     RECT  12.757 84.288 13.208 84.36 ;
     RECT  12.229 87.648 13.208 87.672 ;
     RECT  8.104 88.704 13.208 124.392 ;
     RECT  13.093 125.952 13.208 125.976 ;
     RECT  13.093 129.456 13.283 129.48 ;
     RECT  13.208 1.392 13.312 127.452 ;
     RECT  13.312 2.418 13.504 127.182 ;
     RECT  13.504 77.328 13.529 78.12 ;
     RECT  13.504 125.952 13.637 125.976 ;
     RECT  13.504 74.64 13.709 75.24 ;
     RECT  13.504 83.184 13.781 83.208 ;
     RECT  13.504 87.648 13.889 87.672 ;
     RECT  13.504 25.008 14.573 28.824 ;
     RECT  13.504 30.288 14.645 60.312 ;
     RECT  13.504 82.128 14.725 82.152 ;
     RECT  13.529 77.952 14.76 78.12 ;
     RECT  14.76 77.808 14.821 78.12 ;
     RECT  13.504 79.2 14.821 80.328 ;
     RECT  14.725 82.128 14.893 82.2 ;
     RECT  13.709 75.216 15.005 75.24 ;
     RECT  14.893 82.128 15.041 83.016 ;
     RECT  15.041 82.128 15.433 82.728 ;
     RECT  14.821 77.808 15.581 80.328 ;
     RECT  15.581 78.624 15.676 80.328 ;
     RECT  14.573 27.072 15.797 28.824 ;
     RECT  15.505 84.864 15.865 84.888 ;
     RECT  15.865 84.768 15.935 84.888 ;
     RECT  15.205 128.784 15.976 128.808 ;
     RECT  15.433 81.312 16.013 82.728 ;
     RECT  15.935 84.768 16.076 85.512 ;
     RECT  15.976 128.736 16.121 128.808 ;
     RECT  15.676 79.2 16.163 80.328 ;
     RECT  16.076 84.768 16.163 85.608 ;
     RECT  16.163 84.768 16.261 85.512 ;
     RECT  16.181 129.456 16.265 129.48 ;
     RECT  15.797 27.6 16.301 28.824 ;
     RECT  16.22 127.68 16.307 127.704 ;
     RECT  16.261 84.384 16.553 85.512 ;
     RECT  16.301 28.8 16.589 28.824 ;
     RECT  14.645 30.288 16.661 35.304 ;
     RECT  13.504 88.704 16.697 124.392 ;
     RECT  16.013 81.312 16.985 82.68 ;
     RECT  16.697 88.752 17.093 124.392 ;
     RECT  5.821 0.144 17.341 0.168 ;
     RECT  13.312 1.392 17.341 1.416 ;
     RECT  17.405 83.232 17.42 83.256 ;
     RECT  16.553 84.384 17.42 85.272 ;
     RECT  16.163 79.2 17.507 80.28 ;
     RECT  17.507 79.2 17.555 80.088 ;
     RECT  17.42 83.232 17.637 85.272 ;
     RECT  17.093 88.752 17.701 93.336 ;
     RECT  16.985 81.312 18.061 81.72 ;
     RECT  17.701 88.32 18.14 93.336 ;
     RECT  17.637 83.232 18.469 85.512 ;
     RECT  17.461 86.736 18.469 86.76 ;
     RECT  17.341 0.144 18.608 1.416 ;
     RECT  14.573 25.008 18.608 25.608 ;
     RECT  16.301 27.6 18.608 27.624 ;
     RECT  16.661 30.576 18.608 35.304 ;
     RECT  14.645 36.288 18.608 60.312 ;
     RECT  13.504 62.544 18.608 62.568 ;
     RECT  17.555 80.064 18.608 80.088 ;
     RECT  18.061 81.072 18.608 81.72 ;
     RECT  18.469 82.704 18.608 86.76 ;
     RECT  18.14 87.792 18.608 93.336 ;
     RECT  17.093 94.32 18.608 124.392 ;
     RECT  18.469 129.456 18.707 129.48 ;
     RECT  18.608 0.144 18.712 127.452 ;
     RECT  18.712 2.418 18.904 127.182 ;
     RECT  18.904 27.6 18.965 27.624 ;
     RECT  18.904 82.704 19.001 86.76 ;
     RECT  18.904 81.072 19.109 81.48 ;
     RECT  19.001 83.568 19.109 86.76 ;
     RECT  18.904 91.728 19.181 93.336 ;
     RECT  19.181 91.728 19.217 92.28 ;
     RECT  19.217 91.728 19.397 92.232 ;
     RECT  19.109 81.36 19.505 81.48 ;
     RECT  19.397 91.728 19.577 92.184 ;
     RECT  18.904 30.576 19.685 35.304 ;
     RECT  19.109 83.568 19.715 84.984 ;
     RECT  18.904 125.952 19.721 125.976 ;
     RECT  19.715 84.336 19.757 84.984 ;
     RECT  18.904 88.752 19.793 90.648 ;
     RECT  19.793 90.624 19.829 90.648 ;
     RECT  19.577 91.728 19.901 91.752 ;
     RECT  19.505 81.36 20.153 81.384 ;
     RECT  18.712 0.144 20.689 1.416 ;
     RECT  19.109 86.016 20.797 86.76 ;
     RECT  19.685 30.576 20.801 33.288 ;
     RECT  20.629 127.632 20.837 127.656 ;
     RECT  20.801 31.104 20.873 33.288 ;
     RECT  19.793 88.752 21.053 89.544 ;
     RECT  19.757 84.432 21.061 84.984 ;
     RECT  21.061 84.192 21.085 84.984 ;
     RECT  21.085 83.856 21.107 84.984 ;
     RECT  20.873 32.784 21.233 33.288 ;
     RECT  20.873 31.104 21.485 31.8 ;
     RECT  21.637 128.208 21.773 128.232 ;
     RECT  21.107 83.856 21.881 84.456 ;
     RECT  21.233 33.024 21.953 33.288 ;
     RECT  20.797 85.968 22.093 86.76 ;
     RECT  21.053 88.752 22.117 89.16 ;
     RECT  22.117 88.752 22.165 89.544 ;
     RECT  22.165 88.656 22.237 89.544 ;
     RECT  21.485 31.776 22.349 31.8 ;
     RECT  21.881 84.336 22.525 84.456 ;
     RECT  22.093 85.968 22.525 87.624 ;
     RECT  22.525 84.336 22.565 87.624 ;
     RECT  22.237 88.656 22.645 89.688 ;
     RECT  18.904 94.848 22.777 95.112 ;
     RECT  18.904 96.288 22.777 124.392 ;
     RECT  22.565 85.152 22.787 87.624 ;
     RECT  22.787 86.352 22.811 87.624 ;
     RECT  22.645 88.656 22.853 90.456 ;
     RECT  22.777 94.848 23.353 124.392 ;
     RECT  22.853 88.752 23.381 90.456 ;
     RECT  23.605 128.208 23.717 128.232 ;
     RECT  23.353 94.656 23.929 124.392 ;
     RECT  20.689 0.144 24.008 1.992 ;
     RECT  21.953 33.024 24.008 33.048 ;
     RECT  19.685 34.608 24.008 35.304 ;
     RECT  18.904 36.288 24.008 60.312 ;
     RECT  18.904 62.544 24.008 62.568 ;
     RECT  22.787 85.152 24.008 85.176 ;
     RECT  22.811 86.352 24.008 87.672 ;
     RECT  23.381 88.752 24.008 90.648 ;
     RECT  23.125 91.728 24.008 91.752 ;
     RECT  23.929 94.656 24.008 124.584 ;
     RECT  24.085 129.456 24.185 129.48 ;
     RECT  24.008 0.144 24.304 127.704 ;
     RECT  24.304 95.136 24.509 124.872 ;
     RECT  24.304 86.592 24.545 91.08 ;
     RECT  24.509 95.568 24.545 99.192 ;
     RECT  24.545 98.112 24.581 99.192 ;
     RECT  24.304 127.68 24.659 127.704 ;
     RECT  24.545 89.76 24.689 91.08 ;
     RECT  24.545 86.592 24.899 88.776 ;
     RECT  24.899 87.312 24.94 88.776 ;
     RECT  24.509 100.512 24.941 124.872 ;
     RECT  24.941 100.8 24.977 124.872 ;
     RECT  24.545 95.568 25.013 96.84 ;
     RECT  25.013 95.568 25.193 96.744 ;
     RECT  24.977 100.8 25.301 124.776 ;
     RECT  24.581 98.448 25.409 99.192 ;
     RECT  25.193 95.664 25.481 96.744 ;
     RECT  25.409 98.64 25.481 99.192 ;
     RECT  25.093 128.784 25.481 128.808 ;
     RECT  25.301 100.8 25.561 124.632 ;
     RECT  25.481 95.664 25.574 96.696 ;
     RECT  25.574 95.712 25.589 96.696 ;
     RECT  25.561 100.8 25.589 124.584 ;
     RECT  24.304 36.528 25.625 60.312 ;
     RECT  24.94 87.6 25.657 88.776 ;
     RECT  24.689 90.24 25.657 91.08 ;
     RECT  25.481 98.736 25.661 98.76 ;
     RECT  25.589 95.712 25.733 96.36 ;
     RECT  24.304 92.592 25.765 92.616 ;
     RECT  25.589 100.8 25.841 124.44 ;
     RECT  25.657 87.6 26.125 91.08 ;
     RECT  26.06 126 26.147 126.024 ;
     RECT  26.125 87.168 26.201 91.08 ;
     RECT  25.733 95.712 26.309 95.736 ;
     RECT  26.201 87.168 26.453 90.696 ;
     RECT  25.765 92.592 26.489 92.808 ;
     RECT  25.625 36.528 26.633 38.52 ;
     RECT  26.581 127.056 26.777 127.08 ;
     RECT  26.453 87.168 26.885 90.648 ;
     RECT  26.885 87.168 26.921 89.736 ;
     RECT  26.633 36.528 27.065 36.552 ;
     RECT  26.489 92.784 27.205 92.808 ;
     RECT  25.625 39.504 27.209 60.312 ;
     RECT  26.921 87.168 27.281 89.448 ;
     RECT  27.281 87.168 27.395 88.92 ;
     RECT  27.209 40.56 27.533 60.312 ;
     RECT  27.061 94.08 27.541 94.104 ;
     RECT  26.633 37.584 27.677 38.52 ;
     RECT  27.205 92.784 27.709 92.952 ;
     RECT  27.541 94.08 27.709 94.152 ;
     RECT  27.673 91.44 27.925 91.464 ;
     RECT  27.709 92.784 27.925 94.152 ;
     RECT  27.853 95.184 28.069 95.208 ;
     RECT  27.677 37.584 28.253 38.28 ;
     RECT  27.209 39.504 28.289 39.528 ;
     RECT  27.925 91.44 28.717 94.152 ;
     RECT  28.069 95.136 28.717 95.208 ;
     RECT  28.069 98.592 28.997 98.616 ;
     RECT  24.304 0.144 29.408 1.992 ;
     RECT  28.253 38.256 29.408 38.28 ;
     RECT  27.533 40.56 29.408 52.008 ;
     RECT  27.533 53.52 29.408 60.312 ;
     RECT  24.304 62.544 29.408 62.568 ;
     RECT  27.395 87.6 29.408 88.92 ;
     RECT  28.717 91.44 29.408 95.208 ;
     RECT  28.997 98.592 29.408 99.192 ;
     RECT  25.841 100.8 29.408 124.392 ;
     RECT  28.508 125.424 29.408 125.448 ;
     RECT  29.408 0.144 29.512 127.452 ;
     RECT  29.516 128.832 29.603 128.856 ;
     RECT  29.512 0.144 29.689 127.182 ;
     RECT  29.689 0.096 29.704 127.182 ;
     RECT  29.704 0.096 29.891 1.992 ;
     RECT  29.704 92.928 29.909 93.048 ;
     RECT  29.704 126 30.083 126.504 ;
     RECT  29.704 95.136 30.413 96.648 ;
     RECT  30.083 126.48 30.593 126.504 ;
     RECT  30.413 95.184 30.707 96.648 ;
     RECT  29.704 87.6 30.809 88.92 ;
     RECT  29.891 0.144 31.021 1.992 ;
     RECT  29.704 100.224 31.061 124.392 ;
     RECT  29.909 92.928 31.097 92.952 ;
     RECT  31.061 104.16 31.097 124.392 ;
     RECT  31.061 100.224 31.169 103.176 ;
     RECT  31.097 104.88 31.169 124.392 ;
     RECT  30.707 95.184 31.241 95.832 ;
     RECT  30.997 128.208 31.241 128.232 ;
     RECT  30.809 87.6 31.427 88.776 ;
     RECT  31.34 93.312 31.427 93.336 ;
     RECT  31.241 95.184 31.489 95.64 ;
     RECT  31.309 98.208 31.525 98.232 ;
     RECT  29.704 38.256 31.637 38.28 ;
     RECT  31.489 94.944 31.777 95.64 ;
     RECT  31.169 101.664 31.925 103.176 ;
     RECT  31.093 96.912 31.961 96.936 ;
     RECT  31.925 103.152 31.997 103.176 ;
     RECT  31.777 93.984 32.003 95.64 ;
     RECT  31.925 101.664 32.069 102.168 ;
     RECT  31.525 98.208 32.177 98.424 ;
     RECT  29.704 62.544 32.245 62.568 ;
     RECT  31.427 88.032 32.291 88.776 ;
     RECT  32.005 129.456 32.357 129.48 ;
     RECT  32.177 98.352 32.461 98.424 ;
     RECT  31.169 105.504 32.461 124.392 ;
     RECT  32.461 104.592 32.501 124.392 ;
     RECT  32.453 126.48 32.537 126.504 ;
     RECT  32.461 98.352 32.569 99 ;
     RECT  32.003 94.272 32.579 95.64 ;
     RECT  32.579 94.56 32.636 95.64 ;
     RECT  31.169 100.224 32.677 100.248 ;
     RECT  32.291 88.752 32.723 88.776 ;
     RECT  32.636 94.56 32.723 95.736 ;
     RECT  29.704 41.232 32.789 52.008 ;
     RECT  32.723 94.56 32.897 95.448 ;
     RECT  32.501 104.592 32.965 105.528 ;
     RECT  32.965 104.352 33.145 105.528 ;
     RECT  32.789 41.232 33.185 41.256 ;
     RECT  32.789 42.48 33.221 52.008 ;
     RECT  33.145 104.304 33.289 105.528 ;
     RECT  33.289 104.256 33.329 105.528 ;
     RECT  32.569 98.352 33.401 99.192 ;
     RECT  33.329 104.256 33.469 104.76 ;
     RECT  33.469 103.824 33.473 104.76 ;
     RECT  32.069 102 33.493 102.168 ;
     RECT  32.677 100.224 33.613 100.92 ;
     RECT  33.493 102 33.613 102.6 ;
     RECT  32.501 106.752 33.617 124.392 ;
     RECT  34.297 126.624 34.693 126.648 ;
     RECT  34.693 126.528 34.765 126.648 ;
     RECT  31.021 0.048 34.808 1.992 ;
     RECT  33.221 42.48 34.808 43.8 ;
     RECT  33.221 44.976 34.808 52.008 ;
     RECT  29.704 53.52 34.808 60.312 ;
     RECT  32.245 61.92 34.808 62.568 ;
     RECT  32.897 94.944 34.808 95.448 ;
     RECT  33.401 98.352 34.808 99.048 ;
     RECT  33.613 100.224 34.808 102.6 ;
     RECT  33.473 103.824 34.808 104.712 ;
     RECT  33.617 106.992 34.808 109.272 ;
     RECT  33.617 110.256 34.808 124.392 ;
     RECT  33.932 125.424 34.808 125.448 ;
     RECT  34.765 126.528 34.808 126.744 ;
     RECT  34.808 0.048 34.912 127.452 ;
     RECT  34.912 0.048 35.104 127.182 ;
     RECT  35.104 126.576 35.219 126.744 ;
     RECT  35.104 45.744 35.417 52.008 ;
     RECT  35.104 61.92 35.453 62.568 ;
     RECT  35.104 100.272 35.525 102.696 ;
     RECT  35.104 98.352 35.633 99 ;
     RECT  34.981 129.456 35.633 129.48 ;
     RECT  35.104 42.768 35.669 43.56 ;
     RECT  35.633 98.976 35.705 99 ;
     RECT  35.417 45.984 35.957 52.008 ;
     RECT  35.219 126.576 35.987 126.6 ;
     RECT  35.104 53.52 36.209 60.312 ;
     RECT  35.104 106.992 36.313 108.408 ;
     RECT  36.313 106.992 36.385 109.032 ;
     RECT  35.453 62.544 36.425 62.568 ;
     RECT  36.385 106.848 36.457 109.032 ;
     RECT  35.104 110.352 36.457 124.392 ;
     RECT  36.209 58.416 36.821 60.312 ;
     RECT  35.669 43.536 36.857 43.56 ;
     RECT  36.457 106.848 36.893 124.392 ;
     RECT  35.525 102.144 36.961 102.696 ;
     RECT  36.893 106.848 36.965 107.976 ;
     RECT  36.961 102.144 36.997 103.176 ;
     RECT  36.565 104.16 36.997 104.184 ;
     RECT  36.965 106.848 37.037 107.832 ;
     RECT  36.893 108.96 37.109 124.392 ;
     RECT  37.109 108.96 37.217 108.984 ;
     RECT  36.997 102.144 37.249 104.184 ;
     RECT  37.037 106.848 37.253 107.736 ;
     RECT  35.957 46.848 37.361 52.008 ;
     RECT  37.249 102.048 37.429 104.184 ;
     RECT  37.253 106.848 37.541 107.592 ;
     RECT  37.109 110.256 37.613 124.392 ;
     RECT  35.525 100.272 37.619 100.92 ;
     RECT  37.429 102.048 37.619 104.28 ;
     RECT  37.361 47.088 37.649 52.008 ;
     RECT  37.619 102.576 38.005 104.28 ;
     RECT  38.005 102.576 38.051 104.856 ;
     RECT  37.957 125.376 38.117 125.4 ;
     RECT  36.209 53.52 38.153 57.192 ;
     RECT  35.104 95.424 38.483 95.448 ;
     RECT  38.365 127.104 38.483 127.128 ;
     RECT  38.051 102.96 38.585 102.984 ;
     RECT  38.153 53.52 38.621 55.992 ;
     RECT  37.619 100.32 38.653 100.92 ;
     RECT  38.653 100.32 38.729 101.496 ;
     RECT  38.051 104.112 38.729 104.856 ;
     RECT  38.729 100.896 38.869 101.496 ;
     RECT  37.649 47.712 38.873 52.008 ;
     RECT  37.613 110.256 38.917 110.808 ;
     RECT  38.873 47.712 39.017 51.48 ;
     RECT  38.729 104.112 39.121 104.328 ;
     RECT  37.613 111.984 39.157 124.392 ;
     RECT  37.237 105.84 39.301 105.864 ;
     RECT  37.541 107.28 39.301 107.592 ;
     RECT  38.869 100.896 39.409 101.88 ;
     RECT  38.917 109.968 39.625 110.808 ;
     RECT  39.409 100.896 39.733 101.928 ;
     RECT  39.884 128.256 39.971 128.28 ;
     RECT  35.104 0.048 40.208 2.04 ;
     RECT  39.017 48 40.208 51.48 ;
     RECT  38.621 53.52 40.208 55.704 ;
     RECT  38.153 57.168 40.208 57.192 ;
     RECT  36.821 58.416 40.208 59.208 ;
     RECT  36.821 60.288 40.208 60.312 ;
     RECT  39.733 100.896 40.208 101.976 ;
     RECT  39.121 103.44 40.208 104.328 ;
     RECT  39.301 105.36 40.208 105.864 ;
     RECT  39.301 106.944 40.208 107.592 ;
     RECT  39.625 109.968 40.208 110.856 ;
     RECT  39.157 111.984 40.208 124.824 ;
     RECT  40.208 0.048 40.312 127.452 ;
     RECT  40.312 0.048 40.355 127.182 ;
     RECT  40.069 129.456 40.451 129.48 ;
     RECT  40.355 1.968 40.504 127.182 ;
     RECT  40.504 101.088 40.745 101.976 ;
     RECT  40.745 101.088 40.817 101.928 ;
     RECT  40.504 104.928 40.889 105.912 ;
     RECT  40.504 106.896 41.033 108.84 ;
     RECT  40.504 112.224 41.033 124.824 ;
     RECT  41.033 106.992 41.285 108.84 ;
     RECT  40.504 110.544 41.429 110.856 ;
     RECT  40.817 101.088 41.537 101.736 ;
     RECT  41.033 112.224 41.641 117.096 ;
     RECT  41.285 107.376 41.789 108.84 ;
     RECT  41.641 112.176 41.861 117.096 ;
     RECT  41.789 108.192 41.969 108.84 ;
     RECT  41.861 112.176 41.969 116.712 ;
     RECT  41.969 116.064 42.005 116.712 ;
     RECT  41.893 128.784 42.077 128.808 ;
     RECT  40.355 0.048 42.083 0.84 ;
     RECT  41.969 112.176 42.113 114.984 ;
     RECT  41.429 110.592 42.149 110.856 ;
     RECT  41.033 118.128 42.185 124.824 ;
     RECT  40.504 51.216 42.293 51.48 ;
     RECT  42.113 112.416 42.329 114.984 ;
     RECT  42.353 127.056 42.437 127.08 ;
     RECT  40.504 49.488 42.509 50.04 ;
     RECT  40.504 57.168 42.757 57.192 ;
     RECT  42.757 57.168 42.797 57.336 ;
     RECT  42.083 0.096 42.905 0.84 ;
     RECT  40.504 53.52 43.049 55.704 ;
     RECT  41.969 108.384 43.052 108.84 ;
     RECT  42.905 0.192 43.091 0.84 ;
     RECT  42.329 112.464 43.117 114.984 ;
     RECT  40.889 105.792 43.139 105.912 ;
     RECT  43.052 107.76 43.139 108.84 ;
     RECT  43.139 108.336 43.153 108.84 ;
     RECT  43.081 109.872 43.153 109.896 ;
     RECT  43.049 53.52 43.157 54.984 ;
     RECT  43.117 112.464 43.225 115.032 ;
     RECT  42.005 116.352 43.225 116.712 ;
     RECT  43.196 111.456 43.283 111.48 ;
     RECT  42.185 118.176 43.337 124.824 ;
     RECT  43.225 112.464 43.409 116.712 ;
     RECT  43.361 129.456 43.445 129.48 ;
     RECT  42.293 51.456 43.481 51.48 ;
     RECT  42.509 49.488 43.517 49.512 ;
     RECT  43.409 114.864 43.625 116.712 ;
     RECT  43.625 115.008 43.661 116.712 ;
     RECT  43.409 112.464 43.697 113.784 ;
     RECT  43.153 108.336 43.729 109.896 ;
     RECT  43.697 113.088 43.769 113.784 ;
     RECT  43.769 113.088 43.805 113.448 ;
     RECT  43.337 119.232 43.877 124.824 ;
     RECT  43.805 113.424 43.907 113.448 ;
     RECT  43.661 115.536 43.909 116.712 ;
     RECT  43.157 53.52 43.913 53.544 ;
     RECT  40.504 1.968 44.003 2.04 ;
     RECT  43.909 115.536 44.201 116.904 ;
     RECT  43.909 126 44.237 126.024 ;
     RECT  43.877 121.152 44.269 124.824 ;
     RECT  44.269 121.152 44.387 124.872 ;
     RECT  44.201 116.592 44.417 116.904 ;
     RECT  44.387 121.152 44.453 124.392 ;
     RECT  44.201 115.536 44.489 115.56 ;
     RECT  44.417 116.688 44.489 116.904 ;
     RECT  44.489 116.688 44.525 116.712 ;
     RECT  43.729 108.336 44.561 110.04 ;
     RECT  43.091 0.192 44.837 0.312 ;
     RECT  44.665 128.256 44.915 128.28 ;
     RECT  44.837 0.096 44.921 0.312 ;
     RECT  44.561 108.336 44.989 109.128 ;
     RECT  44.921 0.192 45.301 0.312 ;
     RECT  45.277 125.616 45.308 125.64 ;
     RECT  43.877 119.232 45.385 119.976 ;
     RECT  44.453 121.152 45.385 124.152 ;
     RECT  44.989 108.096 45.529 109.128 ;
     RECT  44.003 2.016 45.608 2.04 ;
     RECT  43.157 54.96 45.608 54.984 ;
     RECT  42.797 57.312 45.608 57.336 ;
     RECT  40.504 58.416 45.608 59.208 ;
     RECT  40.504 60.288 45.608 60.312 ;
     RECT  41.701 70.032 45.608 70.056 ;
     RECT  42.613 75.168 45.608 75.192 ;
     RECT  43.477 82.464 45.608 82.488 ;
     RECT  44.389 88.368 45.608 88.392 ;
     RECT  41.537 101.088 45.608 101.112 ;
     RECT  43.139 105.888 45.608 105.912 ;
     RECT  45.529 108.096 45.608 109.272 ;
     RECT  44.305 111.12 45.608 111.144 ;
     RECT  45.205 114 45.608 114.024 ;
     RECT  45.493 115.152 45.608 115.176 ;
     RECT  45.385 119.232 45.608 124.152 ;
     RECT  45.308 125.616 45.608 125.688 ;
     RECT  45.608 2.016 45.712 127.452 ;
     RECT  45.712 2.016 45.827 127.182 ;
     RECT  45.827 2.418 45.904 127.182 ;
     RECT  45.829 129.456 46.019 129.48 ;
     RECT  45.904 118.896 46.037 123.48 ;
     RECT  45.904 113.76 46.163 115.176 ;
     RECT  45.904 110.832 46.181 110.856 ;
     RECT  45.904 117.408 46.181 117.432 ;
     RECT  46.037 121.584 46.181 123.48 ;
     RECT  45.301 0.192 46.213 0.84 ;
     RECT  46.037 118.896 46.253 120.504 ;
     RECT  46.213 0.144 46.309 0.84 ;
     RECT  45.904 116.304 46.355 116.328 ;
     RECT  45.904 107.76 46.397 109.272 ;
     RECT  45.904 124.512 46.433 126.024 ;
     RECT  46.253 118.896 46.505 120.024 ;
     RECT  45.904 101.088 46.643 101.112 ;
     RECT  46.163 114.288 46.721 115.176 ;
     RECT  45.904 57.312 46.829 57.336 ;
     RECT  46.433 126 46.883 126.024 ;
     RECT  46.433 124.512 46.897 124.824 ;
     RECT  46.505 118.896 46.973 119.976 ;
     RECT  45.904 58.416 47.261 58.44 ;
     RECT  46.973 118.992 47.297 119.976 ;
     RECT  46.397 107.76 47.369 108.744 ;
     RECT  46.721 114.288 47.369 114.792 ;
     RECT  47.369 114.288 47.401 114.312 ;
     RECT  46.181 121.584 47.401 123 ;
     RECT  47.401 121.536 47.437 123 ;
     RECT  47.369 107.76 47.441 108.36 ;
     RECT  47.437 121.2 47.473 123 ;
     RECT  47.317 128.208 47.477 128.232 ;
     RECT  47.441 108.096 47.549 108.36 ;
     RECT  47.297 118.992 47.765 119.784 ;
     RECT  47.473 121.2 47.843 123.144 ;
     RECT  47.761 116.208 47.893 116.232 ;
     RECT  46.897 124.32 47.909 124.824 ;
     RECT  47.893 116.208 47.939 117 ;
     RECT  47.939 116.976 47.977 117 ;
     RECT  47.977 116.976 48.017 117.432 ;
     RECT  45.904 112.08 48.037 112.392 ;
     RECT  47.765 118.992 48.053 119.688 ;
     RECT  47.941 62.592 48.157 62.616 ;
     RECT  47.549 108.096 48.197 108.216 ;
     RECT  47.843 121.2 48.197 122.712 ;
     RECT  48.197 108.192 48.233 108.216 ;
     RECT  47.909 124.32 48.305 124.344 ;
     RECT  48.197 121.2 48.341 121.944 ;
     RECT  48.293 129.456 48.377 129.48 ;
     RECT  48.053 118.992 48.445 119.64 ;
     RECT  48.037 111.888 48.469 112.392 ;
     RECT  47.401 113.808 48.469 114.312 ;
     RECT  48.445 118.56 48.563 119.64 ;
     RECT  48.017 117.408 48.593 117.432 ;
     RECT  48.341 121.536 48.629 121.944 ;
     RECT  48.629 121.584 48.773 121.944 ;
     RECT  48.733 128.832 48.851 128.856 ;
     RECT  48.469 111.888 48.881 114.312 ;
     RECT  48.563 119.472 49.061 119.64 ;
     RECT  49.129 65.904 49.273 65.928 ;
     RECT  48.157 62.304 49.381 62.616 ;
     RECT  49.237 67.488 49.417 67.512 ;
     RECT  49.381 62.304 49.465 63.816 ;
     RECT  49.465 63.792 49.468 63.816 ;
     RECT  49.417 67.488 49.489 67.608 ;
     RECT  48.773 121.584 49.67 121.704 ;
     RECT  49.273 65.856 49.777 65.928 ;
     RECT  49.489 67.488 49.885 67.656 ;
     RECT  48.881 111.888 50.029 113.88 ;
     RECT  49.813 129.456 50.105 129.48 ;
     RECT  50.053 117.216 50.137 117.24 ;
     RECT  49.777 65.856 50.317 65.976 ;
     RECT  48.229 125.424 50.317 125.448 ;
     RECT  49.285 128.208 50.501 128.232 ;
     RECT  50.317 65.664 50.569 65.976 ;
     RECT  49.885 67.008 50.569 67.656 ;
     RECT  50.425 120.336 50.641 120.36 ;
     RECT  50.137 117.216 50.857 117.432 ;
     RECT  50.317 125.424 50.965 125.496 ;
     RECT  49.465 62.304 51.008 62.616 ;
     RECT  50.569 65.664 51.008 67.656 ;
     RECT  45.904 70.032 51.008 70.056 ;
     RECT  45.904 75.168 51.008 75.192 ;
     RECT  45.904 82.464 51.008 82.488 ;
     RECT  45.904 88.368 51.008 88.392 ;
     RECT  47.125 106.464 51.008 106.488 ;
     RECT  50.029 111.888 51.008 114.552 ;
     RECT  49.021 115.824 51.008 115.848 ;
     RECT  50.857 116.976 51.008 117.432 ;
     RECT  50.641 119.424 51.008 120.36 ;
     RECT  49.67 121.584 51.008 121.656 ;
     RECT  50.713 123.024 51.008 123.048 ;
     RECT  50.965 125.424 51.008 125.64 ;
     RECT  50.741 127.056 51.008 127.08 ;
     RECT  51.008 2.148 51.112 127.704 ;
     RECT  50.965 128.832 51.299 128.856 ;
     RECT  51.112 2.418 51.304 127.704 ;
     RECT  51.304 113.568 51.329 113.592 ;
     RECT  51.304 111.888 51.401 112.248 ;
     RECT  51.304 116.976 51.437 117 ;
     RECT  51.401 111.984 51.731 112.248 ;
     RECT  51.304 119.472 51.731 121.656 ;
     RECT  51.304 127.68 51.827 127.704 ;
     RECT  51.304 70.032 51.833 70.056 ;
     RECT  46.309 0.048 52.225 0.84 ;
     RECT  52.253 129.456 52.337 129.48 ;
     RECT  51.731 120.768 52.445 121.656 ;
     RECT  51.304 123.072 52.481 123.096 ;
     RECT  52.445 121.632 52.513 121.656 ;
     RECT  51.304 125.184 52.513 125.64 ;
     RECT  52.513 124.464 52.549 125.64 ;
     RECT  51.731 119.472 52.693 119.736 ;
     RECT  52.549 124.368 52.693 125.64 ;
     RECT  52.693 128.832 52.787 128.856 ;
     RECT  52.693 119.088 52.796 119.736 ;
     RECT  52.796 117.936 52.837 117.96 ;
     RECT  52.796 119.088 52.837 120.216 ;
     RECT  52.225 0.048 52.877 1.656 ;
     RECT  52.837 117.936 52.883 120.216 ;
     RECT  52.693 124.272 52.909 125.64 ;
     RECT  52.873 62.256 53.021 62.28 ;
     RECT  53.017 71.472 53.053 71.496 ;
     RECT  52.981 72.768 53.053 72.792 ;
     RECT  52.729 116.736 53.129 116.76 ;
     RECT  51.304 75.168 53.305 75.192 ;
     RECT  52.877 0.048 53.309 0.12 ;
     RECT  53.228 128.256 53.315 128.28 ;
     RECT  53.305 75.168 53.341 75.72 ;
     RECT  52.909 124.272 53.341 125.736 ;
     RECT  53.341 74.976 53.377 75.72 ;
     RECT  53.053 71.472 53.417 72.792 ;
     RECT  53.417 71.472 53.453 72.504 ;
     RECT  53.377 73.776 53.485 75.72 ;
     RECT  52.883 119.472 53.737 120.216 ;
     RECT  52.513 121.632 53.737 122.664 ;
     RECT  53.749 128.208 53.849 128.232 ;
     RECT  53.309 0.096 53.885 0.12 ;
     RECT  53.485 73.536 53.917 75.72 ;
     RECT  52.883 118.368 53.993 118.392 ;
     RECT  53.737 119.472 54.133 122.664 ;
     RECT  53.341 123.696 54.133 125.736 ;
     RECT  53.917 73.536 54.173 75.816 ;
     RECT  54.133 119.472 54.421 125.736 ;
     RECT  54.493 8.688 54.529 8.712 ;
     RECT  53.453 72.144 54.529 72.504 ;
     RECT  54.529 8.16 54.601 8.712 ;
     RECT  54.421 119.088 54.659 125.736 ;
     RECT  54.601 7.872 54.673 8.712 ;
     RECT  54.659 120.96 54.709 125.736 ;
     RECT  54.529 72.144 54.749 72.6 ;
     RECT  54.659 119.088 54.749 119.928 ;
     RECT  54.709 120.96 54.749 127.08 ;
     RECT  54.749 72.192 54.821 72.6 ;
     RECT  54.821 72.192 54.929 72.36 ;
     RECT  54.853 57.936 54.961 57.96 ;
     RECT  54.749 121.008 54.965 127.08 ;
     RECT  54.749 119.088 55.037 119.688 ;
     RECT  54.965 121.008 55.037 125.736 ;
     RECT  54.929 72.192 55.073 72.264 ;
     RECT  55.037 121.008 55.073 125.496 ;
     RECT  54.997 51.456 55.105 51.48 ;
     RECT  54.673 7.632 55.177 8.712 ;
     RECT  55.073 72.24 55.217 72.264 ;
     RECT  55.073 121.008 55.235 125.448 ;
     RECT  55.105 51.216 55.237 51.48 ;
     RECT  51.731 111.984 55.237 112.008 ;
     RECT  52.877 1.632 55.537 1.656 ;
     RECT  55.537 1.392 55.609 1.656 ;
     RECT  55.069 52.704 55.609 52.728 ;
     RECT  55.237 51.168 55.645 51.48 ;
     RECT  55.141 47.088 55.717 47.112 ;
     RECT  55.753 40.368 55.789 40.392 ;
     RECT  55.645 50.832 55.813 51.48 ;
     RECT  56.257 38.784 56.293 38.808 ;
     RECT  55.789 40.368 56.293 40.584 ;
     RECT  55.609 1.152 56.408 1.656 ;
     RECT  55.213 3.888 56.408 3.912 ;
     RECT  55.177 6.864 56.408 8.712 ;
     RECT  54.637 10.128 56.408 10.152 ;
     RECT  54.421 18.432 56.408 18.456 ;
     RECT  54.097 23.808 56.408 23.832 ;
     RECT  56.329 36.912 56.408 36.936 ;
     RECT  56.293 38.784 56.408 40.584 ;
     RECT  55.573 42.768 56.408 42.792 ;
     RECT  55.825 44.976 56.408 45 ;
     RECT  55.717 47.04 56.408 47.112 ;
     RECT  55.681 49.2 56.408 49.224 ;
     RECT  55.813 50.544 56.408 51.48 ;
     RECT  55.609 52.704 56.408 53.016 ;
     RECT  54.925 55.968 56.408 55.992 ;
     RECT  54.961 57.408 56.408 57.96 ;
     RECT  54.173 73.68 56.408 75.672 ;
     RECT  51.304 82.464 56.408 82.488 ;
     RECT  55.861 86.256 56.408 86.28 ;
     RECT  51.304 88.368 56.408 88.392 ;
     RECT  51.304 106.464 56.408 106.488 ;
     RECT  55.237 111.408 56.408 112.008 ;
     RECT  55.813 114.864 56.408 114.888 ;
     RECT  55.037 119.184 56.408 119.688 ;
     RECT  55.235 121.392 56.408 125.448 ;
     RECT  55.645 127.104 56.408 127.128 ;
     RECT  56.408 1.152 56.512 127.452 ;
     RECT  56.512 1.152 56.704 127.182 ;
     RECT  56.704 57.408 56.801 57.96 ;
     RECT  56.704 119.664 56.837 119.688 ;
     RECT  56.704 74.4 56.981 74.424 ;
     RECT  56.725 128.784 57.017 128.808 ;
     RECT  56.704 122.688 57.089 124.92 ;
     RECT  56.704 72.96 57.241 72.984 ;
     RECT  57.089 122.976 57.413 124.92 ;
     RECT  57.205 129.456 57.413 129.48 ;
     RECT  56.704 121.392 57.521 121.656 ;
     RECT  57.521 121.392 57.557 121.416 ;
     RECT  57.413 122.976 57.593 123 ;
     RECT  56.704 77.808 57.769 77.832 ;
     RECT  57.733 81.024 57.769 81.048 ;
     RECT  57.413 124.128 57.769 124.92 ;
     RECT  56.704 82.464 57.881 82.488 ;
     RECT  57.769 124.128 57.917 125.448 ;
     RECT  56.704 41.904 57.949 43.032 ;
     RECT  56.704 36.768 57.973 36.936 ;
     RECT  56.704 38.784 57.973 40.584 ;
     RECT  56.704 100.512 57.973 100.536 ;
     RECT  56.704 102.048 57.973 102.072 ;
     RECT  56.704 44.736 57.985 45 ;
     RECT  57.925 29.28 58.021 29.304 ;
     RECT  57.973 36.768 58.021 40.584 ;
     RECT  57.949 41.904 58.021 43.272 ;
     RECT  57.925 91.2 58.021 91.224 ;
     RECT  57.653 128.208 58.021 128.232 ;
     RECT  58.021 128.208 58.057 128.28 ;
     RECT  58.021 28.56 58.069 29.304 ;
     RECT  57.769 77.808 58.129 77.928 ;
     RECT  57.769 80.448 58.129 81.048 ;
     RECT  58.057 33.264 58.237 33.288 ;
     RECT  56.704 79.104 58.273 79.128 ;
     RECT  58.129 77.28 58.309 77.928 ;
     RECT  58.273 79.104 58.345 79.224 ;
     RECT  58.129 80.448 58.345 81.672 ;
     RECT  56.704 10.128 58.381 10.152 ;
     RECT  56.704 11.136 58.381 11.16 ;
     RECT  56.704 86.256 58.417 86.28 ;
     RECT  56.704 50.544 58.453 51.48 ;
     RECT  58.309 77.136 58.525 77.928 ;
     RECT  58.417 86.256 58.525 86.328 ;
     RECT  58.549 27.312 58.561 27.336 ;
     RECT  56.704 30.816 58.633 31.8 ;
     RECT  58.237 33.264 58.633 33.816 ;
     RECT  58.633 30.816 58.645 33.816 ;
     RECT  57.917 124.608 58.673 125.448 ;
     RECT  58.057 127.68 58.693 128.28 ;
     RECT  56.704 1.152 58.705 1.656 ;
     RECT  58.525 86.208 58.705 86.328 ;
     RECT  58.525 76.992 58.741 77.928 ;
     RECT  56.704 88.368 58.745 88.392 ;
     RECT  58.673 124.608 58.745 125.304 ;
     RECT  58.693 127.632 58.781 128.28 ;
     RECT  58.597 83.232 58.813 83.352 ;
     RECT  58.705 85.776 58.813 86.952 ;
     RECT  58.745 124.8 58.817 125.304 ;
     RECT  58.561 26.784 58.849 27.336 ;
     RECT  58.069 28.56 58.849 29.832 ;
     RECT  58.741 76.944 58.885 77.928 ;
     RECT  58.345 79.104 58.885 81.672 ;
     RECT  56.704 106.464 58.925 106.488 ;
     RECT  58.781 127.68 58.957 128.28 ;
     RECT  58.813 83.232 58.993 84.024 ;
     RECT  58.453 50.256 59.029 51.48 ;
     RECT  56.704 52.704 59.029 53.016 ;
     RECT  56.704 114.864 59.029 114.888 ;
     RECT  58.645 30.816 59.077 33.912 ;
     RECT  58.597 35.04 59.077 35.064 ;
     RECT  58.645 97.824 59.077 97.848 ;
     RECT  57.985 44.736 59.125 45.768 ;
     RECT  58.993 83.232 59.137 84.12 ;
     RECT  58.849 26.784 59.173 29.832 ;
     RECT  59.077 30.816 59.173 35.064 ;
     RECT  56.801 57.552 59.173 57.96 ;
     RECT  58.885 76.944 59.177 81.672 ;
     RECT  58.993 12.768 59.245 12.792 ;
     RECT  59.245 12.768 59.281 13.368 ;
     RECT  59.177 76.992 59.357 81.672 ;
     RECT  59.281 12.768 59.389 13.896 ;
     RECT  59.077 97.488 59.389 97.848 ;
     RECT  58.597 98.928 59.389 98.952 ;
     RECT  59.357 79.344 59.393 81.672 ;
     RECT  58.069 92.976 59.497 93 ;
     RECT  56.704 6.864 59.569 9.144 ;
     RECT  58.381 10.128 59.569 11.16 ;
     RECT  58.021 91.2 59.569 91.8 ;
     RECT  59.497 92.784 59.569 93 ;
     RECT  56.704 18.432 59.605 18.456 ;
     RECT  59.137 83.232 59.605 84.168 ;
     RECT  59.605 83.232 59.641 84.312 ;
     RECT  58.813 85.776 59.641 87.096 ;
     RECT  58.549 89.568 59.677 89.592 ;
     RECT  59.389 97.488 59.677 99.096 ;
     RECT  59.357 76.992 59.717 78.12 ;
     RECT  59.641 83.232 59.717 87.096 ;
     RECT  59.389 12.768 59.749 14.664 ;
     RECT  58.597 16.08 59.749 16.104 ;
     RECT  59.569 91.2 59.749 93 ;
     RECT  57.973 100.512 59.749 102.072 ;
     RECT  59.713 104.112 59.749 104.136 ;
     RECT  59.569 6.864 59.785 11.16 ;
     RECT  59.393 80.448 59.789 81.048 ;
     RECT  59.717 83.328 59.789 87.096 ;
     RECT  56.704 118.224 59.797 118.248 ;
     RECT  56.704 3.12 59.821 3.912 ;
     RECT  59.749 100.512 59.821 104.136 ;
     RECT  59.125 108.336 59.821 108.36 ;
     RECT  59.749 90.768 59.857 93 ;
     RECT  59.221 96.384 59.857 96.408 ;
     RECT  59.677 97.488 59.857 99.24 ;
     RECT  59.717 77.76 59.861 78.12 ;
     RECT  59.393 79.344 59.861 79.368 ;
     RECT  59.789 81.024 59.861 81.048 ;
     RECT  59.789 83.328 59.861 86.952 ;
     RECT  59.821 108.336 59.893 108.792 ;
     RECT  59.857 121.872 59.893 121.896 ;
     RECT  59.861 83.328 59.897 86.664 ;
     RECT  56.704 111.408 59.929 112.008 ;
     RECT  59.897 83.472 60.005 86.664 ;
     RECT  59.749 12.768 60.037 16.104 ;
     RECT  59.677 82.08 60.049 82.104 ;
     RECT  59.893 107.904 60.073 108.792 ;
     RECT  59.929 110.64 60.073 112.008 ;
     RECT  60.005 84.96 60.077 86.664 ;
     RECT  59.893 121.872 60.109 122.424 ;
     RECT  58.957 127.68 60.109 128.328 ;
     RECT  59.861 78.096 60.113 78.12 ;
     RECT  60.005 83.472 60.113 83.832 ;
     RECT  59.929 21.504 60.133 21.528 ;
     RECT  59.785 6.624 60.181 11.16 ;
     RECT  60.037 12.768 60.181 16.872 ;
     RECT  59.677 89.52 60.181 89.592 ;
     RECT  59.857 90.672 60.181 93 ;
     RECT  59.029 114.864 60.181 115.176 ;
     RECT  60.037 126.576 60.181 126.6 ;
     RECT  60.109 127.68 60.181 128.376 ;
     RECT  60.077 85.488 60.193 86.664 ;
     RECT  60.073 110.112 60.217 112.008 ;
     RECT  59.857 113.328 60.217 113.544 ;
     RECT  60.181 114.864 60.217 116.088 ;
     RECT  58.817 124.848 60.217 125.304 ;
     RECT  60.113 83.472 60.221 83.496 ;
     RECT  60.181 126.576 60.265 128.376 ;
     RECT  59.797 59.52 60.289 59.544 ;
     RECT  60.073 107.904 60.325 109.032 ;
     RECT  60.217 110.112 60.325 112.248 ;
     RECT  59.821 100.512 60.361 104.424 ;
     RECT  60.217 124.8 60.361 125.304 ;
     RECT  60.325 107.904 60.365 112.248 ;
     RECT  60.181 89.52 60.397 93 ;
     RECT  59.857 96.384 60.397 99.24 ;
     RECT  59.797 118.224 60.433 118.584 ;
     RECT  59.173 57.552 60.469 58.2 ;
     RECT  60.289 59.52 60.469 60.312 ;
     RECT  59.893 64.896 60.505 64.92 ;
     RECT  60.397 106.8 60.505 106.824 ;
     RECT  60.217 113.328 60.505 116.088 ;
     RECT  60.181 117.168 60.505 117.192 ;
     RECT  60.433 118.224 60.505 118.872 ;
     RECT  60.361 120.48 60.505 120.504 ;
     RECT  60.397 89.28 60.517 93 ;
     RECT  60.397 20.352 60.541 20.376 ;
     RECT  60.133 21.504 60.541 22.008 ;
     RECT  60.505 106.752 60.541 106.824 ;
     RECT  60.365 107.904 60.541 110.808 ;
     RECT  60.365 112.224 60.541 112.248 ;
     RECT  60.505 113.328 60.541 117.192 ;
     RECT  60.541 20.352 60.613 22.008 ;
     RECT  59.605 18.432 60.649 19.368 ;
     RECT  60.613 20.352 60.649 22.824 ;
     RECT  60.505 95.136 60.649 95.16 ;
     RECT  60.397 96.384 60.649 99.336 ;
     RECT  56.704 47.04 60.685 47.592 ;
     RECT  60.541 112.224 60.685 117.192 ;
     RECT  60.505 118.224 60.685 120.504 ;
     RECT  60.109 121.68 60.685 122.424 ;
     RECT  60.361 124.368 60.685 125.304 ;
     RECT  60.193 85.728 60.697 86.664 ;
     RECT  58.705 0.672 60.721 1.656 ;
     RECT  59.821 2.784 60.721 3.912 ;
     RECT  60.649 18.432 60.757 22.824 ;
     RECT  56.704 23.808 60.757 23.832 ;
     RECT  60.649 95.088 60.829 95.16 ;
     RECT  60.649 96.336 60.829 99.336 ;
     RECT  59.173 94.08 60.865 94.104 ;
     RECT  60.829 95.088 60.865 99.336 ;
     RECT  60.361 100.512 60.865 104.712 ;
     RECT  60.541 106.752 60.901 110.808 ;
     RECT  60.685 124.272 60.901 125.304 ;
     RECT  60.721 0.672 60.937 3.912 ;
     RECT  60.685 112.224 60.937 117.24 ;
     RECT  60.685 118.224 60.937 122.568 ;
     RECT  60.721 66.864 60.973 66.888 ;
     RECT  60.325 68.976 60.973 69 ;
     RECT  60.937 112.224 60.973 122.664 ;
     RECT  60.973 80.496 60.997 80.52 ;
     RECT  60.469 57.552 61.009 60.312 ;
     RECT  60.757 18.432 61.045 23.832 ;
     RECT  60.517 88.752 61.045 93 ;
     RECT  60.865 100.512 61.045 105.192 ;
     RECT  60.901 106.176 61.045 110.808 ;
     RECT  61.009 57.552 61.081 60.936 ;
     RECT  61.045 88.368 61.081 93.096 ;
     RECT  60.865 94.08 61.081 99.336 ;
     RECT  60.901 124.224 61.117 125.304 ;
     RECT  60.865 126.384 61.117 126.408 ;
     RECT  60.997 80.496 61.153 81 ;
     RECT  60.973 112.224 61.189 122.904 ;
     RECT  61.117 124.224 61.189 126.408 ;
     RECT  60.181 6.624 61.237 16.872 ;
     RECT  61.189 112.224 61.261 126.408 ;
     RECT  60.265 127.536 61.261 128.376 ;
     RECT  60.973 66.288 61.333 66.888 ;
     RECT  61.081 88.368 61.369 99.336 ;
     RECT  61.045 100.512 61.369 110.808 ;
     RECT  60.973 68.736 61.381 69 ;
     RECT  61.261 112.224 61.405 128.376 ;
     RECT  61.369 88.368 61.441 110.808 ;
     RECT  61.381 63.168 61.477 63.192 ;
     RECT  56.704 55.68 61.505 56.232 ;
     RECT  61.081 57.552 61.505 61.032 ;
     RECT  61.477 62.496 61.505 63.192 ;
     RECT  61.477 75.024 61.513 75.72 ;
     RECT  61.189 76.944 61.513 76.968 ;
     RECT  61.153 79.824 61.513 81 ;
     RECT  61.381 68.736 61.525 69.288 ;
     RECT  59.125 44.688 61.549 45.768 ;
     RECT  60.685 46.848 61.549 47.592 ;
     RECT  58.021 36.768 61.573 43.272 ;
     RECT  61.237 6.624 61.621 17.448 ;
     RECT  61.045 18.432 61.621 24.696 ;
     RECT  61.573 36.768 61.621 43.608 ;
     RECT  61.549 44.688 61.621 47.592 ;
     RECT  61.081 73.632 61.657 73.656 ;
     RECT  61.513 75.024 61.729 76.968 ;
     RECT  60.937 0.672 61.808 4.68 ;
     RECT  61.621 6.624 61.808 24.696 ;
     RECT  59.173 26.784 61.808 35.064 ;
     RECT  61.621 36.768 61.808 47.592 ;
     RECT  56.704 49.2 61.808 49.224 ;
     RECT  59.029 50.256 61.808 53.016 ;
     RECT  61.505 54.864 61.808 56.232 ;
     RECT  61.505 57.552 61.808 63.192 ;
     RECT  60.505 64.896 61.808 65.208 ;
     RECT  61.333 66.288 61.808 67.176 ;
     RECT  61.525 68.64 61.808 69.288 ;
     RECT  61.585 70.656 61.808 70.68 ;
     RECT  61.585 71.712 61.808 71.736 ;
     RECT  61.657 73.056 61.808 73.656 ;
     RECT  61.729 75.024 61.808 77.64 ;
     RECT  61.513 78.96 61.808 81 ;
     RECT  61.405 82.656 61.808 82.68 ;
     RECT  60.697 85.728 61.808 86.136 ;
     RECT  61.441 88.368 61.808 111.144 ;
     RECT  61.405 112.224 61.808 128.712 ;
     RECT  61.808 0.672 62.104 128.712 ;
     RECT  62.104 116.256 62.129 116.472 ;
     RECT  62.104 92.208 62.165 106.296 ;
     RECT  62.104 118.128 62.165 120.312 ;
     RECT  62.104 54.96 62.273 62.52 ;
     RECT  62.104 68.736 62.273 72.408 ;
     RECT  62.165 92.208 62.273 103.8 ;
     RECT  62.104 107.52 62.273 109.512 ;
     RECT  62.104 111.504 62.435 115.272 ;
     RECT  62.273 68.88 62.867 72.168 ;
     RECT  62.104 25.824 63.169 35.784 ;
     RECT  62.104 36.768 63.169 53.736 ;
     RECT  62.435 113.712 63.169 115.272 ;
     RECT  62.129 116.304 63.169 116.472 ;
     RECT  62.165 104.784 63.205 106.296 ;
     RECT  62.273 107.52 63.205 108.216 ;
     RECT  63.169 113.712 63.205 116.472 ;
     RECT  63.169 25.824 63.241 53.736 ;
     RECT  62.273 54.96 63.241 62.424 ;
     RECT  62.165 119.184 63.241 120.312 ;
     RECT  62.104 121.68 63.241 128.712 ;
     RECT  62.104 63.504 63.277 65.208 ;
     RECT  62.104 66.384 63.277 67.656 ;
     RECT  62.867 68.88 63.277 71.16 ;
     RECT  62.104 73.632 63.277 73.656 ;
     RECT  62.104 74.88 63.277 82.872 ;
     RECT  62.104 83.856 63.277 86.088 ;
     RECT  62.104 87.6 63.277 90.36 ;
     RECT  62.273 92.304 63.277 101.064 ;
     RECT  62.273 102.144 63.277 103.8 ;
     RECT  63.205 104.784 63.313 108.216 ;
     RECT  62.273 109.488 63.313 109.512 ;
     RECT  63.205 113.712 63.313 116.76 ;
     RECT  62.165 118.128 63.313 118.152 ;
     RECT  62.104 0.672 63.385 4.68 ;
     RECT  62.104 5.904 63.385 24.696 ;
     RECT  63.277 73.392 63.421 73.656 ;
     RECT  63.277 74.64 63.421 82.872 ;
     RECT  63.277 92.304 63.637 103.8 ;
     RECT  63.313 104.784 63.709 109.512 ;
     RECT  63.313 110.496 63.709 110.52 ;
     RECT  63.241 25.824 63.781 62.424 ;
     RECT  63.277 63.504 63.781 71.16 ;
     RECT  63.637 91.824 63.817 103.8 ;
     RECT  63.709 104.784 63.817 110.52 ;
     RECT  63.313 113.712 63.817 118.152 ;
     RECT  63.241 119.184 63.817 128.712 ;
     RECT  63.781 25.824 63.853 71.16 ;
     RECT  62.867 72.144 63.853 72.168 ;
     RECT  63.421 73.152 63.853 82.872 ;
     RECT  63.817 91.824 63.889 110.52 ;
     RECT  62.435 111.504 63.889 112.488 ;
     RECT  63.817 113.712 63.889 128.712 ;
     RECT  63.853 25.824 63.961 82.872 ;
     RECT  63.277 83.856 63.961 90.84 ;
     RECT  63.961 25.824 64.069 90.84 ;
     RECT  63.889 91.824 64.069 128.712 ;
     RECT  63.385 0.672 64.537 24.696 ;
     RECT  64.069 25.824 64.537 128.712 ;
     RECT  64.537 0.672 64.681 128.712 ;
     RECT  64.681 0.672 64.764 128.952 ;
     RECT  64.764 9.984 64.793 10.008 ;
     RECT  64.764 128.832 64.793 128.856 ;
    LAYER M5 ;
     RECT  40.32 0.016 49.896 0.131 ;
     RECT  40.32 0.131 49.464 0.179 ;
     RECT  47.136 0.179 49.464 0.323 ;
     RECT  41.712 0.179 45.816 0.851 ;
     RECT  29.856 0.085 29.88 2.137 ;
     RECT  40.32 0.179 40.344 2.137 ;
     RECT  45.792 0.851 45.816 2.137 ;
     RECT  2.4 2.137 2.52 2.151 ;
     RECT  7.8 2.137 7.92 2.151 ;
     RECT  13.2 2.137 13.32 2.151 ;
     RECT  18.6 2.137 18.72 2.151 ;
     RECT  24 2.137 24.12 2.151 ;
     RECT  34.8 2.137 34.92 2.151 ;
     RECT  40.2 2.137 40.344 2.151 ;
     RECT  45.6 2.137 45.816 2.151 ;
     RECT  51 2.137 51.12 2.151 ;
     RECT  56.4 2.137 56.52 2.151 ;
     RECT  61.8 2.137 61.92 2.151 ;
     RECT  0.576 3.109 0.6 3.637 ;
     RECT  0.576 3.637 1.416 4.357 ;
     RECT  0.144 4.357 1.416 6.133 ;
     RECT  2.4 2.151 2.712 6.133 ;
     RECT  64.272 8.101 64.296 8.149 ;
     RECT  63.84 8.149 64.296 8.291 ;
     RECT  61.8 2.151 62.112 8.869 ;
     RECT  56.4 2.151 56.712 9.109 ;
     RECT  61.8 8.869 62.232 9.349 ;
     RECT  0.144 6.133 2.712 10.117 ;
     RECT  0.144 10.117 3.576 12.853 ;
     RECT  61.68 9.349 62.232 14.101 ;
     RECT  64.272 14.581 64.296 14.629 ;
     RECT  63.84 14.629 64.296 14.771 ;
     RECT  59.712 18.757 59.736 19.237 ;
     RECT  63.84 21.493 63.864 21.541 ;
     RECT  63.84 21.541 64.296 21.683 ;
     RECT  59.712 19.237 60.024 21.973 ;
     RECT  59.712 21.973 60.168 22.549 ;
     RECT  61.2 14.101 62.232 22.549 ;
     RECT  59.712 22.549 62.232 26.533 ;
     RECT  59.712 26.533 63.096 28.309 ;
     RECT  56.4 9.109 57.192 28.549 ;
     RECT  58.56 27.301 58.584 28.549 ;
     RECT  59.712 28.309 63.816 30.373 ;
     RECT  59.616 30.373 63.816 30.421 ;
     RECT  56.4 28.549 58.584 30.565 ;
     RECT  59.616 30.421 64.296 30.565 ;
     RECT  56.4 30.565 64.296 31.045 ;
     RECT  56.4 31.045 64.488 32.005 ;
     RECT  56.4 32.005 64.68 50.533 ;
     RECT  55.824 50.533 64.68 51.157 ;
     RECT  7.8 2.151 8.112 62.533 ;
     RECT  7.68 62.533 8.112 62.725 ;
     RECT  47.136 0.323 48.552 63.205 ;
     RECT  7.392 62.725 8.112 63.779 ;
     RECT  47.136 63.205 49.416 63.827 ;
     RECT  7.488 63.779 8.112 64.357 ;
     RECT  7.488 64.357 8.52 64.931 ;
     RECT  7.68 64.931 8.52 64.933 ;
     RECT  7.68 64.933 9.144 65.027 ;
     RECT  6.336 64.885 6.36 65.603 ;
     RECT  7.68 65.027 8.112 66.037 ;
     RECT  9.12 65.027 9.144 66.037 ;
     RECT  7.68 66.037 9.144 67.141 ;
     RECT  10.656 66.613 10.68 67.237 ;
     RECT  0.144 12.853 4.008 67.331 ;
     RECT  7.44 67.141 9.144 68.531 ;
     RECT  7.44 68.531 9.096 68.627 ;
     RECT  10.656 67.237 11.304 68.915 ;
     RECT  11.28 68.915 11.304 69.251 ;
     RECT  41.712 0.851 44.424 70.067 ;
     RECT  7.68 68.627 9.096 70.645 ;
     RECT  7.536 70.645 9.096 70.739 ;
     RECT  13.2 2.151 13.512 70.789 ;
     RECT  7.536 70.739 8.52 70.835 ;
     RECT  7.536 70.835 8.112 71.651 ;
     RECT  12.384 70.789 13.512 74.581 ;
     RECT  10.8 73.381 10.824 74.723 ;
     RECT  11.904 74.581 13.512 74.723 ;
     RECT  42.624 70.067 44.424 75.203 ;
     RECT  7.632 71.651 8.112 75.781 ;
     RECT  0.192 67.331 4.008 75.829 ;
     RECT  5.328 75.781 5.352 75.829 ;
     RECT  0.192 75.829 5.352 77.461 ;
     RECT  6.336 73.477 6.36 77.461 ;
     RECT  0.192 77.461 6.36 77.555 ;
     RECT  55.248 51.157 64.68 78.035 ;
     RECT  12.384 74.723 13.512 78.181 ;
     RECT  14.832 77.797 14.856 78.613 ;
     RECT  7.632 75.781 8.328 79.189 ;
     RECT  12.192 78.181 13.512 79.189 ;
     RECT  14.832 78.613 15.624 79.189 ;
     RECT  11.28 79.189 15.624 79.235 ;
     RECT  4.848 77.555 6.36 79.237 ;
     RECT  7.632 79.189 8.808 79.237 ;
     RECT  0.192 77.555 3.864 79.283 ;
     RECT  12.384 79.235 15.624 79.283 ;
     RECT  10.272 79.477 10.296 79.765 ;
     RECT  11.28 79.235 11.304 79.765 ;
     RECT  15.6 79.283 15.624 79.811 ;
     RECT  12.384 79.283 14.232 79.859 ;
     RECT  12.384 79.859 13.512 80.243 ;
     RECT  17.52 79.189 17.544 80.245 ;
     RECT  10.272 79.765 11.304 80.341 ;
     RECT  17.472 80.245 17.544 81.347 ;
     RECT  4.848 79.237 8.808 81.445 ;
     RECT  9.792 80.341 11.304 81.445 ;
     RECT  1.392 79.283 3.864 82.069 ;
     RECT  4.848 81.445 11.304 82.069 ;
     RECT  13.2 80.243 13.512 82.117 ;
     RECT  13.2 82.117 14.28 82.165 ;
     RECT  43.488 75.203 44.424 82.499 ;
     RECT  18.6 2.151 18.912 82.693 ;
     RECT  17.472 81.347 17.496 83.221 ;
     RECT  18.48 82.693 18.912 83.557 ;
     RECT  18.48 83.557 19.704 83.939 ;
     RECT  13.2 82.165 14.76 84.277 ;
     RECT  1.392 82.069 11.304 84.325 ;
     RECT  18.6 83.939 19.704 84.371 ;
     RECT  16.128 80.293 16.152 84.373 ;
     RECT  0.192 79.283 0.216 84.419 ;
     RECT  16.128 84.373 16.296 84.757 ;
     RECT  15.984 84.757 16.296 84.901 ;
     RECT  17.424 83.221 17.496 84.901 ;
     RECT  21.072 84.181 21.096 84.995 ;
     RECT  15.984 84.901 17.496 85.237 ;
     RECT  18.6 84.371 18.912 85.237 ;
     RECT  15.984 85.237 18.912 85.523 ;
     RECT  22.752 85.141 22.776 85.907 ;
     RECT  24 2.151 24.312 86.581 ;
     RECT  21.408 85.957 21.432 86.675 ;
     RECT  16.128 85.523 17.496 86.771 ;
     RECT  24 86.581 24.888 87.347 ;
     RECT  32.256 61.909 32.28 87.589 ;
     RECT  1.392 84.325 11.784 87.637 ;
     RECT  12.768 84.277 14.76 87.637 ;
     RECT  27.36 87.157 27.384 87.685 ;
     RECT  24 87.347 24.504 87.731 ;
     RECT  18.48 85.523 18.912 87.781 ;
     RECT  26.448 87.685 27.384 87.827 ;
     RECT  55.248 78.035 64.632 88.213 ;
     RECT  18.192 87.781 18.912 88.309 ;
     RECT  55.248 88.213 64.68 88.355 ;
     RECT  44.4 82.499 44.424 88.403 ;
     RECT  31.392 87.589 32.28 88.741 ;
     RECT  16.128 86.771 16.728 88.787 ;
     RECT  24 87.731 24.456 89.363 ;
     RECT  55.248 88.355 64.632 89.507 ;
     RECT  21.168 89.125 21.192 89.509 ;
     RECT  24 89.363 24.312 89.989 ;
     RECT  21.168 89.509 22.152 90.421 ;
     RECT  23.424 89.989 24.312 90.421 ;
     RECT  26.448 87.827 26.472 90.469 ;
     RECT  16.272 88.787 16.728 90.565 ;
     RECT  17.712 88.309 18.912 90.565 ;
     RECT  26.448 90.469 26.808 90.611 ;
     RECT  21.168 90.421 24.312 90.659 ;
     RECT  26.448 90.611 26.472 90.659 ;
     RECT  29.4 2.137 29.88 91.429 ;
     RECT  21.168 90.659 22.68 91.717 ;
     RECT  24 90.659 24.312 91.717 ;
     RECT  28.416 91.429 29.88 92.099 ;
     RECT  29.4 92.099 29.88 92.963 ;
     RECT  27.84 92.917 27.864 94.019 ;
     RECT  31.392 88.741 32.712 94.307 ;
     RECT  34.8 2.151 35.112 94.981 ;
     RECT  32.544 94.307 32.712 95.219 ;
     RECT  33.84 94.981 35.112 95.459 ;
     RECT  29.4 92.963 29.712 96.613 ;
     RECT  31.392 94.307 31.416 96.613 ;
     RECT  27.072 94.069 27.576 98.581 ;
     RECT  55.248 89.507 63.768 98.963 ;
     RECT  27.072 98.581 28.104 99.157 ;
     RECT  29.4 96.613 31.416 99.157 ;
     RECT  27.072 99.157 31.416 100.259 ;
     RECT  38.448 95.413 38.472 100.261 ;
     RECT  37.584 100.261 38.472 100.355 ;
     RECT  32.688 95.219 32.712 100.931 ;
     RECT  45.6 2.151 45.912 101.077 ;
     RECT  47.136 63.827 48.552 101.077 ;
     RECT  55.248 98.963 58.008 101.123 ;
     RECT  34.8 95.459 35.112 101.605 ;
     RECT  40.2 2.151 40.512 101.845 ;
     RECT  59.04 98.963 63.768 102.083 ;
     RECT  31.392 100.259 31.416 102.179 ;
     RECT  33.024 101.989 33.048 102.565 ;
     RECT  34.464 101.605 35.112 102.565 ;
     RECT  37.584 100.355 37.608 102.565 ;
     RECT  39.936 101.845 40.512 103.475 ;
     RECT  37.248 102.565 38.04 104.867 ;
     RECT  37.248 104.867 37.464 105.875 ;
     RECT  45.6 101.077 48.552 105.877 ;
     RECT  45.216 105.877 48.552 106.499 ;
     RECT  40.2 103.475 40.512 106.885 ;
     RECT  40.2 106.885 41.016 108.227 ;
     RECT  59.04 102.083 63.72 108.323 ;
     RECT  43.104 105.781 43.128 108.371 ;
     RECT  38.928 109.957 38.952 110.533 ;
     RECT  40.2 108.227 40.512 110.533 ;
     RECT  55.248 101.123 57.528 111.443 ;
     RECT  48.048 106.499 48.552 111.923 ;
     RECT  45.216 106.499 46.632 112.115 ;
     RECT  51 2.151 51.312 112.213 ;
     RECT  38.928 110.533 40.512 112.885 ;
     RECT  48.48 111.923 48.552 113.171 ;
     RECT  43.248 109.861 43.272 113.413 ;
     RECT  45.216 112.115 45.912 113.749 ;
     RECT  45.216 113.749 46.152 114.035 ;
     RECT  51 112.213 51.72 114.517 ;
     RECT  45.504 114.035 46.152 114.803 ;
     RECT  55.824 111.443 57.528 114.899 ;
     RECT  59.04 108.323 59.832 115.187 ;
     RECT  38.928 112.885 41.448 115.717 ;
     RECT  48.528 113.171 48.552 116.197 ;
     RECT  45.504 114.803 45.912 116.293 ;
     RECT  38.928 115.717 41.88 116.579 ;
     RECT  47.904 116.197 48.552 117.011 ;
     RECT  60.864 108.323 63.72 117.013 ;
     RECT  60.816 117.013 63.72 117.155 ;
     RECT  50.064 114.517 51.72 117.251 ;
     RECT  56.4 114.899 57.528 118.259 ;
     RECT  48.528 117.011 48.552 118.595 ;
     RECT  59.808 115.187 59.832 118.595 ;
     RECT  52.848 117.925 52.872 120.227 ;
     RECT  60.864 117.155 63.72 120.323 ;
     RECT  54.624 119.893 54.648 120.805 ;
     RECT  60.864 120.323 62.112 120.899 ;
     RECT  54.576 120.805 54.648 120.997 ;
     RECT  51 117.251 51.72 121.475 ;
     RECT  45.504 116.293 46.344 121.573 ;
     RECT  54.576 120.997 55.224 121.667 ;
     RECT  43.248 113.413 43.896 121.669 ;
     RECT  45.504 121.573 46.392 121.669 ;
     RECT  43.248 121.669 44.04 121.715 ;
     RECT  45.024 121.669 46.392 121.859 ;
     RECT  61.344 120.899 62.112 122.051 ;
     RECT  45.504 121.859 46.392 122.147 ;
     RECT  54.576 121.667 54.648 122.147 ;
     RECT  54.576 122.147 54.6 122.485 ;
     RECT  37.44 105.875 37.464 122.533 ;
     RECT  1.392 87.637 14.76 122.965 ;
     RECT  0.768 122.965 14.76 123.107 ;
     RECT  43.872 121.715 44.04 123.107 ;
     RECT  54.48 122.485 54.6 123.109 ;
     RECT  54.48 123.109 55.272 123.251 ;
     RECT  21.168 91.717 24.312 123.349 ;
     RECT  25.584 95.701 25.608 123.349 ;
     RECT  16.272 90.565 18.912 123.637 ;
     RECT  21.168 123.349 25.608 123.731 ;
     RECT  63.6 120.323 63.72 123.779 ;
     RECT  63.696 123.779 63.72 123.827 ;
     RECT  45.6 122.147 46.392 124.547 ;
     RECT  25.488 123.731 25.608 124.643 ;
     RECT  43.872 123.107 43.944 124.837 ;
     RECT  61.8 122.051 62.112 124.837 ;
     RECT  36.48 122.533 37.464 125.365 ;
     RECT  38.928 116.579 41.448 125.365 ;
     RECT  55.248 123.251 55.272 125.413 ;
     RECT  56.4 118.259 56.712 125.413 ;
     RECT  45.6 124.547 46.344 125.653 ;
     RECT  16.272 123.637 19.176 125.941 ;
     RECT  20.16 89.461 20.184 125.941 ;
     RECT  25.584 124.643 25.608 125.989 ;
     RECT  27.072 100.259 29.712 125.989 ;
     RECT  45.36 125.653 46.344 125.989 ;
     RECT  47.808 121.765 47.832 125.989 ;
     RECT  61.632 124.837 62.112 126.467 ;
     RECT  25.584 125.989 30.072 126.469 ;
     RECT  31.536 103.141 31.56 126.469 ;
     RECT  33.024 102.565 35.112 126.469 ;
     RECT  31.536 126.469 35.112 126.565 ;
     RECT  36.48 125.365 41.448 126.565 ;
     RECT  63.648 125.989 63.672 126.565 ;
     RECT  31.536 126.565 41.448 127.045 ;
     RECT  42.864 123.061 42.888 127.045 ;
     RECT  51 121.475 51.312 127.045 ;
     RECT  54.24 123.685 54.264 127.045 ;
     RECT  55.248 125.413 56.712 127.045 ;
     RECT  54.24 127.045 56.712 127.449 ;
     RECT  21.168 123.731 24.312 127.463 ;
     RECT  25.584 126.469 30.552 127.463 ;
     RECT  50.784 127.045 51.312 127.463 ;
     RECT  54.24 127.449 56.52 127.463 ;
     RECT  61.8 126.467 62.112 127.525 ;
     RECT  16.272 125.941 20.184 127.621 ;
     RECT  21.168 127.463 23.64 127.621 ;
     RECT  25.584 127.463 29.064 127.669 ;
     RECT  58.704 127.621 58.728 127.669 ;
     RECT  60.192 127.045 60.216 127.669 ;
     RECT  16.272 127.621 23.64 127.715 ;
     RECT  1.392 123.107 14.76 127.763 ;
     RECT  61.8 127.525 62.184 127.765 ;
     RECT  63.648 126.565 64.152 127.765 ;
     RECT  30.048 127.463 30.552 128.197 ;
     RECT  31.536 127.045 42.888 128.197 ;
     RECT  50.784 127.463 50.808 128.197 ;
     RECT  54.24 127.463 56.232 128.197 ;
     RECT  58.176 127.669 60.696 128.197 ;
     RECT  43.872 124.837 44.376 128.245 ;
     RECT  45.36 125.989 47.832 128.245 ;
     RECT  53.76 128.197 56.232 128.245 ;
     RECT  57.696 128.197 60.696 128.245 ;
     RECT  61.8 127.765 64.152 128.245 ;
     RECT  3.84 127.763 14.76 128.773 ;
     RECT  53.28 128.245 56.232 128.773 ;
     RECT  57.696 128.245 64.152 128.773 ;
     RECT  24.624 127.669 29.064 128.821 ;
     RECT  30.048 128.197 42.888 128.821 ;
     RECT  49.296 128.197 49.32 128.821 ;
     RECT  50.304 128.197 50.808 128.821 ;
     RECT  51.792 127.669 51.816 128.821 ;
     RECT  53.28 128.773 64.152 128.821 ;
     RECT  1.392 127.763 2.328 129.445 ;
     RECT  3.84 128.773 15.72 129.445 ;
     RECT  16.704 127.715 23.64 129.445 ;
     RECT  24.624 128.821 42.888 129.445 ;
     RECT  43.872 128.245 47.832 129.445 ;
     RECT  48.816 128.821 49.32 129.445 ;
     RECT  50.304 128.821 64.152 129.445 ;
     RECT  0.912 129.445 64.152 129.552 ;
  END
END qfd_c_land_r258_narrow
END LIBRARY
